VERSION 5.8 ;
BUSBITCHARS "[]" ;
DIVIDERCHAR "/" ;
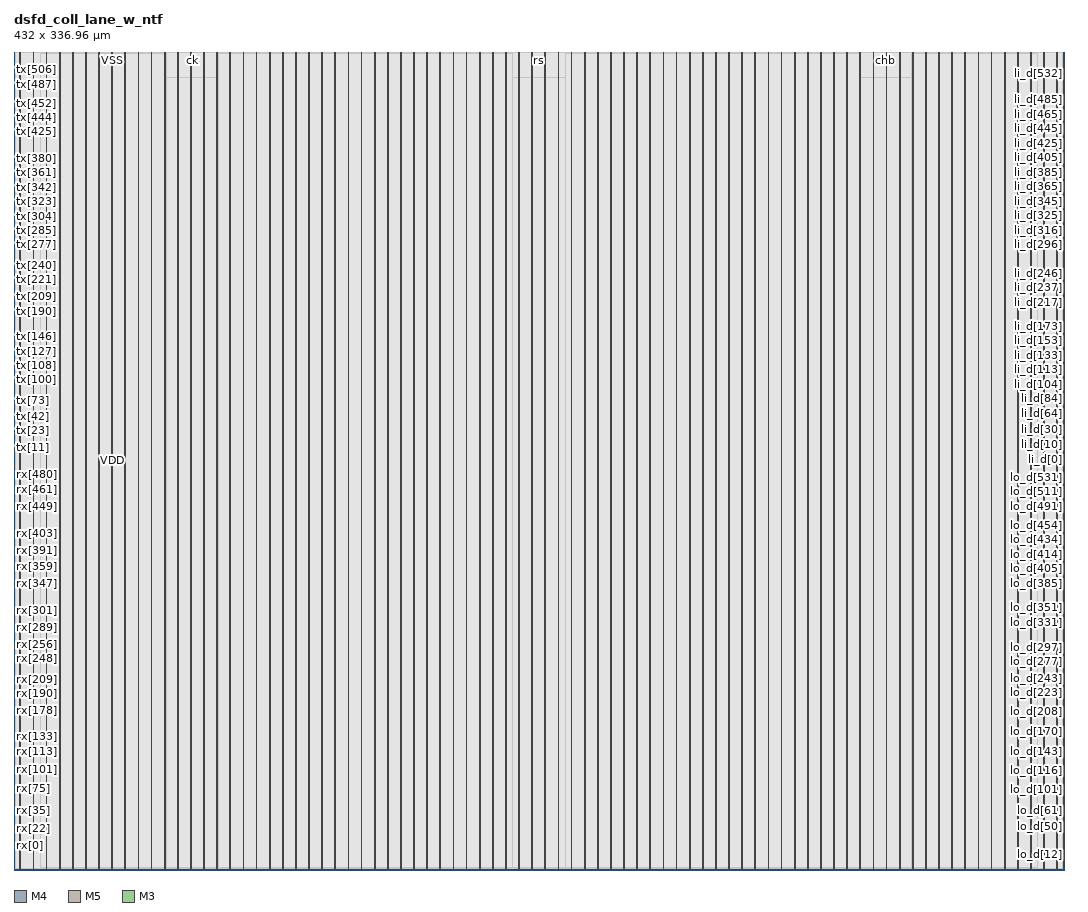
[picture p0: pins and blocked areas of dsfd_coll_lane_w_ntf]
MACRO dsfd_coll_lane_w_ntf
  CLASS BLOCK ;
  ORIGIN 0 0 ;
  FOREIGN dsfd_coll_lane_w_ntf 0 0 ;
  SIZE 432.0 BY 336.96 ;
  SYMMETRY X Y ;
  PIN rx[0]
    DIRECTION INPUT ;
    USE SIGNAL ;
    PORT
      LAYER M4 ;
        RECT 0.000 10.128 0.192 10.152 ;
    END
  END rx[0]
  PIN rx[1]
    DIRECTION INPUT ;
    USE SIGNAL ;
    PORT
      LAYER M4 ;
        RECT 0.000 10.464 0.192 10.488 ;
    END
  END rx[1]
  PIN rx[2]
    DIRECTION INPUT ;
    USE SIGNAL ;
    PORT
      LAYER M4 ;
        RECT 0.000 10.752 0.192 10.776 ;
    END
  END rx[2]
  PIN rx[3]
    DIRECTION INPUT ;
    USE SIGNAL ;
    PORT
      LAYER M4 ;
        RECT 0.000 11.088 0.192 11.112 ;
    END
  END rx[3]
  PIN rx[4]
    DIRECTION INPUT ;
    USE SIGNAL ;
    PORT
      LAYER M4 ;
        RECT 0.000 11.376 0.192 11.400 ;
    END
  END rx[4]
  PIN rx[5]
    DIRECTION INPUT ;
    USE SIGNAL ;
    PORT
      LAYER M4 ;
        RECT 0.000 11.712 0.192 11.736 ;
    END
  END rx[5]
  PIN rx[6]
    DIRECTION INPUT ;
    USE SIGNAL ;
    PORT
      LAYER M4 ;
        RECT 0.000 12.000 0.192 12.024 ;
    END
  END rx[6]
  PIN rx[7]
    DIRECTION INPUT ;
    USE SIGNAL ;
    PORT
      LAYER M4 ;
        RECT 0.000 12.336 0.192 12.360 ;
    END
  END rx[7]
  PIN rx[8]
    DIRECTION INPUT ;
    USE SIGNAL ;
    PORT
      LAYER M4 ;
        RECT 0.000 12.624 0.192 12.648 ;
    END
  END rx[8]
  PIN rx[9]
    DIRECTION INPUT ;
    USE SIGNAL ;
    PORT
      LAYER M4 ;
        RECT 0.000 12.960 0.192 12.984 ;
    END
  END rx[9]
  PIN rx[10]
    DIRECTION INPUT ;
    USE SIGNAL ;
    PORT
      LAYER M4 ;
        RECT 0.000 13.248 0.192 13.272 ;
    END
  END rx[10]
  PIN rx[11]
    DIRECTION INPUT ;
    USE SIGNAL ;
    PORT
      LAYER M4 ;
        RECT 0.000 13.584 0.192 13.608 ;
    END
  END rx[11]
  PIN rx[12]
    DIRECTION INPUT ;
    USE SIGNAL ;
    PORT
      LAYER M4 ;
        RECT 0.000 13.872 0.192 13.896 ;
    END
  END rx[12]
  PIN rx[13]
    DIRECTION INPUT ;
    USE SIGNAL ;
    PORT
      LAYER M4 ;
        RECT 0.000 14.160 0.192 14.184 ;
    END
  END rx[13]
  PIN rx[14]
    DIRECTION INPUT ;
    USE SIGNAL ;
    PORT
      LAYER M4 ;
        RECT 0.000 14.496 0.192 14.520 ;
    END
  END rx[14]
  PIN rx[15]
    DIRECTION INPUT ;
    USE SIGNAL ;
    PORT
      LAYER M4 ;
        RECT 0.000 14.784 0.192 14.808 ;
    END
  END rx[15]
  PIN rx[16]
    DIRECTION INPUT ;
    USE SIGNAL ;
    PORT
      LAYER M4 ;
        RECT 0.000 15.120 0.192 15.144 ;
    END
  END rx[16]
  PIN rx[17]
    DIRECTION INPUT ;
    USE SIGNAL ;
    PORT
      LAYER M4 ;
        RECT 0.000 15.408 0.192 15.432 ;
    END
  END rx[17]
  PIN rx[18]
    DIRECTION INPUT ;
    USE SIGNAL ;
    PORT
      LAYER M4 ;
        RECT 0.000 15.744 0.192 15.768 ;
    END
  END rx[18]
  PIN rx[19]
    DIRECTION INPUT ;
    USE SIGNAL ;
    PORT
      LAYER M4 ;
        RECT 0.000 16.032 0.192 16.056 ;
    END
  END rx[19]
  PIN rx[20]
    DIRECTION INPUT ;
    USE SIGNAL ;
    PORT
      LAYER M4 ;
        RECT 0.000 16.368 0.192 16.392 ;
    END
  END rx[20]
  PIN rx[21]
    DIRECTION INPUT ;
    USE SIGNAL ;
    PORT
      LAYER M4 ;
        RECT 0.000 16.656 0.192 16.680 ;
    END
  END rx[21]
  PIN rx[22]
    DIRECTION INPUT ;
    USE SIGNAL ;
    PORT
      LAYER M4 ;
        RECT 0.000 16.992 0.192 17.016 ;
    END
  END rx[22]
  PIN rx[23]
    DIRECTION INPUT ;
    USE SIGNAL ;
    PORT
      LAYER M4 ;
        RECT 0.000 17.280 0.192 17.304 ;
    END
  END rx[23]
  PIN rx[24]
    DIRECTION INPUT ;
    USE SIGNAL ;
    PORT
      LAYER M4 ;
        RECT 0.000 17.616 0.192 17.640 ;
    END
  END rx[24]
  PIN rx[25]
    DIRECTION INPUT ;
    USE SIGNAL ;
    PORT
      LAYER M4 ;
        RECT 0.000 17.904 0.192 17.928 ;
    END
  END rx[25]
  PIN rx[26]
    DIRECTION INPUT ;
    USE SIGNAL ;
    PORT
      LAYER M4 ;
        RECT 0.000 18.240 0.192 18.264 ;
    END
  END rx[26]
  PIN rx[27]
    DIRECTION INPUT ;
    USE SIGNAL ;
    PORT
      LAYER M4 ;
        RECT 0.000 18.528 0.192 18.552 ;
    END
  END rx[27]
  PIN rx[28]
    DIRECTION INPUT ;
    USE SIGNAL ;
    PORT
      LAYER M4 ;
        RECT 0.000 18.864 0.192 18.888 ;
    END
  END rx[28]
  PIN rx[29]
    DIRECTION INPUT ;
    USE SIGNAL ;
    PORT
      LAYER M4 ;
        RECT 0.000 19.152 0.192 19.176 ;
    END
  END rx[29]
  PIN rx[30]
    DIRECTION INPUT ;
    USE SIGNAL ;
    PORT
      LAYER M4 ;
        RECT 0.000 19.440 0.192 19.464 ;
    END
  END rx[30]
  PIN rx[31]
    DIRECTION INPUT ;
    USE SIGNAL ;
    PORT
      LAYER M4 ;
        RECT 0.000 19.776 0.192 19.800 ;
    END
  END rx[31]
  PIN rx[32]
    DIRECTION INPUT ;
    USE SIGNAL ;
    PORT
      LAYER M4 ;
        RECT 0.000 20.064 0.192 20.088 ;
    END
  END rx[32]
  PIN rx[33]
    DIRECTION INPUT ;
    USE SIGNAL ;
    PORT
      LAYER M4 ;
        RECT 0.000 20.400 0.192 20.424 ;
    END
  END rx[33]
  PIN rx[34]
    DIRECTION INPUT ;
    USE SIGNAL ;
    PORT
      LAYER M4 ;
        RECT 0.000 20.688 0.192 20.712 ;
    END
  END rx[34]
  PIN rx[35]
    DIRECTION INPUT ;
    USE SIGNAL ;
    PORT
      LAYER M4 ;
        RECT 0.000 21.024 0.192 21.048 ;
    END
  END rx[35]
  PIN rx[36]
    DIRECTION INPUT ;
    USE SIGNAL ;
    PORT
      LAYER M4 ;
        RECT 0.000 21.312 0.192 21.336 ;
    END
  END rx[36]
  PIN rx[37]
    DIRECTION INPUT ;
    USE SIGNAL ;
    PORT
      LAYER M4 ;
        RECT 0.000 21.648 0.192 21.672 ;
    END
  END rx[37]
  PIN rx[38]
    DIRECTION INPUT ;
    USE SIGNAL ;
    PORT
      LAYER M4 ;
        RECT 0.000 21.936 0.192 21.960 ;
    END
  END rx[38]
  PIN rx[39]
    DIRECTION INPUT ;
    USE SIGNAL ;
    PORT
      LAYER M4 ;
        RECT 0.000 22.272 0.192 22.296 ;
    END
  END rx[39]
  PIN rx[40]
    DIRECTION INPUT ;
    USE SIGNAL ;
    PORT
      LAYER M4 ;
        RECT 0.000 22.560 0.192 22.584 ;
    END
  END rx[40]
  PIN rx[41]
    DIRECTION INPUT ;
    USE SIGNAL ;
    PORT
      LAYER M4 ;
        RECT 0.000 22.896 0.192 22.920 ;
    END
  END rx[41]
  PIN rx[42]
    DIRECTION INPUT ;
    USE SIGNAL ;
    PORT
      LAYER M4 ;
        RECT 0.000 23.184 0.192 23.208 ;
    END
  END rx[42]
  PIN rx[43]
    DIRECTION INPUT ;
    USE SIGNAL ;
    PORT
      LAYER M4 ;
        RECT 0.000 23.520 0.192 23.544 ;
    END
  END rx[43]
  PIN rx[44]
    DIRECTION INPUT ;
    USE SIGNAL ;
    PORT
      LAYER M4 ;
        RECT 0.000 23.808 0.192 23.832 ;
    END
  END rx[44]
  PIN rx[45]
    DIRECTION INPUT ;
    USE SIGNAL ;
    PORT
      LAYER M4 ;
        RECT 0.000 24.144 0.192 24.168 ;
    END
  END rx[45]
  PIN rx[46]
    DIRECTION INPUT ;
    USE SIGNAL ;
    PORT
      LAYER M4 ;
        RECT 0.000 24.432 0.192 24.456 ;
    END
  END rx[46]
  PIN rx[47]
    DIRECTION INPUT ;
    USE SIGNAL ;
    PORT
      LAYER M4 ;
        RECT 0.000 24.768 0.192 24.792 ;
    END
  END rx[47]
  PIN rx[48]
    DIRECTION INPUT ;
    USE SIGNAL ;
    PORT
      LAYER M4 ;
        RECT 0.000 25.056 0.192 25.080 ;
    END
  END rx[48]
  PIN rx[49]
    DIRECTION INPUT ;
    USE SIGNAL ;
    PORT
      LAYER M4 ;
        RECT 0.000 25.344 0.192 25.368 ;
    END
  END rx[49]
  PIN rx[50]
    DIRECTION INPUT ;
    USE SIGNAL ;
    PORT
      LAYER M4 ;
        RECT 0.000 25.680 0.192 25.704 ;
    END
  END rx[50]
  PIN rx[51]
    DIRECTION INPUT ;
    USE SIGNAL ;
    PORT
      LAYER M4 ;
        RECT 0.000 25.968 0.192 25.992 ;
    END
  END rx[51]
  PIN rx[52]
    DIRECTION INPUT ;
    USE SIGNAL ;
    PORT
      LAYER M4 ;
        RECT 0.000 26.304 0.192 26.328 ;
    END
  END rx[52]
  PIN rx[53]
    DIRECTION INPUT ;
    USE SIGNAL ;
    PORT
      LAYER M4 ;
        RECT 0.000 26.592 0.192 26.616 ;
    END
  END rx[53]
  PIN rx[54]
    DIRECTION INPUT ;
    USE SIGNAL ;
    PORT
      LAYER M4 ;
        RECT 0.000 26.928 0.192 26.952 ;
    END
  END rx[54]
  PIN rx[55]
    DIRECTION INPUT ;
    USE SIGNAL ;
    PORT
      LAYER M4 ;
        RECT 0.000 27.216 0.192 27.240 ;
    END
  END rx[55]
  PIN rx[56]
    DIRECTION INPUT ;
    USE SIGNAL ;
    PORT
      LAYER M4 ;
        RECT 0.000 27.552 0.192 27.576 ;
    END
  END rx[56]
  PIN rx[57]
    DIRECTION INPUT ;
    USE SIGNAL ;
    PORT
      LAYER M4 ;
        RECT 0.000 27.840 0.192 27.864 ;
    END
  END rx[57]
  PIN rx[58]
    DIRECTION INPUT ;
    USE SIGNAL ;
    PORT
      LAYER M4 ;
        RECT 0.000 28.176 0.192 28.200 ;
    END
  END rx[58]
  PIN rx[59]
    DIRECTION INPUT ;
    USE SIGNAL ;
    PORT
      LAYER M4 ;
        RECT 0.000 28.464 0.192 28.488 ;
    END
  END rx[59]
  PIN rx[60]
    DIRECTION INPUT ;
    USE SIGNAL ;
    PORT
      LAYER M4 ;
        RECT 0.000 28.800 0.192 28.824 ;
    END
  END rx[60]
  PIN rx[61]
    DIRECTION INPUT ;
    USE SIGNAL ;
    PORT
      LAYER M4 ;
        RECT 0.000 29.088 0.192 29.112 ;
    END
  END rx[61]
  PIN rx[62]
    DIRECTION INPUT ;
    USE SIGNAL ;
    PORT
      LAYER M4 ;
        RECT 0.000 29.424 0.192 29.448 ;
    END
  END rx[62]
  PIN rx[63]
    DIRECTION INPUT ;
    USE SIGNAL ;
    PORT
      LAYER M4 ;
        RECT 0.000 29.712 0.192 29.736 ;
    END
  END rx[63]
  PIN rx[64]
    DIRECTION INPUT ;
    USE SIGNAL ;
    PORT
      LAYER M4 ;
        RECT 0.000 30.048 0.192 30.072 ;
    END
  END rx[64]
  PIN rx[65]
    DIRECTION INPUT ;
    USE SIGNAL ;
    PORT
      LAYER M4 ;
        RECT 0.000 30.336 0.192 30.360 ;
    END
  END rx[65]
  PIN rx[66]
    DIRECTION INPUT ;
    USE SIGNAL ;
    PORT
      LAYER M4 ;
        RECT 0.000 30.672 0.192 30.696 ;
    END
  END rx[66]
  PIN rx[67]
    DIRECTION INPUT ;
    USE SIGNAL ;
    PORT
      LAYER M4 ;
        RECT 0.000 30.960 0.192 30.984 ;
    END
  END rx[67]
  PIN rx[68]
    DIRECTION INPUT ;
    USE SIGNAL ;
    PORT
      LAYER M4 ;
        RECT 0.000 31.248 0.192 31.272 ;
    END
  END rx[68]
  PIN rx[69]
    DIRECTION INPUT ;
    USE SIGNAL ;
    PORT
      LAYER M4 ;
        RECT 0.000 31.584 0.192 31.608 ;
    END
  END rx[69]
  PIN rx[70]
    DIRECTION INPUT ;
    USE SIGNAL ;
    PORT
      LAYER M4 ;
        RECT 0.000 31.872 0.192 31.896 ;
    END
  END rx[70]
  PIN rx[71]
    DIRECTION INPUT ;
    USE SIGNAL ;
    PORT
      LAYER M4 ;
        RECT 0.000 32.208 0.192 32.232 ;
    END
  END rx[71]
  PIN rx[72]
    DIRECTION INPUT ;
    USE SIGNAL ;
    PORT
      LAYER M4 ;
        RECT 0.000 32.496 0.192 32.520 ;
    END
  END rx[72]
  PIN rx[73]
    DIRECTION INPUT ;
    USE SIGNAL ;
    PORT
      LAYER M4 ;
        RECT 0.000 32.832 0.192 32.856 ;
    END
  END rx[73]
  PIN rx[74]
    DIRECTION INPUT ;
    USE SIGNAL ;
    PORT
      LAYER M4 ;
        RECT 0.000 33.120 0.192 33.144 ;
    END
  END rx[74]
  PIN rx[75]
    DIRECTION INPUT ;
    USE SIGNAL ;
    PORT
      LAYER M4 ;
        RECT 0.000 33.456 0.192 33.480 ;
    END
  END rx[75]
  PIN rx[76]
    DIRECTION INPUT ;
    USE SIGNAL ;
    PORT
      LAYER M4 ;
        RECT 0.000 33.744 0.192 33.768 ;
    END
  END rx[76]
  PIN rx[77]
    DIRECTION INPUT ;
    USE SIGNAL ;
    PORT
      LAYER M4 ;
        RECT 0.000 34.080 0.192 34.104 ;
    END
  END rx[77]
  PIN rx[78]
    DIRECTION INPUT ;
    USE SIGNAL ;
    PORT
      LAYER M4 ;
        RECT 0.000 34.368 0.192 34.392 ;
    END
  END rx[78]
  PIN rx[79]
    DIRECTION INPUT ;
    USE SIGNAL ;
    PORT
      LAYER M4 ;
        RECT 0.000 34.704 0.192 34.728 ;
    END
  END rx[79]
  PIN rx[80]
    DIRECTION INPUT ;
    USE SIGNAL ;
    PORT
      LAYER M4 ;
        RECT 0.000 34.992 0.192 35.016 ;
    END
  END rx[80]
  PIN rx[81]
    DIRECTION INPUT ;
    USE SIGNAL ;
    PORT
      LAYER M4 ;
        RECT 0.000 35.328 0.192 35.352 ;
    END
  END rx[81]
  PIN rx[82]
    DIRECTION INPUT ;
    USE SIGNAL ;
    PORT
      LAYER M4 ;
        RECT 0.000 35.616 0.192 35.640 ;
    END
  END rx[82]
  PIN rx[83]
    DIRECTION INPUT ;
    USE SIGNAL ;
    PORT
      LAYER M4 ;
        RECT 0.000 35.952 0.192 35.976 ;
    END
  END rx[83]
  PIN rx[84]
    DIRECTION INPUT ;
    USE SIGNAL ;
    PORT
      LAYER M4 ;
        RECT 0.000 36.240 0.192 36.264 ;
    END
  END rx[84]
  PIN rx[85]
    DIRECTION INPUT ;
    USE SIGNAL ;
    PORT
      LAYER M4 ;
        RECT 0.000 36.528 0.192 36.552 ;
    END
  END rx[85]
  PIN rx[86]
    DIRECTION INPUT ;
    USE SIGNAL ;
    PORT
      LAYER M4 ;
        RECT 0.000 36.864 0.192 36.888 ;
    END
  END rx[86]
  PIN rx[87]
    DIRECTION INPUT ;
    USE SIGNAL ;
    PORT
      LAYER M4 ;
        RECT 0.000 37.152 0.192 37.176 ;
    END
  END rx[87]
  PIN rx[88]
    DIRECTION INPUT ;
    USE SIGNAL ;
    PORT
      LAYER M4 ;
        RECT 0.000 37.488 0.192 37.512 ;
    END
  END rx[88]
  PIN rx[89]
    DIRECTION INPUT ;
    USE SIGNAL ;
    PORT
      LAYER M4 ;
        RECT 0.000 37.776 0.192 37.800 ;
    END
  END rx[89]
  PIN rx[90]
    DIRECTION INPUT ;
    USE SIGNAL ;
    PORT
      LAYER M4 ;
        RECT 0.000 38.112 0.192 38.136 ;
    END
  END rx[90]
  PIN rx[91]
    DIRECTION INPUT ;
    USE SIGNAL ;
    PORT
      LAYER M4 ;
        RECT 0.000 38.400 0.192 38.424 ;
    END
  END rx[91]
  PIN rx[92]
    DIRECTION INPUT ;
    USE SIGNAL ;
    PORT
      LAYER M4 ;
        RECT 0.000 38.736 0.192 38.760 ;
    END
  END rx[92]
  PIN rx[93]
    DIRECTION INPUT ;
    USE SIGNAL ;
    PORT
      LAYER M4 ;
        RECT 0.000 39.024 0.192 39.048 ;
    END
  END rx[93]
  PIN rx[94]
    DIRECTION INPUT ;
    USE SIGNAL ;
    PORT
      LAYER M4 ;
        RECT 0.000 39.360 0.192 39.384 ;
    END
  END rx[94]
  PIN rx[95]
    DIRECTION INPUT ;
    USE SIGNAL ;
    PORT
      LAYER M4 ;
        RECT 0.000 39.648 0.192 39.672 ;
    END
  END rx[95]
  PIN rx[96]
    DIRECTION INPUT ;
    USE SIGNAL ;
    PORT
      LAYER M4 ;
        RECT 0.000 39.984 0.192 40.008 ;
    END
  END rx[96]
  PIN rx[97]
    DIRECTION INPUT ;
    USE SIGNAL ;
    PORT
      LAYER M4 ;
        RECT 0.000 40.272 0.192 40.296 ;
    END
  END rx[97]
  PIN rx[98]
    DIRECTION INPUT ;
    USE SIGNAL ;
    PORT
      LAYER M4 ;
        RECT 0.000 40.608 0.192 40.632 ;
    END
  END rx[98]
  PIN rx[99]
    DIRECTION INPUT ;
    USE SIGNAL ;
    PORT
      LAYER M4 ;
        RECT 0.000 40.896 0.192 40.920 ;
    END
  END rx[99]
  PIN rx[100]
    DIRECTION INPUT ;
    USE SIGNAL ;
    PORT
      LAYER M4 ;
        RECT 0.000 41.232 0.192 41.256 ;
    END
  END rx[100]
  PIN rx[101]
    DIRECTION INPUT ;
    USE SIGNAL ;
    PORT
      LAYER M4 ;
        RECT 0.000 41.520 0.192 41.544 ;
    END
  END rx[101]
  PIN rx[102]
    DIRECTION INPUT ;
    USE SIGNAL ;
    PORT
      LAYER M4 ;
        RECT 0.000 41.856 0.192 41.880 ;
    END
  END rx[102]
  PIN rx[103]
    DIRECTION INPUT ;
    USE SIGNAL ;
    PORT
      LAYER M4 ;
        RECT 0.000 42.144 0.192 42.168 ;
    END
  END rx[103]
  PIN rx[104]
    DIRECTION INPUT ;
    USE SIGNAL ;
    PORT
      LAYER M4 ;
        RECT 0.000 42.432 0.192 42.456 ;
    END
  END rx[104]
  PIN rx[105]
    DIRECTION INPUT ;
    USE SIGNAL ;
    PORT
      LAYER M4 ;
        RECT 0.000 42.768 0.192 42.792 ;
    END
  END rx[105]
  PIN rx[106]
    DIRECTION INPUT ;
    USE SIGNAL ;
    PORT
      LAYER M4 ;
        RECT 0.000 43.056 0.192 43.080 ;
    END
  END rx[106]
  PIN rx[107]
    DIRECTION INPUT ;
    USE SIGNAL ;
    PORT
      LAYER M4 ;
        RECT 0.000 43.392 0.192 43.416 ;
    END
  END rx[107]
  PIN rx[108]
    DIRECTION INPUT ;
    USE SIGNAL ;
    PORT
      LAYER M4 ;
        RECT 0.000 43.680 0.192 43.704 ;
    END
  END rx[108]
  PIN rx[109]
    DIRECTION INPUT ;
    USE SIGNAL ;
    PORT
      LAYER M4 ;
        RECT 0.000 44.016 0.192 44.040 ;
    END
  END rx[109]
  PIN rx[110]
    DIRECTION INPUT ;
    USE SIGNAL ;
    PORT
      LAYER M4 ;
        RECT 0.000 44.304 0.192 44.328 ;
    END
  END rx[110]
  PIN rx[111]
    DIRECTION INPUT ;
    USE SIGNAL ;
    PORT
      LAYER M4 ;
        RECT 0.000 44.640 0.192 44.664 ;
    END
  END rx[111]
  PIN rx[112]
    DIRECTION INPUT ;
    USE SIGNAL ;
    PORT
      LAYER M4 ;
        RECT 0.000 44.928 0.192 44.952 ;
    END
  END rx[112]
  PIN rx[113]
    DIRECTION INPUT ;
    USE SIGNAL ;
    PORT
      LAYER M4 ;
        RECT 0.000 45.264 0.192 45.288 ;
    END
  END rx[113]
  PIN rx[114]
    DIRECTION INPUT ;
    USE SIGNAL ;
    PORT
      LAYER M4 ;
        RECT 0.000 45.552 0.192 45.576 ;
    END
  END rx[114]
  PIN rx[115]
    DIRECTION INPUT ;
    USE SIGNAL ;
    PORT
      LAYER M4 ;
        RECT 0.000 45.888 0.192 45.912 ;
    END
  END rx[115]
  PIN rx[116]
    DIRECTION INPUT ;
    USE SIGNAL ;
    PORT
      LAYER M4 ;
        RECT 0.000 46.176 0.192 46.200 ;
    END
  END rx[116]
  PIN rx[117]
    DIRECTION INPUT ;
    USE SIGNAL ;
    PORT
      LAYER M4 ;
        RECT 0.000 46.512 0.192 46.536 ;
    END
  END rx[117]
  PIN rx[118]
    DIRECTION INPUT ;
    USE SIGNAL ;
    PORT
      LAYER M4 ;
        RECT 0.000 46.800 0.192 46.824 ;
    END
  END rx[118]
  PIN rx[119]
    DIRECTION INPUT ;
    USE SIGNAL ;
    PORT
      LAYER M4 ;
        RECT 0.000 47.136 0.192 47.160 ;
    END
  END rx[119]
  PIN rx[120]
    DIRECTION INPUT ;
    USE SIGNAL ;
    PORT
      LAYER M4 ;
        RECT 0.000 47.424 0.192 47.448 ;
    END
  END rx[120]
  PIN rx[121]
    DIRECTION INPUT ;
    USE SIGNAL ;
    PORT
      LAYER M4 ;
        RECT 0.000 47.712 0.192 47.736 ;
    END
  END rx[121]
  PIN rx[122]
    DIRECTION INPUT ;
    USE SIGNAL ;
    PORT
      LAYER M4 ;
        RECT 0.000 48.048 0.192 48.072 ;
    END
  END rx[122]
  PIN rx[123]
    DIRECTION INPUT ;
    USE SIGNAL ;
    PORT
      LAYER M4 ;
        RECT 0.000 48.336 0.192 48.360 ;
    END
  END rx[123]
  PIN rx[124]
    DIRECTION INPUT ;
    USE SIGNAL ;
    PORT
      LAYER M4 ;
        RECT 0.000 48.672 0.192 48.696 ;
    END
  END rx[124]
  PIN rx[125]
    DIRECTION INPUT ;
    USE SIGNAL ;
    PORT
      LAYER M4 ;
        RECT 0.000 48.960 0.192 48.984 ;
    END
  END rx[125]
  PIN rx[126]
    DIRECTION INPUT ;
    USE SIGNAL ;
    PORT
      LAYER M4 ;
        RECT 0.000 49.296 0.192 49.320 ;
    END
  END rx[126]
  PIN rx[127]
    DIRECTION INPUT ;
    USE SIGNAL ;
    PORT
      LAYER M4 ;
        RECT 0.000 49.584 0.192 49.608 ;
    END
  END rx[127]
  PIN rx[128]
    DIRECTION INPUT ;
    USE SIGNAL ;
    PORT
      LAYER M4 ;
        RECT 0.000 49.920 0.192 49.944 ;
    END
  END rx[128]
  PIN rx[129]
    DIRECTION INPUT ;
    USE SIGNAL ;
    PORT
      LAYER M4 ;
        RECT 0.000 50.208 0.192 50.232 ;
    END
  END rx[129]
  PIN rx[130]
    DIRECTION INPUT ;
    USE SIGNAL ;
    PORT
      LAYER M4 ;
        RECT 0.000 50.544 0.192 50.568 ;
    END
  END rx[130]
  PIN rx[131]
    DIRECTION INPUT ;
    USE SIGNAL ;
    PORT
      LAYER M4 ;
        RECT 0.000 50.832 0.192 50.856 ;
    END
  END rx[131]
  PIN rx[132]
    DIRECTION INPUT ;
    USE SIGNAL ;
    PORT
      LAYER M4 ;
        RECT 0.000 51.168 0.192 51.192 ;
    END
  END rx[132]
  PIN rx[133]
    DIRECTION INPUT ;
    USE SIGNAL ;
    PORT
      LAYER M4 ;
        RECT 0.000 51.456 0.192 51.480 ;
    END
  END rx[133]
  PIN rx[134]
    DIRECTION INPUT ;
    USE SIGNAL ;
    PORT
      LAYER M4 ;
        RECT 0.000 51.792 0.192 51.816 ;
    END
  END rx[134]
  PIN rx[135]
    DIRECTION INPUT ;
    USE SIGNAL ;
    PORT
      LAYER M4 ;
        RECT 0.000 52.080 0.192 52.104 ;
    END
  END rx[135]
  PIN rx[136]
    DIRECTION INPUT ;
    USE SIGNAL ;
    PORT
      LAYER M4 ;
        RECT 0.000 52.416 0.192 52.440 ;
    END
  END rx[136]
  PIN rx[137]
    DIRECTION INPUT ;
    USE SIGNAL ;
    PORT
      LAYER M4 ;
        RECT 0.000 52.704 0.192 52.728 ;
    END
  END rx[137]
  PIN rx[138]
    DIRECTION INPUT ;
    USE SIGNAL ;
    PORT
      LAYER M4 ;
        RECT 0.000 53.040 0.192 53.064 ;
    END
  END rx[138]
  PIN rx[139]
    DIRECTION INPUT ;
    USE SIGNAL ;
    PORT
      LAYER M4 ;
        RECT 0.000 53.328 0.192 53.352 ;
    END
  END rx[139]
  PIN rx[140]
    DIRECTION INPUT ;
    USE SIGNAL ;
    PORT
      LAYER M4 ;
        RECT 0.000 53.616 0.192 53.640 ;
    END
  END rx[140]
  PIN rx[141]
    DIRECTION INPUT ;
    USE SIGNAL ;
    PORT
      LAYER M4 ;
        RECT 0.000 53.952 0.192 53.976 ;
    END
  END rx[141]
  PIN rx[142]
    DIRECTION INPUT ;
    USE SIGNAL ;
    PORT
      LAYER M4 ;
        RECT 0.000 54.240 0.192 54.264 ;
    END
  END rx[142]
  PIN rx[143]
    DIRECTION INPUT ;
    USE SIGNAL ;
    PORT
      LAYER M4 ;
        RECT 0.000 54.576 0.192 54.600 ;
    END
  END rx[143]
  PIN rx[144]
    DIRECTION INPUT ;
    USE SIGNAL ;
    PORT
      LAYER M4 ;
        RECT 0.000 54.864 0.192 54.888 ;
    END
  END rx[144]
  PIN rx[145]
    DIRECTION INPUT ;
    USE SIGNAL ;
    PORT
      LAYER M4 ;
        RECT 0.000 55.200 0.192 55.224 ;
    END
  END rx[145]
  PIN rx[146]
    DIRECTION INPUT ;
    USE SIGNAL ;
    PORT
      LAYER M4 ;
        RECT 0.000 55.488 0.192 55.512 ;
    END
  END rx[146]
  PIN rx[147]
    DIRECTION INPUT ;
    USE SIGNAL ;
    PORT
      LAYER M4 ;
        RECT 0.000 55.824 0.192 55.848 ;
    END
  END rx[147]
  PIN rx[148]
    DIRECTION INPUT ;
    USE SIGNAL ;
    PORT
      LAYER M4 ;
        RECT 0.000 56.112 0.192 56.136 ;
    END
  END rx[148]
  PIN rx[149]
    DIRECTION INPUT ;
    USE SIGNAL ;
    PORT
      LAYER M4 ;
        RECT 0.000 56.448 0.192 56.472 ;
    END
  END rx[149]
  PIN rx[150]
    DIRECTION INPUT ;
    USE SIGNAL ;
    PORT
      LAYER M4 ;
        RECT 0.000 56.736 0.192 56.760 ;
    END
  END rx[150]
  PIN rx[151]
    DIRECTION INPUT ;
    USE SIGNAL ;
    PORT
      LAYER M4 ;
        RECT 0.000 57.072 0.192 57.096 ;
    END
  END rx[151]
  PIN rx[152]
    DIRECTION INPUT ;
    USE SIGNAL ;
    PORT
      LAYER M4 ;
        RECT 0.000 57.360 0.192 57.384 ;
    END
  END rx[152]
  PIN rx[153]
    DIRECTION INPUT ;
    USE SIGNAL ;
    PORT
      LAYER M4 ;
        RECT 0.000 57.696 0.192 57.720 ;
    END
  END rx[153]
  PIN rx[154]
    DIRECTION INPUT ;
    USE SIGNAL ;
    PORT
      LAYER M4 ;
        RECT 0.000 57.984 0.192 58.008 ;
    END
  END rx[154]
  PIN rx[155]
    DIRECTION INPUT ;
    USE SIGNAL ;
    PORT
      LAYER M4 ;
        RECT 0.000 58.320 0.192 58.344 ;
    END
  END rx[155]
  PIN rx[156]
    DIRECTION INPUT ;
    USE SIGNAL ;
    PORT
      LAYER M4 ;
        RECT 0.000 58.608 0.192 58.632 ;
    END
  END rx[156]
  PIN rx[157]
    DIRECTION INPUT ;
    USE SIGNAL ;
    PORT
      LAYER M4 ;
        RECT 0.000 58.944 0.192 58.968 ;
    END
  END rx[157]
  PIN rx[158]
    DIRECTION INPUT ;
    USE SIGNAL ;
    PORT
      LAYER M4 ;
        RECT 0.000 59.232 0.192 59.256 ;
    END
  END rx[158]
  PIN rx[159]
    DIRECTION INPUT ;
    USE SIGNAL ;
    PORT
      LAYER M4 ;
        RECT 0.000 59.520 0.192 59.544 ;
    END
  END rx[159]
  PIN rx[160]
    DIRECTION INPUT ;
    USE SIGNAL ;
    PORT
      LAYER M4 ;
        RECT 0.000 59.856 0.192 59.880 ;
    END
  END rx[160]
  PIN rx[161]
    DIRECTION INPUT ;
    USE SIGNAL ;
    PORT
      LAYER M4 ;
        RECT 0.000 60.144 0.192 60.168 ;
    END
  END rx[161]
  PIN rx[162]
    DIRECTION INPUT ;
    USE SIGNAL ;
    PORT
      LAYER M4 ;
        RECT 0.000 60.480 0.192 60.504 ;
    END
  END rx[162]
  PIN rx[163]
    DIRECTION INPUT ;
    USE SIGNAL ;
    PORT
      LAYER M4 ;
        RECT 0.000 60.768 0.192 60.792 ;
    END
  END rx[163]
  PIN rx[164]
    DIRECTION INPUT ;
    USE SIGNAL ;
    PORT
      LAYER M4 ;
        RECT 0.000 61.104 0.192 61.128 ;
    END
  END rx[164]
  PIN rx[165]
    DIRECTION INPUT ;
    USE SIGNAL ;
    PORT
      LAYER M4 ;
        RECT 0.000 61.392 0.192 61.416 ;
    END
  END rx[165]
  PIN rx[166]
    DIRECTION INPUT ;
    USE SIGNAL ;
    PORT
      LAYER M4 ;
        RECT 0.000 61.728 0.192 61.752 ;
    END
  END rx[166]
  PIN rx[167]
    DIRECTION INPUT ;
    USE SIGNAL ;
    PORT
      LAYER M4 ;
        RECT 0.000 62.016 0.192 62.040 ;
    END
  END rx[167]
  PIN rx[168]
    DIRECTION INPUT ;
    USE SIGNAL ;
    PORT
      LAYER M4 ;
        RECT 0.000 62.352 0.192 62.376 ;
    END
  END rx[168]
  PIN rx[169]
    DIRECTION INPUT ;
    USE SIGNAL ;
    PORT
      LAYER M4 ;
        RECT 0.000 62.640 0.192 62.664 ;
    END
  END rx[169]
  PIN rx[170]
    DIRECTION INPUT ;
    USE SIGNAL ;
    PORT
      LAYER M4 ;
        RECT 0.000 62.976 0.192 63.000 ;
    END
  END rx[170]
  PIN rx[171]
    DIRECTION INPUT ;
    USE SIGNAL ;
    PORT
      LAYER M4 ;
        RECT 0.000 63.264 0.192 63.288 ;
    END
  END rx[171]
  PIN rx[172]
    DIRECTION INPUT ;
    USE SIGNAL ;
    PORT
      LAYER M4 ;
        RECT 0.000 63.600 0.192 63.624 ;
    END
  END rx[172]
  PIN rx[173]
    DIRECTION INPUT ;
    USE SIGNAL ;
    PORT
      LAYER M4 ;
        RECT 0.000 63.888 0.192 63.912 ;
    END
  END rx[173]
  PIN rx[174]
    DIRECTION INPUT ;
    USE SIGNAL ;
    PORT
      LAYER M4 ;
        RECT 0.000 64.224 0.192 64.248 ;
    END
  END rx[174]
  PIN rx[175]
    DIRECTION INPUT ;
    USE SIGNAL ;
    PORT
      LAYER M4 ;
        RECT 0.000 64.512 0.192 64.536 ;
    END
  END rx[175]
  PIN rx[176]
    DIRECTION INPUT ;
    USE SIGNAL ;
    PORT
      LAYER M4 ;
        RECT 0.000 64.800 0.192 64.824 ;
    END
  END rx[176]
  PIN rx[177]
    DIRECTION INPUT ;
    USE SIGNAL ;
    PORT
      LAYER M4 ;
        RECT 0.000 65.136 0.192 65.160 ;
    END
  END rx[177]
  PIN rx[178]
    DIRECTION INPUT ;
    USE SIGNAL ;
    PORT
      LAYER M4 ;
        RECT 0.000 65.424 0.192 65.448 ;
    END
  END rx[178]
  PIN rx[179]
    DIRECTION INPUT ;
    USE SIGNAL ;
    PORT
      LAYER M4 ;
        RECT 0.000 65.760 0.192 65.784 ;
    END
  END rx[179]
  PIN rx[180]
    DIRECTION INPUT ;
    USE SIGNAL ;
    PORT
      LAYER M4 ;
        RECT 0.000 66.048 0.192 66.072 ;
    END
  END rx[180]
  PIN rx[181]
    DIRECTION INPUT ;
    USE SIGNAL ;
    PORT
      LAYER M4 ;
        RECT 0.000 66.384 0.192 66.408 ;
    END
  END rx[181]
  PIN rx[182]
    DIRECTION INPUT ;
    USE SIGNAL ;
    PORT
      LAYER M4 ;
        RECT 0.000 66.672 0.192 66.696 ;
    END
  END rx[182]
  PIN rx[183]
    DIRECTION INPUT ;
    USE SIGNAL ;
    PORT
      LAYER M4 ;
        RECT 0.000 67.008 0.192 67.032 ;
    END
  END rx[183]
  PIN rx[184]
    DIRECTION INPUT ;
    USE SIGNAL ;
    PORT
      LAYER M4 ;
        RECT 0.000 67.296 0.192 67.320 ;
    END
  END rx[184]
  PIN rx[185]
    DIRECTION INPUT ;
    USE SIGNAL ;
    PORT
      LAYER M4 ;
        RECT 0.000 67.632 0.192 67.656 ;
    END
  END rx[185]
  PIN rx[186]
    DIRECTION INPUT ;
    USE SIGNAL ;
    PORT
      LAYER M4 ;
        RECT 0.000 67.920 0.192 67.944 ;
    END
  END rx[186]
  PIN rx[187]
    DIRECTION INPUT ;
    USE SIGNAL ;
    PORT
      LAYER M4 ;
        RECT 0.000 68.256 0.192 68.280 ;
    END
  END rx[187]
  PIN rx[188]
    DIRECTION INPUT ;
    USE SIGNAL ;
    PORT
      LAYER M4 ;
        RECT 0.000 68.544 0.192 68.568 ;
    END
  END rx[188]
  PIN rx[189]
    DIRECTION INPUT ;
    USE SIGNAL ;
    PORT
      LAYER M4 ;
        RECT 0.000 68.880 0.192 68.904 ;
    END
  END rx[189]
  PIN rx[190]
    DIRECTION INPUT ;
    USE SIGNAL ;
    PORT
      LAYER M4 ;
        RECT 0.000 69.168 0.192 69.192 ;
    END
  END rx[190]
  PIN rx[191]
    DIRECTION INPUT ;
    USE SIGNAL ;
    PORT
      LAYER M4 ;
        RECT 0.000 69.504 0.192 69.528 ;
    END
  END rx[191]
  PIN rx[192]
    DIRECTION INPUT ;
    USE SIGNAL ;
    PORT
      LAYER M4 ;
        RECT 0.000 69.792 0.192 69.816 ;
    END
  END rx[192]
  PIN rx[193]
    DIRECTION INPUT ;
    USE SIGNAL ;
    PORT
      LAYER M4 ;
        RECT 0.000 70.128 0.192 70.152 ;
    END
  END rx[193]
  PIN rx[194]
    DIRECTION INPUT ;
    USE SIGNAL ;
    PORT
      LAYER M4 ;
        RECT 0.000 70.416 0.192 70.440 ;
    END
  END rx[194]
  PIN rx[195]
    DIRECTION INPUT ;
    USE SIGNAL ;
    PORT
      LAYER M4 ;
        RECT 0.000 70.704 0.192 70.728 ;
    END
  END rx[195]
  PIN rx[196]
    DIRECTION INPUT ;
    USE SIGNAL ;
    PORT
      LAYER M4 ;
        RECT 0.000 71.040 0.192 71.064 ;
    END
  END rx[196]
  PIN rx[197]
    DIRECTION INPUT ;
    USE SIGNAL ;
    PORT
      LAYER M4 ;
        RECT 0.000 71.328 0.192 71.352 ;
    END
  END rx[197]
  PIN rx[198]
    DIRECTION INPUT ;
    USE SIGNAL ;
    PORT
      LAYER M4 ;
        RECT 0.000 71.664 0.192 71.688 ;
    END
  END rx[198]
  PIN rx[199]
    DIRECTION INPUT ;
    USE SIGNAL ;
    PORT
      LAYER M4 ;
        RECT 0.000 71.952 0.192 71.976 ;
    END
  END rx[199]
  PIN rx[200]
    DIRECTION INPUT ;
    USE SIGNAL ;
    PORT
      LAYER M4 ;
        RECT 0.000 72.288 0.192 72.312 ;
    END
  END rx[200]
  PIN rx[201]
    DIRECTION INPUT ;
    USE SIGNAL ;
    PORT
      LAYER M4 ;
        RECT 0.000 72.576 0.192 72.600 ;
    END
  END rx[201]
  PIN rx[202]
    DIRECTION INPUT ;
    USE SIGNAL ;
    PORT
      LAYER M4 ;
        RECT 0.000 72.912 0.192 72.936 ;
    END
  END rx[202]
  PIN rx[203]
    DIRECTION INPUT ;
    USE SIGNAL ;
    PORT
      LAYER M4 ;
        RECT 0.000 73.200 0.192 73.224 ;
    END
  END rx[203]
  PIN rx[204]
    DIRECTION INPUT ;
    USE SIGNAL ;
    PORT
      LAYER M4 ;
        RECT 0.000 73.536 0.192 73.560 ;
    END
  END rx[204]
  PIN rx[205]
    DIRECTION INPUT ;
    USE SIGNAL ;
    PORT
      LAYER M4 ;
        RECT 0.000 73.824 0.192 73.848 ;
    END
  END rx[205]
  PIN rx[206]
    DIRECTION INPUT ;
    USE SIGNAL ;
    PORT
      LAYER M4 ;
        RECT 0.000 74.160 0.192 74.184 ;
    END
  END rx[206]
  PIN rx[207]
    DIRECTION INPUT ;
    USE SIGNAL ;
    PORT
      LAYER M4 ;
        RECT 0.000 74.448 0.192 74.472 ;
    END
  END rx[207]
  PIN rx[208]
    DIRECTION INPUT ;
    USE SIGNAL ;
    PORT
      LAYER M4 ;
        RECT 0.000 74.784 0.192 74.808 ;
    END
  END rx[208]
  PIN rx[209]
    DIRECTION INPUT ;
    USE SIGNAL ;
    PORT
      LAYER M4 ;
        RECT 0.000 75.072 0.192 75.096 ;
    END
  END rx[209]
  PIN rx[210]
    DIRECTION INPUT ;
    USE SIGNAL ;
    PORT
      LAYER M4 ;
        RECT 0.000 75.408 0.192 75.432 ;
    END
  END rx[210]
  PIN rx[211]
    DIRECTION INPUT ;
    USE SIGNAL ;
    PORT
      LAYER M4 ;
        RECT 0.000 75.696 0.192 75.720 ;
    END
  END rx[211]
  PIN rx[212]
    DIRECTION INPUT ;
    USE SIGNAL ;
    PORT
      LAYER M4 ;
        RECT 0.000 75.984 0.192 76.008 ;
    END
  END rx[212]
  PIN rx[213]
    DIRECTION INPUT ;
    USE SIGNAL ;
    PORT
      LAYER M4 ;
        RECT 0.000 76.320 0.192 76.344 ;
    END
  END rx[213]
  PIN rx[214]
    DIRECTION INPUT ;
    USE SIGNAL ;
    PORT
      LAYER M4 ;
        RECT 0.000 76.608 0.192 76.632 ;
    END
  END rx[214]
  PIN rx[215]
    DIRECTION INPUT ;
    USE SIGNAL ;
    PORT
      LAYER M4 ;
        RECT 0.000 76.944 0.192 76.968 ;
    END
  END rx[215]
  PIN rx[216]
    DIRECTION INPUT ;
    USE SIGNAL ;
    PORT
      LAYER M4 ;
        RECT 0.000 77.232 0.192 77.256 ;
    END
  END rx[216]
  PIN rx[217]
    DIRECTION INPUT ;
    USE SIGNAL ;
    PORT
      LAYER M4 ;
        RECT 0.000 77.568 0.192 77.592 ;
    END
  END rx[217]
  PIN rx[218]
    DIRECTION INPUT ;
    USE SIGNAL ;
    PORT
      LAYER M4 ;
        RECT 0.000 77.856 0.192 77.880 ;
    END
  END rx[218]
  PIN rx[219]
    DIRECTION INPUT ;
    USE SIGNAL ;
    PORT
      LAYER M4 ;
        RECT 0.000 78.192 0.192 78.216 ;
    END
  END rx[219]
  PIN rx[220]
    DIRECTION INPUT ;
    USE SIGNAL ;
    PORT
      LAYER M4 ;
        RECT 0.000 78.480 0.192 78.504 ;
    END
  END rx[220]
  PIN rx[221]
    DIRECTION INPUT ;
    USE SIGNAL ;
    PORT
      LAYER M4 ;
        RECT 0.000 78.816 0.192 78.840 ;
    END
  END rx[221]
  PIN rx[222]
    DIRECTION INPUT ;
    USE SIGNAL ;
    PORT
      LAYER M4 ;
        RECT 0.000 79.104 0.192 79.128 ;
    END
  END rx[222]
  PIN rx[223]
    DIRECTION INPUT ;
    USE SIGNAL ;
    PORT
      LAYER M4 ;
        RECT 0.000 79.440 0.192 79.464 ;
    END
  END rx[223]
  PIN rx[224]
    DIRECTION INPUT ;
    USE SIGNAL ;
    PORT
      LAYER M4 ;
        RECT 0.000 79.728 0.192 79.752 ;
    END
  END rx[224]
  PIN rx[225]
    DIRECTION INPUT ;
    USE SIGNAL ;
    PORT
      LAYER M4 ;
        RECT 0.000 80.064 0.192 80.088 ;
    END
  END rx[225]
  PIN rx[226]
    DIRECTION INPUT ;
    USE SIGNAL ;
    PORT
      LAYER M4 ;
        RECT 0.000 80.352 0.192 80.376 ;
    END
  END rx[226]
  PIN rx[227]
    DIRECTION INPUT ;
    USE SIGNAL ;
    PORT
      LAYER M4 ;
        RECT 0.000 80.688 0.192 80.712 ;
    END
  END rx[227]
  PIN rx[228]
    DIRECTION INPUT ;
    USE SIGNAL ;
    PORT
      LAYER M4 ;
        RECT 0.000 80.976 0.192 81.000 ;
    END
  END rx[228]
  PIN rx[229]
    DIRECTION INPUT ;
    USE SIGNAL ;
    PORT
      LAYER M4 ;
        RECT 0.000 81.312 0.192 81.336 ;
    END
  END rx[229]
  PIN rx[230]
    DIRECTION INPUT ;
    USE SIGNAL ;
    PORT
      LAYER M4 ;
        RECT 0.000 81.600 0.192 81.624 ;
    END
  END rx[230]
  PIN rx[231]
    DIRECTION INPUT ;
    USE SIGNAL ;
    PORT
      LAYER M4 ;
        RECT 0.000 81.888 0.192 81.912 ;
    END
  END rx[231]
  PIN rx[232]
    DIRECTION INPUT ;
    USE SIGNAL ;
    PORT
      LAYER M4 ;
        RECT 0.000 82.224 0.192 82.248 ;
    END
  END rx[232]
  PIN rx[233]
    DIRECTION INPUT ;
    USE SIGNAL ;
    PORT
      LAYER M4 ;
        RECT 0.000 82.512 0.192 82.536 ;
    END
  END rx[233]
  PIN rx[234]
    DIRECTION INPUT ;
    USE SIGNAL ;
    PORT
      LAYER M4 ;
        RECT 0.000 82.848 0.192 82.872 ;
    END
  END rx[234]
  PIN rx[235]
    DIRECTION INPUT ;
    USE SIGNAL ;
    PORT
      LAYER M4 ;
        RECT 0.000 83.136 0.192 83.160 ;
    END
  END rx[235]
  PIN rx[236]
    DIRECTION INPUT ;
    USE SIGNAL ;
    PORT
      LAYER M4 ;
        RECT 0.000 83.472 0.192 83.496 ;
    END
  END rx[236]
  PIN rx[237]
    DIRECTION INPUT ;
    USE SIGNAL ;
    PORT
      LAYER M4 ;
        RECT 0.000 83.760 0.192 83.784 ;
    END
  END rx[237]
  PIN rx[238]
    DIRECTION INPUT ;
    USE SIGNAL ;
    PORT
      LAYER M4 ;
        RECT 0.000 84.096 0.192 84.120 ;
    END
  END rx[238]
  PIN rx[239]
    DIRECTION INPUT ;
    USE SIGNAL ;
    PORT
      LAYER M4 ;
        RECT 0.000 84.384 0.192 84.408 ;
    END
  END rx[239]
  PIN rx[240]
    DIRECTION INPUT ;
    USE SIGNAL ;
    PORT
      LAYER M4 ;
        RECT 0.000 84.720 0.192 84.744 ;
    END
  END rx[240]
  PIN rx[241]
    DIRECTION INPUT ;
    USE SIGNAL ;
    PORT
      LAYER M4 ;
        RECT 0.000 85.008 0.192 85.032 ;
    END
  END rx[241]
  PIN rx[242]
    DIRECTION INPUT ;
    USE SIGNAL ;
    PORT
      LAYER M4 ;
        RECT 0.000 85.344 0.192 85.368 ;
    END
  END rx[242]
  PIN rx[243]
    DIRECTION INPUT ;
    USE SIGNAL ;
    PORT
      LAYER M4 ;
        RECT 0.000 85.632 0.192 85.656 ;
    END
  END rx[243]
  PIN rx[244]
    DIRECTION INPUT ;
    USE SIGNAL ;
    PORT
      LAYER M4 ;
        RECT 0.000 85.968 0.192 85.992 ;
    END
  END rx[244]
  PIN rx[245]
    DIRECTION INPUT ;
    USE SIGNAL ;
    PORT
      LAYER M4 ;
        RECT 0.000 86.256 0.192 86.280 ;
    END
  END rx[245]
  PIN rx[246]
    DIRECTION INPUT ;
    USE SIGNAL ;
    PORT
      LAYER M4 ;
        RECT 0.000 86.592 0.192 86.616 ;
    END
  END rx[246]
  PIN rx[247]
    DIRECTION INPUT ;
    USE SIGNAL ;
    PORT
      LAYER M4 ;
        RECT 0.000 86.880 0.192 86.904 ;
    END
  END rx[247]
  PIN rx[248]
    DIRECTION INPUT ;
    USE SIGNAL ;
    PORT
      LAYER M4 ;
        RECT 0.000 87.168 0.192 87.192 ;
    END
  END rx[248]
  PIN rx[249]
    DIRECTION INPUT ;
    USE SIGNAL ;
    PORT
      LAYER M4 ;
        RECT 0.000 87.504 0.192 87.528 ;
    END
  END rx[249]
  PIN rx[250]
    DIRECTION INPUT ;
    USE SIGNAL ;
    PORT
      LAYER M4 ;
        RECT 0.000 87.792 0.192 87.816 ;
    END
  END rx[250]
  PIN rx[251]
    DIRECTION INPUT ;
    USE SIGNAL ;
    PORT
      LAYER M4 ;
        RECT 0.000 88.128 0.192 88.152 ;
    END
  END rx[251]
  PIN rx[252]
    DIRECTION INPUT ;
    USE SIGNAL ;
    PORT
      LAYER M4 ;
        RECT 0.000 88.416 0.192 88.440 ;
    END
  END rx[252]
  PIN rx[253]
    DIRECTION INPUT ;
    USE SIGNAL ;
    PORT
      LAYER M4 ;
        RECT 0.000 88.752 0.192 88.776 ;
    END
  END rx[253]
  PIN rx[254]
    DIRECTION INPUT ;
    USE SIGNAL ;
    PORT
      LAYER M4 ;
        RECT 0.000 89.040 0.192 89.064 ;
    END
  END rx[254]
  PIN rx[255]
    DIRECTION INPUT ;
    USE SIGNAL ;
    PORT
      LAYER M4 ;
        RECT 0.000 89.376 0.192 89.400 ;
    END
  END rx[255]
  PIN rx[256]
    DIRECTION INPUT ;
    USE SIGNAL ;
    PORT
      LAYER M4 ;
        RECT 0.000 89.664 0.192 89.688 ;
    END
  END rx[256]
  PIN rx[257]
    DIRECTION INPUT ;
    USE SIGNAL ;
    PORT
      LAYER M4 ;
        RECT 0.000 90.000 0.192 90.024 ;
    END
  END rx[257]
  PIN rx[258]
    DIRECTION INPUT ;
    USE SIGNAL ;
    PORT
      LAYER M4 ;
        RECT 0.000 90.288 0.192 90.312 ;
    END
  END rx[258]
  PIN rx[259]
    DIRECTION INPUT ;
    USE SIGNAL ;
    PORT
      LAYER M4 ;
        RECT 0.000 90.624 0.192 90.648 ;
    END
  END rx[259]
  PIN rx[260]
    DIRECTION INPUT ;
    USE SIGNAL ;
    PORT
      LAYER M4 ;
        RECT 0.000 90.912 0.192 90.936 ;
    END
  END rx[260]
  PIN rx[261]
    DIRECTION INPUT ;
    USE SIGNAL ;
    PORT
      LAYER M4 ;
        RECT 0.000 91.248 0.192 91.272 ;
    END
  END rx[261]
  PIN rx[262]
    DIRECTION INPUT ;
    USE SIGNAL ;
    PORT
      LAYER M4 ;
        RECT 0.000 91.536 0.192 91.560 ;
    END
  END rx[262]
  PIN rx[263]
    DIRECTION INPUT ;
    USE SIGNAL ;
    PORT
      LAYER M4 ;
        RECT 0.000 91.872 0.192 91.896 ;
    END
  END rx[263]
  PIN rx[264]
    DIRECTION INPUT ;
    USE SIGNAL ;
    PORT
      LAYER M4 ;
        RECT 0.000 92.160 0.192 92.184 ;
    END
  END rx[264]
  PIN rx[265]
    DIRECTION INPUT ;
    USE SIGNAL ;
    PORT
      LAYER M4 ;
        RECT 0.000 92.496 0.192 92.520 ;
    END
  END rx[265]
  PIN rx[266]
    DIRECTION INPUT ;
    USE SIGNAL ;
    PORT
      LAYER M4 ;
        RECT 0.000 92.784 0.192 92.808 ;
    END
  END rx[266]
  PIN rx[267]
    DIRECTION INPUT ;
    USE SIGNAL ;
    PORT
      LAYER M4 ;
        RECT 0.000 93.072 0.192 93.096 ;
    END
  END rx[267]
  PIN rx[268]
    DIRECTION INPUT ;
    USE SIGNAL ;
    PORT
      LAYER M4 ;
        RECT 0.000 93.408 0.192 93.432 ;
    END
  END rx[268]
  PIN rx[269]
    DIRECTION INPUT ;
    USE SIGNAL ;
    PORT
      LAYER M4 ;
        RECT 0.000 93.696 0.192 93.720 ;
    END
  END rx[269]
  PIN rx[270]
    DIRECTION INPUT ;
    USE SIGNAL ;
    PORT
      LAYER M4 ;
        RECT 0.000 94.032 0.192 94.056 ;
    END
  END rx[270]
  PIN rx[271]
    DIRECTION INPUT ;
    USE SIGNAL ;
    PORT
      LAYER M4 ;
        RECT 0.000 94.320 0.192 94.344 ;
    END
  END rx[271]
  PIN rx[272]
    DIRECTION INPUT ;
    USE SIGNAL ;
    PORT
      LAYER M4 ;
        RECT 0.000 94.656 0.192 94.680 ;
    END
  END rx[272]
  PIN rx[273]
    DIRECTION INPUT ;
    USE SIGNAL ;
    PORT
      LAYER M4 ;
        RECT 0.000 94.944 0.192 94.968 ;
    END
  END rx[273]
  PIN rx[274]
    DIRECTION INPUT ;
    USE SIGNAL ;
    PORT
      LAYER M4 ;
        RECT 0.000 95.280 0.192 95.304 ;
    END
  END rx[274]
  PIN rx[275]
    DIRECTION INPUT ;
    USE SIGNAL ;
    PORT
      LAYER M4 ;
        RECT 0.000 95.568 0.192 95.592 ;
    END
  END rx[275]
  PIN rx[276]
    DIRECTION INPUT ;
    USE SIGNAL ;
    PORT
      LAYER M4 ;
        RECT 0.000 95.904 0.192 95.928 ;
    END
  END rx[276]
  PIN rx[277]
    DIRECTION INPUT ;
    USE SIGNAL ;
    PORT
      LAYER M4 ;
        RECT 0.000 96.192 0.192 96.216 ;
    END
  END rx[277]
  PIN rx[278]
    DIRECTION INPUT ;
    USE SIGNAL ;
    PORT
      LAYER M4 ;
        RECT 0.000 96.528 0.192 96.552 ;
    END
  END rx[278]
  PIN rx[279]
    DIRECTION INPUT ;
    USE SIGNAL ;
    PORT
      LAYER M4 ;
        RECT 0.000 96.816 0.192 96.840 ;
    END
  END rx[279]
  PIN rx[280]
    DIRECTION INPUT ;
    USE SIGNAL ;
    PORT
      LAYER M4 ;
        RECT 0.000 97.152 0.192 97.176 ;
    END
  END rx[280]
  PIN rx[281]
    DIRECTION INPUT ;
    USE SIGNAL ;
    PORT
      LAYER M4 ;
        RECT 0.000 97.440 0.192 97.464 ;
    END
  END rx[281]
  PIN rx[282]
    DIRECTION INPUT ;
    USE SIGNAL ;
    PORT
      LAYER M4 ;
        RECT 0.000 97.776 0.192 97.800 ;
    END
  END rx[282]
  PIN rx[283]
    DIRECTION INPUT ;
    USE SIGNAL ;
    PORT
      LAYER M4 ;
        RECT 0.000 98.064 0.192 98.088 ;
    END
  END rx[283]
  PIN rx[284]
    DIRECTION INPUT ;
    USE SIGNAL ;
    PORT
      LAYER M4 ;
        RECT 0.000 98.400 0.192 98.424 ;
    END
  END rx[284]
  PIN rx[285]
    DIRECTION INPUT ;
    USE SIGNAL ;
    PORT
      LAYER M4 ;
        RECT 0.000 98.688 0.192 98.712 ;
    END
  END rx[285]
  PIN rx[286]
    DIRECTION INPUT ;
    USE SIGNAL ;
    PORT
      LAYER M4 ;
        RECT 0.000 98.976 0.192 99.000 ;
    END
  END rx[286]
  PIN rx[287]
    DIRECTION INPUT ;
    USE SIGNAL ;
    PORT
      LAYER M4 ;
        RECT 0.000 99.312 0.192 99.336 ;
    END
  END rx[287]
  PIN rx[288]
    DIRECTION INPUT ;
    USE SIGNAL ;
    PORT
      LAYER M4 ;
        RECT 0.000 99.600 0.192 99.624 ;
    END
  END rx[288]
  PIN rx[289]
    DIRECTION INPUT ;
    USE SIGNAL ;
    PORT
      LAYER M4 ;
        RECT 0.000 99.936 0.192 99.960 ;
    END
  END rx[289]
  PIN rx[290]
    DIRECTION INPUT ;
    USE SIGNAL ;
    PORT
      LAYER M4 ;
        RECT 0.000 100.224 0.192 100.248 ;
    END
  END rx[290]
  PIN rx[291]
    DIRECTION INPUT ;
    USE SIGNAL ;
    PORT
      LAYER M4 ;
        RECT 0.000 100.560 0.192 100.584 ;
    END
  END rx[291]
  PIN rx[292]
    DIRECTION INPUT ;
    USE SIGNAL ;
    PORT
      LAYER M4 ;
        RECT 0.000 100.848 0.192 100.872 ;
    END
  END rx[292]
  PIN rx[293]
    DIRECTION INPUT ;
    USE SIGNAL ;
    PORT
      LAYER M4 ;
        RECT 0.000 101.184 0.192 101.208 ;
    END
  END rx[293]
  PIN rx[294]
    DIRECTION INPUT ;
    USE SIGNAL ;
    PORT
      LAYER M4 ;
        RECT 0.000 101.472 0.192 101.496 ;
    END
  END rx[294]
  PIN rx[295]
    DIRECTION INPUT ;
    USE SIGNAL ;
    PORT
      LAYER M4 ;
        RECT 0.000 101.808 0.192 101.832 ;
    END
  END rx[295]
  PIN rx[296]
    DIRECTION INPUT ;
    USE SIGNAL ;
    PORT
      LAYER M4 ;
        RECT 0.000 102.096 0.192 102.120 ;
    END
  END rx[296]
  PIN rx[297]
    DIRECTION INPUT ;
    USE SIGNAL ;
    PORT
      LAYER M4 ;
        RECT 0.000 102.432 0.192 102.456 ;
    END
  END rx[297]
  PIN rx[298]
    DIRECTION INPUT ;
    USE SIGNAL ;
    PORT
      LAYER M4 ;
        RECT 0.000 102.720 0.192 102.744 ;
    END
  END rx[298]
  PIN rx[299]
    DIRECTION INPUT ;
    USE SIGNAL ;
    PORT
      LAYER M4 ;
        RECT 0.000 103.056 0.192 103.080 ;
    END
  END rx[299]
  PIN rx[300]
    DIRECTION INPUT ;
    USE SIGNAL ;
    PORT
      LAYER M4 ;
        RECT 0.000 103.344 0.192 103.368 ;
    END
  END rx[300]
  PIN rx[301]
    DIRECTION INPUT ;
    USE SIGNAL ;
    PORT
      LAYER M4 ;
        RECT 0.000 103.680 0.192 103.704 ;
    END
  END rx[301]
  PIN rx[302]
    DIRECTION INPUT ;
    USE SIGNAL ;
    PORT
      LAYER M4 ;
        RECT 0.000 103.968 0.192 103.992 ;
    END
  END rx[302]
  PIN rx[303]
    DIRECTION INPUT ;
    USE SIGNAL ;
    PORT
      LAYER M4 ;
        RECT 0.000 104.256 0.192 104.280 ;
    END
  END rx[303]
  PIN rx[304]
    DIRECTION INPUT ;
    USE SIGNAL ;
    PORT
      LAYER M4 ;
        RECT 0.000 104.592 0.192 104.616 ;
    END
  END rx[304]
  PIN rx[305]
    DIRECTION INPUT ;
    USE SIGNAL ;
    PORT
      LAYER M4 ;
        RECT 0.000 104.880 0.192 104.904 ;
    END
  END rx[305]
  PIN rx[306]
    DIRECTION INPUT ;
    USE SIGNAL ;
    PORT
      LAYER M4 ;
        RECT 0.000 105.216 0.192 105.240 ;
    END
  END rx[306]
  PIN rx[307]
    DIRECTION INPUT ;
    USE SIGNAL ;
    PORT
      LAYER M4 ;
        RECT 0.000 105.504 0.192 105.528 ;
    END
  END rx[307]
  PIN rx[308]
    DIRECTION INPUT ;
    USE SIGNAL ;
    PORT
      LAYER M4 ;
        RECT 0.000 105.840 0.192 105.864 ;
    END
  END rx[308]
  PIN rx[309]
    DIRECTION INPUT ;
    USE SIGNAL ;
    PORT
      LAYER M4 ;
        RECT 0.000 106.128 0.192 106.152 ;
    END
  END rx[309]
  PIN rx[310]
    DIRECTION INPUT ;
    USE SIGNAL ;
    PORT
      LAYER M4 ;
        RECT 0.000 106.464 0.192 106.488 ;
    END
  END rx[310]
  PIN rx[311]
    DIRECTION INPUT ;
    USE SIGNAL ;
    PORT
      LAYER M4 ;
        RECT 0.000 106.752 0.192 106.776 ;
    END
  END rx[311]
  PIN rx[312]
    DIRECTION INPUT ;
    USE SIGNAL ;
    PORT
      LAYER M4 ;
        RECT 0.000 107.088 0.192 107.112 ;
    END
  END rx[312]
  PIN rx[313]
    DIRECTION INPUT ;
    USE SIGNAL ;
    PORT
      LAYER M4 ;
        RECT 0.000 107.376 0.192 107.400 ;
    END
  END rx[313]
  PIN rx[314]
    DIRECTION INPUT ;
    USE SIGNAL ;
    PORT
      LAYER M4 ;
        RECT 0.000 107.712 0.192 107.736 ;
    END
  END rx[314]
  PIN rx[315]
    DIRECTION INPUT ;
    USE SIGNAL ;
    PORT
      LAYER M4 ;
        RECT 0.000 108.000 0.192 108.024 ;
    END
  END rx[315]
  PIN rx[316]
    DIRECTION INPUT ;
    USE SIGNAL ;
    PORT
      LAYER M4 ;
        RECT 0.000 108.336 0.192 108.360 ;
    END
  END rx[316]
  PIN rx[317]
    DIRECTION INPUT ;
    USE SIGNAL ;
    PORT
      LAYER M4 ;
        RECT 0.000 108.624 0.192 108.648 ;
    END
  END rx[317]
  PIN rx[318]
    DIRECTION INPUT ;
    USE SIGNAL ;
    PORT
      LAYER M4 ;
        RECT 0.000 108.960 0.192 108.984 ;
    END
  END rx[318]
  PIN rx[319]
    DIRECTION INPUT ;
    USE SIGNAL ;
    PORT
      LAYER M4 ;
        RECT 0.000 109.248 0.192 109.272 ;
    END
  END rx[319]
  PIN rx[320]
    DIRECTION INPUT ;
    USE SIGNAL ;
    PORT
      LAYER M4 ;
        RECT 0.000 109.584 0.192 109.608 ;
    END
  END rx[320]
  PIN rx[321]
    DIRECTION INPUT ;
    USE SIGNAL ;
    PORT
      LAYER M4 ;
        RECT 0.000 109.872 0.192 109.896 ;
    END
  END rx[321]
  PIN rx[322]
    DIRECTION INPUT ;
    USE SIGNAL ;
    PORT
      LAYER M4 ;
        RECT 0.000 110.160 0.192 110.184 ;
    END
  END rx[322]
  PIN rx[323]
    DIRECTION INPUT ;
    USE SIGNAL ;
    PORT
      LAYER M4 ;
        RECT 0.000 110.496 0.192 110.520 ;
    END
  END rx[323]
  PIN rx[324]
    DIRECTION INPUT ;
    USE SIGNAL ;
    PORT
      LAYER M4 ;
        RECT 0.000 110.784 0.192 110.808 ;
    END
  END rx[324]
  PIN rx[325]
    DIRECTION INPUT ;
    USE SIGNAL ;
    PORT
      LAYER M4 ;
        RECT 0.000 111.120 0.192 111.144 ;
    END
  END rx[325]
  PIN rx[326]
    DIRECTION INPUT ;
    USE SIGNAL ;
    PORT
      LAYER M4 ;
        RECT 0.000 111.408 0.192 111.432 ;
    END
  END rx[326]
  PIN rx[327]
    DIRECTION INPUT ;
    USE SIGNAL ;
    PORT
      LAYER M4 ;
        RECT 0.000 111.744 0.192 111.768 ;
    END
  END rx[327]
  PIN rx[328]
    DIRECTION INPUT ;
    USE SIGNAL ;
    PORT
      LAYER M4 ;
        RECT 0.000 112.032 0.192 112.056 ;
    END
  END rx[328]
  PIN rx[329]
    DIRECTION INPUT ;
    USE SIGNAL ;
    PORT
      LAYER M4 ;
        RECT 0.000 112.368 0.192 112.392 ;
    END
  END rx[329]
  PIN rx[330]
    DIRECTION INPUT ;
    USE SIGNAL ;
    PORT
      LAYER M4 ;
        RECT 0.000 112.656 0.192 112.680 ;
    END
  END rx[330]
  PIN rx[331]
    DIRECTION INPUT ;
    USE SIGNAL ;
    PORT
      LAYER M4 ;
        RECT 0.000 112.992 0.192 113.016 ;
    END
  END rx[331]
  PIN rx[332]
    DIRECTION INPUT ;
    USE SIGNAL ;
    PORT
      LAYER M4 ;
        RECT 0.000 113.280 0.192 113.304 ;
    END
  END rx[332]
  PIN rx[333]
    DIRECTION INPUT ;
    USE SIGNAL ;
    PORT
      LAYER M4 ;
        RECT 0.000 113.616 0.192 113.640 ;
    END
  END rx[333]
  PIN rx[334]
    DIRECTION INPUT ;
    USE SIGNAL ;
    PORT
      LAYER M4 ;
        RECT 0.000 113.904 0.192 113.928 ;
    END
  END rx[334]
  PIN rx[335]
    DIRECTION INPUT ;
    USE SIGNAL ;
    PORT
      LAYER M4 ;
        RECT 0.000 114.240 0.192 114.264 ;
    END
  END rx[335]
  PIN rx[336]
    DIRECTION INPUT ;
    USE SIGNAL ;
    PORT
      LAYER M4 ;
        RECT 0.000 114.528 0.192 114.552 ;
    END
  END rx[336]
  PIN rx[337]
    DIRECTION INPUT ;
    USE SIGNAL ;
    PORT
      LAYER M4 ;
        RECT 0.000 114.864 0.192 114.888 ;
    END
  END rx[337]
  PIN rx[338]
    DIRECTION INPUT ;
    USE SIGNAL ;
    PORT
      LAYER M4 ;
        RECT 0.000 115.152 0.192 115.176 ;
    END
  END rx[338]
  PIN rx[339]
    DIRECTION INPUT ;
    USE SIGNAL ;
    PORT
      LAYER M4 ;
        RECT 0.000 115.440 0.192 115.464 ;
    END
  END rx[339]
  PIN rx[340]
    DIRECTION INPUT ;
    USE SIGNAL ;
    PORT
      LAYER M4 ;
        RECT 0.000 115.776 0.192 115.800 ;
    END
  END rx[340]
  PIN rx[341]
    DIRECTION INPUT ;
    USE SIGNAL ;
    PORT
      LAYER M4 ;
        RECT 0.000 116.064 0.192 116.088 ;
    END
  END rx[341]
  PIN rx[342]
    DIRECTION INPUT ;
    USE SIGNAL ;
    PORT
      LAYER M4 ;
        RECT 0.000 116.400 0.192 116.424 ;
    END
  END rx[342]
  PIN rx[343]
    DIRECTION INPUT ;
    USE SIGNAL ;
    PORT
      LAYER M4 ;
        RECT 0.000 116.688 0.192 116.712 ;
    END
  END rx[343]
  PIN rx[344]
    DIRECTION INPUT ;
    USE SIGNAL ;
    PORT
      LAYER M4 ;
        RECT 0.000 117.024 0.192 117.048 ;
    END
  END rx[344]
  PIN rx[345]
    DIRECTION INPUT ;
    USE SIGNAL ;
    PORT
      LAYER M4 ;
        RECT 0.000 117.312 0.192 117.336 ;
    END
  END rx[345]
  PIN rx[346]
    DIRECTION INPUT ;
    USE SIGNAL ;
    PORT
      LAYER M4 ;
        RECT 0.000 117.648 0.192 117.672 ;
    END
  END rx[346]
  PIN rx[347]
    DIRECTION INPUT ;
    USE SIGNAL ;
    PORT
      LAYER M4 ;
        RECT 0.000 117.936 0.192 117.960 ;
    END
  END rx[347]
  PIN rx[348]
    DIRECTION INPUT ;
    USE SIGNAL ;
    PORT
      LAYER M4 ;
        RECT 0.000 118.272 0.192 118.296 ;
    END
  END rx[348]
  PIN rx[349]
    DIRECTION INPUT ;
    USE SIGNAL ;
    PORT
      LAYER M4 ;
        RECT 0.000 118.560 0.192 118.584 ;
    END
  END rx[349]
  PIN rx[350]
    DIRECTION INPUT ;
    USE SIGNAL ;
    PORT
      LAYER M4 ;
        RECT 0.000 118.896 0.192 118.920 ;
    END
  END rx[350]
  PIN rx[351]
    DIRECTION INPUT ;
    USE SIGNAL ;
    PORT
      LAYER M4 ;
        RECT 0.000 119.184 0.192 119.208 ;
    END
  END rx[351]
  PIN rx[352]
    DIRECTION INPUT ;
    USE SIGNAL ;
    PORT
      LAYER M4 ;
        RECT 0.000 119.520 0.192 119.544 ;
    END
  END rx[352]
  PIN rx[353]
    DIRECTION INPUT ;
    USE SIGNAL ;
    PORT
      LAYER M4 ;
        RECT 0.000 119.808 0.192 119.832 ;
    END
  END rx[353]
  PIN rx[354]
    DIRECTION INPUT ;
    USE SIGNAL ;
    PORT
      LAYER M4 ;
        RECT 0.000 120.144 0.192 120.168 ;
    END
  END rx[354]
  PIN rx[355]
    DIRECTION INPUT ;
    USE SIGNAL ;
    PORT
      LAYER M4 ;
        RECT 0.000 120.432 0.192 120.456 ;
    END
  END rx[355]
  PIN rx[356]
    DIRECTION INPUT ;
    USE SIGNAL ;
    PORT
      LAYER M4 ;
        RECT 0.000 120.768 0.192 120.792 ;
    END
  END rx[356]
  PIN rx[357]
    DIRECTION INPUT ;
    USE SIGNAL ;
    PORT
      LAYER M4 ;
        RECT 0.000 121.056 0.192 121.080 ;
    END
  END rx[357]
  PIN rx[358]
    DIRECTION INPUT ;
    USE SIGNAL ;
    PORT
      LAYER M4 ;
        RECT 0.000 121.344 0.192 121.368 ;
    END
  END rx[358]
  PIN rx[359]
    DIRECTION INPUT ;
    USE SIGNAL ;
    PORT
      LAYER M4 ;
        RECT 0.000 121.680 0.192 121.704 ;
    END
  END rx[359]
  PIN rx[360]
    DIRECTION INPUT ;
    USE SIGNAL ;
    PORT
      LAYER M4 ;
        RECT 0.000 121.968 0.192 121.992 ;
    END
  END rx[360]
  PIN rx[361]
    DIRECTION INPUT ;
    USE SIGNAL ;
    PORT
      LAYER M4 ;
        RECT 0.000 122.304 0.192 122.328 ;
    END
  END rx[361]
  PIN rx[362]
    DIRECTION INPUT ;
    USE SIGNAL ;
    PORT
      LAYER M4 ;
        RECT 0.000 122.592 0.192 122.616 ;
    END
  END rx[362]
  PIN rx[363]
    DIRECTION INPUT ;
    USE SIGNAL ;
    PORT
      LAYER M4 ;
        RECT 0.000 122.928 0.192 122.952 ;
    END
  END rx[363]
  PIN rx[364]
    DIRECTION INPUT ;
    USE SIGNAL ;
    PORT
      LAYER M4 ;
        RECT 0.000 123.216 0.192 123.240 ;
    END
  END rx[364]
  PIN rx[365]
    DIRECTION INPUT ;
    USE SIGNAL ;
    PORT
      LAYER M4 ;
        RECT 0.000 123.552 0.192 123.576 ;
    END
  END rx[365]
  PIN rx[366]
    DIRECTION INPUT ;
    USE SIGNAL ;
    PORT
      LAYER M4 ;
        RECT 0.000 123.840 0.192 123.864 ;
    END
  END rx[366]
  PIN rx[367]
    DIRECTION INPUT ;
    USE SIGNAL ;
    PORT
      LAYER M4 ;
        RECT 0.000 124.176 0.192 124.200 ;
    END
  END rx[367]
  PIN rx[368]
    DIRECTION INPUT ;
    USE SIGNAL ;
    PORT
      LAYER M4 ;
        RECT 0.000 124.464 0.192 124.488 ;
    END
  END rx[368]
  PIN rx[369]
    DIRECTION INPUT ;
    USE SIGNAL ;
    PORT
      LAYER M4 ;
        RECT 0.000 124.800 0.192 124.824 ;
    END
  END rx[369]
  PIN rx[370]
    DIRECTION INPUT ;
    USE SIGNAL ;
    PORT
      LAYER M4 ;
        RECT 0.000 125.088 0.192 125.112 ;
    END
  END rx[370]
  PIN rx[371]
    DIRECTION INPUT ;
    USE SIGNAL ;
    PORT
      LAYER M4 ;
        RECT 0.000 125.424 0.192 125.448 ;
    END
  END rx[371]
  PIN rx[372]
    DIRECTION INPUT ;
    USE SIGNAL ;
    PORT
      LAYER M4 ;
        RECT 0.000 125.712 0.192 125.736 ;
    END
  END rx[372]
  PIN rx[373]
    DIRECTION INPUT ;
    USE SIGNAL ;
    PORT
      LAYER M4 ;
        RECT 0.000 126.048 0.192 126.072 ;
    END
  END rx[373]
  PIN rx[374]
    DIRECTION INPUT ;
    USE SIGNAL ;
    PORT
      LAYER M4 ;
        RECT 0.000 126.336 0.192 126.360 ;
    END
  END rx[374]
  PIN rx[375]
    DIRECTION INPUT ;
    USE SIGNAL ;
    PORT
      LAYER M4 ;
        RECT 0.000 126.672 0.192 126.696 ;
    END
  END rx[375]
  PIN rx[376]
    DIRECTION INPUT ;
    USE SIGNAL ;
    PORT
      LAYER M4 ;
        RECT 0.000 126.960 0.192 126.984 ;
    END
  END rx[376]
  PIN rx[377]
    DIRECTION INPUT ;
    USE SIGNAL ;
    PORT
      LAYER M4 ;
        RECT 0.000 127.248 0.192 127.272 ;
    END
  END rx[377]
  PIN rx[378]
    DIRECTION INPUT ;
    USE SIGNAL ;
    PORT
      LAYER M4 ;
        RECT 0.000 127.584 0.192 127.608 ;
    END
  END rx[378]
  PIN rx[379]
    DIRECTION INPUT ;
    USE SIGNAL ;
    PORT
      LAYER M4 ;
        RECT 0.000 127.872 0.192 127.896 ;
    END
  END rx[379]
  PIN rx[380]
    DIRECTION INPUT ;
    USE SIGNAL ;
    PORT
      LAYER M4 ;
        RECT 0.000 128.208 0.192 128.232 ;
    END
  END rx[380]
  PIN rx[381]
    DIRECTION INPUT ;
    USE SIGNAL ;
    PORT
      LAYER M4 ;
        RECT 0.000 128.496 0.192 128.520 ;
    END
  END rx[381]
  PIN rx[382]
    DIRECTION INPUT ;
    USE SIGNAL ;
    PORT
      LAYER M4 ;
        RECT 0.000 128.832 0.192 128.856 ;
    END
  END rx[382]
  PIN rx[383]
    DIRECTION INPUT ;
    USE SIGNAL ;
    PORT
      LAYER M4 ;
        RECT 0.000 129.120 0.192 129.144 ;
    END
  END rx[383]
  PIN rx[384]
    DIRECTION INPUT ;
    USE SIGNAL ;
    PORT
      LAYER M4 ;
        RECT 0.000 129.456 0.192 129.480 ;
    END
  END rx[384]
  PIN rx[385]
    DIRECTION INPUT ;
    USE SIGNAL ;
    PORT
      LAYER M4 ;
        RECT 0.000 129.744 0.192 129.768 ;
    END
  END rx[385]
  PIN rx[386]
    DIRECTION INPUT ;
    USE SIGNAL ;
    PORT
      LAYER M4 ;
        RECT 0.000 130.080 0.192 130.104 ;
    END
  END rx[386]
  PIN rx[387]
    DIRECTION INPUT ;
    USE SIGNAL ;
    PORT
      LAYER M4 ;
        RECT 0.000 130.368 0.192 130.392 ;
    END
  END rx[387]
  PIN rx[388]
    DIRECTION INPUT ;
    USE SIGNAL ;
    PORT
      LAYER M4 ;
        RECT 0.000 130.704 0.192 130.728 ;
    END
  END rx[388]
  PIN rx[389]
    DIRECTION INPUT ;
    USE SIGNAL ;
    PORT
      LAYER M4 ;
        RECT 0.000 130.992 0.192 131.016 ;
    END
  END rx[389]
  PIN rx[390]
    DIRECTION INPUT ;
    USE SIGNAL ;
    PORT
      LAYER M4 ;
        RECT 0.000 131.328 0.192 131.352 ;
    END
  END rx[390]
  PIN rx[391]
    DIRECTION INPUT ;
    USE SIGNAL ;
    PORT
      LAYER M4 ;
        RECT 0.000 131.616 0.192 131.640 ;
    END
  END rx[391]
  PIN rx[392]
    DIRECTION INPUT ;
    USE SIGNAL ;
    PORT
      LAYER M4 ;
        RECT 0.000 131.952 0.192 131.976 ;
    END
  END rx[392]
  PIN rx[393]
    DIRECTION INPUT ;
    USE SIGNAL ;
    PORT
      LAYER M4 ;
        RECT 0.000 132.240 0.192 132.264 ;
    END
  END rx[393]
  PIN rx[394]
    DIRECTION INPUT ;
    USE SIGNAL ;
    PORT
      LAYER M4 ;
        RECT 0.000 132.528 0.192 132.552 ;
    END
  END rx[394]
  PIN rx[395]
    DIRECTION INPUT ;
    USE SIGNAL ;
    PORT
      LAYER M4 ;
        RECT 0.000 132.864 0.192 132.888 ;
    END
  END rx[395]
  PIN rx[396]
    DIRECTION INPUT ;
    USE SIGNAL ;
    PORT
      LAYER M4 ;
        RECT 0.000 133.152 0.192 133.176 ;
    END
  END rx[396]
  PIN rx[397]
    DIRECTION INPUT ;
    USE SIGNAL ;
    PORT
      LAYER M4 ;
        RECT 0.000 133.488 0.192 133.512 ;
    END
  END rx[397]
  PIN rx[398]
    DIRECTION INPUT ;
    USE SIGNAL ;
    PORT
      LAYER M4 ;
        RECT 0.000 133.776 0.192 133.800 ;
    END
  END rx[398]
  PIN rx[399]
    DIRECTION INPUT ;
    USE SIGNAL ;
    PORT
      LAYER M4 ;
        RECT 0.000 134.112 0.192 134.136 ;
    END
  END rx[399]
  PIN rx[400]
    DIRECTION INPUT ;
    USE SIGNAL ;
    PORT
      LAYER M4 ;
        RECT 0.000 134.400 0.192 134.424 ;
    END
  END rx[400]
  PIN rx[401]
    DIRECTION INPUT ;
    USE SIGNAL ;
    PORT
      LAYER M4 ;
        RECT 0.000 134.736 0.192 134.760 ;
    END
  END rx[401]
  PIN rx[402]
    DIRECTION INPUT ;
    USE SIGNAL ;
    PORT
      LAYER M4 ;
        RECT 0.000 135.024 0.192 135.048 ;
    END
  END rx[402]
  PIN rx[403]
    DIRECTION INPUT ;
    USE SIGNAL ;
    PORT
      LAYER M4 ;
        RECT 0.000 135.360 0.192 135.384 ;
    END
  END rx[403]
  PIN rx[404]
    DIRECTION INPUT ;
    USE SIGNAL ;
    PORT
      LAYER M4 ;
        RECT 0.000 135.648 0.192 135.672 ;
    END
  END rx[404]
  PIN rx[405]
    DIRECTION INPUT ;
    USE SIGNAL ;
    PORT
      LAYER M4 ;
        RECT 0.000 135.984 0.192 136.008 ;
    END
  END rx[405]
  PIN rx[406]
    DIRECTION INPUT ;
    USE SIGNAL ;
    PORT
      LAYER M4 ;
        RECT 0.000 136.272 0.192 136.296 ;
    END
  END rx[406]
  PIN rx[407]
    DIRECTION INPUT ;
    USE SIGNAL ;
    PORT
      LAYER M4 ;
        RECT 0.000 136.608 0.192 136.632 ;
    END
  END rx[407]
  PIN rx[408]
    DIRECTION INPUT ;
    USE SIGNAL ;
    PORT
      LAYER M4 ;
        RECT 0.000 136.896 0.192 136.920 ;
    END
  END rx[408]
  PIN rx[409]
    DIRECTION INPUT ;
    USE SIGNAL ;
    PORT
      LAYER M4 ;
        RECT 0.000 137.232 0.192 137.256 ;
    END
  END rx[409]
  PIN rx[410]
    DIRECTION INPUT ;
    USE SIGNAL ;
    PORT
      LAYER M4 ;
        RECT 0.000 137.520 0.192 137.544 ;
    END
  END rx[410]
  PIN rx[411]
    DIRECTION INPUT ;
    USE SIGNAL ;
    PORT
      LAYER M4 ;
        RECT 0.000 137.856 0.192 137.880 ;
    END
  END rx[411]
  PIN rx[412]
    DIRECTION INPUT ;
    USE SIGNAL ;
    PORT
      LAYER M4 ;
        RECT 0.000 138.144 0.192 138.168 ;
    END
  END rx[412]
  PIN rx[413]
    DIRECTION INPUT ;
    USE SIGNAL ;
    PORT
      LAYER M4 ;
        RECT 0.000 138.432 0.192 138.456 ;
    END
  END rx[413]
  PIN rx[414]
    DIRECTION INPUT ;
    USE SIGNAL ;
    PORT
      LAYER M4 ;
        RECT 0.000 138.768 0.192 138.792 ;
    END
  END rx[414]
  PIN rx[415]
    DIRECTION INPUT ;
    USE SIGNAL ;
    PORT
      LAYER M4 ;
        RECT 0.000 139.056 0.192 139.080 ;
    END
  END rx[415]
  PIN rx[416]
    DIRECTION INPUT ;
    USE SIGNAL ;
    PORT
      LAYER M4 ;
        RECT 0.000 139.392 0.192 139.416 ;
    END
  END rx[416]
  PIN rx[417]
    DIRECTION INPUT ;
    USE SIGNAL ;
    PORT
      LAYER M4 ;
        RECT 0.000 139.680 0.192 139.704 ;
    END
  END rx[417]
  PIN rx[418]
    DIRECTION INPUT ;
    USE SIGNAL ;
    PORT
      LAYER M4 ;
        RECT 0.000 140.016 0.192 140.040 ;
    END
  END rx[418]
  PIN rx[419]
    DIRECTION INPUT ;
    USE SIGNAL ;
    PORT
      LAYER M4 ;
        RECT 0.000 140.304 0.192 140.328 ;
    END
  END rx[419]
  PIN rx[420]
    DIRECTION INPUT ;
    USE SIGNAL ;
    PORT
      LAYER M4 ;
        RECT 0.000 140.640 0.192 140.664 ;
    END
  END rx[420]
  PIN rx[421]
    DIRECTION INPUT ;
    USE SIGNAL ;
    PORT
      LAYER M4 ;
        RECT 0.000 140.928 0.192 140.952 ;
    END
  END rx[421]
  PIN rx[422]
    DIRECTION INPUT ;
    USE SIGNAL ;
    PORT
      LAYER M4 ;
        RECT 0.000 141.264 0.192 141.288 ;
    END
  END rx[422]
  PIN rx[423]
    DIRECTION INPUT ;
    USE SIGNAL ;
    PORT
      LAYER M4 ;
        RECT 0.000 141.552 0.192 141.576 ;
    END
  END rx[423]
  PIN rx[424]
    DIRECTION INPUT ;
    USE SIGNAL ;
    PORT
      LAYER M4 ;
        RECT 0.000 141.888 0.192 141.912 ;
    END
  END rx[424]
  PIN rx[425]
    DIRECTION INPUT ;
    USE SIGNAL ;
    PORT
      LAYER M4 ;
        RECT 0.000 142.176 0.192 142.200 ;
    END
  END rx[425]
  PIN rx[426]
    DIRECTION INPUT ;
    USE SIGNAL ;
    PORT
      LAYER M4 ;
        RECT 0.000 142.512 0.192 142.536 ;
    END
  END rx[426]
  PIN rx[427]
    DIRECTION INPUT ;
    USE SIGNAL ;
    PORT
      LAYER M4 ;
        RECT 0.000 142.800 0.192 142.824 ;
    END
  END rx[427]
  PIN rx[428]
    DIRECTION INPUT ;
    USE SIGNAL ;
    PORT
      LAYER M4 ;
        RECT 0.000 143.136 0.192 143.160 ;
    END
  END rx[428]
  PIN rx[429]
    DIRECTION INPUT ;
    USE SIGNAL ;
    PORT
      LAYER M4 ;
        RECT 0.000 143.424 0.192 143.448 ;
    END
  END rx[429]
  PIN rx[430]
    DIRECTION INPUT ;
    USE SIGNAL ;
    PORT
      LAYER M4 ;
        RECT 0.000 143.712 0.192 143.736 ;
    END
  END rx[430]
  PIN rx[431]
    DIRECTION INPUT ;
    USE SIGNAL ;
    PORT
      LAYER M4 ;
        RECT 0.000 144.048 0.192 144.072 ;
    END
  END rx[431]
  PIN rx[432]
    DIRECTION INPUT ;
    USE SIGNAL ;
    PORT
      LAYER M4 ;
        RECT 0.000 144.336 0.192 144.360 ;
    END
  END rx[432]
  PIN rx[433]
    DIRECTION INPUT ;
    USE SIGNAL ;
    PORT
      LAYER M4 ;
        RECT 0.000 144.672 0.192 144.696 ;
    END
  END rx[433]
  PIN rx[434]
    DIRECTION INPUT ;
    USE SIGNAL ;
    PORT
      LAYER M4 ;
        RECT 0.000 144.960 0.192 144.984 ;
    END
  END rx[434]
  PIN rx[435]
    DIRECTION INPUT ;
    USE SIGNAL ;
    PORT
      LAYER M4 ;
        RECT 0.000 145.296 0.192 145.320 ;
    END
  END rx[435]
  PIN rx[436]
    DIRECTION INPUT ;
    USE SIGNAL ;
    PORT
      LAYER M4 ;
        RECT 0.000 145.584 0.192 145.608 ;
    END
  END rx[436]
  PIN rx[437]
    DIRECTION INPUT ;
    USE SIGNAL ;
    PORT
      LAYER M4 ;
        RECT 0.000 145.920 0.192 145.944 ;
    END
  END rx[437]
  PIN rx[438]
    DIRECTION INPUT ;
    USE SIGNAL ;
    PORT
      LAYER M4 ;
        RECT 0.000 146.208 0.192 146.232 ;
    END
  END rx[438]
  PIN rx[439]
    DIRECTION INPUT ;
    USE SIGNAL ;
    PORT
      LAYER M4 ;
        RECT 0.000 146.544 0.192 146.568 ;
    END
  END rx[439]
  PIN rx[440]
    DIRECTION INPUT ;
    USE SIGNAL ;
    PORT
      LAYER M4 ;
        RECT 0.000 146.832 0.192 146.856 ;
    END
  END rx[440]
  PIN rx[441]
    DIRECTION INPUT ;
    USE SIGNAL ;
    PORT
      LAYER M4 ;
        RECT 0.000 147.168 0.192 147.192 ;
    END
  END rx[441]
  PIN rx[442]
    DIRECTION INPUT ;
    USE SIGNAL ;
    PORT
      LAYER M4 ;
        RECT 0.000 147.456 0.192 147.480 ;
    END
  END rx[442]
  PIN rx[443]
    DIRECTION INPUT ;
    USE SIGNAL ;
    PORT
      LAYER M4 ;
        RECT 0.000 147.792 0.192 147.816 ;
    END
  END rx[443]
  PIN rx[444]
    DIRECTION INPUT ;
    USE SIGNAL ;
    PORT
      LAYER M4 ;
        RECT 0.000 148.080 0.192 148.104 ;
    END
  END rx[444]
  PIN rx[445]
    DIRECTION INPUT ;
    USE SIGNAL ;
    PORT
      LAYER M4 ;
        RECT 0.000 148.416 0.192 148.440 ;
    END
  END rx[445]
  PIN rx[446]
    DIRECTION INPUT ;
    USE SIGNAL ;
    PORT
      LAYER M4 ;
        RECT 0.000 148.704 0.192 148.728 ;
    END
  END rx[446]
  PIN rx[447]
    DIRECTION INPUT ;
    USE SIGNAL ;
    PORT
      LAYER M4 ;
        RECT 0.000 149.040 0.192 149.064 ;
    END
  END rx[447]
  PIN rx[448]
    DIRECTION INPUT ;
    USE SIGNAL ;
    PORT
      LAYER M4 ;
        RECT 0.000 149.328 0.192 149.352 ;
    END
  END rx[448]
  PIN rx[449]
    DIRECTION INPUT ;
    USE SIGNAL ;
    PORT
      LAYER M4 ;
        RECT 0.000 149.616 0.192 149.640 ;
    END
  END rx[449]
  PIN rx[450]
    DIRECTION INPUT ;
    USE SIGNAL ;
    PORT
      LAYER M4 ;
        RECT 0.000 149.952 0.192 149.976 ;
    END
  END rx[450]
  PIN rx[451]
    DIRECTION INPUT ;
    USE SIGNAL ;
    PORT
      LAYER M4 ;
        RECT 0.000 150.240 0.192 150.264 ;
    END
  END rx[451]
  PIN rx[452]
    DIRECTION INPUT ;
    USE SIGNAL ;
    PORT
      LAYER M4 ;
        RECT 0.000 150.576 0.192 150.600 ;
    END
  END rx[452]
  PIN rx[453]
    DIRECTION INPUT ;
    USE SIGNAL ;
    PORT
      LAYER M4 ;
        RECT 0.000 150.864 0.192 150.888 ;
    END
  END rx[453]
  PIN rx[454]
    DIRECTION INPUT ;
    USE SIGNAL ;
    PORT
      LAYER M4 ;
        RECT 0.000 151.200 0.192 151.224 ;
    END
  END rx[454]
  PIN rx[455]
    DIRECTION INPUT ;
    USE SIGNAL ;
    PORT
      LAYER M4 ;
        RECT 0.000 151.488 0.192 151.512 ;
    END
  END rx[455]
  PIN rx[456]
    DIRECTION INPUT ;
    USE SIGNAL ;
    PORT
      LAYER M4 ;
        RECT 0.000 151.824 0.192 151.848 ;
    END
  END rx[456]
  PIN rx[457]
    DIRECTION INPUT ;
    USE SIGNAL ;
    PORT
      LAYER M4 ;
        RECT 0.000 152.112 0.192 152.136 ;
    END
  END rx[457]
  PIN rx[458]
    DIRECTION INPUT ;
    USE SIGNAL ;
    PORT
      LAYER M4 ;
        RECT 0.000 152.448 0.192 152.472 ;
    END
  END rx[458]
  PIN rx[459]
    DIRECTION INPUT ;
    USE SIGNAL ;
    PORT
      LAYER M4 ;
        RECT 0.000 152.736 0.192 152.760 ;
    END
  END rx[459]
  PIN rx[460]
    DIRECTION INPUT ;
    USE SIGNAL ;
    PORT
      LAYER M4 ;
        RECT 0.000 153.072 0.192 153.096 ;
    END
  END rx[460]
  PIN rx[461]
    DIRECTION INPUT ;
    USE SIGNAL ;
    PORT
      LAYER M4 ;
        RECT 0.000 153.360 0.192 153.384 ;
    END
  END rx[461]
  PIN rx[462]
    DIRECTION INPUT ;
    USE SIGNAL ;
    PORT
      LAYER M4 ;
        RECT 0.000 153.696 0.192 153.720 ;
    END
  END rx[462]
  PIN rx[463]
    DIRECTION INPUT ;
    USE SIGNAL ;
    PORT
      LAYER M4 ;
        RECT 0.000 153.984 0.192 154.008 ;
    END
  END rx[463]
  PIN rx[464]
    DIRECTION INPUT ;
    USE SIGNAL ;
    PORT
      LAYER M4 ;
        RECT 0.000 154.320 0.192 154.344 ;
    END
  END rx[464]
  PIN rx[465]
    DIRECTION INPUT ;
    USE SIGNAL ;
    PORT
      LAYER M4 ;
        RECT 0.000 154.608 0.192 154.632 ;
    END
  END rx[465]
  PIN rx[466]
    DIRECTION INPUT ;
    USE SIGNAL ;
    PORT
      LAYER M4 ;
        RECT 0.000 154.944 0.192 154.968 ;
    END
  END rx[466]
  PIN rx[467]
    DIRECTION INPUT ;
    USE SIGNAL ;
    PORT
      LAYER M4 ;
        RECT 0.000 155.232 0.192 155.256 ;
    END
  END rx[467]
  PIN rx[468]
    DIRECTION INPUT ;
    USE SIGNAL ;
    PORT
      LAYER M4 ;
        RECT 0.000 155.520 0.192 155.544 ;
    END
  END rx[468]
  PIN rx[469]
    DIRECTION INPUT ;
    USE SIGNAL ;
    PORT
      LAYER M4 ;
        RECT 0.000 155.856 0.192 155.880 ;
    END
  END rx[469]
  PIN rx[470]
    DIRECTION INPUT ;
    USE SIGNAL ;
    PORT
      LAYER M4 ;
        RECT 0.000 156.144 0.192 156.168 ;
    END
  END rx[470]
  PIN rx[471]
    DIRECTION INPUT ;
    USE SIGNAL ;
    PORT
      LAYER M4 ;
        RECT 0.000 156.480 0.192 156.504 ;
    END
  END rx[471]
  PIN rx[472]
    DIRECTION INPUT ;
    USE SIGNAL ;
    PORT
      LAYER M4 ;
        RECT 0.000 156.768 0.192 156.792 ;
    END
  END rx[472]
  PIN rx[473]
    DIRECTION INPUT ;
    USE SIGNAL ;
    PORT
      LAYER M4 ;
        RECT 0.000 157.104 0.192 157.128 ;
    END
  END rx[473]
  PIN rx[474]
    DIRECTION INPUT ;
    USE SIGNAL ;
    PORT
      LAYER M4 ;
        RECT 0.000 157.392 0.192 157.416 ;
    END
  END rx[474]
  PIN rx[475]
    DIRECTION INPUT ;
    USE SIGNAL ;
    PORT
      LAYER M4 ;
        RECT 0.000 157.728 0.192 157.752 ;
    END
  END rx[475]
  PIN rx[476]
    DIRECTION INPUT ;
    USE SIGNAL ;
    PORT
      LAYER M4 ;
        RECT 0.000 158.016 0.192 158.040 ;
    END
  END rx[476]
  PIN rx[477]
    DIRECTION INPUT ;
    USE SIGNAL ;
    PORT
      LAYER M4 ;
        RECT 0.000 158.352 0.192 158.376 ;
    END
  END rx[477]
  PIN rx[478]
    DIRECTION INPUT ;
    USE SIGNAL ;
    PORT
      LAYER M4 ;
        RECT 0.000 158.640 0.192 158.664 ;
    END
  END rx[478]
  PIN rx[479]
    DIRECTION INPUT ;
    USE SIGNAL ;
    PORT
      LAYER M4 ;
        RECT 0.000 158.976 0.192 159.000 ;
    END
  END rx[479]
  PIN rx[480]
    DIRECTION INPUT ;
    USE SIGNAL ;
    PORT
      LAYER M4 ;
        RECT 0.000 159.264 0.192 159.288 ;
    END
  END rx[480]
  PIN rx[481]
    DIRECTION INPUT ;
    USE SIGNAL ;
    PORT
      LAYER M4 ;
        RECT 0.000 159.600 0.192 159.624 ;
    END
  END rx[481]
  PIN rx[482]
    DIRECTION INPUT ;
    USE SIGNAL ;
    PORT
      LAYER M4 ;
        RECT 0.000 159.888 0.192 159.912 ;
    END
  END rx[482]
  PIN rx[483]
    DIRECTION INPUT ;
    USE SIGNAL ;
    PORT
      LAYER M4 ;
        RECT 0.000 160.224 0.192 160.248 ;
    END
  END rx[483]
  PIN rx[484]
    DIRECTION INPUT ;
    USE SIGNAL ;
    PORT
      LAYER M4 ;
        RECT 0.000 160.512 0.192 160.536 ;
    END
  END rx[484]
  PIN rx[485]
    DIRECTION INPUT ;
    USE SIGNAL ;
    PORT
      LAYER M4 ;
        RECT 0.000 160.800 0.192 160.824 ;
    END
  END rx[485]
  PIN rx[486]
    DIRECTION INPUT ;
    USE SIGNAL ;
    PORT
      LAYER M4 ;
        RECT 0.000 161.136 0.192 161.160 ;
    END
  END rx[486]
  PIN rx[487]
    DIRECTION INPUT ;
    USE SIGNAL ;
    PORT
      LAYER M4 ;
        RECT 0.000 161.424 0.192 161.448 ;
    END
  END rx[487]
  PIN rx[488]
    DIRECTION INPUT ;
    USE SIGNAL ;
    PORT
      LAYER M4 ;
        RECT 0.000 161.760 0.192 161.784 ;
    END
  END rx[488]
  PIN rx[489]
    DIRECTION INPUT ;
    USE SIGNAL ;
    PORT
      LAYER M4 ;
        RECT 0.000 162.048 0.192 162.072 ;
    END
  END rx[489]
  PIN rx[490]
    DIRECTION INPUT ;
    USE SIGNAL ;
    PORT
      LAYER M4 ;
        RECT 0.000 162.384 0.192 162.408 ;
    END
  END rx[490]
  PIN rx[491]
    DIRECTION INPUT ;
    USE SIGNAL ;
    PORT
      LAYER M4 ;
        RECT 0.000 162.672 0.192 162.696 ;
    END
  END rx[491]
  PIN rx[492]
    DIRECTION INPUT ;
    USE SIGNAL ;
    PORT
      LAYER M4 ;
        RECT 0.000 163.008 0.192 163.032 ;
    END
  END rx[492]
  PIN rx[493]
    DIRECTION INPUT ;
    USE SIGNAL ;
    PORT
      LAYER M4 ;
        RECT 0.000 163.296 0.192 163.320 ;
    END
  END rx[493]
  PIN rx[494]
    DIRECTION INPUT ;
    USE SIGNAL ;
    PORT
      LAYER M4 ;
        RECT 0.000 163.632 0.192 163.656 ;
    END
  END rx[494]
  PIN rx[495]
    DIRECTION INPUT ;
    USE SIGNAL ;
    PORT
      LAYER M4 ;
        RECT 0.000 163.920 0.192 163.944 ;
    END
  END rx[495]
  PIN rx[496]
    DIRECTION INPUT ;
    USE SIGNAL ;
    PORT
      LAYER M4 ;
        RECT 0.000 164.256 0.192 164.280 ;
    END
  END rx[496]
  PIN rx[497]
    DIRECTION INPUT ;
    USE SIGNAL ;
    PORT
      LAYER M4 ;
        RECT 0.000 164.544 0.192 164.568 ;
    END
  END rx[497]
  PIN rx[498]
    DIRECTION INPUT ;
    USE SIGNAL ;
    PORT
      LAYER M4 ;
        RECT 0.000 164.880 0.192 164.904 ;
    END
  END rx[498]
  PIN rx[499]
    DIRECTION INPUT ;
    USE SIGNAL ;
    PORT
      LAYER M4 ;
        RECT 0.000 165.168 0.192 165.192 ;
    END
  END rx[499]
  PIN rx[500]
    DIRECTION INPUT ;
    USE SIGNAL ;
    PORT
      LAYER M4 ;
        RECT 0.000 165.504 0.192 165.528 ;
    END
  END rx[500]
  PIN rx[501]
    DIRECTION INPUT ;
    USE SIGNAL ;
    PORT
      LAYER M4 ;
        RECT 0.000 165.792 0.192 165.816 ;
    END
  END rx[501]
  PIN rx[502]
    DIRECTION INPUT ;
    USE SIGNAL ;
    PORT
      LAYER M4 ;
        RECT 0.000 166.128 0.192 166.152 ;
    END
  END rx[502]
  PIN rx[503]
    DIRECTION INPUT ;
    USE SIGNAL ;
    PORT
      LAYER M4 ;
        RECT 0.000 166.416 0.192 166.440 ;
    END
  END rx[503]
  PIN rx[504]
    DIRECTION INPUT ;
    USE SIGNAL ;
    PORT
      LAYER M4 ;
        RECT 0.000 166.704 0.192 166.728 ;
    END
  END rx[504]
  PIN rx[505]
    DIRECTION INPUT ;
    USE SIGNAL ;
    PORT
      LAYER M4 ;
        RECT 0.000 167.040 0.192 167.064 ;
    END
  END rx[505]
  PIN rx[506]
    DIRECTION INPUT ;
    USE SIGNAL ;
    PORT
      LAYER M4 ;
        RECT 0.000 167.328 0.192 167.352 ;
    END
  END rx[506]
  PIN rx[507]
    DIRECTION INPUT ;
    USE SIGNAL ;
    PORT
      LAYER M4 ;
        RECT 0.000 167.664 0.192 167.688 ;
    END
  END rx[507]
  PIN rx[508]
    DIRECTION INPUT ;
    USE SIGNAL ;
    PORT
      LAYER M4 ;
        RECT 0.000 167.952 0.192 167.976 ;
    END
  END rx[508]
  PIN rx[509]
    DIRECTION INPUT ;
    USE SIGNAL ;
    PORT
      LAYER M4 ;
        RECT 0.000 168.288 0.192 168.312 ;
    END
  END rx[509]
  PIN rx[510]
    DIRECTION INPUT ;
    USE SIGNAL ;
    PORT
      LAYER M4 ;
        RECT 0.000 168.576 0.192 168.600 ;
    END
  END rx[510]
  PIN rx[511]
    DIRECTION INPUT ;
    USE SIGNAL ;
    PORT
      LAYER M4 ;
        RECT 0.000 168.912 0.192 168.936 ;
    END
  END rx[511]
  PIN rx[512]
    DIRECTION INPUT ;
    USE SIGNAL ;
    PORT
      LAYER M4 ;
        RECT 0.000 169.200 0.192 169.224 ;
    END
  END rx[512]
  PIN rx[513]
    DIRECTION INPUT ;
    USE SIGNAL ;
    PORT
      LAYER M4 ;
        RECT 0.000 169.536 0.192 169.560 ;
    END
  END rx[513]
  PIN rx[514]
    DIRECTION INPUT ;
    USE SIGNAL ;
    PORT
      LAYER M4 ;
        RECT 0.000 169.824 0.192 169.848 ;
    END
  END rx[514]
  PIN tx[0]
    DIRECTION OUTPUT ;
    USE SIGNAL ;
    PORT
      LAYER M4 ;
        RECT 0.000 170.160 0.192 170.184 ;
    END
  END tx[0]
  PIN tx[1]
    DIRECTION OUTPUT ;
    USE SIGNAL ;
    PORT
      LAYER M4 ;
        RECT 0.000 170.448 0.192 170.472 ;
    END
  END tx[1]
  PIN tx[2]
    DIRECTION OUTPUT ;
    USE SIGNAL ;
    PORT
      LAYER M4 ;
        RECT 0.000 170.784 0.192 170.808 ;
    END
  END tx[2]
  PIN tx[3]
    DIRECTION OUTPUT ;
    USE SIGNAL ;
    PORT
      LAYER M4 ;
        RECT 0.000 171.072 0.192 171.096 ;
    END
  END tx[3]
  PIN tx[4]
    DIRECTION OUTPUT ;
    USE SIGNAL ;
    PORT
      LAYER M4 ;
        RECT 0.000 171.408 0.192 171.432 ;
    END
  END tx[4]
  PIN tx[5]
    DIRECTION OUTPUT ;
    USE SIGNAL ;
    PORT
      LAYER M4 ;
        RECT 0.000 171.696 0.192 171.720 ;
    END
  END tx[5]
  PIN tx[6]
    DIRECTION OUTPUT ;
    USE SIGNAL ;
    PORT
      LAYER M4 ;
        RECT 0.000 172.032 0.192 172.056 ;
    END
  END tx[6]
  PIN tx[7]
    DIRECTION OUTPUT ;
    USE SIGNAL ;
    PORT
      LAYER M4 ;
        RECT 0.000 172.368 0.192 172.392 ;
    END
  END tx[7]
  PIN tx[8]
    DIRECTION OUTPUT ;
    USE SIGNAL ;
    PORT
      LAYER M4 ;
        RECT 0.000 172.656 0.192 172.680 ;
    END
  END tx[8]
  PIN tx[9]
    DIRECTION OUTPUT ;
    USE SIGNAL ;
    PORT
      LAYER M4 ;
        RECT 0.000 172.992 0.192 173.016 ;
    END
  END tx[9]
  PIN tx[10]
    DIRECTION OUTPUT ;
    USE SIGNAL ;
    PORT
      LAYER M4 ;
        RECT 0.000 173.280 0.192 173.304 ;
    END
  END tx[10]
  PIN tx[11]
    DIRECTION OUTPUT ;
    USE SIGNAL ;
    PORT
      LAYER M4 ;
        RECT 0.000 173.616 0.192 173.640 ;
    END
  END tx[11]
  PIN tx[12]
    DIRECTION OUTPUT ;
    USE SIGNAL ;
    PORT
      LAYER M4 ;
        RECT 0.000 173.904 0.192 173.928 ;
    END
  END tx[12]
  PIN tx[13]
    DIRECTION OUTPUT ;
    USE SIGNAL ;
    PORT
      LAYER M4 ;
        RECT 0.000 174.240 0.192 174.264 ;
    END
  END tx[13]
  PIN tx[14]
    DIRECTION OUTPUT ;
    USE SIGNAL ;
    PORT
      LAYER M4 ;
        RECT 0.000 174.528 0.192 174.552 ;
    END
  END tx[14]
  PIN tx[15]
    DIRECTION OUTPUT ;
    USE SIGNAL ;
    PORT
      LAYER M4 ;
        RECT 0.000 174.864 0.192 174.888 ;
    END
  END tx[15]
  PIN tx[16]
    DIRECTION OUTPUT ;
    USE SIGNAL ;
    PORT
      LAYER M4 ;
        RECT 0.000 175.152 0.192 175.176 ;
    END
  END tx[16]
  PIN tx[17]
    DIRECTION OUTPUT ;
    USE SIGNAL ;
    PORT
      LAYER M4 ;
        RECT 0.000 175.488 0.192 175.512 ;
    END
  END tx[17]
  PIN tx[18]
    DIRECTION OUTPUT ;
    USE SIGNAL ;
    PORT
      LAYER M4 ;
        RECT 0.000 175.824 0.192 175.848 ;
    END
  END tx[18]
  PIN tx[19]
    DIRECTION OUTPUT ;
    USE SIGNAL ;
    PORT
      LAYER M4 ;
        RECT 0.000 176.112 0.192 176.136 ;
    END
  END tx[19]
  PIN tx[20]
    DIRECTION OUTPUT ;
    USE SIGNAL ;
    PORT
      LAYER M4 ;
        RECT 0.000 176.448 0.192 176.472 ;
    END
  END tx[20]
  PIN tx[21]
    DIRECTION OUTPUT ;
    USE SIGNAL ;
    PORT
      LAYER M4 ;
        RECT 0.000 176.736 0.192 176.760 ;
    END
  END tx[21]
  PIN tx[22]
    DIRECTION OUTPUT ;
    USE SIGNAL ;
    PORT
      LAYER M4 ;
        RECT 0.000 177.072 0.192 177.096 ;
    END
  END tx[22]
  PIN tx[23]
    DIRECTION OUTPUT ;
    USE SIGNAL ;
    PORT
      LAYER M4 ;
        RECT 0.000 177.360 0.192 177.384 ;
    END
  END tx[23]
  PIN tx[24]
    DIRECTION OUTPUT ;
    USE SIGNAL ;
    PORT
      LAYER M4 ;
        RECT 0.000 177.696 0.192 177.720 ;
    END
  END tx[24]
  PIN tx[25]
    DIRECTION OUTPUT ;
    USE SIGNAL ;
    PORT
      LAYER M4 ;
        RECT 0.000 177.984 0.192 178.008 ;
    END
  END tx[25]
  PIN tx[26]
    DIRECTION OUTPUT ;
    USE SIGNAL ;
    PORT
      LAYER M4 ;
        RECT 0.000 178.320 0.192 178.344 ;
    END
  END tx[26]
  PIN tx[27]
    DIRECTION OUTPUT ;
    USE SIGNAL ;
    PORT
      LAYER M4 ;
        RECT 0.000 178.656 0.192 178.680 ;
    END
  END tx[27]
  PIN tx[28]
    DIRECTION OUTPUT ;
    USE SIGNAL ;
    PORT
      LAYER M4 ;
        RECT 0.000 178.944 0.192 178.968 ;
    END
  END tx[28]
  PIN tx[29]
    DIRECTION OUTPUT ;
    USE SIGNAL ;
    PORT
      LAYER M4 ;
        RECT 0.000 179.280 0.192 179.304 ;
    END
  END tx[29]
  PIN tx[30]
    DIRECTION OUTPUT ;
    USE SIGNAL ;
    PORT
      LAYER M4 ;
        RECT 0.000 179.568 0.192 179.592 ;
    END
  END tx[30]
  PIN tx[31]
    DIRECTION OUTPUT ;
    USE SIGNAL ;
    PORT
      LAYER M4 ;
        RECT 0.000 179.904 0.192 179.928 ;
    END
  END tx[31]
  PIN tx[32]
    DIRECTION OUTPUT ;
    USE SIGNAL ;
    PORT
      LAYER M4 ;
        RECT 0.000 180.192 0.192 180.216 ;
    END
  END tx[32]
  PIN tx[33]
    DIRECTION OUTPUT ;
    USE SIGNAL ;
    PORT
      LAYER M4 ;
        RECT 0.000 180.528 0.192 180.552 ;
    END
  END tx[33]
  PIN tx[34]
    DIRECTION OUTPUT ;
    USE SIGNAL ;
    PORT
      LAYER M4 ;
        RECT 0.000 180.816 0.192 180.840 ;
    END
  END tx[34]
  PIN tx[35]
    DIRECTION OUTPUT ;
    USE SIGNAL ;
    PORT
      LAYER M4 ;
        RECT 0.000 181.152 0.192 181.176 ;
    END
  END tx[35]
  PIN tx[36]
    DIRECTION OUTPUT ;
    USE SIGNAL ;
    PORT
      LAYER M4 ;
        RECT 0.000 181.440 0.192 181.464 ;
    END
  END tx[36]
  PIN tx[37]
    DIRECTION OUTPUT ;
    USE SIGNAL ;
    PORT
      LAYER M4 ;
        RECT 0.000 181.776 0.192 181.800 ;
    END
  END tx[37]
  PIN tx[38]
    DIRECTION OUTPUT ;
    USE SIGNAL ;
    PORT
      LAYER M4 ;
        RECT 0.000 182.112 0.192 182.136 ;
    END
  END tx[38]
  PIN tx[39]
    DIRECTION OUTPUT ;
    USE SIGNAL ;
    PORT
      LAYER M4 ;
        RECT 0.000 182.400 0.192 182.424 ;
    END
  END tx[39]
  PIN tx[40]
    DIRECTION OUTPUT ;
    USE SIGNAL ;
    PORT
      LAYER M4 ;
        RECT 0.000 182.736 0.192 182.760 ;
    END
  END tx[40]
  PIN tx[41]
    DIRECTION OUTPUT ;
    USE SIGNAL ;
    PORT
      LAYER M4 ;
        RECT 0.000 183.024 0.192 183.048 ;
    END
  END tx[41]
  PIN tx[42]
    DIRECTION OUTPUT ;
    USE SIGNAL ;
    PORT
      LAYER M4 ;
        RECT 0.000 183.360 0.192 183.384 ;
    END
  END tx[42]
  PIN tx[43]
    DIRECTION OUTPUT ;
    USE SIGNAL ;
    PORT
      LAYER M4 ;
        RECT 0.000 183.648 0.192 183.672 ;
    END
  END tx[43]
  PIN tx[44]
    DIRECTION OUTPUT ;
    USE SIGNAL ;
    PORT
      LAYER M4 ;
        RECT 0.000 183.984 0.192 184.008 ;
    END
  END tx[44]
  PIN tx[45]
    DIRECTION OUTPUT ;
    USE SIGNAL ;
    PORT
      LAYER M4 ;
        RECT 0.000 184.272 0.192 184.296 ;
    END
  END tx[45]
  PIN tx[46]
    DIRECTION OUTPUT ;
    USE SIGNAL ;
    PORT
      LAYER M4 ;
        RECT 0.000 184.608 0.192 184.632 ;
    END
  END tx[46]
  PIN tx[47]
    DIRECTION OUTPUT ;
    USE SIGNAL ;
    PORT
      LAYER M4 ;
        RECT 0.000 184.944 0.192 184.968 ;
    END
  END tx[47]
  PIN tx[48]
    DIRECTION OUTPUT ;
    USE SIGNAL ;
    PORT
      LAYER M4 ;
        RECT 0.000 185.232 0.192 185.256 ;
    END
  END tx[48]
  PIN tx[49]
    DIRECTION OUTPUT ;
    USE SIGNAL ;
    PORT
      LAYER M4 ;
        RECT 0.000 185.568 0.192 185.592 ;
    END
  END tx[49]
  PIN tx[50]
    DIRECTION OUTPUT ;
    USE SIGNAL ;
    PORT
      LAYER M4 ;
        RECT 0.000 185.856 0.192 185.880 ;
    END
  END tx[50]
  PIN tx[51]
    DIRECTION OUTPUT ;
    USE SIGNAL ;
    PORT
      LAYER M4 ;
        RECT 0.000 186.192 0.192 186.216 ;
    END
  END tx[51]
  PIN tx[52]
    DIRECTION OUTPUT ;
    USE SIGNAL ;
    PORT
      LAYER M4 ;
        RECT 0.000 186.480 0.192 186.504 ;
    END
  END tx[52]
  PIN tx[53]
    DIRECTION OUTPUT ;
    USE SIGNAL ;
    PORT
      LAYER M4 ;
        RECT 0.000 186.816 0.192 186.840 ;
    END
  END tx[53]
  PIN tx[54]
    DIRECTION OUTPUT ;
    USE SIGNAL ;
    PORT
      LAYER M4 ;
        RECT 0.000 187.104 0.192 187.128 ;
    END
  END tx[54]
  PIN tx[55]
    DIRECTION OUTPUT ;
    USE SIGNAL ;
    PORT
      LAYER M4 ;
        RECT 0.000 187.440 0.192 187.464 ;
    END
  END tx[55]
  PIN tx[56]
    DIRECTION OUTPUT ;
    USE SIGNAL ;
    PORT
      LAYER M4 ;
        RECT 0.000 187.728 0.192 187.752 ;
    END
  END tx[56]
  PIN tx[57]
    DIRECTION OUTPUT ;
    USE SIGNAL ;
    PORT
      LAYER M4 ;
        RECT 0.000 188.064 0.192 188.088 ;
    END
  END tx[57]
  PIN tx[58]
    DIRECTION OUTPUT ;
    USE SIGNAL ;
    PORT
      LAYER M4 ;
        RECT 0.000 188.400 0.192 188.424 ;
    END
  END tx[58]
  PIN tx[59]
    DIRECTION OUTPUT ;
    USE SIGNAL ;
    PORT
      LAYER M4 ;
        RECT 0.000 188.688 0.192 188.712 ;
    END
  END tx[59]
  PIN tx[60]
    DIRECTION OUTPUT ;
    USE SIGNAL ;
    PORT
      LAYER M4 ;
        RECT 0.000 189.024 0.192 189.048 ;
    END
  END tx[60]
  PIN tx[61]
    DIRECTION OUTPUT ;
    USE SIGNAL ;
    PORT
      LAYER M4 ;
        RECT 0.000 189.312 0.192 189.336 ;
    END
  END tx[61]
  PIN tx[62]
    DIRECTION OUTPUT ;
    USE SIGNAL ;
    PORT
      LAYER M4 ;
        RECT 0.000 189.648 0.192 189.672 ;
    END
  END tx[62]
  PIN tx[63]
    DIRECTION OUTPUT ;
    USE SIGNAL ;
    PORT
      LAYER M4 ;
        RECT 0.000 189.936 0.192 189.960 ;
    END
  END tx[63]
  PIN tx[64]
    DIRECTION OUTPUT ;
    USE SIGNAL ;
    PORT
      LAYER M4 ;
        RECT 0.000 190.272 0.192 190.296 ;
    END
  END tx[64]
  PIN tx[65]
    DIRECTION OUTPUT ;
    USE SIGNAL ;
    PORT
      LAYER M4 ;
        RECT 0.000 190.560 0.192 190.584 ;
    END
  END tx[65]
  PIN tx[66]
    DIRECTION OUTPUT ;
    USE SIGNAL ;
    PORT
      LAYER M4 ;
        RECT 0.000 190.896 0.192 190.920 ;
    END
  END tx[66]
  PIN tx[67]
    DIRECTION OUTPUT ;
    USE SIGNAL ;
    PORT
      LAYER M4 ;
        RECT 0.000 191.232 0.192 191.256 ;
    END
  END tx[67]
  PIN tx[68]
    DIRECTION OUTPUT ;
    USE SIGNAL ;
    PORT
      LAYER M4 ;
        RECT 0.000 191.520 0.192 191.544 ;
    END
  END tx[68]
  PIN tx[69]
    DIRECTION OUTPUT ;
    USE SIGNAL ;
    PORT
      LAYER M4 ;
        RECT 0.000 191.856 0.192 191.880 ;
    END
  END tx[69]
  PIN tx[70]
    DIRECTION OUTPUT ;
    USE SIGNAL ;
    PORT
      LAYER M4 ;
        RECT 0.000 192.144 0.192 192.168 ;
    END
  END tx[70]
  PIN tx[71]
    DIRECTION OUTPUT ;
    USE SIGNAL ;
    PORT
      LAYER M4 ;
        RECT 0.000 192.480 0.192 192.504 ;
    END
  END tx[71]
  PIN tx[72]
    DIRECTION OUTPUT ;
    USE SIGNAL ;
    PORT
      LAYER M4 ;
        RECT 0.000 192.768 0.192 192.792 ;
    END
  END tx[72]
  PIN tx[73]
    DIRECTION OUTPUT ;
    USE SIGNAL ;
    PORT
      LAYER M4 ;
        RECT 0.000 193.104 0.192 193.128 ;
    END
  END tx[73]
  PIN tx[74]
    DIRECTION OUTPUT ;
    USE SIGNAL ;
    PORT
      LAYER M4 ;
        RECT 0.000 193.392 0.192 193.416 ;
    END
  END tx[74]
  PIN tx[75]
    DIRECTION OUTPUT ;
    USE SIGNAL ;
    PORT
      LAYER M4 ;
        RECT 0.000 193.728 0.192 193.752 ;
    END
  END tx[75]
  PIN tx[76]
    DIRECTION OUTPUT ;
    USE SIGNAL ;
    PORT
      LAYER M4 ;
        RECT 0.000 194.016 0.192 194.040 ;
    END
  END tx[76]
  PIN tx[77]
    DIRECTION OUTPUT ;
    USE SIGNAL ;
    PORT
      LAYER M4 ;
        RECT 0.000 194.352 0.192 194.376 ;
    END
  END tx[77]
  PIN tx[78]
    DIRECTION OUTPUT ;
    USE SIGNAL ;
    PORT
      LAYER M4 ;
        RECT 0.000 194.688 0.192 194.712 ;
    END
  END tx[78]
  PIN tx[79]
    DIRECTION OUTPUT ;
    USE SIGNAL ;
    PORT
      LAYER M4 ;
        RECT 0.000 194.976 0.192 195.000 ;
    END
  END tx[79]
  PIN tx[80]
    DIRECTION OUTPUT ;
    USE SIGNAL ;
    PORT
      LAYER M4 ;
        RECT 0.000 195.312 0.192 195.336 ;
    END
  END tx[80]
  PIN tx[81]
    DIRECTION OUTPUT ;
    USE SIGNAL ;
    PORT
      LAYER M4 ;
        RECT 0.000 195.600 0.192 195.624 ;
    END
  END tx[81]
  PIN tx[82]
    DIRECTION OUTPUT ;
    USE SIGNAL ;
    PORT
      LAYER M4 ;
        RECT 0.000 195.936 0.192 195.960 ;
    END
  END tx[82]
  PIN tx[83]
    DIRECTION OUTPUT ;
    USE SIGNAL ;
    PORT
      LAYER M4 ;
        RECT 0.000 196.224 0.192 196.248 ;
    END
  END tx[83]
  PIN tx[84]
    DIRECTION OUTPUT ;
    USE SIGNAL ;
    PORT
      LAYER M4 ;
        RECT 0.000 196.560 0.192 196.584 ;
    END
  END tx[84]
  PIN tx[85]
    DIRECTION OUTPUT ;
    USE SIGNAL ;
    PORT
      LAYER M4 ;
        RECT 0.000 196.848 0.192 196.872 ;
    END
  END tx[85]
  PIN tx[86]
    DIRECTION OUTPUT ;
    USE SIGNAL ;
    PORT
      LAYER M4 ;
        RECT 0.000 197.184 0.192 197.208 ;
    END
  END tx[86]
  PIN tx[87]
    DIRECTION OUTPUT ;
    USE SIGNAL ;
    PORT
      LAYER M4 ;
        RECT 0.000 197.472 0.192 197.496 ;
    END
  END tx[87]
  PIN tx[88]
    DIRECTION OUTPUT ;
    USE SIGNAL ;
    PORT
      LAYER M4 ;
        RECT 0.000 197.808 0.192 197.832 ;
    END
  END tx[88]
  PIN tx[89]
    DIRECTION OUTPUT ;
    USE SIGNAL ;
    PORT
      LAYER M4 ;
        RECT 0.000 198.144 0.192 198.168 ;
    END
  END tx[89]
  PIN tx[90]
    DIRECTION OUTPUT ;
    USE SIGNAL ;
    PORT
      LAYER M4 ;
        RECT 0.000 198.432 0.192 198.456 ;
    END
  END tx[90]
  PIN tx[91]
    DIRECTION OUTPUT ;
    USE SIGNAL ;
    PORT
      LAYER M4 ;
        RECT 0.000 198.768 0.192 198.792 ;
    END
  END tx[91]
  PIN tx[92]
    DIRECTION OUTPUT ;
    USE SIGNAL ;
    PORT
      LAYER M4 ;
        RECT 0.000 199.056 0.192 199.080 ;
    END
  END tx[92]
  PIN tx[93]
    DIRECTION OUTPUT ;
    USE SIGNAL ;
    PORT
      LAYER M4 ;
        RECT 0.000 199.392 0.192 199.416 ;
    END
  END tx[93]
  PIN tx[94]
    DIRECTION OUTPUT ;
    USE SIGNAL ;
    PORT
      LAYER M4 ;
        RECT 0.000 199.680 0.192 199.704 ;
    END
  END tx[94]
  PIN tx[95]
    DIRECTION OUTPUT ;
    USE SIGNAL ;
    PORT
      LAYER M4 ;
        RECT 0.000 200.016 0.192 200.040 ;
    END
  END tx[95]
  PIN tx[96]
    DIRECTION OUTPUT ;
    USE SIGNAL ;
    PORT
      LAYER M4 ;
        RECT 0.000 200.304 0.192 200.328 ;
    END
  END tx[96]
  PIN tx[97]
    DIRECTION OUTPUT ;
    USE SIGNAL ;
    PORT
      LAYER M4 ;
        RECT 0.000 200.640 0.192 200.664 ;
    END
  END tx[97]
  PIN tx[98]
    DIRECTION OUTPUT ;
    USE SIGNAL ;
    PORT
      LAYER M4 ;
        RECT 0.000 200.976 0.192 201.000 ;
    END
  END tx[98]
  PIN tx[99]
    DIRECTION OUTPUT ;
    USE SIGNAL ;
    PORT
      LAYER M4 ;
        RECT 0.000 201.264 0.192 201.288 ;
    END
  END tx[99]
  PIN tx[100]
    DIRECTION OUTPUT ;
    USE SIGNAL ;
    PORT
      LAYER M4 ;
        RECT 0.000 201.600 0.192 201.624 ;
    END
  END tx[100]
  PIN tx[101]
    DIRECTION OUTPUT ;
    USE SIGNAL ;
    PORT
      LAYER M4 ;
        RECT 0.000 201.888 0.192 201.912 ;
    END
  END tx[101]
  PIN tx[102]
    DIRECTION OUTPUT ;
    USE SIGNAL ;
    PORT
      LAYER M4 ;
        RECT 0.000 202.224 0.192 202.248 ;
    END
  END tx[102]
  PIN tx[103]
    DIRECTION OUTPUT ;
    USE SIGNAL ;
    PORT
      LAYER M4 ;
        RECT 0.000 202.512 0.192 202.536 ;
    END
  END tx[103]
  PIN tx[104]
    DIRECTION OUTPUT ;
    USE SIGNAL ;
    PORT
      LAYER M4 ;
        RECT 0.000 202.848 0.192 202.872 ;
    END
  END tx[104]
  PIN tx[105]
    DIRECTION OUTPUT ;
    USE SIGNAL ;
    PORT
      LAYER M4 ;
        RECT 0.000 203.136 0.192 203.160 ;
    END
  END tx[105]
  PIN tx[106]
    DIRECTION OUTPUT ;
    USE SIGNAL ;
    PORT
      LAYER M4 ;
        RECT 0.000 203.472 0.192 203.496 ;
    END
  END tx[106]
  PIN tx[107]
    DIRECTION OUTPUT ;
    USE SIGNAL ;
    PORT
      LAYER M4 ;
        RECT 0.000 203.760 0.192 203.784 ;
    END
  END tx[107]
  PIN tx[108]
    DIRECTION OUTPUT ;
    USE SIGNAL ;
    PORT
      LAYER M4 ;
        RECT 0.000 204.096 0.192 204.120 ;
    END
  END tx[108]
  PIN tx[109]
    DIRECTION OUTPUT ;
    USE SIGNAL ;
    PORT
      LAYER M4 ;
        RECT 0.000 204.432 0.192 204.456 ;
    END
  END tx[109]
  PIN tx[110]
    DIRECTION OUTPUT ;
    USE SIGNAL ;
    PORT
      LAYER M4 ;
        RECT 0.000 204.720 0.192 204.744 ;
    END
  END tx[110]
  PIN tx[111]
    DIRECTION OUTPUT ;
    USE SIGNAL ;
    PORT
      LAYER M4 ;
        RECT 0.000 205.056 0.192 205.080 ;
    END
  END tx[111]
  PIN tx[112]
    DIRECTION OUTPUT ;
    USE SIGNAL ;
    PORT
      LAYER M4 ;
        RECT 0.000 205.344 0.192 205.368 ;
    END
  END tx[112]
  PIN tx[113]
    DIRECTION OUTPUT ;
    USE SIGNAL ;
    PORT
      LAYER M4 ;
        RECT 0.000 205.680 0.192 205.704 ;
    END
  END tx[113]
  PIN tx[114]
    DIRECTION OUTPUT ;
    USE SIGNAL ;
    PORT
      LAYER M4 ;
        RECT 0.000 205.968 0.192 205.992 ;
    END
  END tx[114]
  PIN tx[115]
    DIRECTION OUTPUT ;
    USE SIGNAL ;
    PORT
      LAYER M4 ;
        RECT 0.000 206.304 0.192 206.328 ;
    END
  END tx[115]
  PIN tx[116]
    DIRECTION OUTPUT ;
    USE SIGNAL ;
    PORT
      LAYER M4 ;
        RECT 0.000 206.592 0.192 206.616 ;
    END
  END tx[116]
  PIN tx[117]
    DIRECTION OUTPUT ;
    USE SIGNAL ;
    PORT
      LAYER M4 ;
        RECT 0.000 206.928 0.192 206.952 ;
    END
  END tx[117]
  PIN tx[118]
    DIRECTION OUTPUT ;
    USE SIGNAL ;
    PORT
      LAYER M4 ;
        RECT 0.000 207.264 0.192 207.288 ;
    END
  END tx[118]
  PIN tx[119]
    DIRECTION OUTPUT ;
    USE SIGNAL ;
    PORT
      LAYER M4 ;
        RECT 0.000 207.552 0.192 207.576 ;
    END
  END tx[119]
  PIN tx[120]
    DIRECTION OUTPUT ;
    USE SIGNAL ;
    PORT
      LAYER M4 ;
        RECT 0.000 207.888 0.192 207.912 ;
    END
  END tx[120]
  PIN tx[121]
    DIRECTION OUTPUT ;
    USE SIGNAL ;
    PORT
      LAYER M4 ;
        RECT 0.000 208.176 0.192 208.200 ;
    END
  END tx[121]
  PIN tx[122]
    DIRECTION OUTPUT ;
    USE SIGNAL ;
    PORT
      LAYER M4 ;
        RECT 0.000 208.512 0.192 208.536 ;
    END
  END tx[122]
  PIN tx[123]
    DIRECTION OUTPUT ;
    USE SIGNAL ;
    PORT
      LAYER M4 ;
        RECT 0.000 208.800 0.192 208.824 ;
    END
  END tx[123]
  PIN tx[124]
    DIRECTION OUTPUT ;
    USE SIGNAL ;
    PORT
      LAYER M4 ;
        RECT 0.000 209.136 0.192 209.160 ;
    END
  END tx[124]
  PIN tx[125]
    DIRECTION OUTPUT ;
    USE SIGNAL ;
    PORT
      LAYER M4 ;
        RECT 0.000 209.424 0.192 209.448 ;
    END
  END tx[125]
  PIN tx[126]
    DIRECTION OUTPUT ;
    USE SIGNAL ;
    PORT
      LAYER M4 ;
        RECT 0.000 209.760 0.192 209.784 ;
    END
  END tx[126]
  PIN tx[127]
    DIRECTION OUTPUT ;
    USE SIGNAL ;
    PORT
      LAYER M4 ;
        RECT 0.000 210.048 0.192 210.072 ;
    END
  END tx[127]
  PIN tx[128]
    DIRECTION OUTPUT ;
    USE SIGNAL ;
    PORT
      LAYER M4 ;
        RECT 0.000 210.384 0.192 210.408 ;
    END
  END tx[128]
  PIN tx[129]
    DIRECTION OUTPUT ;
    USE SIGNAL ;
    PORT
      LAYER M4 ;
        RECT 0.000 210.720 0.192 210.744 ;
    END
  END tx[129]
  PIN tx[130]
    DIRECTION OUTPUT ;
    USE SIGNAL ;
    PORT
      LAYER M4 ;
        RECT 0.000 211.008 0.192 211.032 ;
    END
  END tx[130]
  PIN tx[131]
    DIRECTION OUTPUT ;
    USE SIGNAL ;
    PORT
      LAYER M4 ;
        RECT 0.000 211.344 0.192 211.368 ;
    END
  END tx[131]
  PIN tx[132]
    DIRECTION OUTPUT ;
    USE SIGNAL ;
    PORT
      LAYER M4 ;
        RECT 0.000 211.632 0.192 211.656 ;
    END
  END tx[132]
  PIN tx[133]
    DIRECTION OUTPUT ;
    USE SIGNAL ;
    PORT
      LAYER M4 ;
        RECT 0.000 211.968 0.192 211.992 ;
    END
  END tx[133]
  PIN tx[134]
    DIRECTION OUTPUT ;
    USE SIGNAL ;
    PORT
      LAYER M4 ;
        RECT 0.000 212.256 0.192 212.280 ;
    END
  END tx[134]
  PIN tx[135]
    DIRECTION OUTPUT ;
    USE SIGNAL ;
    PORT
      LAYER M4 ;
        RECT 0.000 212.592 0.192 212.616 ;
    END
  END tx[135]
  PIN tx[136]
    DIRECTION OUTPUT ;
    USE SIGNAL ;
    PORT
      LAYER M4 ;
        RECT 0.000 212.880 0.192 212.904 ;
    END
  END tx[136]
  PIN tx[137]
    DIRECTION OUTPUT ;
    USE SIGNAL ;
    PORT
      LAYER M4 ;
        RECT 0.000 213.216 0.192 213.240 ;
    END
  END tx[137]
  PIN tx[138]
    DIRECTION OUTPUT ;
    USE SIGNAL ;
    PORT
      LAYER M4 ;
        RECT 0.000 213.552 0.192 213.576 ;
    END
  END tx[138]
  PIN tx[139]
    DIRECTION OUTPUT ;
    USE SIGNAL ;
    PORT
      LAYER M4 ;
        RECT 0.000 213.840 0.192 213.864 ;
    END
  END tx[139]
  PIN tx[140]
    DIRECTION OUTPUT ;
    USE SIGNAL ;
    PORT
      LAYER M4 ;
        RECT 0.000 214.176 0.192 214.200 ;
    END
  END tx[140]
  PIN tx[141]
    DIRECTION OUTPUT ;
    USE SIGNAL ;
    PORT
      LAYER M4 ;
        RECT 0.000 214.464 0.192 214.488 ;
    END
  END tx[141]
  PIN tx[142]
    DIRECTION OUTPUT ;
    USE SIGNAL ;
    PORT
      LAYER M4 ;
        RECT 0.000 214.800 0.192 214.824 ;
    END
  END tx[142]
  PIN tx[143]
    DIRECTION OUTPUT ;
    USE SIGNAL ;
    PORT
      LAYER M4 ;
        RECT 0.000 215.088 0.192 215.112 ;
    END
  END tx[143]
  PIN tx[144]
    DIRECTION OUTPUT ;
    USE SIGNAL ;
    PORT
      LAYER M4 ;
        RECT 0.000 215.424 0.192 215.448 ;
    END
  END tx[144]
  PIN tx[145]
    DIRECTION OUTPUT ;
    USE SIGNAL ;
    PORT
      LAYER M4 ;
        RECT 0.000 215.712 0.192 215.736 ;
    END
  END tx[145]
  PIN tx[146]
    DIRECTION OUTPUT ;
    USE SIGNAL ;
    PORT
      LAYER M4 ;
        RECT 0.000 216.048 0.192 216.072 ;
    END
  END tx[146]
  PIN tx[147]
    DIRECTION OUTPUT ;
    USE SIGNAL ;
    PORT
      LAYER M4 ;
        RECT 0.000 216.336 0.192 216.360 ;
    END
  END tx[147]
  PIN tx[148]
    DIRECTION OUTPUT ;
    USE SIGNAL ;
    PORT
      LAYER M4 ;
        RECT 0.000 216.672 0.192 216.696 ;
    END
  END tx[148]
  PIN tx[149]
    DIRECTION OUTPUT ;
    USE SIGNAL ;
    PORT
      LAYER M4 ;
        RECT 0.000 217.008 0.192 217.032 ;
    END
  END tx[149]
  PIN tx[150]
    DIRECTION OUTPUT ;
    USE SIGNAL ;
    PORT
      LAYER M4 ;
        RECT 0.000 217.296 0.192 217.320 ;
    END
  END tx[150]
  PIN tx[151]
    DIRECTION OUTPUT ;
    USE SIGNAL ;
    PORT
      LAYER M4 ;
        RECT 0.000 217.632 0.192 217.656 ;
    END
  END tx[151]
  PIN tx[152]
    DIRECTION OUTPUT ;
    USE SIGNAL ;
    PORT
      LAYER M4 ;
        RECT 0.000 217.920 0.192 217.944 ;
    END
  END tx[152]
  PIN tx[153]
    DIRECTION OUTPUT ;
    USE SIGNAL ;
    PORT
      LAYER M4 ;
        RECT 0.000 218.256 0.192 218.280 ;
    END
  END tx[153]
  PIN tx[154]
    DIRECTION OUTPUT ;
    USE SIGNAL ;
    PORT
      LAYER M4 ;
        RECT 0.000 218.544 0.192 218.568 ;
    END
  END tx[154]
  PIN tx[155]
    DIRECTION OUTPUT ;
    USE SIGNAL ;
    PORT
      LAYER M4 ;
        RECT 0.000 218.880 0.192 218.904 ;
    END
  END tx[155]
  PIN tx[156]
    DIRECTION OUTPUT ;
    USE SIGNAL ;
    PORT
      LAYER M4 ;
        RECT 0.000 219.168 0.192 219.192 ;
    END
  END tx[156]
  PIN tx[157]
    DIRECTION OUTPUT ;
    USE SIGNAL ;
    PORT
      LAYER M4 ;
        RECT 0.000 219.504 0.192 219.528 ;
    END
  END tx[157]
  PIN tx[158]
    DIRECTION OUTPUT ;
    USE SIGNAL ;
    PORT
      LAYER M4 ;
        RECT 0.000 219.840 0.192 219.864 ;
    END
  END tx[158]
  PIN tx[159]
    DIRECTION OUTPUT ;
    USE SIGNAL ;
    PORT
      LAYER M4 ;
        RECT 0.000 220.128 0.192 220.152 ;
    END
  END tx[159]
  PIN tx[160]
    DIRECTION OUTPUT ;
    USE SIGNAL ;
    PORT
      LAYER M4 ;
        RECT 0.000 220.464 0.192 220.488 ;
    END
  END tx[160]
  PIN tx[161]
    DIRECTION OUTPUT ;
    USE SIGNAL ;
    PORT
      LAYER M4 ;
        RECT 0.000 220.752 0.192 220.776 ;
    END
  END tx[161]
  PIN tx[162]
    DIRECTION OUTPUT ;
    USE SIGNAL ;
    PORT
      LAYER M4 ;
        RECT 0.000 221.088 0.192 221.112 ;
    END
  END tx[162]
  PIN tx[163]
    DIRECTION OUTPUT ;
    USE SIGNAL ;
    PORT
      LAYER M4 ;
        RECT 0.000 221.376 0.192 221.400 ;
    END
  END tx[163]
  PIN tx[164]
    DIRECTION OUTPUT ;
    USE SIGNAL ;
    PORT
      LAYER M4 ;
        RECT 0.000 221.712 0.192 221.736 ;
    END
  END tx[164]
  PIN tx[165]
    DIRECTION OUTPUT ;
    USE SIGNAL ;
    PORT
      LAYER M4 ;
        RECT 0.000 222.000 0.192 222.024 ;
    END
  END tx[165]
  PIN tx[166]
    DIRECTION OUTPUT ;
    USE SIGNAL ;
    PORT
      LAYER M4 ;
        RECT 0.000 222.336 0.192 222.360 ;
    END
  END tx[166]
  PIN tx[167]
    DIRECTION OUTPUT ;
    USE SIGNAL ;
    PORT
      LAYER M4 ;
        RECT 0.000 222.624 0.192 222.648 ;
    END
  END tx[167]
  PIN tx[168]
    DIRECTION OUTPUT ;
    USE SIGNAL ;
    PORT
      LAYER M4 ;
        RECT 0.000 222.960 0.192 222.984 ;
    END
  END tx[168]
  PIN tx[169]
    DIRECTION OUTPUT ;
    USE SIGNAL ;
    PORT
      LAYER M4 ;
        RECT 0.000 223.296 0.192 223.320 ;
    END
  END tx[169]
  PIN tx[170]
    DIRECTION OUTPUT ;
    USE SIGNAL ;
    PORT
      LAYER M4 ;
        RECT 0.000 223.584 0.192 223.608 ;
    END
  END tx[170]
  PIN tx[171]
    DIRECTION OUTPUT ;
    USE SIGNAL ;
    PORT
      LAYER M4 ;
        RECT 0.000 223.920 0.192 223.944 ;
    END
  END tx[171]
  PIN tx[172]
    DIRECTION OUTPUT ;
    USE SIGNAL ;
    PORT
      LAYER M4 ;
        RECT 0.000 224.208 0.192 224.232 ;
    END
  END tx[172]
  PIN tx[173]
    DIRECTION OUTPUT ;
    USE SIGNAL ;
    PORT
      LAYER M4 ;
        RECT 0.000 224.544 0.192 224.568 ;
    END
  END tx[173]
  PIN tx[174]
    DIRECTION OUTPUT ;
    USE SIGNAL ;
    PORT
      LAYER M4 ;
        RECT 0.000 224.832 0.192 224.856 ;
    END
  END tx[174]
  PIN tx[175]
    DIRECTION OUTPUT ;
    USE SIGNAL ;
    PORT
      LAYER M4 ;
        RECT 0.000 225.168 0.192 225.192 ;
    END
  END tx[175]
  PIN tx[176]
    DIRECTION OUTPUT ;
    USE SIGNAL ;
    PORT
      LAYER M4 ;
        RECT 0.000 225.456 0.192 225.480 ;
    END
  END tx[176]
  PIN tx[177]
    DIRECTION OUTPUT ;
    USE SIGNAL ;
    PORT
      LAYER M4 ;
        RECT 0.000 225.792 0.192 225.816 ;
    END
  END tx[177]
  PIN tx[178]
    DIRECTION OUTPUT ;
    USE SIGNAL ;
    PORT
      LAYER M4 ;
        RECT 0.000 226.080 0.192 226.104 ;
    END
  END tx[178]
  PIN tx[179]
    DIRECTION OUTPUT ;
    USE SIGNAL ;
    PORT
      LAYER M4 ;
        RECT 0.000 226.416 0.192 226.440 ;
    END
  END tx[179]
  PIN tx[180]
    DIRECTION OUTPUT ;
    USE SIGNAL ;
    PORT
      LAYER M4 ;
        RECT 0.000 226.752 0.192 226.776 ;
    END
  END tx[180]
  PIN tx[181]
    DIRECTION OUTPUT ;
    USE SIGNAL ;
    PORT
      LAYER M4 ;
        RECT 0.000 227.040 0.192 227.064 ;
    END
  END tx[181]
  PIN tx[182]
    DIRECTION OUTPUT ;
    USE SIGNAL ;
    PORT
      LAYER M4 ;
        RECT 0.000 227.376 0.192 227.400 ;
    END
  END tx[182]
  PIN tx[183]
    DIRECTION OUTPUT ;
    USE SIGNAL ;
    PORT
      LAYER M4 ;
        RECT 0.000 227.664 0.192 227.688 ;
    END
  END tx[183]
  PIN tx[184]
    DIRECTION OUTPUT ;
    USE SIGNAL ;
    PORT
      LAYER M4 ;
        RECT 0.000 228.000 0.192 228.024 ;
    END
  END tx[184]
  PIN tx[185]
    DIRECTION OUTPUT ;
    USE SIGNAL ;
    PORT
      LAYER M4 ;
        RECT 0.000 228.288 0.192 228.312 ;
    END
  END tx[185]
  PIN tx[186]
    DIRECTION OUTPUT ;
    USE SIGNAL ;
    PORT
      LAYER M4 ;
        RECT 0.000 228.624 0.192 228.648 ;
    END
  END tx[186]
  PIN tx[187]
    DIRECTION OUTPUT ;
    USE SIGNAL ;
    PORT
      LAYER M4 ;
        RECT 0.000 228.912 0.192 228.936 ;
    END
  END tx[187]
  PIN tx[188]
    DIRECTION OUTPUT ;
    USE SIGNAL ;
    PORT
      LAYER M4 ;
        RECT 0.000 229.248 0.192 229.272 ;
    END
  END tx[188]
  PIN tx[189]
    DIRECTION OUTPUT ;
    USE SIGNAL ;
    PORT
      LAYER M4 ;
        RECT 0.000 229.584 0.192 229.608 ;
    END
  END tx[189]
  PIN tx[190]
    DIRECTION OUTPUT ;
    USE SIGNAL ;
    PORT
      LAYER M4 ;
        RECT 0.000 229.872 0.192 229.896 ;
    END
  END tx[190]
  PIN tx[191]
    DIRECTION OUTPUT ;
    USE SIGNAL ;
    PORT
      LAYER M4 ;
        RECT 0.000 230.208 0.192 230.232 ;
    END
  END tx[191]
  PIN tx[192]
    DIRECTION OUTPUT ;
    USE SIGNAL ;
    PORT
      LAYER M4 ;
        RECT 0.000 230.496 0.192 230.520 ;
    END
  END tx[192]
  PIN tx[193]
    DIRECTION OUTPUT ;
    USE SIGNAL ;
    PORT
      LAYER M4 ;
        RECT 0.000 230.832 0.192 230.856 ;
    END
  END tx[193]
  PIN tx[194]
    DIRECTION OUTPUT ;
    USE SIGNAL ;
    PORT
      LAYER M4 ;
        RECT 0.000 231.120 0.192 231.144 ;
    END
  END tx[194]
  PIN tx[195]
    DIRECTION OUTPUT ;
    USE SIGNAL ;
    PORT
      LAYER M4 ;
        RECT 0.000 231.456 0.192 231.480 ;
    END
  END tx[195]
  PIN tx[196]
    DIRECTION OUTPUT ;
    USE SIGNAL ;
    PORT
      LAYER M4 ;
        RECT 0.000 231.744 0.192 231.768 ;
    END
  END tx[196]
  PIN tx[197]
    DIRECTION OUTPUT ;
    USE SIGNAL ;
    PORT
      LAYER M4 ;
        RECT 0.000 232.080 0.192 232.104 ;
    END
  END tx[197]
  PIN tx[198]
    DIRECTION OUTPUT ;
    USE SIGNAL ;
    PORT
      LAYER M4 ;
        RECT 0.000 232.368 0.192 232.392 ;
    END
  END tx[198]
  PIN tx[199]
    DIRECTION OUTPUT ;
    USE SIGNAL ;
    PORT
      LAYER M4 ;
        RECT 0.000 232.704 0.192 232.728 ;
    END
  END tx[199]
  PIN tx[200]
    DIRECTION OUTPUT ;
    USE SIGNAL ;
    PORT
      LAYER M4 ;
        RECT 0.000 233.040 0.192 233.064 ;
    END
  END tx[200]
  PIN tx[201]
    DIRECTION OUTPUT ;
    USE SIGNAL ;
    PORT
      LAYER M4 ;
        RECT 0.000 233.328 0.192 233.352 ;
    END
  END tx[201]
  PIN tx[202]
    DIRECTION OUTPUT ;
    USE SIGNAL ;
    PORT
      LAYER M4 ;
        RECT 0.000 233.664 0.192 233.688 ;
    END
  END tx[202]
  PIN tx[203]
    DIRECTION OUTPUT ;
    USE SIGNAL ;
    PORT
      LAYER M4 ;
        RECT 0.000 233.952 0.192 233.976 ;
    END
  END tx[203]
  PIN tx[204]
    DIRECTION OUTPUT ;
    USE SIGNAL ;
    PORT
      LAYER M4 ;
        RECT 0.000 234.288 0.192 234.312 ;
    END
  END tx[204]
  PIN tx[205]
    DIRECTION OUTPUT ;
    USE SIGNAL ;
    PORT
      LAYER M4 ;
        RECT 0.000 234.576 0.192 234.600 ;
    END
  END tx[205]
  PIN tx[206]
    DIRECTION OUTPUT ;
    USE SIGNAL ;
    PORT
      LAYER M4 ;
        RECT 0.000 234.912 0.192 234.936 ;
    END
  END tx[206]
  PIN tx[207]
    DIRECTION OUTPUT ;
    USE SIGNAL ;
    PORT
      LAYER M4 ;
        RECT 0.000 235.200 0.192 235.224 ;
    END
  END tx[207]
  PIN tx[208]
    DIRECTION OUTPUT ;
    USE SIGNAL ;
    PORT
      LAYER M4 ;
        RECT 0.000 235.536 0.192 235.560 ;
    END
  END tx[208]
  PIN tx[209]
    DIRECTION OUTPUT ;
    USE SIGNAL ;
    PORT
      LAYER M4 ;
        RECT 0.000 235.872 0.192 235.896 ;
    END
  END tx[209]
  PIN tx[210]
    DIRECTION OUTPUT ;
    USE SIGNAL ;
    PORT
      LAYER M4 ;
        RECT 0.000 236.160 0.192 236.184 ;
    END
  END tx[210]
  PIN tx[211]
    DIRECTION OUTPUT ;
    USE SIGNAL ;
    PORT
      LAYER M4 ;
        RECT 0.000 236.496 0.192 236.520 ;
    END
  END tx[211]
  PIN tx[212]
    DIRECTION OUTPUT ;
    USE SIGNAL ;
    PORT
      LAYER M4 ;
        RECT 0.000 236.784 0.192 236.808 ;
    END
  END tx[212]
  PIN tx[213]
    DIRECTION OUTPUT ;
    USE SIGNAL ;
    PORT
      LAYER M4 ;
        RECT 0.000 237.120 0.192 237.144 ;
    END
  END tx[213]
  PIN tx[214]
    DIRECTION OUTPUT ;
    USE SIGNAL ;
    PORT
      LAYER M4 ;
        RECT 0.000 237.408 0.192 237.432 ;
    END
  END tx[214]
  PIN tx[215]
    DIRECTION OUTPUT ;
    USE SIGNAL ;
    PORT
      LAYER M4 ;
        RECT 0.000 237.744 0.192 237.768 ;
    END
  END tx[215]
  PIN tx[216]
    DIRECTION OUTPUT ;
    USE SIGNAL ;
    PORT
      LAYER M4 ;
        RECT 0.000 238.032 0.192 238.056 ;
    END
  END tx[216]
  PIN tx[217]
    DIRECTION OUTPUT ;
    USE SIGNAL ;
    PORT
      LAYER M4 ;
        RECT 0.000 238.368 0.192 238.392 ;
    END
  END tx[217]
  PIN tx[218]
    DIRECTION OUTPUT ;
    USE SIGNAL ;
    PORT
      LAYER M4 ;
        RECT 0.000 238.656 0.192 238.680 ;
    END
  END tx[218]
  PIN tx[219]
    DIRECTION OUTPUT ;
    USE SIGNAL ;
    PORT
      LAYER M4 ;
        RECT 0.000 238.992 0.192 239.016 ;
    END
  END tx[219]
  PIN tx[220]
    DIRECTION OUTPUT ;
    USE SIGNAL ;
    PORT
      LAYER M4 ;
        RECT 0.000 239.328 0.192 239.352 ;
    END
  END tx[220]
  PIN tx[221]
    DIRECTION OUTPUT ;
    USE SIGNAL ;
    PORT
      LAYER M4 ;
        RECT 0.000 239.616 0.192 239.640 ;
    END
  END tx[221]
  PIN tx[222]
    DIRECTION OUTPUT ;
    USE SIGNAL ;
    PORT
      LAYER M4 ;
        RECT 0.000 239.952 0.192 239.976 ;
    END
  END tx[222]
  PIN tx[223]
    DIRECTION OUTPUT ;
    USE SIGNAL ;
    PORT
      LAYER M4 ;
        RECT 0.000 240.240 0.192 240.264 ;
    END
  END tx[223]
  PIN tx[224]
    DIRECTION OUTPUT ;
    USE SIGNAL ;
    PORT
      LAYER M4 ;
        RECT 0.000 240.576 0.192 240.600 ;
    END
  END tx[224]
  PIN tx[225]
    DIRECTION OUTPUT ;
    USE SIGNAL ;
    PORT
      LAYER M4 ;
        RECT 0.000 240.864 0.192 240.888 ;
    END
  END tx[225]
  PIN tx[226]
    DIRECTION OUTPUT ;
    USE SIGNAL ;
    PORT
      LAYER M4 ;
        RECT 0.000 241.200 0.192 241.224 ;
    END
  END tx[226]
  PIN tx[227]
    DIRECTION OUTPUT ;
    USE SIGNAL ;
    PORT
      LAYER M4 ;
        RECT 0.000 241.488 0.192 241.512 ;
    END
  END tx[227]
  PIN tx[228]
    DIRECTION OUTPUT ;
    USE SIGNAL ;
    PORT
      LAYER M4 ;
        RECT 0.000 241.824 0.192 241.848 ;
    END
  END tx[228]
  PIN tx[229]
    DIRECTION OUTPUT ;
    USE SIGNAL ;
    PORT
      LAYER M4 ;
        RECT 0.000 242.160 0.192 242.184 ;
    END
  END tx[229]
  PIN tx[230]
    DIRECTION OUTPUT ;
    USE SIGNAL ;
    PORT
      LAYER M4 ;
        RECT 0.000 242.448 0.192 242.472 ;
    END
  END tx[230]
  PIN tx[231]
    DIRECTION OUTPUT ;
    USE SIGNAL ;
    PORT
      LAYER M4 ;
        RECT 0.000 242.784 0.192 242.808 ;
    END
  END tx[231]
  PIN tx[232]
    DIRECTION OUTPUT ;
    USE SIGNAL ;
    PORT
      LAYER M4 ;
        RECT 0.000 243.072 0.192 243.096 ;
    END
  END tx[232]
  PIN tx[233]
    DIRECTION OUTPUT ;
    USE SIGNAL ;
    PORT
      LAYER M4 ;
        RECT 0.000 243.408 0.192 243.432 ;
    END
  END tx[233]
  PIN tx[234]
    DIRECTION OUTPUT ;
    USE SIGNAL ;
    PORT
      LAYER M4 ;
        RECT 0.000 243.696 0.192 243.720 ;
    END
  END tx[234]
  PIN tx[235]
    DIRECTION OUTPUT ;
    USE SIGNAL ;
    PORT
      LAYER M4 ;
        RECT 0.000 244.032 0.192 244.056 ;
    END
  END tx[235]
  PIN tx[236]
    DIRECTION OUTPUT ;
    USE SIGNAL ;
    PORT
      LAYER M4 ;
        RECT 0.000 244.320 0.192 244.344 ;
    END
  END tx[236]
  PIN tx[237]
    DIRECTION OUTPUT ;
    USE SIGNAL ;
    PORT
      LAYER M4 ;
        RECT 0.000 244.656 0.192 244.680 ;
    END
  END tx[237]
  PIN tx[238]
    DIRECTION OUTPUT ;
    USE SIGNAL ;
    PORT
      LAYER M4 ;
        RECT 0.000 244.944 0.192 244.968 ;
    END
  END tx[238]
  PIN tx[239]
    DIRECTION OUTPUT ;
    USE SIGNAL ;
    PORT
      LAYER M4 ;
        RECT 0.000 245.280 0.192 245.304 ;
    END
  END tx[239]
  PIN tx[240]
    DIRECTION OUTPUT ;
    USE SIGNAL ;
    PORT
      LAYER M4 ;
        RECT 0.000 245.616 0.192 245.640 ;
    END
  END tx[240]
  PIN tx[241]
    DIRECTION OUTPUT ;
    USE SIGNAL ;
    PORT
      LAYER M4 ;
        RECT 0.000 245.904 0.192 245.928 ;
    END
  END tx[241]
  PIN tx[242]
    DIRECTION OUTPUT ;
    USE SIGNAL ;
    PORT
      LAYER M4 ;
        RECT 0.000 246.240 0.192 246.264 ;
    END
  END tx[242]
  PIN tx[243]
    DIRECTION OUTPUT ;
    USE SIGNAL ;
    PORT
      LAYER M4 ;
        RECT 0.000 246.528 0.192 246.552 ;
    END
  END tx[243]
  PIN tx[244]
    DIRECTION OUTPUT ;
    USE SIGNAL ;
    PORT
      LAYER M4 ;
        RECT 0.000 246.864 0.192 246.888 ;
    END
  END tx[244]
  PIN tx[245]
    DIRECTION OUTPUT ;
    USE SIGNAL ;
    PORT
      LAYER M4 ;
        RECT 0.000 247.152 0.192 247.176 ;
    END
  END tx[245]
  PIN tx[246]
    DIRECTION OUTPUT ;
    USE SIGNAL ;
    PORT
      LAYER M4 ;
        RECT 0.000 247.488 0.192 247.512 ;
    END
  END tx[246]
  PIN tx[247]
    DIRECTION OUTPUT ;
    USE SIGNAL ;
    PORT
      LAYER M4 ;
        RECT 0.000 247.776 0.192 247.800 ;
    END
  END tx[247]
  PIN tx[248]
    DIRECTION OUTPUT ;
    USE SIGNAL ;
    PORT
      LAYER M4 ;
        RECT 0.000 248.112 0.192 248.136 ;
    END
  END tx[248]
  PIN tx[249]
    DIRECTION OUTPUT ;
    USE SIGNAL ;
    PORT
      LAYER M4 ;
        RECT 0.000 248.448 0.192 248.472 ;
    END
  END tx[249]
  PIN tx[250]
    DIRECTION OUTPUT ;
    USE SIGNAL ;
    PORT
      LAYER M4 ;
        RECT 0.000 248.736 0.192 248.760 ;
    END
  END tx[250]
  PIN tx[251]
    DIRECTION OUTPUT ;
    USE SIGNAL ;
    PORT
      LAYER M4 ;
        RECT 0.000 249.072 0.192 249.096 ;
    END
  END tx[251]
  PIN tx[252]
    DIRECTION OUTPUT ;
    USE SIGNAL ;
    PORT
      LAYER M4 ;
        RECT 0.000 249.360 0.192 249.384 ;
    END
  END tx[252]
  PIN tx[253]
    DIRECTION OUTPUT ;
    USE SIGNAL ;
    PORT
      LAYER M4 ;
        RECT 0.000 249.696 0.192 249.720 ;
    END
  END tx[253]
  PIN tx[254]
    DIRECTION OUTPUT ;
    USE SIGNAL ;
    PORT
      LAYER M4 ;
        RECT 0.000 249.984 0.192 250.008 ;
    END
  END tx[254]
  PIN tx[255]
    DIRECTION OUTPUT ;
    USE SIGNAL ;
    PORT
      LAYER M4 ;
        RECT 0.000 250.320 0.192 250.344 ;
    END
  END tx[255]
  PIN tx[256]
    DIRECTION OUTPUT ;
    USE SIGNAL ;
    PORT
      LAYER M4 ;
        RECT 0.000 250.608 0.192 250.632 ;
    END
  END tx[256]
  PIN tx[257]
    DIRECTION OUTPUT ;
    USE SIGNAL ;
    PORT
      LAYER M4 ;
        RECT 0.000 250.944 0.192 250.968 ;
    END
  END tx[257]
  PIN tx[258]
    DIRECTION OUTPUT ;
    USE SIGNAL ;
    PORT
      LAYER M4 ;
        RECT 0.000 251.232 0.192 251.256 ;
    END
  END tx[258]
  PIN tx[259]
    DIRECTION OUTPUT ;
    USE SIGNAL ;
    PORT
      LAYER M4 ;
        RECT 0.000 251.568 0.192 251.592 ;
    END
  END tx[259]
  PIN tx[260]
    DIRECTION OUTPUT ;
    USE SIGNAL ;
    PORT
      LAYER M4 ;
        RECT 0.000 251.904 0.192 251.928 ;
    END
  END tx[260]
  PIN tx[261]
    DIRECTION OUTPUT ;
    USE SIGNAL ;
    PORT
      LAYER M4 ;
        RECT 0.000 252.192 0.192 252.216 ;
    END
  END tx[261]
  PIN tx[262]
    DIRECTION OUTPUT ;
    USE SIGNAL ;
    PORT
      LAYER M4 ;
        RECT 0.000 252.528 0.192 252.552 ;
    END
  END tx[262]
  PIN tx[263]
    DIRECTION OUTPUT ;
    USE SIGNAL ;
    PORT
      LAYER M4 ;
        RECT 0.000 252.816 0.192 252.840 ;
    END
  END tx[263]
  PIN tx[264]
    DIRECTION OUTPUT ;
    USE SIGNAL ;
    PORT
      LAYER M4 ;
        RECT 0.000 253.152 0.192 253.176 ;
    END
  END tx[264]
  PIN tx[265]
    DIRECTION OUTPUT ;
    USE SIGNAL ;
    PORT
      LAYER M4 ;
        RECT 0.000 253.440 0.192 253.464 ;
    END
  END tx[265]
  PIN tx[266]
    DIRECTION OUTPUT ;
    USE SIGNAL ;
    PORT
      LAYER M4 ;
        RECT 0.000 253.776 0.192 253.800 ;
    END
  END tx[266]
  PIN tx[267]
    DIRECTION OUTPUT ;
    USE SIGNAL ;
    PORT
      LAYER M4 ;
        RECT 0.000 254.064 0.192 254.088 ;
    END
  END tx[267]
  PIN tx[268]
    DIRECTION OUTPUT ;
    USE SIGNAL ;
    PORT
      LAYER M4 ;
        RECT 0.000 254.400 0.192 254.424 ;
    END
  END tx[268]
  PIN tx[269]
    DIRECTION OUTPUT ;
    USE SIGNAL ;
    PORT
      LAYER M4 ;
        RECT 0.000 254.736 0.192 254.760 ;
    END
  END tx[269]
  PIN tx[270]
    DIRECTION OUTPUT ;
    USE SIGNAL ;
    PORT
      LAYER M4 ;
        RECT 0.000 255.024 0.192 255.048 ;
    END
  END tx[270]
  PIN tx[271]
    DIRECTION OUTPUT ;
    USE SIGNAL ;
    PORT
      LAYER M4 ;
        RECT 0.000 255.360 0.192 255.384 ;
    END
  END tx[271]
  PIN tx[272]
    DIRECTION OUTPUT ;
    USE SIGNAL ;
    PORT
      LAYER M4 ;
        RECT 0.000 255.648 0.192 255.672 ;
    END
  END tx[272]
  PIN tx[273]
    DIRECTION OUTPUT ;
    USE SIGNAL ;
    PORT
      LAYER M4 ;
        RECT 0.000 255.984 0.192 256.008 ;
    END
  END tx[273]
  PIN tx[274]
    DIRECTION OUTPUT ;
    USE SIGNAL ;
    PORT
      LAYER M4 ;
        RECT 0.000 256.272 0.192 256.296 ;
    END
  END tx[274]
  PIN tx[275]
    DIRECTION OUTPUT ;
    USE SIGNAL ;
    PORT
      LAYER M4 ;
        RECT 0.000 256.608 0.192 256.632 ;
    END
  END tx[275]
  PIN tx[276]
    DIRECTION OUTPUT ;
    USE SIGNAL ;
    PORT
      LAYER M4 ;
        RECT 0.000 256.896 0.192 256.920 ;
    END
  END tx[276]
  PIN tx[277]
    DIRECTION OUTPUT ;
    USE SIGNAL ;
    PORT
      LAYER M4 ;
        RECT 0.000 257.232 0.192 257.256 ;
    END
  END tx[277]
  PIN tx[278]
    DIRECTION OUTPUT ;
    USE SIGNAL ;
    PORT
      LAYER M4 ;
        RECT 0.000 257.520 0.192 257.544 ;
    END
  END tx[278]
  PIN tx[279]
    DIRECTION OUTPUT ;
    USE SIGNAL ;
    PORT
      LAYER M4 ;
        RECT 0.000 257.856 0.192 257.880 ;
    END
  END tx[279]
  PIN tx[280]
    DIRECTION OUTPUT ;
    USE SIGNAL ;
    PORT
      LAYER M4 ;
        RECT 0.000 258.192 0.192 258.216 ;
    END
  END tx[280]
  PIN tx[281]
    DIRECTION OUTPUT ;
    USE SIGNAL ;
    PORT
      LAYER M4 ;
        RECT 0.000 258.480 0.192 258.504 ;
    END
  END tx[281]
  PIN tx[282]
    DIRECTION OUTPUT ;
    USE SIGNAL ;
    PORT
      LAYER M4 ;
        RECT 0.000 258.816 0.192 258.840 ;
    END
  END tx[282]
  PIN tx[283]
    DIRECTION OUTPUT ;
    USE SIGNAL ;
    PORT
      LAYER M4 ;
        RECT 0.000 259.104 0.192 259.128 ;
    END
  END tx[283]
  PIN tx[284]
    DIRECTION OUTPUT ;
    USE SIGNAL ;
    PORT
      LAYER M4 ;
        RECT 0.000 259.440 0.192 259.464 ;
    END
  END tx[284]
  PIN tx[285]
    DIRECTION OUTPUT ;
    USE SIGNAL ;
    PORT
      LAYER M4 ;
        RECT 0.000 259.728 0.192 259.752 ;
    END
  END tx[285]
  PIN tx[286]
    DIRECTION OUTPUT ;
    USE SIGNAL ;
    PORT
      LAYER M4 ;
        RECT 0.000 260.064 0.192 260.088 ;
    END
  END tx[286]
  PIN tx[287]
    DIRECTION OUTPUT ;
    USE SIGNAL ;
    PORT
      LAYER M4 ;
        RECT 0.000 260.352 0.192 260.376 ;
    END
  END tx[287]
  PIN tx[288]
    DIRECTION OUTPUT ;
    USE SIGNAL ;
    PORT
      LAYER M4 ;
        RECT 0.000 260.688 0.192 260.712 ;
    END
  END tx[288]
  PIN tx[289]
    DIRECTION OUTPUT ;
    USE SIGNAL ;
    PORT
      LAYER M4 ;
        RECT 0.000 260.976 0.192 261.000 ;
    END
  END tx[289]
  PIN tx[290]
    DIRECTION OUTPUT ;
    USE SIGNAL ;
    PORT
      LAYER M4 ;
        RECT 0.000 261.312 0.192 261.336 ;
    END
  END tx[290]
  PIN tx[291]
    DIRECTION OUTPUT ;
    USE SIGNAL ;
    PORT
      LAYER M4 ;
        RECT 0.000 261.648 0.192 261.672 ;
    END
  END tx[291]
  PIN tx[292]
    DIRECTION OUTPUT ;
    USE SIGNAL ;
    PORT
      LAYER M4 ;
        RECT 0.000 261.936 0.192 261.960 ;
    END
  END tx[292]
  PIN tx[293]
    DIRECTION OUTPUT ;
    USE SIGNAL ;
    PORT
      LAYER M4 ;
        RECT 0.000 262.272 0.192 262.296 ;
    END
  END tx[293]
  PIN tx[294]
    DIRECTION OUTPUT ;
    USE SIGNAL ;
    PORT
      LAYER M4 ;
        RECT 0.000 262.560 0.192 262.584 ;
    END
  END tx[294]
  PIN tx[295]
    DIRECTION OUTPUT ;
    USE SIGNAL ;
    PORT
      LAYER M4 ;
        RECT 0.000 262.896 0.192 262.920 ;
    END
  END tx[295]
  PIN tx[296]
    DIRECTION OUTPUT ;
    USE SIGNAL ;
    PORT
      LAYER M4 ;
        RECT 0.000 263.184 0.192 263.208 ;
    END
  END tx[296]
  PIN tx[297]
    DIRECTION OUTPUT ;
    USE SIGNAL ;
    PORT
      LAYER M4 ;
        RECT 0.000 263.520 0.192 263.544 ;
    END
  END tx[297]
  PIN tx[298]
    DIRECTION OUTPUT ;
    USE SIGNAL ;
    PORT
      LAYER M4 ;
        RECT 0.000 263.808 0.192 263.832 ;
    END
  END tx[298]
  PIN tx[299]
    DIRECTION OUTPUT ;
    USE SIGNAL ;
    PORT
      LAYER M4 ;
        RECT 0.000 264.144 0.192 264.168 ;
    END
  END tx[299]
  PIN tx[300]
    DIRECTION OUTPUT ;
    USE SIGNAL ;
    PORT
      LAYER M4 ;
        RECT 0.000 264.480 0.192 264.504 ;
    END
  END tx[300]
  PIN tx[301]
    DIRECTION OUTPUT ;
    USE SIGNAL ;
    PORT
      LAYER M4 ;
        RECT 0.000 264.768 0.192 264.792 ;
    END
  END tx[301]
  PIN tx[302]
    DIRECTION OUTPUT ;
    USE SIGNAL ;
    PORT
      LAYER M4 ;
        RECT 0.000 265.104 0.192 265.128 ;
    END
  END tx[302]
  PIN tx[303]
    DIRECTION OUTPUT ;
    USE SIGNAL ;
    PORT
      LAYER M4 ;
        RECT 0.000 265.392 0.192 265.416 ;
    END
  END tx[303]
  PIN tx[304]
    DIRECTION OUTPUT ;
    USE SIGNAL ;
    PORT
      LAYER M4 ;
        RECT 0.000 265.728 0.192 265.752 ;
    END
  END tx[304]
  PIN tx[305]
    DIRECTION OUTPUT ;
    USE SIGNAL ;
    PORT
      LAYER M4 ;
        RECT 0.000 266.016 0.192 266.040 ;
    END
  END tx[305]
  PIN tx[306]
    DIRECTION OUTPUT ;
    USE SIGNAL ;
    PORT
      LAYER M4 ;
        RECT 0.000 266.352 0.192 266.376 ;
    END
  END tx[306]
  PIN tx[307]
    DIRECTION OUTPUT ;
    USE SIGNAL ;
    PORT
      LAYER M4 ;
        RECT 0.000 266.640 0.192 266.664 ;
    END
  END tx[307]
  PIN tx[308]
    DIRECTION OUTPUT ;
    USE SIGNAL ;
    PORT
      LAYER M4 ;
        RECT 0.000 266.976 0.192 267.000 ;
    END
  END tx[308]
  PIN tx[309]
    DIRECTION OUTPUT ;
    USE SIGNAL ;
    PORT
      LAYER M4 ;
        RECT 0.000 267.264 0.192 267.288 ;
    END
  END tx[309]
  PIN tx[310]
    DIRECTION OUTPUT ;
    USE SIGNAL ;
    PORT
      LAYER M4 ;
        RECT 0.000 267.600 0.192 267.624 ;
    END
  END tx[310]
  PIN tx[311]
    DIRECTION OUTPUT ;
    USE SIGNAL ;
    PORT
      LAYER M4 ;
        RECT 0.000 267.936 0.192 267.960 ;
    END
  END tx[311]
  PIN tx[312]
    DIRECTION OUTPUT ;
    USE SIGNAL ;
    PORT
      LAYER M4 ;
        RECT 0.000 268.224 0.192 268.248 ;
    END
  END tx[312]
  PIN tx[313]
    DIRECTION OUTPUT ;
    USE SIGNAL ;
    PORT
      LAYER M4 ;
        RECT 0.000 268.560 0.192 268.584 ;
    END
  END tx[313]
  PIN tx[314]
    DIRECTION OUTPUT ;
    USE SIGNAL ;
    PORT
      LAYER M4 ;
        RECT 0.000 268.848 0.192 268.872 ;
    END
  END tx[314]
  PIN tx[315]
    DIRECTION OUTPUT ;
    USE SIGNAL ;
    PORT
      LAYER M4 ;
        RECT 0.000 269.184 0.192 269.208 ;
    END
  END tx[315]
  PIN tx[316]
    DIRECTION OUTPUT ;
    USE SIGNAL ;
    PORT
      LAYER M4 ;
        RECT 0.000 269.472 0.192 269.496 ;
    END
  END tx[316]
  PIN tx[317]
    DIRECTION OUTPUT ;
    USE SIGNAL ;
    PORT
      LAYER M4 ;
        RECT 0.000 269.808 0.192 269.832 ;
    END
  END tx[317]
  PIN tx[318]
    DIRECTION OUTPUT ;
    USE SIGNAL ;
    PORT
      LAYER M4 ;
        RECT 0.000 270.096 0.192 270.120 ;
    END
  END tx[318]
  PIN tx[319]
    DIRECTION OUTPUT ;
    USE SIGNAL ;
    PORT
      LAYER M4 ;
        RECT 0.000 270.432 0.192 270.456 ;
    END
  END tx[319]
  PIN tx[320]
    DIRECTION OUTPUT ;
    USE SIGNAL ;
    PORT
      LAYER M4 ;
        RECT 0.000 270.768 0.192 270.792 ;
    END
  END tx[320]
  PIN tx[321]
    DIRECTION OUTPUT ;
    USE SIGNAL ;
    PORT
      LAYER M4 ;
        RECT 0.000 271.056 0.192 271.080 ;
    END
  END tx[321]
  PIN tx[322]
    DIRECTION OUTPUT ;
    USE SIGNAL ;
    PORT
      LAYER M4 ;
        RECT 0.000 271.392 0.192 271.416 ;
    END
  END tx[322]
  PIN tx[323]
    DIRECTION OUTPUT ;
    USE SIGNAL ;
    PORT
      LAYER M4 ;
        RECT 0.000 271.680 0.192 271.704 ;
    END
  END tx[323]
  PIN tx[324]
    DIRECTION OUTPUT ;
    USE SIGNAL ;
    PORT
      LAYER M4 ;
        RECT 0.000 272.016 0.192 272.040 ;
    END
  END tx[324]
  PIN tx[325]
    DIRECTION OUTPUT ;
    USE SIGNAL ;
    PORT
      LAYER M4 ;
        RECT 0.000 272.304 0.192 272.328 ;
    END
  END tx[325]
  PIN tx[326]
    DIRECTION OUTPUT ;
    USE SIGNAL ;
    PORT
      LAYER M4 ;
        RECT 0.000 272.640 0.192 272.664 ;
    END
  END tx[326]
  PIN tx[327]
    DIRECTION OUTPUT ;
    USE SIGNAL ;
    PORT
      LAYER M4 ;
        RECT 0.000 272.928 0.192 272.952 ;
    END
  END tx[327]
  PIN tx[328]
    DIRECTION OUTPUT ;
    USE SIGNAL ;
    PORT
      LAYER M4 ;
        RECT 0.000 273.264 0.192 273.288 ;
    END
  END tx[328]
  PIN tx[329]
    DIRECTION OUTPUT ;
    USE SIGNAL ;
    PORT
      LAYER M4 ;
        RECT 0.000 273.552 0.192 273.576 ;
    END
  END tx[329]
  PIN tx[330]
    DIRECTION OUTPUT ;
    USE SIGNAL ;
    PORT
      LAYER M4 ;
        RECT 0.000 273.888 0.192 273.912 ;
    END
  END tx[330]
  PIN tx[331]
    DIRECTION OUTPUT ;
    USE SIGNAL ;
    PORT
      LAYER M4 ;
        RECT 0.000 274.224 0.192 274.248 ;
    END
  END tx[331]
  PIN tx[332]
    DIRECTION OUTPUT ;
    USE SIGNAL ;
    PORT
      LAYER M4 ;
        RECT 0.000 274.512 0.192 274.536 ;
    END
  END tx[332]
  PIN tx[333]
    DIRECTION OUTPUT ;
    USE SIGNAL ;
    PORT
      LAYER M4 ;
        RECT 0.000 274.848 0.192 274.872 ;
    END
  END tx[333]
  PIN tx[334]
    DIRECTION OUTPUT ;
    USE SIGNAL ;
    PORT
      LAYER M4 ;
        RECT 0.000 275.136 0.192 275.160 ;
    END
  END tx[334]
  PIN tx[335]
    DIRECTION OUTPUT ;
    USE SIGNAL ;
    PORT
      LAYER M4 ;
        RECT 0.000 275.472 0.192 275.496 ;
    END
  END tx[335]
  PIN tx[336]
    DIRECTION OUTPUT ;
    USE SIGNAL ;
    PORT
      LAYER M4 ;
        RECT 0.000 275.760 0.192 275.784 ;
    END
  END tx[336]
  PIN tx[337]
    DIRECTION OUTPUT ;
    USE SIGNAL ;
    PORT
      LAYER M4 ;
        RECT 0.000 276.096 0.192 276.120 ;
    END
  END tx[337]
  PIN tx[338]
    DIRECTION OUTPUT ;
    USE SIGNAL ;
    PORT
      LAYER M4 ;
        RECT 0.000 276.384 0.192 276.408 ;
    END
  END tx[338]
  PIN tx[339]
    DIRECTION OUTPUT ;
    USE SIGNAL ;
    PORT
      LAYER M4 ;
        RECT 0.000 276.720 0.192 276.744 ;
    END
  END tx[339]
  PIN tx[340]
    DIRECTION OUTPUT ;
    USE SIGNAL ;
    PORT
      LAYER M4 ;
        RECT 0.000 277.056 0.192 277.080 ;
    END
  END tx[340]
  PIN tx[341]
    DIRECTION OUTPUT ;
    USE SIGNAL ;
    PORT
      LAYER M4 ;
        RECT 0.000 277.344 0.192 277.368 ;
    END
  END tx[341]
  PIN tx[342]
    DIRECTION OUTPUT ;
    USE SIGNAL ;
    PORT
      LAYER M4 ;
        RECT 0.000 277.680 0.192 277.704 ;
    END
  END tx[342]
  PIN tx[343]
    DIRECTION OUTPUT ;
    USE SIGNAL ;
    PORT
      LAYER M4 ;
        RECT 0.000 277.968 0.192 277.992 ;
    END
  END tx[343]
  PIN tx[344]
    DIRECTION OUTPUT ;
    USE SIGNAL ;
    PORT
      LAYER M4 ;
        RECT 0.000 278.304 0.192 278.328 ;
    END
  END tx[344]
  PIN tx[345]
    DIRECTION OUTPUT ;
    USE SIGNAL ;
    PORT
      LAYER M4 ;
        RECT 0.000 278.592 0.192 278.616 ;
    END
  END tx[345]
  PIN tx[346]
    DIRECTION OUTPUT ;
    USE SIGNAL ;
    PORT
      LAYER M4 ;
        RECT 0.000 278.928 0.192 278.952 ;
    END
  END tx[346]
  PIN tx[347]
    DIRECTION OUTPUT ;
    USE SIGNAL ;
    PORT
      LAYER M4 ;
        RECT 0.000 279.216 0.192 279.240 ;
    END
  END tx[347]
  PIN tx[348]
    DIRECTION OUTPUT ;
    USE SIGNAL ;
    PORT
      LAYER M4 ;
        RECT 0.000 279.552 0.192 279.576 ;
    END
  END tx[348]
  PIN tx[349]
    DIRECTION OUTPUT ;
    USE SIGNAL ;
    PORT
      LAYER M4 ;
        RECT 0.000 279.840 0.192 279.864 ;
    END
  END tx[349]
  PIN tx[350]
    DIRECTION OUTPUT ;
    USE SIGNAL ;
    PORT
      LAYER M4 ;
        RECT 0.000 280.176 0.192 280.200 ;
    END
  END tx[350]
  PIN tx[351]
    DIRECTION OUTPUT ;
    USE SIGNAL ;
    PORT
      LAYER M4 ;
        RECT 0.000 280.512 0.192 280.536 ;
    END
  END tx[351]
  PIN tx[352]
    DIRECTION OUTPUT ;
    USE SIGNAL ;
    PORT
      LAYER M4 ;
        RECT 0.000 280.800 0.192 280.824 ;
    END
  END tx[352]
  PIN tx[353]
    DIRECTION OUTPUT ;
    USE SIGNAL ;
    PORT
      LAYER M4 ;
        RECT 0.000 281.136 0.192 281.160 ;
    END
  END tx[353]
  PIN tx[354]
    DIRECTION OUTPUT ;
    USE SIGNAL ;
    PORT
      LAYER M4 ;
        RECT 0.000 281.424 0.192 281.448 ;
    END
  END tx[354]
  PIN tx[355]
    DIRECTION OUTPUT ;
    USE SIGNAL ;
    PORT
      LAYER M4 ;
        RECT 0.000 281.760 0.192 281.784 ;
    END
  END tx[355]
  PIN tx[356]
    DIRECTION OUTPUT ;
    USE SIGNAL ;
    PORT
      LAYER M4 ;
        RECT 0.000 282.048 0.192 282.072 ;
    END
  END tx[356]
  PIN tx[357]
    DIRECTION OUTPUT ;
    USE SIGNAL ;
    PORT
      LAYER M4 ;
        RECT 0.000 282.384 0.192 282.408 ;
    END
  END tx[357]
  PIN tx[358]
    DIRECTION OUTPUT ;
    USE SIGNAL ;
    PORT
      LAYER M4 ;
        RECT 0.000 282.672 0.192 282.696 ;
    END
  END tx[358]
  PIN tx[359]
    DIRECTION OUTPUT ;
    USE SIGNAL ;
    PORT
      LAYER M4 ;
        RECT 0.000 283.008 0.192 283.032 ;
    END
  END tx[359]
  PIN tx[360]
    DIRECTION OUTPUT ;
    USE SIGNAL ;
    PORT
      LAYER M4 ;
        RECT 0.000 283.344 0.192 283.368 ;
    END
  END tx[360]
  PIN tx[361]
    DIRECTION OUTPUT ;
    USE SIGNAL ;
    PORT
      LAYER M4 ;
        RECT 0.000 283.632 0.192 283.656 ;
    END
  END tx[361]
  PIN tx[362]
    DIRECTION OUTPUT ;
    USE SIGNAL ;
    PORT
      LAYER M4 ;
        RECT 0.000 283.968 0.192 283.992 ;
    END
  END tx[362]
  PIN tx[363]
    DIRECTION OUTPUT ;
    USE SIGNAL ;
    PORT
      LAYER M4 ;
        RECT 0.000 284.256 0.192 284.280 ;
    END
  END tx[363]
  PIN tx[364]
    DIRECTION OUTPUT ;
    USE SIGNAL ;
    PORT
      LAYER M4 ;
        RECT 0.000 284.592 0.192 284.616 ;
    END
  END tx[364]
  PIN tx[365]
    DIRECTION OUTPUT ;
    USE SIGNAL ;
    PORT
      LAYER M4 ;
        RECT 0.000 284.880 0.192 284.904 ;
    END
  END tx[365]
  PIN tx[366]
    DIRECTION OUTPUT ;
    USE SIGNAL ;
    PORT
      LAYER M4 ;
        RECT 0.000 285.216 0.192 285.240 ;
    END
  END tx[366]
  PIN tx[367]
    DIRECTION OUTPUT ;
    USE SIGNAL ;
    PORT
      LAYER M4 ;
        RECT 0.000 285.504 0.192 285.528 ;
    END
  END tx[367]
  PIN tx[368]
    DIRECTION OUTPUT ;
    USE SIGNAL ;
    PORT
      LAYER M4 ;
        RECT 0.000 285.840 0.192 285.864 ;
    END
  END tx[368]
  PIN tx[369]
    DIRECTION OUTPUT ;
    USE SIGNAL ;
    PORT
      LAYER M4 ;
        RECT 0.000 286.128 0.192 286.152 ;
    END
  END tx[369]
  PIN tx[370]
    DIRECTION OUTPUT ;
    USE SIGNAL ;
    PORT
      LAYER M4 ;
        RECT 0.000 286.464 0.192 286.488 ;
    END
  END tx[370]
  PIN tx[371]
    DIRECTION OUTPUT ;
    USE SIGNAL ;
    PORT
      LAYER M4 ;
        RECT 0.000 286.800 0.192 286.824 ;
    END
  END tx[371]
  PIN tx[372]
    DIRECTION OUTPUT ;
    USE SIGNAL ;
    PORT
      LAYER M4 ;
        RECT 0.000 287.088 0.192 287.112 ;
    END
  END tx[372]
  PIN tx[373]
    DIRECTION OUTPUT ;
    USE SIGNAL ;
    PORT
      LAYER M4 ;
        RECT 0.000 287.424 0.192 287.448 ;
    END
  END tx[373]
  PIN tx[374]
    DIRECTION OUTPUT ;
    USE SIGNAL ;
    PORT
      LAYER M4 ;
        RECT 0.000 287.712 0.192 287.736 ;
    END
  END tx[374]
  PIN tx[375]
    DIRECTION OUTPUT ;
    USE SIGNAL ;
    PORT
      LAYER M4 ;
        RECT 0.000 288.048 0.192 288.072 ;
    END
  END tx[375]
  PIN tx[376]
    DIRECTION OUTPUT ;
    USE SIGNAL ;
    PORT
      LAYER M4 ;
        RECT 0.000 288.336 0.192 288.360 ;
    END
  END tx[376]
  PIN tx[377]
    DIRECTION OUTPUT ;
    USE SIGNAL ;
    PORT
      LAYER M4 ;
        RECT 0.000 288.672 0.192 288.696 ;
    END
  END tx[377]
  PIN tx[378]
    DIRECTION OUTPUT ;
    USE SIGNAL ;
    PORT
      LAYER M4 ;
        RECT 0.000 288.960 0.192 288.984 ;
    END
  END tx[378]
  PIN tx[379]
    DIRECTION OUTPUT ;
    USE SIGNAL ;
    PORT
      LAYER M4 ;
        RECT 0.000 289.296 0.192 289.320 ;
    END
  END tx[379]
  PIN tx[380]
    DIRECTION OUTPUT ;
    USE SIGNAL ;
    PORT
      LAYER M4 ;
        RECT 0.000 289.584 0.192 289.608 ;
    END
  END tx[380]
  PIN tx[381]
    DIRECTION OUTPUT ;
    USE SIGNAL ;
    PORT
      LAYER M4 ;
        RECT 0.000 289.920 0.192 289.944 ;
    END
  END tx[381]
  PIN tx[382]
    DIRECTION OUTPUT ;
    USE SIGNAL ;
    PORT
      LAYER M4 ;
        RECT 0.000 290.256 0.192 290.280 ;
    END
  END tx[382]
  PIN tx[383]
    DIRECTION OUTPUT ;
    USE SIGNAL ;
    PORT
      LAYER M4 ;
        RECT 0.000 290.544 0.192 290.568 ;
    END
  END tx[383]
  PIN tx[384]
    DIRECTION OUTPUT ;
    USE SIGNAL ;
    PORT
      LAYER M4 ;
        RECT 0.000 290.880 0.192 290.904 ;
    END
  END tx[384]
  PIN tx[385]
    DIRECTION OUTPUT ;
    USE SIGNAL ;
    PORT
      LAYER M4 ;
        RECT 0.000 291.168 0.192 291.192 ;
    END
  END tx[385]
  PIN tx[386]
    DIRECTION OUTPUT ;
    USE SIGNAL ;
    PORT
      LAYER M4 ;
        RECT 0.000 291.504 0.192 291.528 ;
    END
  END tx[386]
  PIN tx[387]
    DIRECTION OUTPUT ;
    USE SIGNAL ;
    PORT
      LAYER M4 ;
        RECT 0.000 291.792 0.192 291.816 ;
    END
  END tx[387]
  PIN tx[388]
    DIRECTION OUTPUT ;
    USE SIGNAL ;
    PORT
      LAYER M4 ;
        RECT 0.000 292.128 0.192 292.152 ;
    END
  END tx[388]
  PIN tx[389]
    DIRECTION OUTPUT ;
    USE SIGNAL ;
    PORT
      LAYER M4 ;
        RECT 0.000 292.416 0.192 292.440 ;
    END
  END tx[389]
  PIN tx[390]
    DIRECTION OUTPUT ;
    USE SIGNAL ;
    PORT
      LAYER M4 ;
        RECT 0.000 292.752 0.192 292.776 ;
    END
  END tx[390]
  PIN tx[391]
    DIRECTION OUTPUT ;
    USE SIGNAL ;
    PORT
      LAYER M4 ;
        RECT 0.000 293.088 0.192 293.112 ;
    END
  END tx[391]
  PIN tx[392]
    DIRECTION OUTPUT ;
    USE SIGNAL ;
    PORT
      LAYER M4 ;
        RECT 0.000 293.376 0.192 293.400 ;
    END
  END tx[392]
  PIN tx[393]
    DIRECTION OUTPUT ;
    USE SIGNAL ;
    PORT
      LAYER M4 ;
        RECT 0.000 293.712 0.192 293.736 ;
    END
  END tx[393]
  PIN tx[394]
    DIRECTION OUTPUT ;
    USE SIGNAL ;
    PORT
      LAYER M4 ;
        RECT 0.000 294.000 0.192 294.024 ;
    END
  END tx[394]
  PIN tx[395]
    DIRECTION OUTPUT ;
    USE SIGNAL ;
    PORT
      LAYER M4 ;
        RECT 0.000 294.336 0.192 294.360 ;
    END
  END tx[395]
  PIN tx[396]
    DIRECTION OUTPUT ;
    USE SIGNAL ;
    PORT
      LAYER M4 ;
        RECT 0.000 294.624 0.192 294.648 ;
    END
  END tx[396]
  PIN tx[397]
    DIRECTION OUTPUT ;
    USE SIGNAL ;
    PORT
      LAYER M4 ;
        RECT 0.000 294.960 0.192 294.984 ;
    END
  END tx[397]
  PIN tx[398]
    DIRECTION OUTPUT ;
    USE SIGNAL ;
    PORT
      LAYER M4 ;
        RECT 0.000 295.248 0.192 295.272 ;
    END
  END tx[398]
  PIN tx[399]
    DIRECTION OUTPUT ;
    USE SIGNAL ;
    PORT
      LAYER M4 ;
        RECT 0.000 295.584 0.192 295.608 ;
    END
  END tx[399]
  PIN tx[400]
    DIRECTION OUTPUT ;
    USE SIGNAL ;
    PORT
      LAYER M4 ;
        RECT 0.000 295.872 0.192 295.896 ;
    END
  END tx[400]
  PIN tx[401]
    DIRECTION OUTPUT ;
    USE SIGNAL ;
    PORT
      LAYER M4 ;
        RECT 0.000 296.208 0.192 296.232 ;
    END
  END tx[401]
  PIN tx[402]
    DIRECTION OUTPUT ;
    USE SIGNAL ;
    PORT
      LAYER M4 ;
        RECT 0.000 296.544 0.192 296.568 ;
    END
  END tx[402]
  PIN tx[403]
    DIRECTION OUTPUT ;
    USE SIGNAL ;
    PORT
      LAYER M4 ;
        RECT 0.000 296.832 0.192 296.856 ;
    END
  END tx[403]
  PIN tx[404]
    DIRECTION OUTPUT ;
    USE SIGNAL ;
    PORT
      LAYER M4 ;
        RECT 0.000 297.168 0.192 297.192 ;
    END
  END tx[404]
  PIN tx[405]
    DIRECTION OUTPUT ;
    USE SIGNAL ;
    PORT
      LAYER M4 ;
        RECT 0.000 297.456 0.192 297.480 ;
    END
  END tx[405]
  PIN tx[406]
    DIRECTION OUTPUT ;
    USE SIGNAL ;
    PORT
      LAYER M4 ;
        RECT 0.000 297.792 0.192 297.816 ;
    END
  END tx[406]
  PIN tx[407]
    DIRECTION OUTPUT ;
    USE SIGNAL ;
    PORT
      LAYER M4 ;
        RECT 0.000 298.080 0.192 298.104 ;
    END
  END tx[407]
  PIN tx[408]
    DIRECTION OUTPUT ;
    USE SIGNAL ;
    PORT
      LAYER M4 ;
        RECT 0.000 298.416 0.192 298.440 ;
    END
  END tx[408]
  PIN tx[409]
    DIRECTION OUTPUT ;
    USE SIGNAL ;
    PORT
      LAYER M4 ;
        RECT 0.000 298.704 0.192 298.728 ;
    END
  END tx[409]
  PIN tx[410]
    DIRECTION OUTPUT ;
    USE SIGNAL ;
    PORT
      LAYER M4 ;
        RECT 0.000 299.040 0.192 299.064 ;
    END
  END tx[410]
  PIN tx[411]
    DIRECTION OUTPUT ;
    USE SIGNAL ;
    PORT
      LAYER M4 ;
        RECT 0.000 299.376 0.192 299.400 ;
    END
  END tx[411]
  PIN tx[412]
    DIRECTION OUTPUT ;
    USE SIGNAL ;
    PORT
      LAYER M4 ;
        RECT 0.000 299.664 0.192 299.688 ;
    END
  END tx[412]
  PIN tx[413]
    DIRECTION OUTPUT ;
    USE SIGNAL ;
    PORT
      LAYER M4 ;
        RECT 0.000 300.000 0.192 300.024 ;
    END
  END tx[413]
  PIN tx[414]
    DIRECTION OUTPUT ;
    USE SIGNAL ;
    PORT
      LAYER M4 ;
        RECT 0.000 300.288 0.192 300.312 ;
    END
  END tx[414]
  PIN tx[415]
    DIRECTION OUTPUT ;
    USE SIGNAL ;
    PORT
      LAYER M4 ;
        RECT 0.000 300.624 0.192 300.648 ;
    END
  END tx[415]
  PIN tx[416]
    DIRECTION OUTPUT ;
    USE SIGNAL ;
    PORT
      LAYER M4 ;
        RECT 0.000 300.912 0.192 300.936 ;
    END
  END tx[416]
  PIN tx[417]
    DIRECTION OUTPUT ;
    USE SIGNAL ;
    PORT
      LAYER M4 ;
        RECT 0.000 301.248 0.192 301.272 ;
    END
  END tx[417]
  PIN tx[418]
    DIRECTION OUTPUT ;
    USE SIGNAL ;
    PORT
      LAYER M4 ;
        RECT 0.000 301.536 0.192 301.560 ;
    END
  END tx[418]
  PIN tx[419]
    DIRECTION OUTPUT ;
    USE SIGNAL ;
    PORT
      LAYER M4 ;
        RECT 0.000 301.872 0.192 301.896 ;
    END
  END tx[419]
  PIN tx[420]
    DIRECTION OUTPUT ;
    USE SIGNAL ;
    PORT
      LAYER M4 ;
        RECT 0.000 302.160 0.192 302.184 ;
    END
  END tx[420]
  PIN tx[421]
    DIRECTION OUTPUT ;
    USE SIGNAL ;
    PORT
      LAYER M4 ;
        RECT 0.000 302.496 0.192 302.520 ;
    END
  END tx[421]
  PIN tx[422]
    DIRECTION OUTPUT ;
    USE SIGNAL ;
    PORT
      LAYER M4 ;
        RECT 0.000 302.832 0.192 302.856 ;
    END
  END tx[422]
  PIN tx[423]
    DIRECTION OUTPUT ;
    USE SIGNAL ;
    PORT
      LAYER M4 ;
        RECT 0.000 303.120 0.192 303.144 ;
    END
  END tx[423]
  PIN tx[424]
    DIRECTION OUTPUT ;
    USE SIGNAL ;
    PORT
      LAYER M4 ;
        RECT 0.000 303.456 0.192 303.480 ;
    END
  END tx[424]
  PIN tx[425]
    DIRECTION OUTPUT ;
    USE SIGNAL ;
    PORT
      LAYER M4 ;
        RECT 0.000 303.744 0.192 303.768 ;
    END
  END tx[425]
  PIN tx[426]
    DIRECTION OUTPUT ;
    USE SIGNAL ;
    PORT
      LAYER M4 ;
        RECT 0.000 304.080 0.192 304.104 ;
    END
  END tx[426]
  PIN tx[427]
    DIRECTION OUTPUT ;
    USE SIGNAL ;
    PORT
      LAYER M4 ;
        RECT 0.000 304.368 0.192 304.392 ;
    END
  END tx[427]
  PIN tx[428]
    DIRECTION OUTPUT ;
    USE SIGNAL ;
    PORT
      LAYER M4 ;
        RECT 0.000 304.704 0.192 304.728 ;
    END
  END tx[428]
  PIN tx[429]
    DIRECTION OUTPUT ;
    USE SIGNAL ;
    PORT
      LAYER M4 ;
        RECT 0.000 304.992 0.192 305.016 ;
    END
  END tx[429]
  PIN tx[430]
    DIRECTION OUTPUT ;
    USE SIGNAL ;
    PORT
      LAYER M4 ;
        RECT 0.000 305.328 0.192 305.352 ;
    END
  END tx[430]
  PIN tx[431]
    DIRECTION OUTPUT ;
    USE SIGNAL ;
    PORT
      LAYER M4 ;
        RECT 0.000 305.664 0.192 305.688 ;
    END
  END tx[431]
  PIN tx[432]
    DIRECTION OUTPUT ;
    USE SIGNAL ;
    PORT
      LAYER M4 ;
        RECT 0.000 305.952 0.192 305.976 ;
    END
  END tx[432]
  PIN tx[433]
    DIRECTION OUTPUT ;
    USE SIGNAL ;
    PORT
      LAYER M4 ;
        RECT 0.000 306.288 0.192 306.312 ;
    END
  END tx[433]
  PIN tx[434]
    DIRECTION OUTPUT ;
    USE SIGNAL ;
    PORT
      LAYER M4 ;
        RECT 0.000 306.576 0.192 306.600 ;
    END
  END tx[434]
  PIN tx[435]
    DIRECTION OUTPUT ;
    USE SIGNAL ;
    PORT
      LAYER M4 ;
        RECT 0.000 306.912 0.192 306.936 ;
    END
  END tx[435]
  PIN tx[436]
    DIRECTION OUTPUT ;
    USE SIGNAL ;
    PORT
      LAYER M4 ;
        RECT 0.000 307.200 0.192 307.224 ;
    END
  END tx[436]
  PIN tx[437]
    DIRECTION OUTPUT ;
    USE SIGNAL ;
    PORT
      LAYER M4 ;
        RECT 0.000 307.536 0.192 307.560 ;
    END
  END tx[437]
  PIN tx[438]
    DIRECTION OUTPUT ;
    USE SIGNAL ;
    PORT
      LAYER M4 ;
        RECT 0.000 307.824 0.192 307.848 ;
    END
  END tx[438]
  PIN tx[439]
    DIRECTION OUTPUT ;
    USE SIGNAL ;
    PORT
      LAYER M4 ;
        RECT 0.000 308.160 0.192 308.184 ;
    END
  END tx[439]
  PIN tx[440]
    DIRECTION OUTPUT ;
    USE SIGNAL ;
    PORT
      LAYER M4 ;
        RECT 0.000 308.448 0.192 308.472 ;
    END
  END tx[440]
  PIN tx[441]
    DIRECTION OUTPUT ;
    USE SIGNAL ;
    PORT
      LAYER M4 ;
        RECT 0.000 308.784 0.192 308.808 ;
    END
  END tx[441]
  PIN tx[442]
    DIRECTION OUTPUT ;
    USE SIGNAL ;
    PORT
      LAYER M4 ;
        RECT 0.000 309.120 0.192 309.144 ;
    END
  END tx[442]
  PIN tx[443]
    DIRECTION OUTPUT ;
    USE SIGNAL ;
    PORT
      LAYER M4 ;
        RECT 0.000 309.408 0.192 309.432 ;
    END
  END tx[443]
  PIN tx[444]
    DIRECTION OUTPUT ;
    USE SIGNAL ;
    PORT
      LAYER M4 ;
        RECT 0.000 309.744 0.192 309.768 ;
    END
  END tx[444]
  PIN tx[445]
    DIRECTION OUTPUT ;
    USE SIGNAL ;
    PORT
      LAYER M4 ;
        RECT 0.000 310.032 0.192 310.056 ;
    END
  END tx[445]
  PIN tx[446]
    DIRECTION OUTPUT ;
    USE SIGNAL ;
    PORT
      LAYER M4 ;
        RECT 0.000 310.368 0.192 310.392 ;
    END
  END tx[446]
  PIN tx[447]
    DIRECTION OUTPUT ;
    USE SIGNAL ;
    PORT
      LAYER M4 ;
        RECT 0.000 310.656 0.192 310.680 ;
    END
  END tx[447]
  PIN tx[448]
    DIRECTION OUTPUT ;
    USE SIGNAL ;
    PORT
      LAYER M4 ;
        RECT 0.000 310.992 0.192 311.016 ;
    END
  END tx[448]
  PIN tx[449]
    DIRECTION OUTPUT ;
    USE SIGNAL ;
    PORT
      LAYER M4 ;
        RECT 0.000 311.280 0.192 311.304 ;
    END
  END tx[449]
  PIN tx[450]
    DIRECTION OUTPUT ;
    USE SIGNAL ;
    PORT
      LAYER M4 ;
        RECT 0.000 311.616 0.192 311.640 ;
    END
  END tx[450]
  PIN tx[451]
    DIRECTION OUTPUT ;
    USE SIGNAL ;
    PORT
      LAYER M4 ;
        RECT 0.000 311.952 0.192 311.976 ;
    END
  END tx[451]
  PIN tx[452]
    DIRECTION OUTPUT ;
    USE SIGNAL ;
    PORT
      LAYER M4 ;
        RECT 0.000 312.240 0.192 312.264 ;
    END
  END tx[452]
  PIN tx[453]
    DIRECTION OUTPUT ;
    USE SIGNAL ;
    PORT
      LAYER M4 ;
        RECT 0.000 312.576 0.192 312.600 ;
    END
  END tx[453]
  PIN tx[454]
    DIRECTION OUTPUT ;
    USE SIGNAL ;
    PORT
      LAYER M4 ;
        RECT 0.000 312.864 0.192 312.888 ;
    END
  END tx[454]
  PIN tx[455]
    DIRECTION OUTPUT ;
    USE SIGNAL ;
    PORT
      LAYER M4 ;
        RECT 0.000 313.200 0.192 313.224 ;
    END
  END tx[455]
  PIN tx[456]
    DIRECTION OUTPUT ;
    USE SIGNAL ;
    PORT
      LAYER M4 ;
        RECT 0.000 313.488 0.192 313.512 ;
    END
  END tx[456]
  PIN tx[457]
    DIRECTION OUTPUT ;
    USE SIGNAL ;
    PORT
      LAYER M4 ;
        RECT 0.000 313.824 0.192 313.848 ;
    END
  END tx[457]
  PIN tx[458]
    DIRECTION OUTPUT ;
    USE SIGNAL ;
    PORT
      LAYER M4 ;
        RECT 0.000 314.112 0.192 314.136 ;
    END
  END tx[458]
  PIN tx[459]
    DIRECTION OUTPUT ;
    USE SIGNAL ;
    PORT
      LAYER M4 ;
        RECT 0.000 314.448 0.192 314.472 ;
    END
  END tx[459]
  PIN tx[460]
    DIRECTION OUTPUT ;
    USE SIGNAL ;
    PORT
      LAYER M4 ;
        RECT 0.000 314.736 0.192 314.760 ;
    END
  END tx[460]
  PIN tx[461]
    DIRECTION OUTPUT ;
    USE SIGNAL ;
    PORT
      LAYER M4 ;
        RECT 0.000 315.072 0.192 315.096 ;
    END
  END tx[461]
  PIN tx[462]
    DIRECTION OUTPUT ;
    USE SIGNAL ;
    PORT
      LAYER M4 ;
        RECT 0.000 315.408 0.192 315.432 ;
    END
  END tx[462]
  PIN tx[463]
    DIRECTION OUTPUT ;
    USE SIGNAL ;
    PORT
      LAYER M4 ;
        RECT 0.000 315.696 0.192 315.720 ;
    END
  END tx[463]
  PIN tx[464]
    DIRECTION OUTPUT ;
    USE SIGNAL ;
    PORT
      LAYER M4 ;
        RECT 0.000 316.032 0.192 316.056 ;
    END
  END tx[464]
  PIN tx[465]
    DIRECTION OUTPUT ;
    USE SIGNAL ;
    PORT
      LAYER M4 ;
        RECT 0.000 316.320 0.192 316.344 ;
    END
  END tx[465]
  PIN tx[466]
    DIRECTION OUTPUT ;
    USE SIGNAL ;
    PORT
      LAYER M4 ;
        RECT 0.000 316.656 0.192 316.680 ;
    END
  END tx[466]
  PIN tx[467]
    DIRECTION OUTPUT ;
    USE SIGNAL ;
    PORT
      LAYER M4 ;
        RECT 0.000 316.944 0.192 316.968 ;
    END
  END tx[467]
  PIN tx[468]
    DIRECTION OUTPUT ;
    USE SIGNAL ;
    PORT
      LAYER M4 ;
        RECT 0.000 317.280 0.192 317.304 ;
    END
  END tx[468]
  PIN tx[469]
    DIRECTION OUTPUT ;
    USE SIGNAL ;
    PORT
      LAYER M4 ;
        RECT 0.000 317.568 0.192 317.592 ;
    END
  END tx[469]
  PIN tx[470]
    DIRECTION OUTPUT ;
    USE SIGNAL ;
    PORT
      LAYER M4 ;
        RECT 0.000 317.904 0.192 317.928 ;
    END
  END tx[470]
  PIN tx[471]
    DIRECTION OUTPUT ;
    USE SIGNAL ;
    PORT
      LAYER M4 ;
        RECT 0.000 318.192 0.192 318.216 ;
    END
  END tx[471]
  PIN tx[472]
    DIRECTION OUTPUT ;
    USE SIGNAL ;
    PORT
      LAYER M4 ;
        RECT 0.000 318.528 0.192 318.552 ;
    END
  END tx[472]
  PIN tx[473]
    DIRECTION OUTPUT ;
    USE SIGNAL ;
    PORT
      LAYER M4 ;
        RECT 0.000 318.864 0.192 318.888 ;
    END
  END tx[473]
  PIN tx[474]
    DIRECTION OUTPUT ;
    USE SIGNAL ;
    PORT
      LAYER M4 ;
        RECT 0.000 319.152 0.192 319.176 ;
    END
  END tx[474]
  PIN tx[475]
    DIRECTION OUTPUT ;
    USE SIGNAL ;
    PORT
      LAYER M4 ;
        RECT 0.000 319.488 0.192 319.512 ;
    END
  END tx[475]
  PIN tx[476]
    DIRECTION OUTPUT ;
    USE SIGNAL ;
    PORT
      LAYER M4 ;
        RECT 0.000 319.776 0.192 319.800 ;
    END
  END tx[476]
  PIN tx[477]
    DIRECTION OUTPUT ;
    USE SIGNAL ;
    PORT
      LAYER M4 ;
        RECT 0.000 320.112 0.192 320.136 ;
    END
  END tx[477]
  PIN tx[478]
    DIRECTION OUTPUT ;
    USE SIGNAL ;
    PORT
      LAYER M4 ;
        RECT 0.000 320.400 0.192 320.424 ;
    END
  END tx[478]
  PIN tx[479]
    DIRECTION OUTPUT ;
    USE SIGNAL ;
    PORT
      LAYER M4 ;
        RECT 0.000 320.736 0.192 320.760 ;
    END
  END tx[479]
  PIN tx[480]
    DIRECTION OUTPUT ;
    USE SIGNAL ;
    PORT
      LAYER M4 ;
        RECT 0.000 321.024 0.192 321.048 ;
    END
  END tx[480]
  PIN tx[481]
    DIRECTION OUTPUT ;
    USE SIGNAL ;
    PORT
      LAYER M4 ;
        RECT 0.000 321.360 0.192 321.384 ;
    END
  END tx[481]
  PIN tx[482]
    DIRECTION OUTPUT ;
    USE SIGNAL ;
    PORT
      LAYER M4 ;
        RECT 0.000 321.696 0.192 321.720 ;
    END
  END tx[482]
  PIN tx[483]
    DIRECTION OUTPUT ;
    USE SIGNAL ;
    PORT
      LAYER M4 ;
        RECT 0.000 321.984 0.192 322.008 ;
    END
  END tx[483]
  PIN tx[484]
    DIRECTION OUTPUT ;
    USE SIGNAL ;
    PORT
      LAYER M4 ;
        RECT 0.000 322.320 0.192 322.344 ;
    END
  END tx[484]
  PIN tx[485]
    DIRECTION OUTPUT ;
    USE SIGNAL ;
    PORT
      LAYER M4 ;
        RECT 0.000 322.608 0.192 322.632 ;
    END
  END tx[485]
  PIN tx[486]
    DIRECTION OUTPUT ;
    USE SIGNAL ;
    PORT
      LAYER M4 ;
        RECT 0.000 322.944 0.192 322.968 ;
    END
  END tx[486]
  PIN tx[487]
    DIRECTION OUTPUT ;
    USE SIGNAL ;
    PORT
      LAYER M4 ;
        RECT 0.000 323.232 0.192 323.256 ;
    END
  END tx[487]
  PIN tx[488]
    DIRECTION OUTPUT ;
    USE SIGNAL ;
    PORT
      LAYER M4 ;
        RECT 0.000 323.568 0.192 323.592 ;
    END
  END tx[488]
  PIN tx[489]
    DIRECTION OUTPUT ;
    USE SIGNAL ;
    PORT
      LAYER M4 ;
        RECT 0.000 323.856 0.192 323.880 ;
    END
  END tx[489]
  PIN tx[490]
    DIRECTION OUTPUT ;
    USE SIGNAL ;
    PORT
      LAYER M4 ;
        RECT 0.000 324.192 0.192 324.216 ;
    END
  END tx[490]
  PIN tx[491]
    DIRECTION OUTPUT ;
    USE SIGNAL ;
    PORT
      LAYER M4 ;
        RECT 0.000 324.480 0.192 324.504 ;
    END
  END tx[491]
  PIN tx[492]
    DIRECTION OUTPUT ;
    USE SIGNAL ;
    PORT
      LAYER M4 ;
        RECT 0.000 324.816 0.192 324.840 ;
    END
  END tx[492]
  PIN tx[493]
    DIRECTION OUTPUT ;
    USE SIGNAL ;
    PORT
      LAYER M4 ;
        RECT 0.000 325.152 0.192 325.176 ;
    END
  END tx[493]
  PIN tx[494]
    DIRECTION OUTPUT ;
    USE SIGNAL ;
    PORT
      LAYER M4 ;
        RECT 0.000 325.440 0.192 325.464 ;
    END
  END tx[494]
  PIN tx[495]
    DIRECTION OUTPUT ;
    USE SIGNAL ;
    PORT
      LAYER M4 ;
        RECT 0.000 325.776 0.192 325.800 ;
    END
  END tx[495]
  PIN tx[496]
    DIRECTION OUTPUT ;
    USE SIGNAL ;
    PORT
      LAYER M4 ;
        RECT 0.000 326.064 0.192 326.088 ;
    END
  END tx[496]
  PIN tx[497]
    DIRECTION OUTPUT ;
    USE SIGNAL ;
    PORT
      LAYER M4 ;
        RECT 0.000 326.400 0.192 326.424 ;
    END
  END tx[497]
  PIN tx[498]
    DIRECTION OUTPUT ;
    USE SIGNAL ;
    PORT
      LAYER M4 ;
        RECT 0.000 326.688 0.192 326.712 ;
    END
  END tx[498]
  PIN tx[499]
    DIRECTION OUTPUT ;
    USE SIGNAL ;
    PORT
      LAYER M4 ;
        RECT 0.000 327.024 0.192 327.048 ;
    END
  END tx[499]
  PIN tx[500]
    DIRECTION OUTPUT ;
    USE SIGNAL ;
    PORT
      LAYER M4 ;
        RECT 0.000 327.312 0.192 327.336 ;
    END
  END tx[500]
  PIN tx[501]
    DIRECTION OUTPUT ;
    USE SIGNAL ;
    PORT
      LAYER M4 ;
        RECT 0.000 327.648 0.192 327.672 ;
    END
  END tx[501]
  PIN tx[502]
    DIRECTION OUTPUT ;
    USE SIGNAL ;
    PORT
      LAYER M4 ;
        RECT 0.000 327.984 0.192 328.008 ;
    END
  END tx[502]
  PIN tx[503]
    DIRECTION OUTPUT ;
    USE SIGNAL ;
    PORT
      LAYER M4 ;
        RECT 0.000 328.272 0.192 328.296 ;
    END
  END tx[503]
  PIN tx[504]
    DIRECTION OUTPUT ;
    USE SIGNAL ;
    PORT
      LAYER M4 ;
        RECT 0.000 328.608 0.192 328.632 ;
    END
  END tx[504]
  PIN tx[505]
    DIRECTION OUTPUT ;
    USE SIGNAL ;
    PORT
      LAYER M4 ;
        RECT 0.000 328.896 0.192 328.920 ;
    END
  END tx[505]
  PIN tx[506]
    DIRECTION OUTPUT ;
    USE SIGNAL ;
    PORT
      LAYER M4 ;
        RECT 0.000 329.232 0.192 329.256 ;
    END
  END tx[506]
  PIN tx[507]
    DIRECTION OUTPUT ;
    USE SIGNAL ;
    PORT
      LAYER M4 ;
        RECT 0.000 329.520 0.192 329.544 ;
    END
  END tx[507]
  PIN tx[508]
    DIRECTION OUTPUT ;
    USE SIGNAL ;
    PORT
      LAYER M4 ;
        RECT 0.000 329.856 0.192 329.880 ;
    END
  END tx[508]
  PIN tx[509]
    DIRECTION OUTPUT ;
    USE SIGNAL ;
    PORT
      LAYER M4 ;
        RECT 0.000 330.144 0.192 330.168 ;
    END
  END tx[509]
  PIN tx[510]
    DIRECTION OUTPUT ;
    USE SIGNAL ;
    PORT
      LAYER M4 ;
        RECT 0.000 330.480 0.192 330.504 ;
    END
  END tx[510]
  PIN tx[511]
    DIRECTION OUTPUT ;
    USE SIGNAL ;
    PORT
      LAYER M4 ;
        RECT 0.000 330.768 0.192 330.792 ;
    END
  END tx[511]
  PIN lo_v
    DIRECTION INPUT ;
    USE SIGNAL ;
    PORT
      LAYER M4 ;
        RECT 431.808 2.304 432.000 2.328 ;
    END
  END lo_v
  PIN lo_r
    DIRECTION OUTPUT ;
    USE SIGNAL ;
    PORT
      LAYER M4 ;
        RECT 431.808 2.592 432.000 2.616 ;
    END
  END lo_r
  PIN lo_d[0]
    DIRECTION INPUT ;
    USE SIGNAL ;
    PORT
      LAYER M4 ;
        RECT 431.808 2.880 432.000 2.904 ;
    END
  END lo_d[0]
  PIN lo_d[1]
    DIRECTION INPUT ;
    USE SIGNAL ;
    PORT
      LAYER M4 ;
        RECT 431.808 3.216 432.000 3.240 ;
    END
  END lo_d[1]
  PIN lo_d[2]
    DIRECTION INPUT ;
    USE SIGNAL ;
    PORT
      LAYER M4 ;
        RECT 431.808 3.504 432.000 3.528 ;
    END
  END lo_d[2]
  PIN lo_d[3]
    DIRECTION INPUT ;
    USE SIGNAL ;
    PORT
      LAYER M4 ;
        RECT 431.808 3.792 432.000 3.816 ;
    END
  END lo_d[3]
  PIN lo_d[4]
    DIRECTION INPUT ;
    USE SIGNAL ;
    PORT
      LAYER M4 ;
        RECT 431.808 4.080 432.000 4.104 ;
    END
  END lo_d[4]
  PIN lo_d[5]
    DIRECTION INPUT ;
    USE SIGNAL ;
    PORT
      LAYER M4 ;
        RECT 431.808 4.368 432.000 4.392 ;
    END
  END lo_d[5]
  PIN lo_d[6]
    DIRECTION INPUT ;
    USE SIGNAL ;
    PORT
      LAYER M4 ;
        RECT 431.808 4.704 432.000 4.728 ;
    END
  END lo_d[6]
  PIN lo_d[7]
    DIRECTION INPUT ;
    USE SIGNAL ;
    PORT
      LAYER M4 ;
        RECT 431.808 4.992 432.000 5.016 ;
    END
  END lo_d[7]
  PIN lo_d[8]
    DIRECTION INPUT ;
    USE SIGNAL ;
    PORT
      LAYER M4 ;
        RECT 431.808 5.280 432.000 5.304 ;
    END
  END lo_d[8]
  PIN lo_d[9]
    DIRECTION INPUT ;
    USE SIGNAL ;
    PORT
      LAYER M4 ;
        RECT 431.808 5.568 432.000 5.592 ;
    END
  END lo_d[9]
  PIN lo_d[10]
    DIRECTION INPUT ;
    USE SIGNAL ;
    PORT
      LAYER M4 ;
        RECT 431.808 5.904 432.000 5.928 ;
    END
  END lo_d[10]
  PIN lo_d[11]
    DIRECTION INPUT ;
    USE SIGNAL ;
    PORT
      LAYER M4 ;
        RECT 431.808 6.192 432.000 6.216 ;
    END
  END lo_d[11]
  PIN lo_d[12]
    DIRECTION INPUT ;
    USE SIGNAL ;
    PORT
      LAYER M4 ;
        RECT 431.808 6.480 432.000 6.504 ;
    END
  END lo_d[12]
  PIN lo_d[13]
    DIRECTION INPUT ;
    USE SIGNAL ;
    PORT
      LAYER M4 ;
        RECT 431.808 6.768 432.000 6.792 ;
    END
  END lo_d[13]
  PIN lo_d[14]
    DIRECTION INPUT ;
    USE SIGNAL ;
    PORT
      LAYER M4 ;
        RECT 431.808 7.056 432.000 7.080 ;
    END
  END lo_d[14]
  PIN lo_d[15]
    DIRECTION INPUT ;
    USE SIGNAL ;
    PORT
      LAYER M4 ;
        RECT 431.808 7.392 432.000 7.416 ;
    END
  END lo_d[15]
  PIN lo_d[16]
    DIRECTION INPUT ;
    USE SIGNAL ;
    PORT
      LAYER M4 ;
        RECT 431.808 7.680 432.000 7.704 ;
    END
  END lo_d[16]
  PIN lo_d[17]
    DIRECTION INPUT ;
    USE SIGNAL ;
    PORT
      LAYER M4 ;
        RECT 431.808 7.968 432.000 7.992 ;
    END
  END lo_d[17]
  PIN lo_d[18]
    DIRECTION INPUT ;
    USE SIGNAL ;
    PORT
      LAYER M4 ;
        RECT 431.808 8.256 432.000 8.280 ;
    END
  END lo_d[18]
  PIN lo_d[19]
    DIRECTION INPUT ;
    USE SIGNAL ;
    PORT
      LAYER M4 ;
        RECT 431.808 8.592 432.000 8.616 ;
    END
  END lo_d[19]
  PIN lo_d[20]
    DIRECTION INPUT ;
    USE SIGNAL ;
    PORT
      LAYER M4 ;
        RECT 431.808 8.880 432.000 8.904 ;
    END
  END lo_d[20]
  PIN lo_d[21]
    DIRECTION INPUT ;
    USE SIGNAL ;
    PORT
      LAYER M4 ;
        RECT 431.808 9.168 432.000 9.192 ;
    END
  END lo_d[21]
  PIN lo_d[22]
    DIRECTION INPUT ;
    USE SIGNAL ;
    PORT
      LAYER M4 ;
        RECT 431.808 9.456 432.000 9.480 ;
    END
  END lo_d[22]
  PIN lo_d[23]
    DIRECTION INPUT ;
    USE SIGNAL ;
    PORT
      LAYER M4 ;
        RECT 431.808 9.792 432.000 9.816 ;
    END
  END lo_d[23]
  PIN lo_d[24]
    DIRECTION INPUT ;
    USE SIGNAL ;
    PORT
      LAYER M4 ;
        RECT 431.808 10.080 432.000 10.104 ;
    END
  END lo_d[24]
  PIN lo_d[25]
    DIRECTION INPUT ;
    USE SIGNAL ;
    PORT
      LAYER M4 ;
        RECT 431.808 10.368 432.000 10.392 ;
    END
  END lo_d[25]
  PIN lo_d[26]
    DIRECTION INPUT ;
    USE SIGNAL ;
    PORT
      LAYER M4 ;
        RECT 431.808 10.656 432.000 10.680 ;
    END
  END lo_d[26]
  PIN lo_d[27]
    DIRECTION INPUT ;
    USE SIGNAL ;
    PORT
      LAYER M4 ;
        RECT 431.808 10.944 432.000 10.968 ;
    END
  END lo_d[27]
  PIN lo_d[28]
    DIRECTION INPUT ;
    USE SIGNAL ;
    PORT
      LAYER M4 ;
        RECT 431.808 11.280 432.000 11.304 ;
    END
  END lo_d[28]
  PIN lo_d[29]
    DIRECTION INPUT ;
    USE SIGNAL ;
    PORT
      LAYER M4 ;
        RECT 431.808 11.568 432.000 11.592 ;
    END
  END lo_d[29]
  PIN lo_d[30]
    DIRECTION INPUT ;
    USE SIGNAL ;
    PORT
      LAYER M4 ;
        RECT 431.808 11.856 432.000 11.880 ;
    END
  END lo_d[30]
  PIN lo_d[31]
    DIRECTION INPUT ;
    USE SIGNAL ;
    PORT
      LAYER M4 ;
        RECT 431.808 12.144 432.000 12.168 ;
    END
  END lo_d[31]
  PIN lo_d[32]
    DIRECTION INPUT ;
    USE SIGNAL ;
    PORT
      LAYER M4 ;
        RECT 431.808 12.480 432.000 12.504 ;
    END
  END lo_d[32]
  PIN lo_d[33]
    DIRECTION INPUT ;
    USE SIGNAL ;
    PORT
      LAYER M4 ;
        RECT 431.808 12.768 432.000 12.792 ;
    END
  END lo_d[33]
  PIN lo_d[34]
    DIRECTION INPUT ;
    USE SIGNAL ;
    PORT
      LAYER M4 ;
        RECT 431.808 13.056 432.000 13.080 ;
    END
  END lo_d[34]
  PIN lo_d[35]
    DIRECTION INPUT ;
    USE SIGNAL ;
    PORT
      LAYER M4 ;
        RECT 431.808 13.344 432.000 13.368 ;
    END
  END lo_d[35]
  PIN lo_d[36]
    DIRECTION INPUT ;
    USE SIGNAL ;
    PORT
      LAYER M4 ;
        RECT 431.808 13.632 432.000 13.656 ;
    END
  END lo_d[36]
  PIN lo_d[37]
    DIRECTION INPUT ;
    USE SIGNAL ;
    PORT
      LAYER M4 ;
        RECT 431.808 13.968 432.000 13.992 ;
    END
  END lo_d[37]
  PIN lo_d[38]
    DIRECTION INPUT ;
    USE SIGNAL ;
    PORT
      LAYER M4 ;
        RECT 431.808 14.256 432.000 14.280 ;
    END
  END lo_d[38]
  PIN lo_d[39]
    DIRECTION INPUT ;
    USE SIGNAL ;
    PORT
      LAYER M4 ;
        RECT 431.808 14.544 432.000 14.568 ;
    END
  END lo_d[39]
  PIN lo_d[40]
    DIRECTION INPUT ;
    USE SIGNAL ;
    PORT
      LAYER M4 ;
        RECT 431.808 14.832 432.000 14.856 ;
    END
  END lo_d[40]
  PIN lo_d[41]
    DIRECTION INPUT ;
    USE SIGNAL ;
    PORT
      LAYER M4 ;
        RECT 431.808 15.168 432.000 15.192 ;
    END
  END lo_d[41]
  PIN lo_d[42]
    DIRECTION INPUT ;
    USE SIGNAL ;
    PORT
      LAYER M4 ;
        RECT 431.808 15.456 432.000 15.480 ;
    END
  END lo_d[42]
  PIN lo_d[43]
    DIRECTION INPUT ;
    USE SIGNAL ;
    PORT
      LAYER M4 ;
        RECT 431.808 15.744 432.000 15.768 ;
    END
  END lo_d[43]
  PIN lo_d[44]
    DIRECTION INPUT ;
    USE SIGNAL ;
    PORT
      LAYER M4 ;
        RECT 431.808 16.032 432.000 16.056 ;
    END
  END lo_d[44]
  PIN lo_d[45]
    DIRECTION INPUT ;
    USE SIGNAL ;
    PORT
      LAYER M4 ;
        RECT 431.808 16.368 432.000 16.392 ;
    END
  END lo_d[45]
  PIN lo_d[46]
    DIRECTION INPUT ;
    USE SIGNAL ;
    PORT
      LAYER M4 ;
        RECT 431.808 16.656 432.000 16.680 ;
    END
  END lo_d[46]
  PIN lo_d[47]
    DIRECTION INPUT ;
    USE SIGNAL ;
    PORT
      LAYER M4 ;
        RECT 431.808 16.944 432.000 16.968 ;
    END
  END lo_d[47]
  PIN lo_d[48]
    DIRECTION INPUT ;
    USE SIGNAL ;
    PORT
      LAYER M4 ;
        RECT 431.808 17.232 432.000 17.256 ;
    END
  END lo_d[48]
  PIN lo_d[49]
    DIRECTION INPUT ;
    USE SIGNAL ;
    PORT
      LAYER M4 ;
        RECT 431.808 17.520 432.000 17.544 ;
    END
  END lo_d[49]
  PIN lo_d[50]
    DIRECTION INPUT ;
    USE SIGNAL ;
    PORT
      LAYER M4 ;
        RECT 431.808 17.856 432.000 17.880 ;
    END
  END lo_d[50]
  PIN lo_d[51]
    DIRECTION INPUT ;
    USE SIGNAL ;
    PORT
      LAYER M4 ;
        RECT 431.808 18.144 432.000 18.168 ;
    END
  END lo_d[51]
  PIN lo_d[52]
    DIRECTION INPUT ;
    USE SIGNAL ;
    PORT
      LAYER M4 ;
        RECT 431.808 18.432 432.000 18.456 ;
    END
  END lo_d[52]
  PIN lo_d[53]
    DIRECTION INPUT ;
    USE SIGNAL ;
    PORT
      LAYER M4 ;
        RECT 431.808 18.720 432.000 18.744 ;
    END
  END lo_d[53]
  PIN lo_d[54]
    DIRECTION INPUT ;
    USE SIGNAL ;
    PORT
      LAYER M4 ;
        RECT 431.808 19.056 432.000 19.080 ;
    END
  END lo_d[54]
  PIN lo_d[55]
    DIRECTION INPUT ;
    USE SIGNAL ;
    PORT
      LAYER M4 ;
        RECT 431.808 19.344 432.000 19.368 ;
    END
  END lo_d[55]
  PIN lo_d[56]
    DIRECTION INPUT ;
    USE SIGNAL ;
    PORT
      LAYER M4 ;
        RECT 431.808 19.632 432.000 19.656 ;
    END
  END lo_d[56]
  PIN lo_d[57]
    DIRECTION INPUT ;
    USE SIGNAL ;
    PORT
      LAYER M4 ;
        RECT 431.808 19.920 432.000 19.944 ;
    END
  END lo_d[57]
  PIN lo_d[58]
    DIRECTION INPUT ;
    USE SIGNAL ;
    PORT
      LAYER M4 ;
        RECT 431.808 20.208 432.000 20.232 ;
    END
  END lo_d[58]
  PIN lo_d[59]
    DIRECTION INPUT ;
    USE SIGNAL ;
    PORT
      LAYER M4 ;
        RECT 431.808 20.544 432.000 20.568 ;
    END
  END lo_d[59]
  PIN lo_d[60]
    DIRECTION INPUT ;
    USE SIGNAL ;
    PORT
      LAYER M4 ;
        RECT 431.808 20.832 432.000 20.856 ;
    END
  END lo_d[60]
  PIN lo_d[61]
    DIRECTION INPUT ;
    USE SIGNAL ;
    PORT
      LAYER M4 ;
        RECT 431.808 21.120 432.000 21.144 ;
    END
  END lo_d[61]
  PIN lo_d[62]
    DIRECTION INPUT ;
    USE SIGNAL ;
    PORT
      LAYER M4 ;
        RECT 431.808 21.408 432.000 21.432 ;
    END
  END lo_d[62]
  PIN lo_d[63]
    DIRECTION INPUT ;
    USE SIGNAL ;
    PORT
      LAYER M4 ;
        RECT 431.808 21.744 432.000 21.768 ;
    END
  END lo_d[63]
  PIN lo_d[64]
    DIRECTION INPUT ;
    USE SIGNAL ;
    PORT
      LAYER M4 ;
        RECT 431.808 22.032 432.000 22.056 ;
    END
  END lo_d[64]
  PIN lo_d[65]
    DIRECTION INPUT ;
    USE SIGNAL ;
    PORT
      LAYER M4 ;
        RECT 431.808 22.320 432.000 22.344 ;
    END
  END lo_d[65]
  PIN lo_d[66]
    DIRECTION INPUT ;
    USE SIGNAL ;
    PORT
      LAYER M4 ;
        RECT 431.808 22.608 432.000 22.632 ;
    END
  END lo_d[66]
  PIN lo_d[67]
    DIRECTION INPUT ;
    USE SIGNAL ;
    PORT
      LAYER M4 ;
        RECT 431.808 22.896 432.000 22.920 ;
    END
  END lo_d[67]
  PIN lo_d[68]
    DIRECTION INPUT ;
    USE SIGNAL ;
    PORT
      LAYER M4 ;
        RECT 431.808 23.232 432.000 23.256 ;
    END
  END lo_d[68]
  PIN lo_d[69]
    DIRECTION INPUT ;
    USE SIGNAL ;
    PORT
      LAYER M4 ;
        RECT 431.808 23.520 432.000 23.544 ;
    END
  END lo_d[69]
  PIN lo_d[70]
    DIRECTION INPUT ;
    USE SIGNAL ;
    PORT
      LAYER M4 ;
        RECT 431.808 23.808 432.000 23.832 ;
    END
  END lo_d[70]
  PIN lo_d[71]
    DIRECTION INPUT ;
    USE SIGNAL ;
    PORT
      LAYER M4 ;
        RECT 431.808 24.096 432.000 24.120 ;
    END
  END lo_d[71]
  PIN lo_d[72]
    DIRECTION INPUT ;
    USE SIGNAL ;
    PORT
      LAYER M4 ;
        RECT 431.808 24.432 432.000 24.456 ;
    END
  END lo_d[72]
  PIN lo_d[73]
    DIRECTION INPUT ;
    USE SIGNAL ;
    PORT
      LAYER M4 ;
        RECT 431.808 24.720 432.000 24.744 ;
    END
  END lo_d[73]
  PIN lo_d[74]
    DIRECTION INPUT ;
    USE SIGNAL ;
    PORT
      LAYER M4 ;
        RECT 431.808 25.008 432.000 25.032 ;
    END
  END lo_d[74]
  PIN lo_d[75]
    DIRECTION INPUT ;
    USE SIGNAL ;
    PORT
      LAYER M4 ;
        RECT 431.808 25.296 432.000 25.320 ;
    END
  END lo_d[75]
  PIN lo_d[76]
    DIRECTION INPUT ;
    USE SIGNAL ;
    PORT
      LAYER M4 ;
        RECT 431.808 25.632 432.000 25.656 ;
    END
  END lo_d[76]
  PIN lo_d[77]
    DIRECTION INPUT ;
    USE SIGNAL ;
    PORT
      LAYER M4 ;
        RECT 431.808 25.920 432.000 25.944 ;
    END
  END lo_d[77]
  PIN lo_d[78]
    DIRECTION INPUT ;
    USE SIGNAL ;
    PORT
      LAYER M4 ;
        RECT 431.808 26.208 432.000 26.232 ;
    END
  END lo_d[78]
  PIN lo_d[79]
    DIRECTION INPUT ;
    USE SIGNAL ;
    PORT
      LAYER M4 ;
        RECT 431.808 26.496 432.000 26.520 ;
    END
  END lo_d[79]
  PIN lo_d[80]
    DIRECTION INPUT ;
    USE SIGNAL ;
    PORT
      LAYER M4 ;
        RECT 431.808 26.784 432.000 26.808 ;
    END
  END lo_d[80]
  PIN lo_d[81]
    DIRECTION INPUT ;
    USE SIGNAL ;
    PORT
      LAYER M4 ;
        RECT 431.808 27.120 432.000 27.144 ;
    END
  END lo_d[81]
  PIN lo_d[82]
    DIRECTION INPUT ;
    USE SIGNAL ;
    PORT
      LAYER M4 ;
        RECT 431.808 27.408 432.000 27.432 ;
    END
  END lo_d[82]
  PIN lo_d[83]
    DIRECTION INPUT ;
    USE SIGNAL ;
    PORT
      LAYER M4 ;
        RECT 431.808 27.696 432.000 27.720 ;
    END
  END lo_d[83]
  PIN lo_d[84]
    DIRECTION INPUT ;
    USE SIGNAL ;
    PORT
      LAYER M4 ;
        RECT 431.808 27.984 432.000 28.008 ;
    END
  END lo_d[84]
  PIN lo_d[85]
    DIRECTION INPUT ;
    USE SIGNAL ;
    PORT
      LAYER M4 ;
        RECT 431.808 28.320 432.000 28.344 ;
    END
  END lo_d[85]
  PIN lo_d[86]
    DIRECTION INPUT ;
    USE SIGNAL ;
    PORT
      LAYER M4 ;
        RECT 431.808 28.608 432.000 28.632 ;
    END
  END lo_d[86]
  PIN lo_d[87]
    DIRECTION INPUT ;
    USE SIGNAL ;
    PORT
      LAYER M4 ;
        RECT 431.808 28.896 432.000 28.920 ;
    END
  END lo_d[87]
  PIN lo_d[88]
    DIRECTION INPUT ;
    USE SIGNAL ;
    PORT
      LAYER M4 ;
        RECT 431.808 29.184 432.000 29.208 ;
    END
  END lo_d[88]
  PIN lo_d[89]
    DIRECTION INPUT ;
    USE SIGNAL ;
    PORT
      LAYER M4 ;
        RECT 431.808 29.472 432.000 29.496 ;
    END
  END lo_d[89]
  PIN lo_d[90]
    DIRECTION INPUT ;
    USE SIGNAL ;
    PORT
      LAYER M4 ;
        RECT 431.808 29.808 432.000 29.832 ;
    END
  END lo_d[90]
  PIN lo_d[91]
    DIRECTION INPUT ;
    USE SIGNAL ;
    PORT
      LAYER M4 ;
        RECT 431.808 30.096 432.000 30.120 ;
    END
  END lo_d[91]
  PIN lo_d[92]
    DIRECTION INPUT ;
    USE SIGNAL ;
    PORT
      LAYER M4 ;
        RECT 431.808 30.384 432.000 30.408 ;
    END
  END lo_d[92]
  PIN lo_d[93]
    DIRECTION INPUT ;
    USE SIGNAL ;
    PORT
      LAYER M4 ;
        RECT 431.808 30.672 432.000 30.696 ;
    END
  END lo_d[93]
  PIN lo_d[94]
    DIRECTION INPUT ;
    USE SIGNAL ;
    PORT
      LAYER M4 ;
        RECT 431.808 31.008 432.000 31.032 ;
    END
  END lo_d[94]
  PIN lo_d[95]
    DIRECTION INPUT ;
    USE SIGNAL ;
    PORT
      LAYER M4 ;
        RECT 431.808 31.296 432.000 31.320 ;
    END
  END lo_d[95]
  PIN lo_d[96]
    DIRECTION INPUT ;
    USE SIGNAL ;
    PORT
      LAYER M4 ;
        RECT 431.808 31.584 432.000 31.608 ;
    END
  END lo_d[96]
  PIN lo_d[97]
    DIRECTION INPUT ;
    USE SIGNAL ;
    PORT
      LAYER M4 ;
        RECT 431.808 31.872 432.000 31.896 ;
    END
  END lo_d[97]
  PIN lo_d[98]
    DIRECTION INPUT ;
    USE SIGNAL ;
    PORT
      LAYER M4 ;
        RECT 431.808 32.208 432.000 32.232 ;
    END
  END lo_d[98]
  PIN lo_d[99]
    DIRECTION INPUT ;
    USE SIGNAL ;
    PORT
      LAYER M4 ;
        RECT 431.808 32.496 432.000 32.520 ;
    END
  END lo_d[99]
  PIN lo_d[100]
    DIRECTION INPUT ;
    USE SIGNAL ;
    PORT
      LAYER M4 ;
        RECT 431.808 32.784 432.000 32.808 ;
    END
  END lo_d[100]
  PIN lo_d[101]
    DIRECTION INPUT ;
    USE SIGNAL ;
    PORT
      LAYER M4 ;
        RECT 431.808 33.072 432.000 33.096 ;
    END
  END lo_d[101]
  PIN lo_d[102]
    DIRECTION INPUT ;
    USE SIGNAL ;
    PORT
      LAYER M4 ;
        RECT 431.808 33.360 432.000 33.384 ;
    END
  END lo_d[102]
  PIN lo_d[103]
    DIRECTION INPUT ;
    USE SIGNAL ;
    PORT
      LAYER M4 ;
        RECT 431.808 33.696 432.000 33.720 ;
    END
  END lo_d[103]
  PIN lo_d[104]
    DIRECTION INPUT ;
    USE SIGNAL ;
    PORT
      LAYER M4 ;
        RECT 431.808 33.984 432.000 34.008 ;
    END
  END lo_d[104]
  PIN lo_d[105]
    DIRECTION INPUT ;
    USE SIGNAL ;
    PORT
      LAYER M4 ;
        RECT 431.808 34.272 432.000 34.296 ;
    END
  END lo_d[105]
  PIN lo_d[106]
    DIRECTION INPUT ;
    USE SIGNAL ;
    PORT
      LAYER M4 ;
        RECT 431.808 34.560 432.000 34.584 ;
    END
  END lo_d[106]
  PIN lo_d[107]
    DIRECTION INPUT ;
    USE SIGNAL ;
    PORT
      LAYER M4 ;
        RECT 431.808 34.896 432.000 34.920 ;
    END
  END lo_d[107]
  PIN lo_d[108]
    DIRECTION INPUT ;
    USE SIGNAL ;
    PORT
      LAYER M4 ;
        RECT 431.808 35.184 432.000 35.208 ;
    END
  END lo_d[108]
  PIN lo_d[109]
    DIRECTION INPUT ;
    USE SIGNAL ;
    PORT
      LAYER M4 ;
        RECT 431.808 35.472 432.000 35.496 ;
    END
  END lo_d[109]
  PIN lo_d[110]
    DIRECTION INPUT ;
    USE SIGNAL ;
    PORT
      LAYER M4 ;
        RECT 431.808 35.760 432.000 35.784 ;
    END
  END lo_d[110]
  PIN lo_d[111]
    DIRECTION INPUT ;
    USE SIGNAL ;
    PORT
      LAYER M4 ;
        RECT 431.808 36.048 432.000 36.072 ;
    END
  END lo_d[111]
  PIN lo_d[112]
    DIRECTION INPUT ;
    USE SIGNAL ;
    PORT
      LAYER M4 ;
        RECT 431.808 36.384 432.000 36.408 ;
    END
  END lo_d[112]
  PIN lo_d[113]
    DIRECTION INPUT ;
    USE SIGNAL ;
    PORT
      LAYER M4 ;
        RECT 431.808 36.672 432.000 36.696 ;
    END
  END lo_d[113]
  PIN lo_d[114]
    DIRECTION INPUT ;
    USE SIGNAL ;
    PORT
      LAYER M4 ;
        RECT 431.808 36.960 432.000 36.984 ;
    END
  END lo_d[114]
  PIN lo_d[115]
    DIRECTION INPUT ;
    USE SIGNAL ;
    PORT
      LAYER M4 ;
        RECT 431.808 37.248 432.000 37.272 ;
    END
  END lo_d[115]
  PIN lo_d[116]
    DIRECTION INPUT ;
    USE SIGNAL ;
    PORT
      LAYER M4 ;
        RECT 431.808 37.584 432.000 37.608 ;
    END
  END lo_d[116]
  PIN lo_d[117]
    DIRECTION INPUT ;
    USE SIGNAL ;
    PORT
      LAYER M4 ;
        RECT 431.808 37.872 432.000 37.896 ;
    END
  END lo_d[117]
  PIN lo_d[118]
    DIRECTION INPUT ;
    USE SIGNAL ;
    PORT
      LAYER M4 ;
        RECT 431.808 38.160 432.000 38.184 ;
    END
  END lo_d[118]
  PIN lo_d[119]
    DIRECTION INPUT ;
    USE SIGNAL ;
    PORT
      LAYER M4 ;
        RECT 431.808 38.448 432.000 38.472 ;
    END
  END lo_d[119]
  PIN lo_d[120]
    DIRECTION INPUT ;
    USE SIGNAL ;
    PORT
      LAYER M4 ;
        RECT 431.808 38.736 432.000 38.760 ;
    END
  END lo_d[120]
  PIN lo_d[121]
    DIRECTION INPUT ;
    USE SIGNAL ;
    PORT
      LAYER M4 ;
        RECT 431.808 39.072 432.000 39.096 ;
    END
  END lo_d[121]
  PIN lo_d[122]
    DIRECTION INPUT ;
    USE SIGNAL ;
    PORT
      LAYER M4 ;
        RECT 431.808 39.360 432.000 39.384 ;
    END
  END lo_d[122]
  PIN lo_d[123]
    DIRECTION INPUT ;
    USE SIGNAL ;
    PORT
      LAYER M4 ;
        RECT 431.808 39.648 432.000 39.672 ;
    END
  END lo_d[123]
  PIN lo_d[124]
    DIRECTION INPUT ;
    USE SIGNAL ;
    PORT
      LAYER M4 ;
        RECT 431.808 39.936 432.000 39.960 ;
    END
  END lo_d[124]
  PIN lo_d[125]
    DIRECTION INPUT ;
    USE SIGNAL ;
    PORT
      LAYER M4 ;
        RECT 431.808 40.272 432.000 40.296 ;
    END
  END lo_d[125]
  PIN lo_d[126]
    DIRECTION INPUT ;
    USE SIGNAL ;
    PORT
      LAYER M4 ;
        RECT 431.808 40.560 432.000 40.584 ;
    END
  END lo_d[126]
  PIN lo_d[127]
    DIRECTION INPUT ;
    USE SIGNAL ;
    PORT
      LAYER M4 ;
        RECT 431.808 40.848 432.000 40.872 ;
    END
  END lo_d[127]
  PIN lo_d[128]
    DIRECTION INPUT ;
    USE SIGNAL ;
    PORT
      LAYER M4 ;
        RECT 431.808 41.136 432.000 41.160 ;
    END
  END lo_d[128]
  PIN lo_d[129]
    DIRECTION INPUT ;
    USE SIGNAL ;
    PORT
      LAYER M4 ;
        RECT 431.808 41.472 432.000 41.496 ;
    END
  END lo_d[129]
  PIN lo_d[130]
    DIRECTION INPUT ;
    USE SIGNAL ;
    PORT
      LAYER M4 ;
        RECT 431.808 41.760 432.000 41.784 ;
    END
  END lo_d[130]
  PIN lo_d[131]
    DIRECTION INPUT ;
    USE SIGNAL ;
    PORT
      LAYER M4 ;
        RECT 431.808 42.048 432.000 42.072 ;
    END
  END lo_d[131]
  PIN lo_d[132]
    DIRECTION INPUT ;
    USE SIGNAL ;
    PORT
      LAYER M4 ;
        RECT 431.808 42.336 432.000 42.360 ;
    END
  END lo_d[132]
  PIN lo_d[133]
    DIRECTION INPUT ;
    USE SIGNAL ;
    PORT
      LAYER M4 ;
        RECT 431.808 42.624 432.000 42.648 ;
    END
  END lo_d[133]
  PIN lo_d[134]
    DIRECTION INPUT ;
    USE SIGNAL ;
    PORT
      LAYER M4 ;
        RECT 431.808 42.960 432.000 42.984 ;
    END
  END lo_d[134]
  PIN lo_d[135]
    DIRECTION INPUT ;
    USE SIGNAL ;
    PORT
      LAYER M4 ;
        RECT 431.808 43.248 432.000 43.272 ;
    END
  END lo_d[135]
  PIN lo_d[136]
    DIRECTION INPUT ;
    USE SIGNAL ;
    PORT
      LAYER M4 ;
        RECT 431.808 43.536 432.000 43.560 ;
    END
  END lo_d[136]
  PIN lo_d[137]
    DIRECTION INPUT ;
    USE SIGNAL ;
    PORT
      LAYER M4 ;
        RECT 431.808 43.824 432.000 43.848 ;
    END
  END lo_d[137]
  PIN lo_d[138]
    DIRECTION INPUT ;
    USE SIGNAL ;
    PORT
      LAYER M4 ;
        RECT 431.808 44.160 432.000 44.184 ;
    END
  END lo_d[138]
  PIN lo_d[139]
    DIRECTION INPUT ;
    USE SIGNAL ;
    PORT
      LAYER M4 ;
        RECT 431.808 44.448 432.000 44.472 ;
    END
  END lo_d[139]
  PIN lo_d[140]
    DIRECTION INPUT ;
    USE SIGNAL ;
    PORT
      LAYER M4 ;
        RECT 431.808 44.736 432.000 44.760 ;
    END
  END lo_d[140]
  PIN lo_d[141]
    DIRECTION INPUT ;
    USE SIGNAL ;
    PORT
      LAYER M4 ;
        RECT 431.808 45.024 432.000 45.048 ;
    END
  END lo_d[141]
  PIN lo_d[142]
    DIRECTION INPUT ;
    USE SIGNAL ;
    PORT
      LAYER M4 ;
        RECT 431.808 45.312 432.000 45.336 ;
    END
  END lo_d[142]
  PIN lo_d[143]
    DIRECTION INPUT ;
    USE SIGNAL ;
    PORT
      LAYER M4 ;
        RECT 431.808 45.648 432.000 45.672 ;
    END
  END lo_d[143]
  PIN lo_d[144]
    DIRECTION INPUT ;
    USE SIGNAL ;
    PORT
      LAYER M4 ;
        RECT 431.808 45.936 432.000 45.960 ;
    END
  END lo_d[144]
  PIN lo_d[145]
    DIRECTION INPUT ;
    USE SIGNAL ;
    PORT
      LAYER M4 ;
        RECT 431.808 46.224 432.000 46.248 ;
    END
  END lo_d[145]
  PIN lo_d[146]
    DIRECTION INPUT ;
    USE SIGNAL ;
    PORT
      LAYER M4 ;
        RECT 431.808 46.512 432.000 46.536 ;
    END
  END lo_d[146]
  PIN lo_d[147]
    DIRECTION INPUT ;
    USE SIGNAL ;
    PORT
      LAYER M4 ;
        RECT 431.808 46.848 432.000 46.872 ;
    END
  END lo_d[147]
  PIN lo_d[148]
    DIRECTION INPUT ;
    USE SIGNAL ;
    PORT
      LAYER M4 ;
        RECT 431.808 47.136 432.000 47.160 ;
    END
  END lo_d[148]
  PIN lo_d[149]
    DIRECTION INPUT ;
    USE SIGNAL ;
    PORT
      LAYER M4 ;
        RECT 431.808 47.424 432.000 47.448 ;
    END
  END lo_d[149]
  PIN lo_d[150]
    DIRECTION INPUT ;
    USE SIGNAL ;
    PORT
      LAYER M4 ;
        RECT 431.808 47.712 432.000 47.736 ;
    END
  END lo_d[150]
  PIN lo_d[151]
    DIRECTION INPUT ;
    USE SIGNAL ;
    PORT
      LAYER M4 ;
        RECT 431.808 48.048 432.000 48.072 ;
    END
  END lo_d[151]
  PIN lo_d[152]
    DIRECTION INPUT ;
    USE SIGNAL ;
    PORT
      LAYER M4 ;
        RECT 431.808 48.336 432.000 48.360 ;
    END
  END lo_d[152]
  PIN lo_d[153]
    DIRECTION INPUT ;
    USE SIGNAL ;
    PORT
      LAYER M4 ;
        RECT 431.808 48.624 432.000 48.648 ;
    END
  END lo_d[153]
  PIN lo_d[154]
    DIRECTION INPUT ;
    USE SIGNAL ;
    PORT
      LAYER M4 ;
        RECT 431.808 48.912 432.000 48.936 ;
    END
  END lo_d[154]
  PIN lo_d[155]
    DIRECTION INPUT ;
    USE SIGNAL ;
    PORT
      LAYER M4 ;
        RECT 431.808 49.200 432.000 49.224 ;
    END
  END lo_d[155]
  PIN lo_d[156]
    DIRECTION INPUT ;
    USE SIGNAL ;
    PORT
      LAYER M4 ;
        RECT 431.808 49.536 432.000 49.560 ;
    END
  END lo_d[156]
  PIN lo_d[157]
    DIRECTION INPUT ;
    USE SIGNAL ;
    PORT
      LAYER M4 ;
        RECT 431.808 49.824 432.000 49.848 ;
    END
  END lo_d[157]
  PIN lo_d[158]
    DIRECTION INPUT ;
    USE SIGNAL ;
    PORT
      LAYER M4 ;
        RECT 431.808 50.112 432.000 50.136 ;
    END
  END lo_d[158]
  PIN lo_d[159]
    DIRECTION INPUT ;
    USE SIGNAL ;
    PORT
      LAYER M4 ;
        RECT 431.808 50.400 432.000 50.424 ;
    END
  END lo_d[159]
  PIN lo_d[160]
    DIRECTION INPUT ;
    USE SIGNAL ;
    PORT
      LAYER M4 ;
        RECT 431.808 50.736 432.000 50.760 ;
    END
  END lo_d[160]
  PIN lo_d[161]
    DIRECTION INPUT ;
    USE SIGNAL ;
    PORT
      LAYER M4 ;
        RECT 431.808 51.024 432.000 51.048 ;
    END
  END lo_d[161]
  PIN lo_d[162]
    DIRECTION INPUT ;
    USE SIGNAL ;
    PORT
      LAYER M4 ;
        RECT 431.808 51.312 432.000 51.336 ;
    END
  END lo_d[162]
  PIN lo_d[163]
    DIRECTION INPUT ;
    USE SIGNAL ;
    PORT
      LAYER M4 ;
        RECT 431.808 51.600 432.000 51.624 ;
    END
  END lo_d[163]
  PIN lo_d[164]
    DIRECTION INPUT ;
    USE SIGNAL ;
    PORT
      LAYER M4 ;
        RECT 431.808 51.888 432.000 51.912 ;
    END
  END lo_d[164]
  PIN lo_d[165]
    DIRECTION INPUT ;
    USE SIGNAL ;
    PORT
      LAYER M4 ;
        RECT 431.808 52.224 432.000 52.248 ;
    END
  END lo_d[165]
  PIN lo_d[166]
    DIRECTION INPUT ;
    USE SIGNAL ;
    PORT
      LAYER M4 ;
        RECT 431.808 52.512 432.000 52.536 ;
    END
  END lo_d[166]
  PIN lo_d[167]
    DIRECTION INPUT ;
    USE SIGNAL ;
    PORT
      LAYER M4 ;
        RECT 431.808 52.800 432.000 52.824 ;
    END
  END lo_d[167]
  PIN lo_d[168]
    DIRECTION INPUT ;
    USE SIGNAL ;
    PORT
      LAYER M4 ;
        RECT 431.808 53.088 432.000 53.112 ;
    END
  END lo_d[168]
  PIN lo_d[169]
    DIRECTION INPUT ;
    USE SIGNAL ;
    PORT
      LAYER M4 ;
        RECT 431.808 53.424 432.000 53.448 ;
    END
  END lo_d[169]
  PIN lo_d[170]
    DIRECTION INPUT ;
    USE SIGNAL ;
    PORT
      LAYER M4 ;
        RECT 431.808 53.712 432.000 53.736 ;
    END
  END lo_d[170]
  PIN lo_d[171]
    DIRECTION INPUT ;
    USE SIGNAL ;
    PORT
      LAYER M4 ;
        RECT 431.808 54.000 432.000 54.024 ;
    END
  END lo_d[171]
  PIN lo_d[172]
    DIRECTION INPUT ;
    USE SIGNAL ;
    PORT
      LAYER M4 ;
        RECT 431.808 54.288 432.000 54.312 ;
    END
  END lo_d[172]
  PIN lo_d[173]
    DIRECTION INPUT ;
    USE SIGNAL ;
    PORT
      LAYER M4 ;
        RECT 431.808 54.576 432.000 54.600 ;
    END
  END lo_d[173]
  PIN lo_d[174]
    DIRECTION INPUT ;
    USE SIGNAL ;
    PORT
      LAYER M4 ;
        RECT 431.808 54.912 432.000 54.936 ;
    END
  END lo_d[174]
  PIN lo_d[175]
    DIRECTION INPUT ;
    USE SIGNAL ;
    PORT
      LAYER M4 ;
        RECT 431.808 55.200 432.000 55.224 ;
    END
  END lo_d[175]
  PIN lo_d[176]
    DIRECTION INPUT ;
    USE SIGNAL ;
    PORT
      LAYER M4 ;
        RECT 431.808 55.488 432.000 55.512 ;
    END
  END lo_d[176]
  PIN lo_d[177]
    DIRECTION INPUT ;
    USE SIGNAL ;
    PORT
      LAYER M4 ;
        RECT 431.808 55.776 432.000 55.800 ;
    END
  END lo_d[177]
  PIN lo_d[178]
    DIRECTION INPUT ;
    USE SIGNAL ;
    PORT
      LAYER M4 ;
        RECT 431.808 56.112 432.000 56.136 ;
    END
  END lo_d[178]
  PIN lo_d[179]
    DIRECTION INPUT ;
    USE SIGNAL ;
    PORT
      LAYER M4 ;
        RECT 431.808 56.400 432.000 56.424 ;
    END
  END lo_d[179]
  PIN lo_d[180]
    DIRECTION INPUT ;
    USE SIGNAL ;
    PORT
      LAYER M4 ;
        RECT 431.808 56.688 432.000 56.712 ;
    END
  END lo_d[180]
  PIN lo_d[181]
    DIRECTION INPUT ;
    USE SIGNAL ;
    PORT
      LAYER M4 ;
        RECT 431.808 56.976 432.000 57.000 ;
    END
  END lo_d[181]
  PIN lo_d[182]
    DIRECTION INPUT ;
    USE SIGNAL ;
    PORT
      LAYER M4 ;
        RECT 431.808 57.312 432.000 57.336 ;
    END
  END lo_d[182]
  PIN lo_d[183]
    DIRECTION INPUT ;
    USE SIGNAL ;
    PORT
      LAYER M4 ;
        RECT 431.808 57.600 432.000 57.624 ;
    END
  END lo_d[183]
  PIN lo_d[184]
    DIRECTION INPUT ;
    USE SIGNAL ;
    PORT
      LAYER M4 ;
        RECT 431.808 57.888 432.000 57.912 ;
    END
  END lo_d[184]
  PIN lo_d[185]
    DIRECTION INPUT ;
    USE SIGNAL ;
    PORT
      LAYER M4 ;
        RECT 431.808 58.176 432.000 58.200 ;
    END
  END lo_d[185]
  PIN lo_d[186]
    DIRECTION INPUT ;
    USE SIGNAL ;
    PORT
      LAYER M4 ;
        RECT 431.808 58.464 432.000 58.488 ;
    END
  END lo_d[186]
  PIN lo_d[187]
    DIRECTION INPUT ;
    USE SIGNAL ;
    PORT
      LAYER M4 ;
        RECT 431.808 58.800 432.000 58.824 ;
    END
  END lo_d[187]
  PIN lo_d[188]
    DIRECTION INPUT ;
    USE SIGNAL ;
    PORT
      LAYER M4 ;
        RECT 431.808 59.088 432.000 59.112 ;
    END
  END lo_d[188]
  PIN lo_d[189]
    DIRECTION INPUT ;
    USE SIGNAL ;
    PORT
      LAYER M4 ;
        RECT 431.808 59.376 432.000 59.400 ;
    END
  END lo_d[189]
  PIN lo_d[190]
    DIRECTION INPUT ;
    USE SIGNAL ;
    PORT
      LAYER M4 ;
        RECT 431.808 59.664 432.000 59.688 ;
    END
  END lo_d[190]
  PIN lo_d[191]
    DIRECTION INPUT ;
    USE SIGNAL ;
    PORT
      LAYER M4 ;
        RECT 431.808 60.000 432.000 60.024 ;
    END
  END lo_d[191]
  PIN lo_d[192]
    DIRECTION INPUT ;
    USE SIGNAL ;
    PORT
      LAYER M4 ;
        RECT 431.808 60.288 432.000 60.312 ;
    END
  END lo_d[192]
  PIN lo_d[193]
    DIRECTION INPUT ;
    USE SIGNAL ;
    PORT
      LAYER M4 ;
        RECT 431.808 60.576 432.000 60.600 ;
    END
  END lo_d[193]
  PIN lo_d[194]
    DIRECTION INPUT ;
    USE SIGNAL ;
    PORT
      LAYER M4 ;
        RECT 431.808 60.864 432.000 60.888 ;
    END
  END lo_d[194]
  PIN lo_d[195]
    DIRECTION INPUT ;
    USE SIGNAL ;
    PORT
      LAYER M4 ;
        RECT 431.808 61.152 432.000 61.176 ;
    END
  END lo_d[195]
  PIN lo_d[196]
    DIRECTION INPUT ;
    USE SIGNAL ;
    PORT
      LAYER M4 ;
        RECT 431.808 61.488 432.000 61.512 ;
    END
  END lo_d[196]
  PIN lo_d[197]
    DIRECTION INPUT ;
    USE SIGNAL ;
    PORT
      LAYER M4 ;
        RECT 431.808 61.776 432.000 61.800 ;
    END
  END lo_d[197]
  PIN lo_d[198]
    DIRECTION INPUT ;
    USE SIGNAL ;
    PORT
      LAYER M4 ;
        RECT 431.808 62.064 432.000 62.088 ;
    END
  END lo_d[198]
  PIN lo_d[199]
    DIRECTION INPUT ;
    USE SIGNAL ;
    PORT
      LAYER M4 ;
        RECT 431.808 62.352 432.000 62.376 ;
    END
  END lo_d[199]
  PIN lo_d[200]
    DIRECTION INPUT ;
    USE SIGNAL ;
    PORT
      LAYER M4 ;
        RECT 431.808 62.688 432.000 62.712 ;
    END
  END lo_d[200]
  PIN lo_d[201]
    DIRECTION INPUT ;
    USE SIGNAL ;
    PORT
      LAYER M4 ;
        RECT 431.808 62.976 432.000 63.000 ;
    END
  END lo_d[201]
  PIN lo_d[202]
    DIRECTION INPUT ;
    USE SIGNAL ;
    PORT
      LAYER M4 ;
        RECT 431.808 63.264 432.000 63.288 ;
    END
  END lo_d[202]
  PIN lo_d[203]
    DIRECTION INPUT ;
    USE SIGNAL ;
    PORT
      LAYER M4 ;
        RECT 431.808 63.552 432.000 63.576 ;
    END
  END lo_d[203]
  PIN lo_d[204]
    DIRECTION INPUT ;
    USE SIGNAL ;
    PORT
      LAYER M4 ;
        RECT 431.808 63.888 432.000 63.912 ;
    END
  END lo_d[204]
  PIN lo_d[205]
    DIRECTION INPUT ;
    USE SIGNAL ;
    PORT
      LAYER M4 ;
        RECT 431.808 64.176 432.000 64.200 ;
    END
  END lo_d[205]
  PIN lo_d[206]
    DIRECTION INPUT ;
    USE SIGNAL ;
    PORT
      LAYER M4 ;
        RECT 431.808 64.464 432.000 64.488 ;
    END
  END lo_d[206]
  PIN lo_d[207]
    DIRECTION INPUT ;
    USE SIGNAL ;
    PORT
      LAYER M4 ;
        RECT 431.808 64.752 432.000 64.776 ;
    END
  END lo_d[207]
  PIN lo_d[208]
    DIRECTION INPUT ;
    USE SIGNAL ;
    PORT
      LAYER M4 ;
        RECT 431.808 65.040 432.000 65.064 ;
    END
  END lo_d[208]
  PIN lo_d[209]
    DIRECTION INPUT ;
    USE SIGNAL ;
    PORT
      LAYER M4 ;
        RECT 431.808 65.376 432.000 65.400 ;
    END
  END lo_d[209]
  PIN lo_d[210]
    DIRECTION INPUT ;
    USE SIGNAL ;
    PORT
      LAYER M4 ;
        RECT 431.808 65.664 432.000 65.688 ;
    END
  END lo_d[210]
  PIN lo_d[211]
    DIRECTION INPUT ;
    USE SIGNAL ;
    PORT
      LAYER M4 ;
        RECT 431.808 65.952 432.000 65.976 ;
    END
  END lo_d[211]
  PIN lo_d[212]
    DIRECTION INPUT ;
    USE SIGNAL ;
    PORT
      LAYER M4 ;
        RECT 431.808 66.240 432.000 66.264 ;
    END
  END lo_d[212]
  PIN lo_d[213]
    DIRECTION INPUT ;
    USE SIGNAL ;
    PORT
      LAYER M4 ;
        RECT 431.808 66.576 432.000 66.600 ;
    END
  END lo_d[213]
  PIN lo_d[214]
    DIRECTION INPUT ;
    USE SIGNAL ;
    PORT
      LAYER M4 ;
        RECT 431.808 66.864 432.000 66.888 ;
    END
  END lo_d[214]
  PIN lo_d[215]
    DIRECTION INPUT ;
    USE SIGNAL ;
    PORT
      LAYER M4 ;
        RECT 431.808 67.152 432.000 67.176 ;
    END
  END lo_d[215]
  PIN lo_d[216]
    DIRECTION INPUT ;
    USE SIGNAL ;
    PORT
      LAYER M4 ;
        RECT 431.808 67.440 432.000 67.464 ;
    END
  END lo_d[216]
  PIN lo_d[217]
    DIRECTION INPUT ;
    USE SIGNAL ;
    PORT
      LAYER M4 ;
        RECT 431.808 67.728 432.000 67.752 ;
    END
  END lo_d[217]
  PIN lo_d[218]
    DIRECTION INPUT ;
    USE SIGNAL ;
    PORT
      LAYER M4 ;
        RECT 431.808 68.064 432.000 68.088 ;
    END
  END lo_d[218]
  PIN lo_d[219]
    DIRECTION INPUT ;
    USE SIGNAL ;
    PORT
      LAYER M4 ;
        RECT 431.808 68.352 432.000 68.376 ;
    END
  END lo_d[219]
  PIN lo_d[220]
    DIRECTION INPUT ;
    USE SIGNAL ;
    PORT
      LAYER M4 ;
        RECT 431.808 68.640 432.000 68.664 ;
    END
  END lo_d[220]
  PIN lo_d[221]
    DIRECTION INPUT ;
    USE SIGNAL ;
    PORT
      LAYER M4 ;
        RECT 431.808 68.928 432.000 68.952 ;
    END
  END lo_d[221]
  PIN lo_d[222]
    DIRECTION INPUT ;
    USE SIGNAL ;
    PORT
      LAYER M4 ;
        RECT 431.808 69.264 432.000 69.288 ;
    END
  END lo_d[222]
  PIN lo_d[223]
    DIRECTION INPUT ;
    USE SIGNAL ;
    PORT
      LAYER M4 ;
        RECT 431.808 69.552 432.000 69.576 ;
    END
  END lo_d[223]
  PIN lo_d[224]
    DIRECTION INPUT ;
    USE SIGNAL ;
    PORT
      LAYER M4 ;
        RECT 431.808 69.840 432.000 69.864 ;
    END
  END lo_d[224]
  PIN lo_d[225]
    DIRECTION INPUT ;
    USE SIGNAL ;
    PORT
      LAYER M4 ;
        RECT 431.808 70.128 432.000 70.152 ;
    END
  END lo_d[225]
  PIN lo_d[226]
    DIRECTION INPUT ;
    USE SIGNAL ;
    PORT
      LAYER M4 ;
        RECT 431.808 70.416 432.000 70.440 ;
    END
  END lo_d[226]
  PIN lo_d[227]
    DIRECTION INPUT ;
    USE SIGNAL ;
    PORT
      LAYER M4 ;
        RECT 431.808 70.752 432.000 70.776 ;
    END
  END lo_d[227]
  PIN lo_d[228]
    DIRECTION INPUT ;
    USE SIGNAL ;
    PORT
      LAYER M4 ;
        RECT 431.808 71.040 432.000 71.064 ;
    END
  END lo_d[228]
  PIN lo_d[229]
    DIRECTION INPUT ;
    USE SIGNAL ;
    PORT
      LAYER M4 ;
        RECT 431.808 71.328 432.000 71.352 ;
    END
  END lo_d[229]
  PIN lo_d[230]
    DIRECTION INPUT ;
    USE SIGNAL ;
    PORT
      LAYER M4 ;
        RECT 431.808 71.616 432.000 71.640 ;
    END
  END lo_d[230]
  PIN lo_d[231]
    DIRECTION INPUT ;
    USE SIGNAL ;
    PORT
      LAYER M4 ;
        RECT 431.808 71.952 432.000 71.976 ;
    END
  END lo_d[231]
  PIN lo_d[232]
    DIRECTION INPUT ;
    USE SIGNAL ;
    PORT
      LAYER M4 ;
        RECT 431.808 72.240 432.000 72.264 ;
    END
  END lo_d[232]
  PIN lo_d[233]
    DIRECTION INPUT ;
    USE SIGNAL ;
    PORT
      LAYER M4 ;
        RECT 431.808 72.528 432.000 72.552 ;
    END
  END lo_d[233]
  PIN lo_d[234]
    DIRECTION INPUT ;
    USE SIGNAL ;
    PORT
      LAYER M4 ;
        RECT 431.808 72.816 432.000 72.840 ;
    END
  END lo_d[234]
  PIN lo_d[235]
    DIRECTION INPUT ;
    USE SIGNAL ;
    PORT
      LAYER M4 ;
        RECT 431.808 73.152 432.000 73.176 ;
    END
  END lo_d[235]
  PIN lo_d[236]
    DIRECTION INPUT ;
    USE SIGNAL ;
    PORT
      LAYER M4 ;
        RECT 431.808 73.440 432.000 73.464 ;
    END
  END lo_d[236]
  PIN lo_d[237]
    DIRECTION INPUT ;
    USE SIGNAL ;
    PORT
      LAYER M4 ;
        RECT 431.808 73.728 432.000 73.752 ;
    END
  END lo_d[237]
  PIN lo_d[238]
    DIRECTION INPUT ;
    USE SIGNAL ;
    PORT
      LAYER M4 ;
        RECT 431.808 74.016 432.000 74.040 ;
    END
  END lo_d[238]
  PIN lo_d[239]
    DIRECTION INPUT ;
    USE SIGNAL ;
    PORT
      LAYER M4 ;
        RECT 431.808 74.304 432.000 74.328 ;
    END
  END lo_d[239]
  PIN lo_d[240]
    DIRECTION INPUT ;
    USE SIGNAL ;
    PORT
      LAYER M4 ;
        RECT 431.808 74.640 432.000 74.664 ;
    END
  END lo_d[240]
  PIN lo_d[241]
    DIRECTION INPUT ;
    USE SIGNAL ;
    PORT
      LAYER M4 ;
        RECT 431.808 74.928 432.000 74.952 ;
    END
  END lo_d[241]
  PIN lo_d[242]
    DIRECTION INPUT ;
    USE SIGNAL ;
    PORT
      LAYER M4 ;
        RECT 431.808 75.216 432.000 75.240 ;
    END
  END lo_d[242]
  PIN lo_d[243]
    DIRECTION INPUT ;
    USE SIGNAL ;
    PORT
      LAYER M4 ;
        RECT 431.808 75.504 432.000 75.528 ;
    END
  END lo_d[243]
  PIN lo_d[244]
    DIRECTION INPUT ;
    USE SIGNAL ;
    PORT
      LAYER M4 ;
        RECT 431.808 75.840 432.000 75.864 ;
    END
  END lo_d[244]
  PIN lo_d[245]
    DIRECTION INPUT ;
    USE SIGNAL ;
    PORT
      LAYER M4 ;
        RECT 431.808 76.128 432.000 76.152 ;
    END
  END lo_d[245]
  PIN lo_d[246]
    DIRECTION INPUT ;
    USE SIGNAL ;
    PORT
      LAYER M4 ;
        RECT 431.808 76.416 432.000 76.440 ;
    END
  END lo_d[246]
  PIN lo_d[247]
    DIRECTION INPUT ;
    USE SIGNAL ;
    PORT
      LAYER M4 ;
        RECT 431.808 76.704 432.000 76.728 ;
    END
  END lo_d[247]
  PIN lo_d[248]
    DIRECTION INPUT ;
    USE SIGNAL ;
    PORT
      LAYER M4 ;
        RECT 431.808 76.992 432.000 77.016 ;
    END
  END lo_d[248]
  PIN lo_d[249]
    DIRECTION INPUT ;
    USE SIGNAL ;
    PORT
      LAYER M4 ;
        RECT 431.808 77.328 432.000 77.352 ;
    END
  END lo_d[249]
  PIN lo_d[250]
    DIRECTION INPUT ;
    USE SIGNAL ;
    PORT
      LAYER M4 ;
        RECT 431.808 77.616 432.000 77.640 ;
    END
  END lo_d[250]
  PIN lo_d[251]
    DIRECTION INPUT ;
    USE SIGNAL ;
    PORT
      LAYER M4 ;
        RECT 431.808 77.904 432.000 77.928 ;
    END
  END lo_d[251]
  PIN lo_d[252]
    DIRECTION INPUT ;
    USE SIGNAL ;
    PORT
      LAYER M4 ;
        RECT 431.808 78.192 432.000 78.216 ;
    END
  END lo_d[252]
  PIN lo_d[253]
    DIRECTION INPUT ;
    USE SIGNAL ;
    PORT
      LAYER M4 ;
        RECT 431.808 78.528 432.000 78.552 ;
    END
  END lo_d[253]
  PIN lo_d[254]
    DIRECTION INPUT ;
    USE SIGNAL ;
    PORT
      LAYER M4 ;
        RECT 431.808 78.816 432.000 78.840 ;
    END
  END lo_d[254]
  PIN lo_d[255]
    DIRECTION INPUT ;
    USE SIGNAL ;
    PORT
      LAYER M4 ;
        RECT 431.808 79.104 432.000 79.128 ;
    END
  END lo_d[255]
  PIN lo_d[256]
    DIRECTION INPUT ;
    USE SIGNAL ;
    PORT
      LAYER M4 ;
        RECT 431.808 79.392 432.000 79.416 ;
    END
  END lo_d[256]
  PIN lo_d[257]
    DIRECTION INPUT ;
    USE SIGNAL ;
    PORT
      LAYER M4 ;
        RECT 431.808 79.728 432.000 79.752 ;
    END
  END lo_d[257]
  PIN lo_d[258]
    DIRECTION INPUT ;
    USE SIGNAL ;
    PORT
      LAYER M4 ;
        RECT 431.808 80.016 432.000 80.040 ;
    END
  END lo_d[258]
  PIN lo_d[259]
    DIRECTION INPUT ;
    USE SIGNAL ;
    PORT
      LAYER M4 ;
        RECT 431.808 80.304 432.000 80.328 ;
    END
  END lo_d[259]
  PIN lo_d[260]
    DIRECTION INPUT ;
    USE SIGNAL ;
    PORT
      LAYER M4 ;
        RECT 431.808 80.592 432.000 80.616 ;
    END
  END lo_d[260]
  PIN lo_d[261]
    DIRECTION INPUT ;
    USE SIGNAL ;
    PORT
      LAYER M4 ;
        RECT 431.808 80.880 432.000 80.904 ;
    END
  END lo_d[261]
  PIN lo_d[262]
    DIRECTION INPUT ;
    USE SIGNAL ;
    PORT
      LAYER M4 ;
        RECT 431.808 81.216 432.000 81.240 ;
    END
  END lo_d[262]
  PIN lo_d[263]
    DIRECTION INPUT ;
    USE SIGNAL ;
    PORT
      LAYER M4 ;
        RECT 431.808 81.504 432.000 81.528 ;
    END
  END lo_d[263]
  PIN lo_d[264]
    DIRECTION INPUT ;
    USE SIGNAL ;
    PORT
      LAYER M4 ;
        RECT 431.808 81.792 432.000 81.816 ;
    END
  END lo_d[264]
  PIN lo_d[265]
    DIRECTION INPUT ;
    USE SIGNAL ;
    PORT
      LAYER M4 ;
        RECT 431.808 82.080 432.000 82.104 ;
    END
  END lo_d[265]
  PIN lo_d[266]
    DIRECTION INPUT ;
    USE SIGNAL ;
    PORT
      LAYER M4 ;
        RECT 431.808 82.416 432.000 82.440 ;
    END
  END lo_d[266]
  PIN lo_d[267]
    DIRECTION INPUT ;
    USE SIGNAL ;
    PORT
      LAYER M4 ;
        RECT 431.808 82.704 432.000 82.728 ;
    END
  END lo_d[267]
  PIN lo_d[268]
    DIRECTION INPUT ;
    USE SIGNAL ;
    PORT
      LAYER M4 ;
        RECT 431.808 82.992 432.000 83.016 ;
    END
  END lo_d[268]
  PIN lo_d[269]
    DIRECTION INPUT ;
    USE SIGNAL ;
    PORT
      LAYER M4 ;
        RECT 431.808 83.280 432.000 83.304 ;
    END
  END lo_d[269]
  PIN lo_d[270]
    DIRECTION INPUT ;
    USE SIGNAL ;
    PORT
      LAYER M4 ;
        RECT 431.808 83.568 432.000 83.592 ;
    END
  END lo_d[270]
  PIN lo_d[271]
    DIRECTION INPUT ;
    USE SIGNAL ;
    PORT
      LAYER M4 ;
        RECT 431.808 83.904 432.000 83.928 ;
    END
  END lo_d[271]
  PIN lo_d[272]
    DIRECTION INPUT ;
    USE SIGNAL ;
    PORT
      LAYER M4 ;
        RECT 431.808 84.192 432.000 84.216 ;
    END
  END lo_d[272]
  PIN lo_d[273]
    DIRECTION INPUT ;
    USE SIGNAL ;
    PORT
      LAYER M4 ;
        RECT 431.808 84.480 432.000 84.504 ;
    END
  END lo_d[273]
  PIN lo_d[274]
    DIRECTION INPUT ;
    USE SIGNAL ;
    PORT
      LAYER M4 ;
        RECT 431.808 84.768 432.000 84.792 ;
    END
  END lo_d[274]
  PIN lo_d[275]
    DIRECTION INPUT ;
    USE SIGNAL ;
    PORT
      LAYER M4 ;
        RECT 431.808 85.104 432.000 85.128 ;
    END
  END lo_d[275]
  PIN lo_d[276]
    DIRECTION INPUT ;
    USE SIGNAL ;
    PORT
      LAYER M4 ;
        RECT 431.808 85.392 432.000 85.416 ;
    END
  END lo_d[276]
  PIN lo_d[277]
    DIRECTION INPUT ;
    USE SIGNAL ;
    PORT
      LAYER M4 ;
        RECT 431.808 85.680 432.000 85.704 ;
    END
  END lo_d[277]
  PIN lo_d[278]
    DIRECTION INPUT ;
    USE SIGNAL ;
    PORT
      LAYER M4 ;
        RECT 431.808 85.968 432.000 85.992 ;
    END
  END lo_d[278]
  PIN lo_d[279]
    DIRECTION INPUT ;
    USE SIGNAL ;
    PORT
      LAYER M4 ;
        RECT 431.808 86.256 432.000 86.280 ;
    END
  END lo_d[279]
  PIN lo_d[280]
    DIRECTION INPUT ;
    USE SIGNAL ;
    PORT
      LAYER M4 ;
        RECT 431.808 86.592 432.000 86.616 ;
    END
  END lo_d[280]
  PIN lo_d[281]
    DIRECTION INPUT ;
    USE SIGNAL ;
    PORT
      LAYER M4 ;
        RECT 431.808 86.880 432.000 86.904 ;
    END
  END lo_d[281]
  PIN lo_d[282]
    DIRECTION INPUT ;
    USE SIGNAL ;
    PORT
      LAYER M4 ;
        RECT 431.808 87.168 432.000 87.192 ;
    END
  END lo_d[282]
  PIN lo_d[283]
    DIRECTION INPUT ;
    USE SIGNAL ;
    PORT
      LAYER M4 ;
        RECT 431.808 87.456 432.000 87.480 ;
    END
  END lo_d[283]
  PIN lo_d[284]
    DIRECTION INPUT ;
    USE SIGNAL ;
    PORT
      LAYER M4 ;
        RECT 431.808 87.792 432.000 87.816 ;
    END
  END lo_d[284]
  PIN lo_d[285]
    DIRECTION INPUT ;
    USE SIGNAL ;
    PORT
      LAYER M4 ;
        RECT 431.808 88.080 432.000 88.104 ;
    END
  END lo_d[285]
  PIN lo_d[286]
    DIRECTION INPUT ;
    USE SIGNAL ;
    PORT
      LAYER M4 ;
        RECT 431.808 88.368 432.000 88.392 ;
    END
  END lo_d[286]
  PIN lo_d[287]
    DIRECTION INPUT ;
    USE SIGNAL ;
    PORT
      LAYER M4 ;
        RECT 431.808 88.656 432.000 88.680 ;
    END
  END lo_d[287]
  PIN lo_d[288]
    DIRECTION INPUT ;
    USE SIGNAL ;
    PORT
      LAYER M4 ;
        RECT 431.808 88.992 432.000 89.016 ;
    END
  END lo_d[288]
  PIN lo_d[289]
    DIRECTION INPUT ;
    USE SIGNAL ;
    PORT
      LAYER M4 ;
        RECT 431.808 89.280 432.000 89.304 ;
    END
  END lo_d[289]
  PIN lo_d[290]
    DIRECTION INPUT ;
    USE SIGNAL ;
    PORT
      LAYER M4 ;
        RECT 431.808 89.568 432.000 89.592 ;
    END
  END lo_d[290]
  PIN lo_d[291]
    DIRECTION INPUT ;
    USE SIGNAL ;
    PORT
      LAYER M4 ;
        RECT 431.808 89.856 432.000 89.880 ;
    END
  END lo_d[291]
  PIN lo_d[292]
    DIRECTION INPUT ;
    USE SIGNAL ;
    PORT
      LAYER M4 ;
        RECT 431.808 90.144 432.000 90.168 ;
    END
  END lo_d[292]
  PIN lo_d[293]
    DIRECTION INPUT ;
    USE SIGNAL ;
    PORT
      LAYER M4 ;
        RECT 431.808 90.480 432.000 90.504 ;
    END
  END lo_d[293]
  PIN lo_d[294]
    DIRECTION INPUT ;
    USE SIGNAL ;
    PORT
      LAYER M4 ;
        RECT 431.808 90.768 432.000 90.792 ;
    END
  END lo_d[294]
  PIN lo_d[295]
    DIRECTION INPUT ;
    USE SIGNAL ;
    PORT
      LAYER M4 ;
        RECT 431.808 91.056 432.000 91.080 ;
    END
  END lo_d[295]
  PIN lo_d[296]
    DIRECTION INPUT ;
    USE SIGNAL ;
    PORT
      LAYER M4 ;
        RECT 431.808 91.344 432.000 91.368 ;
    END
  END lo_d[296]
  PIN lo_d[297]
    DIRECTION INPUT ;
    USE SIGNAL ;
    PORT
      LAYER M4 ;
        RECT 431.808 91.680 432.000 91.704 ;
    END
  END lo_d[297]
  PIN lo_d[298]
    DIRECTION INPUT ;
    USE SIGNAL ;
    PORT
      LAYER M4 ;
        RECT 431.808 91.968 432.000 91.992 ;
    END
  END lo_d[298]
  PIN lo_d[299]
    DIRECTION INPUT ;
    USE SIGNAL ;
    PORT
      LAYER M4 ;
        RECT 431.808 92.256 432.000 92.280 ;
    END
  END lo_d[299]
  PIN lo_d[300]
    DIRECTION INPUT ;
    USE SIGNAL ;
    PORT
      LAYER M4 ;
        RECT 431.808 92.544 432.000 92.568 ;
    END
  END lo_d[300]
  PIN lo_d[301]
    DIRECTION INPUT ;
    USE SIGNAL ;
    PORT
      LAYER M4 ;
        RECT 431.808 92.832 432.000 92.856 ;
    END
  END lo_d[301]
  PIN lo_d[302]
    DIRECTION INPUT ;
    USE SIGNAL ;
    PORT
      LAYER M4 ;
        RECT 431.808 93.168 432.000 93.192 ;
    END
  END lo_d[302]
  PIN lo_d[303]
    DIRECTION INPUT ;
    USE SIGNAL ;
    PORT
      LAYER M4 ;
        RECT 431.808 93.456 432.000 93.480 ;
    END
  END lo_d[303]
  PIN lo_d[304]
    DIRECTION INPUT ;
    USE SIGNAL ;
    PORT
      LAYER M4 ;
        RECT 431.808 93.744 432.000 93.768 ;
    END
  END lo_d[304]
  PIN lo_d[305]
    DIRECTION INPUT ;
    USE SIGNAL ;
    PORT
      LAYER M4 ;
        RECT 431.808 94.032 432.000 94.056 ;
    END
  END lo_d[305]
  PIN lo_d[306]
    DIRECTION INPUT ;
    USE SIGNAL ;
    PORT
      LAYER M4 ;
        RECT 431.808 94.368 432.000 94.392 ;
    END
  END lo_d[306]
  PIN lo_d[307]
    DIRECTION INPUT ;
    USE SIGNAL ;
    PORT
      LAYER M4 ;
        RECT 431.808 94.656 432.000 94.680 ;
    END
  END lo_d[307]
  PIN lo_d[308]
    DIRECTION INPUT ;
    USE SIGNAL ;
    PORT
      LAYER M4 ;
        RECT 431.808 94.944 432.000 94.968 ;
    END
  END lo_d[308]
  PIN lo_d[309]
    DIRECTION INPUT ;
    USE SIGNAL ;
    PORT
      LAYER M4 ;
        RECT 431.808 95.232 432.000 95.256 ;
    END
  END lo_d[309]
  PIN lo_d[310]
    DIRECTION INPUT ;
    USE SIGNAL ;
    PORT
      LAYER M4 ;
        RECT 431.808 95.568 432.000 95.592 ;
    END
  END lo_d[310]
  PIN lo_d[311]
    DIRECTION INPUT ;
    USE SIGNAL ;
    PORT
      LAYER M4 ;
        RECT 431.808 95.856 432.000 95.880 ;
    END
  END lo_d[311]
  PIN lo_d[312]
    DIRECTION INPUT ;
    USE SIGNAL ;
    PORT
      LAYER M4 ;
        RECT 431.808 96.144 432.000 96.168 ;
    END
  END lo_d[312]
  PIN lo_d[313]
    DIRECTION INPUT ;
    USE SIGNAL ;
    PORT
      LAYER M4 ;
        RECT 431.808 96.432 432.000 96.456 ;
    END
  END lo_d[313]
  PIN lo_d[314]
    DIRECTION INPUT ;
    USE SIGNAL ;
    PORT
      LAYER M4 ;
        RECT 431.808 96.720 432.000 96.744 ;
    END
  END lo_d[314]
  PIN lo_d[315]
    DIRECTION INPUT ;
    USE SIGNAL ;
    PORT
      LAYER M4 ;
        RECT 431.808 97.056 432.000 97.080 ;
    END
  END lo_d[315]
  PIN lo_d[316]
    DIRECTION INPUT ;
    USE SIGNAL ;
    PORT
      LAYER M4 ;
        RECT 431.808 97.344 432.000 97.368 ;
    END
  END lo_d[316]
  PIN lo_d[317]
    DIRECTION INPUT ;
    USE SIGNAL ;
    PORT
      LAYER M4 ;
        RECT 431.808 97.632 432.000 97.656 ;
    END
  END lo_d[317]
  PIN lo_d[318]
    DIRECTION INPUT ;
    USE SIGNAL ;
    PORT
      LAYER M4 ;
        RECT 431.808 97.920 432.000 97.944 ;
    END
  END lo_d[318]
  PIN lo_d[319]
    DIRECTION INPUT ;
    USE SIGNAL ;
    PORT
      LAYER M4 ;
        RECT 431.808 98.256 432.000 98.280 ;
    END
  END lo_d[319]
  PIN lo_d[320]
    DIRECTION INPUT ;
    USE SIGNAL ;
    PORT
      LAYER M4 ;
        RECT 431.808 98.544 432.000 98.568 ;
    END
  END lo_d[320]
  PIN lo_d[321]
    DIRECTION INPUT ;
    USE SIGNAL ;
    PORT
      LAYER M4 ;
        RECT 431.808 98.832 432.000 98.856 ;
    END
  END lo_d[321]
  PIN lo_d[322]
    DIRECTION INPUT ;
    USE SIGNAL ;
    PORT
      LAYER M4 ;
        RECT 431.808 99.120 432.000 99.144 ;
    END
  END lo_d[322]
  PIN lo_d[323]
    DIRECTION INPUT ;
    USE SIGNAL ;
    PORT
      LAYER M4 ;
        RECT 431.808 99.408 432.000 99.432 ;
    END
  END lo_d[323]
  PIN lo_d[324]
    DIRECTION INPUT ;
    USE SIGNAL ;
    PORT
      LAYER M4 ;
        RECT 431.808 99.744 432.000 99.768 ;
    END
  END lo_d[324]
  PIN lo_d[325]
    DIRECTION INPUT ;
    USE SIGNAL ;
    PORT
      LAYER M4 ;
        RECT 431.808 100.032 432.000 100.056 ;
    END
  END lo_d[325]
  PIN lo_d[326]
    DIRECTION INPUT ;
    USE SIGNAL ;
    PORT
      LAYER M4 ;
        RECT 431.808 100.320 432.000 100.344 ;
    END
  END lo_d[326]
  PIN lo_d[327]
    DIRECTION INPUT ;
    USE SIGNAL ;
    PORT
      LAYER M4 ;
        RECT 431.808 100.608 432.000 100.632 ;
    END
  END lo_d[327]
  PIN lo_d[328]
    DIRECTION INPUT ;
    USE SIGNAL ;
    PORT
      LAYER M4 ;
        RECT 431.808 100.944 432.000 100.968 ;
    END
  END lo_d[328]
  PIN lo_d[329]
    DIRECTION INPUT ;
    USE SIGNAL ;
    PORT
      LAYER M4 ;
        RECT 431.808 101.232 432.000 101.256 ;
    END
  END lo_d[329]
  PIN lo_d[330]
    DIRECTION INPUT ;
    USE SIGNAL ;
    PORT
      LAYER M4 ;
        RECT 431.808 101.520 432.000 101.544 ;
    END
  END lo_d[330]
  PIN lo_d[331]
    DIRECTION INPUT ;
    USE SIGNAL ;
    PORT
      LAYER M4 ;
        RECT 431.808 101.808 432.000 101.832 ;
    END
  END lo_d[331]
  PIN lo_d[332]
    DIRECTION INPUT ;
    USE SIGNAL ;
    PORT
      LAYER M4 ;
        RECT 431.808 102.096 432.000 102.120 ;
    END
  END lo_d[332]
  PIN lo_d[333]
    DIRECTION INPUT ;
    USE SIGNAL ;
    PORT
      LAYER M4 ;
        RECT 431.808 102.432 432.000 102.456 ;
    END
  END lo_d[333]
  PIN lo_d[334]
    DIRECTION INPUT ;
    USE SIGNAL ;
    PORT
      LAYER M4 ;
        RECT 431.808 102.720 432.000 102.744 ;
    END
  END lo_d[334]
  PIN lo_d[335]
    DIRECTION INPUT ;
    USE SIGNAL ;
    PORT
      LAYER M4 ;
        RECT 431.808 103.008 432.000 103.032 ;
    END
  END lo_d[335]
  PIN lo_d[336]
    DIRECTION INPUT ;
    USE SIGNAL ;
    PORT
      LAYER M4 ;
        RECT 431.808 103.296 432.000 103.320 ;
    END
  END lo_d[336]
  PIN lo_d[337]
    DIRECTION INPUT ;
    USE SIGNAL ;
    PORT
      LAYER M4 ;
        RECT 431.808 103.632 432.000 103.656 ;
    END
  END lo_d[337]
  PIN lo_d[338]
    DIRECTION INPUT ;
    USE SIGNAL ;
    PORT
      LAYER M4 ;
        RECT 431.808 103.920 432.000 103.944 ;
    END
  END lo_d[338]
  PIN lo_d[339]
    DIRECTION INPUT ;
    USE SIGNAL ;
    PORT
      LAYER M4 ;
        RECT 431.808 104.208 432.000 104.232 ;
    END
  END lo_d[339]
  PIN lo_d[340]
    DIRECTION INPUT ;
    USE SIGNAL ;
    PORT
      LAYER M4 ;
        RECT 431.808 104.496 432.000 104.520 ;
    END
  END lo_d[340]
  PIN lo_d[341]
    DIRECTION INPUT ;
    USE SIGNAL ;
    PORT
      LAYER M4 ;
        RECT 431.808 104.832 432.000 104.856 ;
    END
  END lo_d[341]
  PIN lo_d[342]
    DIRECTION INPUT ;
    USE SIGNAL ;
    PORT
      LAYER M4 ;
        RECT 431.808 105.120 432.000 105.144 ;
    END
  END lo_d[342]
  PIN lo_d[343]
    DIRECTION INPUT ;
    USE SIGNAL ;
    PORT
      LAYER M4 ;
        RECT 431.808 105.408 432.000 105.432 ;
    END
  END lo_d[343]
  PIN lo_d[344]
    DIRECTION INPUT ;
    USE SIGNAL ;
    PORT
      LAYER M4 ;
        RECT 431.808 105.696 432.000 105.720 ;
    END
  END lo_d[344]
  PIN lo_d[345]
    DIRECTION INPUT ;
    USE SIGNAL ;
    PORT
      LAYER M4 ;
        RECT 431.808 105.984 432.000 106.008 ;
    END
  END lo_d[345]
  PIN lo_d[346]
    DIRECTION INPUT ;
    USE SIGNAL ;
    PORT
      LAYER M4 ;
        RECT 431.808 106.320 432.000 106.344 ;
    END
  END lo_d[346]
  PIN lo_d[347]
    DIRECTION INPUT ;
    USE SIGNAL ;
    PORT
      LAYER M4 ;
        RECT 431.808 106.608 432.000 106.632 ;
    END
  END lo_d[347]
  PIN lo_d[348]
    DIRECTION INPUT ;
    USE SIGNAL ;
    PORT
      LAYER M4 ;
        RECT 431.808 106.896 432.000 106.920 ;
    END
  END lo_d[348]
  PIN lo_d[349]
    DIRECTION INPUT ;
    USE SIGNAL ;
    PORT
      LAYER M4 ;
        RECT 431.808 107.184 432.000 107.208 ;
    END
  END lo_d[349]
  PIN lo_d[350]
    DIRECTION INPUT ;
    USE SIGNAL ;
    PORT
      LAYER M4 ;
        RECT 431.808 107.520 432.000 107.544 ;
    END
  END lo_d[350]
  PIN lo_d[351]
    DIRECTION INPUT ;
    USE SIGNAL ;
    PORT
      LAYER M4 ;
        RECT 431.808 107.808 432.000 107.832 ;
    END
  END lo_d[351]
  PIN lo_d[352]
    DIRECTION INPUT ;
    USE SIGNAL ;
    PORT
      LAYER M4 ;
        RECT 431.808 108.096 432.000 108.120 ;
    END
  END lo_d[352]
  PIN lo_d[353]
    DIRECTION INPUT ;
    USE SIGNAL ;
    PORT
      LAYER M4 ;
        RECT 431.808 108.384 432.000 108.408 ;
    END
  END lo_d[353]
  PIN lo_d[354]
    DIRECTION INPUT ;
    USE SIGNAL ;
    PORT
      LAYER M4 ;
        RECT 431.808 108.672 432.000 108.696 ;
    END
  END lo_d[354]
  PIN lo_d[355]
    DIRECTION INPUT ;
    USE SIGNAL ;
    PORT
      LAYER M4 ;
        RECT 431.808 109.008 432.000 109.032 ;
    END
  END lo_d[355]
  PIN lo_d[356]
    DIRECTION INPUT ;
    USE SIGNAL ;
    PORT
      LAYER M4 ;
        RECT 431.808 109.296 432.000 109.320 ;
    END
  END lo_d[356]
  PIN lo_d[357]
    DIRECTION INPUT ;
    USE SIGNAL ;
    PORT
      LAYER M4 ;
        RECT 431.808 109.584 432.000 109.608 ;
    END
  END lo_d[357]
  PIN lo_d[358]
    DIRECTION INPUT ;
    USE SIGNAL ;
    PORT
      LAYER M4 ;
        RECT 431.808 109.872 432.000 109.896 ;
    END
  END lo_d[358]
  PIN lo_d[359]
    DIRECTION INPUT ;
    USE SIGNAL ;
    PORT
      LAYER M4 ;
        RECT 431.808 110.208 432.000 110.232 ;
    END
  END lo_d[359]
  PIN lo_d[360]
    DIRECTION INPUT ;
    USE SIGNAL ;
    PORT
      LAYER M4 ;
        RECT 431.808 110.496 432.000 110.520 ;
    END
  END lo_d[360]
  PIN lo_d[361]
    DIRECTION INPUT ;
    USE SIGNAL ;
    PORT
      LAYER M4 ;
        RECT 431.808 110.784 432.000 110.808 ;
    END
  END lo_d[361]
  PIN lo_d[362]
    DIRECTION INPUT ;
    USE SIGNAL ;
    PORT
      LAYER M4 ;
        RECT 431.808 111.072 432.000 111.096 ;
    END
  END lo_d[362]
  PIN lo_d[363]
    DIRECTION INPUT ;
    USE SIGNAL ;
    PORT
      LAYER M4 ;
        RECT 431.808 111.408 432.000 111.432 ;
    END
  END lo_d[363]
  PIN lo_d[364]
    DIRECTION INPUT ;
    USE SIGNAL ;
    PORT
      LAYER M4 ;
        RECT 431.808 111.696 432.000 111.720 ;
    END
  END lo_d[364]
  PIN lo_d[365]
    DIRECTION INPUT ;
    USE SIGNAL ;
    PORT
      LAYER M4 ;
        RECT 431.808 111.984 432.000 112.008 ;
    END
  END lo_d[365]
  PIN lo_d[366]
    DIRECTION INPUT ;
    USE SIGNAL ;
    PORT
      LAYER M4 ;
        RECT 431.808 112.272 432.000 112.296 ;
    END
  END lo_d[366]
  PIN lo_d[367]
    DIRECTION INPUT ;
    USE SIGNAL ;
    PORT
      LAYER M4 ;
        RECT 431.808 112.560 432.000 112.584 ;
    END
  END lo_d[367]
  PIN lo_d[368]
    DIRECTION INPUT ;
    USE SIGNAL ;
    PORT
      LAYER M4 ;
        RECT 431.808 112.896 432.000 112.920 ;
    END
  END lo_d[368]
  PIN lo_d[369]
    DIRECTION INPUT ;
    USE SIGNAL ;
    PORT
      LAYER M4 ;
        RECT 431.808 113.184 432.000 113.208 ;
    END
  END lo_d[369]
  PIN lo_d[370]
    DIRECTION INPUT ;
    USE SIGNAL ;
    PORT
      LAYER M4 ;
        RECT 431.808 113.472 432.000 113.496 ;
    END
  END lo_d[370]
  PIN lo_d[371]
    DIRECTION INPUT ;
    USE SIGNAL ;
    PORT
      LAYER M4 ;
        RECT 431.808 113.760 432.000 113.784 ;
    END
  END lo_d[371]
  PIN lo_d[372]
    DIRECTION INPUT ;
    USE SIGNAL ;
    PORT
      LAYER M4 ;
        RECT 431.808 114.096 432.000 114.120 ;
    END
  END lo_d[372]
  PIN lo_d[373]
    DIRECTION INPUT ;
    USE SIGNAL ;
    PORT
      LAYER M4 ;
        RECT 431.808 114.384 432.000 114.408 ;
    END
  END lo_d[373]
  PIN lo_d[374]
    DIRECTION INPUT ;
    USE SIGNAL ;
    PORT
      LAYER M4 ;
        RECT 431.808 114.672 432.000 114.696 ;
    END
  END lo_d[374]
  PIN lo_d[375]
    DIRECTION INPUT ;
    USE SIGNAL ;
    PORT
      LAYER M4 ;
        RECT 431.808 114.960 432.000 114.984 ;
    END
  END lo_d[375]
  PIN lo_d[376]
    DIRECTION INPUT ;
    USE SIGNAL ;
    PORT
      LAYER M4 ;
        RECT 431.808 115.248 432.000 115.272 ;
    END
  END lo_d[376]
  PIN lo_d[377]
    DIRECTION INPUT ;
    USE SIGNAL ;
    PORT
      LAYER M4 ;
        RECT 431.808 115.584 432.000 115.608 ;
    END
  END lo_d[377]
  PIN lo_d[378]
    DIRECTION INPUT ;
    USE SIGNAL ;
    PORT
      LAYER M4 ;
        RECT 431.808 115.872 432.000 115.896 ;
    END
  END lo_d[378]
  PIN lo_d[379]
    DIRECTION INPUT ;
    USE SIGNAL ;
    PORT
      LAYER M4 ;
        RECT 431.808 116.160 432.000 116.184 ;
    END
  END lo_d[379]
  PIN lo_d[380]
    DIRECTION INPUT ;
    USE SIGNAL ;
    PORT
      LAYER M4 ;
        RECT 431.808 116.448 432.000 116.472 ;
    END
  END lo_d[380]
  PIN lo_d[381]
    DIRECTION INPUT ;
    USE SIGNAL ;
    PORT
      LAYER M4 ;
        RECT 431.808 116.784 432.000 116.808 ;
    END
  END lo_d[381]
  PIN lo_d[382]
    DIRECTION INPUT ;
    USE SIGNAL ;
    PORT
      LAYER M4 ;
        RECT 431.808 117.072 432.000 117.096 ;
    END
  END lo_d[382]
  PIN lo_d[383]
    DIRECTION INPUT ;
    USE SIGNAL ;
    PORT
      LAYER M4 ;
        RECT 431.808 117.360 432.000 117.384 ;
    END
  END lo_d[383]
  PIN lo_d[384]
    DIRECTION INPUT ;
    USE SIGNAL ;
    PORT
      LAYER M4 ;
        RECT 431.808 117.648 432.000 117.672 ;
    END
  END lo_d[384]
  PIN lo_d[385]
    DIRECTION INPUT ;
    USE SIGNAL ;
    PORT
      LAYER M4 ;
        RECT 431.808 117.936 432.000 117.960 ;
    END
  END lo_d[385]
  PIN lo_d[386]
    DIRECTION INPUT ;
    USE SIGNAL ;
    PORT
      LAYER M4 ;
        RECT 431.808 118.272 432.000 118.296 ;
    END
  END lo_d[386]
  PIN lo_d[387]
    DIRECTION INPUT ;
    USE SIGNAL ;
    PORT
      LAYER M4 ;
        RECT 431.808 118.560 432.000 118.584 ;
    END
  END lo_d[387]
  PIN lo_d[388]
    DIRECTION INPUT ;
    USE SIGNAL ;
    PORT
      LAYER M4 ;
        RECT 431.808 118.848 432.000 118.872 ;
    END
  END lo_d[388]
  PIN lo_d[389]
    DIRECTION INPUT ;
    USE SIGNAL ;
    PORT
      LAYER M4 ;
        RECT 431.808 119.136 432.000 119.160 ;
    END
  END lo_d[389]
  PIN lo_d[390]
    DIRECTION INPUT ;
    USE SIGNAL ;
    PORT
      LAYER M4 ;
        RECT 431.808 119.472 432.000 119.496 ;
    END
  END lo_d[390]
  PIN lo_d[391]
    DIRECTION INPUT ;
    USE SIGNAL ;
    PORT
      LAYER M4 ;
        RECT 431.808 119.760 432.000 119.784 ;
    END
  END lo_d[391]
  PIN lo_d[392]
    DIRECTION INPUT ;
    USE SIGNAL ;
    PORT
      LAYER M4 ;
        RECT 431.808 120.048 432.000 120.072 ;
    END
  END lo_d[392]
  PIN lo_d[393]
    DIRECTION INPUT ;
    USE SIGNAL ;
    PORT
      LAYER M4 ;
        RECT 431.808 120.336 432.000 120.360 ;
    END
  END lo_d[393]
  PIN lo_d[394]
    DIRECTION INPUT ;
    USE SIGNAL ;
    PORT
      LAYER M4 ;
        RECT 431.808 120.672 432.000 120.696 ;
    END
  END lo_d[394]
  PIN lo_d[395]
    DIRECTION INPUT ;
    USE SIGNAL ;
    PORT
      LAYER M4 ;
        RECT 431.808 120.960 432.000 120.984 ;
    END
  END lo_d[395]
  PIN lo_d[396]
    DIRECTION INPUT ;
    USE SIGNAL ;
    PORT
      LAYER M4 ;
        RECT 431.808 121.248 432.000 121.272 ;
    END
  END lo_d[396]
  PIN lo_d[397]
    DIRECTION INPUT ;
    USE SIGNAL ;
    PORT
      LAYER M4 ;
        RECT 431.808 121.536 432.000 121.560 ;
    END
  END lo_d[397]
  PIN lo_d[398]
    DIRECTION INPUT ;
    USE SIGNAL ;
    PORT
      LAYER M4 ;
        RECT 431.808 121.824 432.000 121.848 ;
    END
  END lo_d[398]
  PIN lo_d[399]
    DIRECTION INPUT ;
    USE SIGNAL ;
    PORT
      LAYER M4 ;
        RECT 431.808 122.160 432.000 122.184 ;
    END
  END lo_d[399]
  PIN lo_d[400]
    DIRECTION INPUT ;
    USE SIGNAL ;
    PORT
      LAYER M4 ;
        RECT 431.808 122.448 432.000 122.472 ;
    END
  END lo_d[400]
  PIN lo_d[401]
    DIRECTION INPUT ;
    USE SIGNAL ;
    PORT
      LAYER M4 ;
        RECT 431.808 122.736 432.000 122.760 ;
    END
  END lo_d[401]
  PIN lo_d[402]
    DIRECTION INPUT ;
    USE SIGNAL ;
    PORT
      LAYER M4 ;
        RECT 431.808 123.024 432.000 123.048 ;
    END
  END lo_d[402]
  PIN lo_d[403]
    DIRECTION INPUT ;
    USE SIGNAL ;
    PORT
      LAYER M4 ;
        RECT 431.808 123.360 432.000 123.384 ;
    END
  END lo_d[403]
  PIN lo_d[404]
    DIRECTION INPUT ;
    USE SIGNAL ;
    PORT
      LAYER M4 ;
        RECT 431.808 123.648 432.000 123.672 ;
    END
  END lo_d[404]
  PIN lo_d[405]
    DIRECTION INPUT ;
    USE SIGNAL ;
    PORT
      LAYER M4 ;
        RECT 431.808 123.936 432.000 123.960 ;
    END
  END lo_d[405]
  PIN lo_d[406]
    DIRECTION INPUT ;
    USE SIGNAL ;
    PORT
      LAYER M4 ;
        RECT 431.808 124.224 432.000 124.248 ;
    END
  END lo_d[406]
  PIN lo_d[407]
    DIRECTION INPUT ;
    USE SIGNAL ;
    PORT
      LAYER M4 ;
        RECT 431.808 124.512 432.000 124.536 ;
    END
  END lo_d[407]
  PIN lo_d[408]
    DIRECTION INPUT ;
    USE SIGNAL ;
    PORT
      LAYER M4 ;
        RECT 431.808 124.848 432.000 124.872 ;
    END
  END lo_d[408]
  PIN lo_d[409]
    DIRECTION INPUT ;
    USE SIGNAL ;
    PORT
      LAYER M4 ;
        RECT 431.808 125.136 432.000 125.160 ;
    END
  END lo_d[409]
  PIN lo_d[410]
    DIRECTION INPUT ;
    USE SIGNAL ;
    PORT
      LAYER M4 ;
        RECT 431.808 125.424 432.000 125.448 ;
    END
  END lo_d[410]
  PIN lo_d[411]
    DIRECTION INPUT ;
    USE SIGNAL ;
    PORT
      LAYER M4 ;
        RECT 431.808 125.712 432.000 125.736 ;
    END
  END lo_d[411]
  PIN lo_d[412]
    DIRECTION INPUT ;
    USE SIGNAL ;
    PORT
      LAYER M4 ;
        RECT 431.808 126.048 432.000 126.072 ;
    END
  END lo_d[412]
  PIN lo_d[413]
    DIRECTION INPUT ;
    USE SIGNAL ;
    PORT
      LAYER M4 ;
        RECT 431.808 126.336 432.000 126.360 ;
    END
  END lo_d[413]
  PIN lo_d[414]
    DIRECTION INPUT ;
    USE SIGNAL ;
    PORT
      LAYER M4 ;
        RECT 431.808 126.624 432.000 126.648 ;
    END
  END lo_d[414]
  PIN lo_d[415]
    DIRECTION INPUT ;
    USE SIGNAL ;
    PORT
      LAYER M4 ;
        RECT 431.808 126.912 432.000 126.936 ;
    END
  END lo_d[415]
  PIN lo_d[416]
    DIRECTION INPUT ;
    USE SIGNAL ;
    PORT
      LAYER M4 ;
        RECT 431.808 127.248 432.000 127.272 ;
    END
  END lo_d[416]
  PIN lo_d[417]
    DIRECTION INPUT ;
    USE SIGNAL ;
    PORT
      LAYER M4 ;
        RECT 431.808 127.536 432.000 127.560 ;
    END
  END lo_d[417]
  PIN lo_d[418]
    DIRECTION INPUT ;
    USE SIGNAL ;
    PORT
      LAYER M4 ;
        RECT 431.808 127.824 432.000 127.848 ;
    END
  END lo_d[418]
  PIN lo_d[419]
    DIRECTION INPUT ;
    USE SIGNAL ;
    PORT
      LAYER M4 ;
        RECT 431.808 128.112 432.000 128.136 ;
    END
  END lo_d[419]
  PIN lo_d[420]
    DIRECTION INPUT ;
    USE SIGNAL ;
    PORT
      LAYER M4 ;
        RECT 431.808 128.400 432.000 128.424 ;
    END
  END lo_d[420]
  PIN lo_d[421]
    DIRECTION INPUT ;
    USE SIGNAL ;
    PORT
      LAYER M4 ;
        RECT 431.808 128.736 432.000 128.760 ;
    END
  END lo_d[421]
  PIN lo_d[422]
    DIRECTION INPUT ;
    USE SIGNAL ;
    PORT
      LAYER M4 ;
        RECT 431.808 129.024 432.000 129.048 ;
    END
  END lo_d[422]
  PIN lo_d[423]
    DIRECTION INPUT ;
    USE SIGNAL ;
    PORT
      LAYER M4 ;
        RECT 431.808 129.312 432.000 129.336 ;
    END
  END lo_d[423]
  PIN lo_d[424]
    DIRECTION INPUT ;
    USE SIGNAL ;
    PORT
      LAYER M4 ;
        RECT 431.808 129.600 432.000 129.624 ;
    END
  END lo_d[424]
  PIN lo_d[425]
    DIRECTION INPUT ;
    USE SIGNAL ;
    PORT
      LAYER M4 ;
        RECT 431.808 129.936 432.000 129.960 ;
    END
  END lo_d[425]
  PIN lo_d[426]
    DIRECTION INPUT ;
    USE SIGNAL ;
    PORT
      LAYER M4 ;
        RECT 431.808 130.224 432.000 130.248 ;
    END
  END lo_d[426]
  PIN lo_d[427]
    DIRECTION INPUT ;
    USE SIGNAL ;
    PORT
      LAYER M4 ;
        RECT 431.808 130.512 432.000 130.536 ;
    END
  END lo_d[427]
  PIN lo_d[428]
    DIRECTION INPUT ;
    USE SIGNAL ;
    PORT
      LAYER M4 ;
        RECT 431.808 130.800 432.000 130.824 ;
    END
  END lo_d[428]
  PIN lo_d[429]
    DIRECTION INPUT ;
    USE SIGNAL ;
    PORT
      LAYER M4 ;
        RECT 431.808 131.088 432.000 131.112 ;
    END
  END lo_d[429]
  PIN lo_d[430]
    DIRECTION INPUT ;
    USE SIGNAL ;
    PORT
      LAYER M4 ;
        RECT 431.808 131.424 432.000 131.448 ;
    END
  END lo_d[430]
  PIN lo_d[431]
    DIRECTION INPUT ;
    USE SIGNAL ;
    PORT
      LAYER M4 ;
        RECT 431.808 131.712 432.000 131.736 ;
    END
  END lo_d[431]
  PIN lo_d[432]
    DIRECTION INPUT ;
    USE SIGNAL ;
    PORT
      LAYER M4 ;
        RECT 431.808 132.000 432.000 132.024 ;
    END
  END lo_d[432]
  PIN lo_d[433]
    DIRECTION INPUT ;
    USE SIGNAL ;
    PORT
      LAYER M4 ;
        RECT 431.808 132.288 432.000 132.312 ;
    END
  END lo_d[433]
  PIN lo_d[434]
    DIRECTION INPUT ;
    USE SIGNAL ;
    PORT
      LAYER M4 ;
        RECT 431.808 132.624 432.000 132.648 ;
    END
  END lo_d[434]
  PIN lo_d[435]
    DIRECTION INPUT ;
    USE SIGNAL ;
    PORT
      LAYER M4 ;
        RECT 431.808 132.912 432.000 132.936 ;
    END
  END lo_d[435]
  PIN lo_d[436]
    DIRECTION INPUT ;
    USE SIGNAL ;
    PORT
      LAYER M4 ;
        RECT 431.808 133.200 432.000 133.224 ;
    END
  END lo_d[436]
  PIN lo_d[437]
    DIRECTION INPUT ;
    USE SIGNAL ;
    PORT
      LAYER M4 ;
        RECT 431.808 133.488 432.000 133.512 ;
    END
  END lo_d[437]
  PIN lo_d[438]
    DIRECTION INPUT ;
    USE SIGNAL ;
    PORT
      LAYER M4 ;
        RECT 431.808 133.776 432.000 133.800 ;
    END
  END lo_d[438]
  PIN lo_d[439]
    DIRECTION INPUT ;
    USE SIGNAL ;
    PORT
      LAYER M4 ;
        RECT 431.808 134.112 432.000 134.136 ;
    END
  END lo_d[439]
  PIN lo_d[440]
    DIRECTION INPUT ;
    USE SIGNAL ;
    PORT
      LAYER M4 ;
        RECT 431.808 134.400 432.000 134.424 ;
    END
  END lo_d[440]
  PIN lo_d[441]
    DIRECTION INPUT ;
    USE SIGNAL ;
    PORT
      LAYER M4 ;
        RECT 431.808 134.688 432.000 134.712 ;
    END
  END lo_d[441]
  PIN lo_d[442]
    DIRECTION INPUT ;
    USE SIGNAL ;
    PORT
      LAYER M4 ;
        RECT 431.808 134.976 432.000 135.000 ;
    END
  END lo_d[442]
  PIN lo_d[443]
    DIRECTION INPUT ;
    USE SIGNAL ;
    PORT
      LAYER M4 ;
        RECT 431.808 135.312 432.000 135.336 ;
    END
  END lo_d[443]
  PIN lo_d[444]
    DIRECTION INPUT ;
    USE SIGNAL ;
    PORT
      LAYER M4 ;
        RECT 431.808 135.600 432.000 135.624 ;
    END
  END lo_d[444]
  PIN lo_d[445]
    DIRECTION INPUT ;
    USE SIGNAL ;
    PORT
      LAYER M4 ;
        RECT 431.808 135.888 432.000 135.912 ;
    END
  END lo_d[445]
  PIN lo_d[446]
    DIRECTION INPUT ;
    USE SIGNAL ;
    PORT
      LAYER M4 ;
        RECT 431.808 136.176 432.000 136.200 ;
    END
  END lo_d[446]
  PIN lo_d[447]
    DIRECTION INPUT ;
    USE SIGNAL ;
    PORT
      LAYER M4 ;
        RECT 431.808 136.512 432.000 136.536 ;
    END
  END lo_d[447]
  PIN lo_d[448]
    DIRECTION INPUT ;
    USE SIGNAL ;
    PORT
      LAYER M4 ;
        RECT 431.808 136.800 432.000 136.824 ;
    END
  END lo_d[448]
  PIN lo_d[449]
    DIRECTION INPUT ;
    USE SIGNAL ;
    PORT
      LAYER M4 ;
        RECT 431.808 137.088 432.000 137.112 ;
    END
  END lo_d[449]
  PIN lo_d[450]
    DIRECTION INPUT ;
    USE SIGNAL ;
    PORT
      LAYER M4 ;
        RECT 431.808 137.376 432.000 137.400 ;
    END
  END lo_d[450]
  PIN lo_d[451]
    DIRECTION INPUT ;
    USE SIGNAL ;
    PORT
      LAYER M4 ;
        RECT 431.808 137.664 432.000 137.688 ;
    END
  END lo_d[451]
  PIN lo_d[452]
    DIRECTION INPUT ;
    USE SIGNAL ;
    PORT
      LAYER M4 ;
        RECT 431.808 138.000 432.000 138.024 ;
    END
  END lo_d[452]
  PIN lo_d[453]
    DIRECTION INPUT ;
    USE SIGNAL ;
    PORT
      LAYER M4 ;
        RECT 431.808 138.288 432.000 138.312 ;
    END
  END lo_d[453]
  PIN lo_d[454]
    DIRECTION INPUT ;
    USE SIGNAL ;
    PORT
      LAYER M4 ;
        RECT 431.808 138.576 432.000 138.600 ;
    END
  END lo_d[454]
  PIN lo_d[455]
    DIRECTION INPUT ;
    USE SIGNAL ;
    PORT
      LAYER M4 ;
        RECT 431.808 138.864 432.000 138.888 ;
    END
  END lo_d[455]
  PIN lo_d[456]
    DIRECTION INPUT ;
    USE SIGNAL ;
    PORT
      LAYER M4 ;
        RECT 431.808 139.200 432.000 139.224 ;
    END
  END lo_d[456]
  PIN lo_d[457]
    DIRECTION INPUT ;
    USE SIGNAL ;
    PORT
      LAYER M4 ;
        RECT 431.808 139.488 432.000 139.512 ;
    END
  END lo_d[457]
  PIN lo_d[458]
    DIRECTION INPUT ;
    USE SIGNAL ;
    PORT
      LAYER M4 ;
        RECT 431.808 139.776 432.000 139.800 ;
    END
  END lo_d[458]
  PIN lo_d[459]
    DIRECTION INPUT ;
    USE SIGNAL ;
    PORT
      LAYER M4 ;
        RECT 431.808 140.064 432.000 140.088 ;
    END
  END lo_d[459]
  PIN lo_d[460]
    DIRECTION INPUT ;
    USE SIGNAL ;
    PORT
      LAYER M4 ;
        RECT 431.808 140.352 432.000 140.376 ;
    END
  END lo_d[460]
  PIN lo_d[461]
    DIRECTION INPUT ;
    USE SIGNAL ;
    PORT
      LAYER M4 ;
        RECT 431.808 140.688 432.000 140.712 ;
    END
  END lo_d[461]
  PIN lo_d[462]
    DIRECTION INPUT ;
    USE SIGNAL ;
    PORT
      LAYER M4 ;
        RECT 431.808 140.976 432.000 141.000 ;
    END
  END lo_d[462]
  PIN lo_d[463]
    DIRECTION INPUT ;
    USE SIGNAL ;
    PORT
      LAYER M4 ;
        RECT 431.808 141.264 432.000 141.288 ;
    END
  END lo_d[463]
  PIN lo_d[464]
    DIRECTION INPUT ;
    USE SIGNAL ;
    PORT
      LAYER M4 ;
        RECT 431.808 141.552 432.000 141.576 ;
    END
  END lo_d[464]
  PIN lo_d[465]
    DIRECTION INPUT ;
    USE SIGNAL ;
    PORT
      LAYER M4 ;
        RECT 431.808 141.888 432.000 141.912 ;
    END
  END lo_d[465]
  PIN lo_d[466]
    DIRECTION INPUT ;
    USE SIGNAL ;
    PORT
      LAYER M4 ;
        RECT 431.808 142.176 432.000 142.200 ;
    END
  END lo_d[466]
  PIN lo_d[467]
    DIRECTION INPUT ;
    USE SIGNAL ;
    PORT
      LAYER M4 ;
        RECT 431.808 142.464 432.000 142.488 ;
    END
  END lo_d[467]
  PIN lo_d[468]
    DIRECTION INPUT ;
    USE SIGNAL ;
    PORT
      LAYER M4 ;
        RECT 431.808 142.752 432.000 142.776 ;
    END
  END lo_d[468]
  PIN lo_d[469]
    DIRECTION INPUT ;
    USE SIGNAL ;
    PORT
      LAYER M4 ;
        RECT 431.808 143.088 432.000 143.112 ;
    END
  END lo_d[469]
  PIN lo_d[470]
    DIRECTION INPUT ;
    USE SIGNAL ;
    PORT
      LAYER M4 ;
        RECT 431.808 143.376 432.000 143.400 ;
    END
  END lo_d[470]
  PIN lo_d[471]
    DIRECTION INPUT ;
    USE SIGNAL ;
    PORT
      LAYER M4 ;
        RECT 431.808 143.664 432.000 143.688 ;
    END
  END lo_d[471]
  PIN lo_d[472]
    DIRECTION INPUT ;
    USE SIGNAL ;
    PORT
      LAYER M4 ;
        RECT 431.808 143.952 432.000 143.976 ;
    END
  END lo_d[472]
  PIN lo_d[473]
    DIRECTION INPUT ;
    USE SIGNAL ;
    PORT
      LAYER M4 ;
        RECT 431.808 144.240 432.000 144.264 ;
    END
  END lo_d[473]
  PIN lo_d[474]
    DIRECTION INPUT ;
    USE SIGNAL ;
    PORT
      LAYER M4 ;
        RECT 431.808 144.576 432.000 144.600 ;
    END
  END lo_d[474]
  PIN lo_d[475]
    DIRECTION INPUT ;
    USE SIGNAL ;
    PORT
      LAYER M4 ;
        RECT 431.808 144.864 432.000 144.888 ;
    END
  END lo_d[475]
  PIN lo_d[476]
    DIRECTION INPUT ;
    USE SIGNAL ;
    PORT
      LAYER M4 ;
        RECT 431.808 145.152 432.000 145.176 ;
    END
  END lo_d[476]
  PIN lo_d[477]
    DIRECTION INPUT ;
    USE SIGNAL ;
    PORT
      LAYER M4 ;
        RECT 431.808 145.440 432.000 145.464 ;
    END
  END lo_d[477]
  PIN lo_d[478]
    DIRECTION INPUT ;
    USE SIGNAL ;
    PORT
      LAYER M4 ;
        RECT 431.808 145.776 432.000 145.800 ;
    END
  END lo_d[478]
  PIN lo_d[479]
    DIRECTION INPUT ;
    USE SIGNAL ;
    PORT
      LAYER M4 ;
        RECT 431.808 146.064 432.000 146.088 ;
    END
  END lo_d[479]
  PIN lo_d[480]
    DIRECTION INPUT ;
    USE SIGNAL ;
    PORT
      LAYER M4 ;
        RECT 431.808 146.352 432.000 146.376 ;
    END
  END lo_d[480]
  PIN lo_d[481]
    DIRECTION INPUT ;
    USE SIGNAL ;
    PORT
      LAYER M4 ;
        RECT 431.808 146.640 432.000 146.664 ;
    END
  END lo_d[481]
  PIN lo_d[482]
    DIRECTION INPUT ;
    USE SIGNAL ;
    PORT
      LAYER M4 ;
        RECT 431.808 146.928 432.000 146.952 ;
    END
  END lo_d[482]
  PIN lo_d[483]
    DIRECTION INPUT ;
    USE SIGNAL ;
    PORT
      LAYER M4 ;
        RECT 431.808 147.264 432.000 147.288 ;
    END
  END lo_d[483]
  PIN lo_d[484]
    DIRECTION INPUT ;
    USE SIGNAL ;
    PORT
      LAYER M4 ;
        RECT 431.808 147.552 432.000 147.576 ;
    END
  END lo_d[484]
  PIN lo_d[485]
    DIRECTION INPUT ;
    USE SIGNAL ;
    PORT
      LAYER M4 ;
        RECT 431.808 147.840 432.000 147.864 ;
    END
  END lo_d[485]
  PIN lo_d[486]
    DIRECTION INPUT ;
    USE SIGNAL ;
    PORT
      LAYER M4 ;
        RECT 431.808 148.128 432.000 148.152 ;
    END
  END lo_d[486]
  PIN lo_d[487]
    DIRECTION INPUT ;
    USE SIGNAL ;
    PORT
      LAYER M4 ;
        RECT 431.808 148.464 432.000 148.488 ;
    END
  END lo_d[487]
  PIN lo_d[488]
    DIRECTION INPUT ;
    USE SIGNAL ;
    PORT
      LAYER M4 ;
        RECT 431.808 148.752 432.000 148.776 ;
    END
  END lo_d[488]
  PIN lo_d[489]
    DIRECTION INPUT ;
    USE SIGNAL ;
    PORT
      LAYER M4 ;
        RECT 431.808 149.040 432.000 149.064 ;
    END
  END lo_d[489]
  PIN lo_d[490]
    DIRECTION INPUT ;
    USE SIGNAL ;
    PORT
      LAYER M4 ;
        RECT 431.808 149.328 432.000 149.352 ;
    END
  END lo_d[490]
  PIN lo_d[491]
    DIRECTION INPUT ;
    USE SIGNAL ;
    PORT
      LAYER M4 ;
        RECT 431.808 149.616 432.000 149.640 ;
    END
  END lo_d[491]
  PIN lo_d[492]
    DIRECTION INPUT ;
    USE SIGNAL ;
    PORT
      LAYER M4 ;
        RECT 431.808 149.952 432.000 149.976 ;
    END
  END lo_d[492]
  PIN lo_d[493]
    DIRECTION INPUT ;
    USE SIGNAL ;
    PORT
      LAYER M4 ;
        RECT 431.808 150.240 432.000 150.264 ;
    END
  END lo_d[493]
  PIN lo_d[494]
    DIRECTION INPUT ;
    USE SIGNAL ;
    PORT
      LAYER M4 ;
        RECT 431.808 150.528 432.000 150.552 ;
    END
  END lo_d[494]
  PIN lo_d[495]
    DIRECTION INPUT ;
    USE SIGNAL ;
    PORT
      LAYER M4 ;
        RECT 431.808 150.816 432.000 150.840 ;
    END
  END lo_d[495]
  PIN lo_d[496]
    DIRECTION INPUT ;
    USE SIGNAL ;
    PORT
      LAYER M4 ;
        RECT 431.808 151.152 432.000 151.176 ;
    END
  END lo_d[496]
  PIN lo_d[497]
    DIRECTION INPUT ;
    USE SIGNAL ;
    PORT
      LAYER M4 ;
        RECT 431.808 151.440 432.000 151.464 ;
    END
  END lo_d[497]
  PIN lo_d[498]
    DIRECTION INPUT ;
    USE SIGNAL ;
    PORT
      LAYER M4 ;
        RECT 431.808 151.728 432.000 151.752 ;
    END
  END lo_d[498]
  PIN lo_d[499]
    DIRECTION INPUT ;
    USE SIGNAL ;
    PORT
      LAYER M4 ;
        RECT 431.808 152.016 432.000 152.040 ;
    END
  END lo_d[499]
  PIN lo_d[500]
    DIRECTION INPUT ;
    USE SIGNAL ;
    PORT
      LAYER M4 ;
        RECT 431.808 152.352 432.000 152.376 ;
    END
  END lo_d[500]
  PIN lo_d[501]
    DIRECTION INPUT ;
    USE SIGNAL ;
    PORT
      LAYER M4 ;
        RECT 431.808 152.640 432.000 152.664 ;
    END
  END lo_d[501]
  PIN lo_d[502]
    DIRECTION INPUT ;
    USE SIGNAL ;
    PORT
      LAYER M4 ;
        RECT 431.808 152.928 432.000 152.952 ;
    END
  END lo_d[502]
  PIN lo_d[503]
    DIRECTION INPUT ;
    USE SIGNAL ;
    PORT
      LAYER M4 ;
        RECT 431.808 153.216 432.000 153.240 ;
    END
  END lo_d[503]
  PIN lo_d[504]
    DIRECTION INPUT ;
    USE SIGNAL ;
    PORT
      LAYER M4 ;
        RECT 431.808 153.504 432.000 153.528 ;
    END
  END lo_d[504]
  PIN lo_d[505]
    DIRECTION INPUT ;
    USE SIGNAL ;
    PORT
      LAYER M4 ;
        RECT 431.808 153.840 432.000 153.864 ;
    END
  END lo_d[505]
  PIN lo_d[506]
    DIRECTION INPUT ;
    USE SIGNAL ;
    PORT
      LAYER M4 ;
        RECT 431.808 154.128 432.000 154.152 ;
    END
  END lo_d[506]
  PIN lo_d[507]
    DIRECTION INPUT ;
    USE SIGNAL ;
    PORT
      LAYER M4 ;
        RECT 431.808 154.416 432.000 154.440 ;
    END
  END lo_d[507]
  PIN lo_d[508]
    DIRECTION INPUT ;
    USE SIGNAL ;
    PORT
      LAYER M4 ;
        RECT 431.808 154.704 432.000 154.728 ;
    END
  END lo_d[508]
  PIN lo_d[509]
    DIRECTION INPUT ;
    USE SIGNAL ;
    PORT
      LAYER M4 ;
        RECT 431.808 155.040 432.000 155.064 ;
    END
  END lo_d[509]
  PIN lo_d[510]
    DIRECTION INPUT ;
    USE SIGNAL ;
    PORT
      LAYER M4 ;
        RECT 431.808 155.328 432.000 155.352 ;
    END
  END lo_d[510]
  PIN lo_d[511]
    DIRECTION INPUT ;
    USE SIGNAL ;
    PORT
      LAYER M4 ;
        RECT 431.808 155.616 432.000 155.640 ;
    END
  END lo_d[511]
  PIN lo_d[512]
    DIRECTION INPUT ;
    USE SIGNAL ;
    PORT
      LAYER M4 ;
        RECT 431.808 155.904 432.000 155.928 ;
    END
  END lo_d[512]
  PIN lo_d[513]
    DIRECTION INPUT ;
    USE SIGNAL ;
    PORT
      LAYER M4 ;
        RECT 431.808 156.192 432.000 156.216 ;
    END
  END lo_d[513]
  PIN lo_d[514]
    DIRECTION INPUT ;
    USE SIGNAL ;
    PORT
      LAYER M4 ;
        RECT 431.808 156.528 432.000 156.552 ;
    END
  END lo_d[514]
  PIN lo_d[515]
    DIRECTION INPUT ;
    USE SIGNAL ;
    PORT
      LAYER M4 ;
        RECT 431.808 156.816 432.000 156.840 ;
    END
  END lo_d[515]
  PIN lo_d[516]
    DIRECTION INPUT ;
    USE SIGNAL ;
    PORT
      LAYER M4 ;
        RECT 431.808 157.104 432.000 157.128 ;
    END
  END lo_d[516]
  PIN lo_d[517]
    DIRECTION INPUT ;
    USE SIGNAL ;
    PORT
      LAYER M4 ;
        RECT 431.808 157.392 432.000 157.416 ;
    END
  END lo_d[517]
  PIN lo_d[518]
    DIRECTION INPUT ;
    USE SIGNAL ;
    PORT
      LAYER M4 ;
        RECT 431.808 157.728 432.000 157.752 ;
    END
  END lo_d[518]
  PIN lo_d[519]
    DIRECTION INPUT ;
    USE SIGNAL ;
    PORT
      LAYER M4 ;
        RECT 431.808 158.016 432.000 158.040 ;
    END
  END lo_d[519]
  PIN lo_d[520]
    DIRECTION INPUT ;
    USE SIGNAL ;
    PORT
      LAYER M4 ;
        RECT 431.808 158.304 432.000 158.328 ;
    END
  END lo_d[520]
  PIN lo_d[521]
    DIRECTION INPUT ;
    USE SIGNAL ;
    PORT
      LAYER M4 ;
        RECT 431.808 158.592 432.000 158.616 ;
    END
  END lo_d[521]
  PIN lo_d[522]
    DIRECTION INPUT ;
    USE SIGNAL ;
    PORT
      LAYER M4 ;
        RECT 431.808 158.928 432.000 158.952 ;
    END
  END lo_d[522]
  PIN lo_d[523]
    DIRECTION INPUT ;
    USE SIGNAL ;
    PORT
      LAYER M4 ;
        RECT 431.808 159.216 432.000 159.240 ;
    END
  END lo_d[523]
  PIN lo_d[524]
    DIRECTION INPUT ;
    USE SIGNAL ;
    PORT
      LAYER M4 ;
        RECT 431.808 159.504 432.000 159.528 ;
    END
  END lo_d[524]
  PIN lo_d[525]
    DIRECTION INPUT ;
    USE SIGNAL ;
    PORT
      LAYER M4 ;
        RECT 431.808 159.792 432.000 159.816 ;
    END
  END lo_d[525]
  PIN lo_d[526]
    DIRECTION INPUT ;
    USE SIGNAL ;
    PORT
      LAYER M4 ;
        RECT 431.808 160.080 432.000 160.104 ;
    END
  END lo_d[526]
  PIN lo_d[527]
    DIRECTION INPUT ;
    USE SIGNAL ;
    PORT
      LAYER M4 ;
        RECT 431.808 160.416 432.000 160.440 ;
    END
  END lo_d[527]
  PIN lo_d[528]
    DIRECTION INPUT ;
    USE SIGNAL ;
    PORT
      LAYER M4 ;
        RECT 431.808 160.704 432.000 160.728 ;
    END
  END lo_d[528]
  PIN lo_d[529]
    DIRECTION INPUT ;
    USE SIGNAL ;
    PORT
      LAYER M4 ;
        RECT 431.808 160.992 432.000 161.016 ;
    END
  END lo_d[529]
  PIN lo_d[530]
    DIRECTION INPUT ;
    USE SIGNAL ;
    PORT
      LAYER M4 ;
        RECT 431.808 161.280 432.000 161.304 ;
    END
  END lo_d[530]
  PIN lo_d[531]
    DIRECTION INPUT ;
    USE SIGNAL ;
    PORT
      LAYER M4 ;
        RECT 431.808 161.616 432.000 161.640 ;
    END
  END lo_d[531]
  PIN lo_d[532]
    DIRECTION INPUT ;
    USE SIGNAL ;
    PORT
      LAYER M4 ;
        RECT 431.808 161.904 432.000 161.928 ;
    END
  END lo_d[532]
  PIN lo_d[533]
    DIRECTION INPUT ;
    USE SIGNAL ;
    PORT
      LAYER M4 ;
        RECT 431.808 162.192 432.000 162.216 ;
    END
  END lo_d[533]
  PIN lo_d[534]
    DIRECTION INPUT ;
    USE SIGNAL ;
    PORT
      LAYER M4 ;
        RECT 431.808 162.480 432.000 162.504 ;
    END
  END lo_d[534]
  PIN lo_d[535]
    DIRECTION INPUT ;
    USE SIGNAL ;
    PORT
      LAYER M4 ;
        RECT 431.808 162.768 432.000 162.792 ;
    END
  END lo_d[535]
  PIN lo_d[536]
    DIRECTION INPUT ;
    USE SIGNAL ;
    PORT
      LAYER M4 ;
        RECT 431.808 163.104 432.000 163.128 ;
    END
  END lo_d[536]
  PIN lo_d[537]
    DIRECTION INPUT ;
    USE SIGNAL ;
    PORT
      LAYER M4 ;
        RECT 431.808 163.392 432.000 163.416 ;
    END
  END lo_d[537]
  PIN lo_d[538]
    DIRECTION INPUT ;
    USE SIGNAL ;
    PORT
      LAYER M4 ;
        RECT 431.808 163.680 432.000 163.704 ;
    END
  END lo_d[538]
  PIN lo_d[539]
    DIRECTION INPUT ;
    USE SIGNAL ;
    PORT
      LAYER M4 ;
        RECT 431.808 163.968 432.000 163.992 ;
    END
  END lo_d[539]
  PIN lo_d[540]
    DIRECTION INPUT ;
    USE SIGNAL ;
    PORT
      LAYER M4 ;
        RECT 431.808 164.304 432.000 164.328 ;
    END
  END lo_d[540]
  PIN lo_d[541]
    DIRECTION INPUT ;
    USE SIGNAL ;
    PORT
      LAYER M4 ;
        RECT 431.808 164.592 432.000 164.616 ;
    END
  END lo_d[541]
  PIN lo_d[542]
    DIRECTION INPUT ;
    USE SIGNAL ;
    PORT
      LAYER M4 ;
        RECT 431.808 164.880 432.000 164.904 ;
    END
  END lo_d[542]
  PIN lo_d[543]
    DIRECTION INPUT ;
    USE SIGNAL ;
    PORT
      LAYER M4 ;
        RECT 431.808 165.168 432.000 165.192 ;
    END
  END lo_d[543]
  PIN lo_d[544]
    DIRECTION INPUT ;
    USE SIGNAL ;
    PORT
      LAYER M4 ;
        RECT 431.808 165.456 432.000 165.480 ;
    END
  END lo_d[544]
  PIN lo_d[545]
    DIRECTION INPUT ;
    USE SIGNAL ;
    PORT
      LAYER M4 ;
        RECT 431.808 165.792 432.000 165.816 ;
    END
  END lo_d[545]
  PIN lo_d[546]
    DIRECTION INPUT ;
    USE SIGNAL ;
    PORT
      LAYER M4 ;
        RECT 431.808 166.080 432.000 166.104 ;
    END
  END lo_d[546]
  PIN lo_d[547]
    DIRECTION INPUT ;
    USE SIGNAL ;
    PORT
      LAYER M4 ;
        RECT 431.808 166.368 432.000 166.392 ;
    END
  END lo_d[547]
  PIN lo_d[548]
    DIRECTION INPUT ;
    USE SIGNAL ;
    PORT
      LAYER M4 ;
        RECT 431.808 166.656 432.000 166.680 ;
    END
  END lo_d[548]
  PIN lo_d[549]
    DIRECTION INPUT ;
    USE SIGNAL ;
    PORT
      LAYER M4 ;
        RECT 431.808 166.992 432.000 167.016 ;
    END
  END lo_d[549]
  PIN lo_d[550]
    DIRECTION INPUT ;
    USE SIGNAL ;
    PORT
      LAYER M4 ;
        RECT 431.808 167.280 432.000 167.304 ;
    END
  END lo_d[550]
  PIN lo_d[551]
    DIRECTION INPUT ;
    USE SIGNAL ;
    PORT
      LAYER M4 ;
        RECT 431.808 167.568 432.000 167.592 ;
    END
  END lo_d[551]
  PIN lo_d[552]
    DIRECTION INPUT ;
    USE SIGNAL ;
    PORT
      LAYER M4 ;
        RECT 431.808 167.856 432.000 167.880 ;
    END
  END lo_d[552]
  PIN li_v
    DIRECTION OUTPUT ;
    USE SIGNAL ;
    PORT
      LAYER M4 ;
        RECT 431.808 168.192 432.000 168.216 ;
    END
  END li_v
  PIN li_r
    DIRECTION INPUT ;
    USE SIGNAL ;
    PORT
      LAYER M4 ;
        RECT 431.808 168.480 432.000 168.504 ;
    END
  END li_r
  PIN li_d[0]
    DIRECTION OUTPUT ;
    USE SIGNAL ;
    PORT
      LAYER M4 ;
        RECT 431.808 168.768 432.000 168.792 ;
    END
  END li_d[0]
  PIN li_d[1]
    DIRECTION OUTPUT ;
    USE SIGNAL ;
    PORT
      LAYER M4 ;
        RECT 431.808 169.056 432.000 169.080 ;
    END
  END li_d[1]
  PIN li_d[2]
    DIRECTION OUTPUT ;
    USE SIGNAL ;
    PORT
      LAYER M4 ;
        RECT 431.808 169.344 432.000 169.368 ;
    END
  END li_d[2]
  PIN li_d[3]
    DIRECTION OUTPUT ;
    USE SIGNAL ;
    PORT
      LAYER M4 ;
        RECT 431.808 169.680 432.000 169.704 ;
    END
  END li_d[3]
  PIN li_d[4]
    DIRECTION OUTPUT ;
    USE SIGNAL ;
    PORT
      LAYER M4 ;
        RECT 431.808 169.968 432.000 169.992 ;
    END
  END li_d[4]
  PIN li_d[5]
    DIRECTION OUTPUT ;
    USE SIGNAL ;
    PORT
      LAYER M4 ;
        RECT 431.808 170.256 432.000 170.280 ;
    END
  END li_d[5]
  PIN li_d[6]
    DIRECTION OUTPUT ;
    USE SIGNAL ;
    PORT
      LAYER M4 ;
        RECT 431.808 170.544 432.000 170.568 ;
    END
  END li_d[6]
  PIN li_d[7]
    DIRECTION OUTPUT ;
    USE SIGNAL ;
    PORT
      LAYER M4 ;
        RECT 431.808 170.880 432.000 170.904 ;
    END
  END li_d[7]
  PIN li_d[8]
    DIRECTION OUTPUT ;
    USE SIGNAL ;
    PORT
      LAYER M4 ;
        RECT 431.808 171.168 432.000 171.192 ;
    END
  END li_d[8]
  PIN li_d[9]
    DIRECTION OUTPUT ;
    USE SIGNAL ;
    PORT
      LAYER M4 ;
        RECT 431.808 171.456 432.000 171.480 ;
    END
  END li_d[9]
  PIN li_d[10]
    DIRECTION OUTPUT ;
    USE SIGNAL ;
    PORT
      LAYER M4 ;
        RECT 431.808 171.744 432.000 171.768 ;
    END
  END li_d[10]
  PIN li_d[11]
    DIRECTION OUTPUT ;
    USE SIGNAL ;
    PORT
      LAYER M4 ;
        RECT 431.808 172.032 432.000 172.056 ;
    END
  END li_d[11]
  PIN li_d[12]
    DIRECTION OUTPUT ;
    USE SIGNAL ;
    PORT
      LAYER M4 ;
        RECT 431.808 172.368 432.000 172.392 ;
    END
  END li_d[12]
  PIN li_d[13]
    DIRECTION OUTPUT ;
    USE SIGNAL ;
    PORT
      LAYER M4 ;
        RECT 431.808 172.656 432.000 172.680 ;
    END
  END li_d[13]
  PIN li_d[14]
    DIRECTION OUTPUT ;
    USE SIGNAL ;
    PORT
      LAYER M4 ;
        RECT 431.808 172.944 432.000 172.968 ;
    END
  END li_d[14]
  PIN li_d[15]
    DIRECTION OUTPUT ;
    USE SIGNAL ;
    PORT
      LAYER M4 ;
        RECT 431.808 173.232 432.000 173.256 ;
    END
  END li_d[15]
  PIN li_d[16]
    DIRECTION OUTPUT ;
    USE SIGNAL ;
    PORT
      LAYER M4 ;
        RECT 431.808 173.568 432.000 173.592 ;
    END
  END li_d[16]
  PIN li_d[17]
    DIRECTION OUTPUT ;
    USE SIGNAL ;
    PORT
      LAYER M4 ;
        RECT 431.808 173.856 432.000 173.880 ;
    END
  END li_d[17]
  PIN li_d[18]
    DIRECTION OUTPUT ;
    USE SIGNAL ;
    PORT
      LAYER M4 ;
        RECT 431.808 174.144 432.000 174.168 ;
    END
  END li_d[18]
  PIN li_d[19]
    DIRECTION OUTPUT ;
    USE SIGNAL ;
    PORT
      LAYER M4 ;
        RECT 431.808 174.432 432.000 174.456 ;
    END
  END li_d[19]
  PIN li_d[20]
    DIRECTION OUTPUT ;
    USE SIGNAL ;
    PORT
      LAYER M4 ;
        RECT 431.808 174.768 432.000 174.792 ;
    END
  END li_d[20]
  PIN li_d[21]
    DIRECTION OUTPUT ;
    USE SIGNAL ;
    PORT
      LAYER M4 ;
        RECT 431.808 175.056 432.000 175.080 ;
    END
  END li_d[21]
  PIN li_d[22]
    DIRECTION OUTPUT ;
    USE SIGNAL ;
    PORT
      LAYER M4 ;
        RECT 431.808 175.344 432.000 175.368 ;
    END
  END li_d[22]
  PIN li_d[23]
    DIRECTION OUTPUT ;
    USE SIGNAL ;
    PORT
      LAYER M4 ;
        RECT 431.808 175.632 432.000 175.656 ;
    END
  END li_d[23]
  PIN li_d[24]
    DIRECTION OUTPUT ;
    USE SIGNAL ;
    PORT
      LAYER M4 ;
        RECT 431.808 175.920 432.000 175.944 ;
    END
  END li_d[24]
  PIN li_d[25]
    DIRECTION OUTPUT ;
    USE SIGNAL ;
    PORT
      LAYER M4 ;
        RECT 431.808 176.256 432.000 176.280 ;
    END
  END li_d[25]
  PIN li_d[26]
    DIRECTION OUTPUT ;
    USE SIGNAL ;
    PORT
      LAYER M4 ;
        RECT 431.808 176.544 432.000 176.568 ;
    END
  END li_d[26]
  PIN li_d[27]
    DIRECTION OUTPUT ;
    USE SIGNAL ;
    PORT
      LAYER M4 ;
        RECT 431.808 176.832 432.000 176.856 ;
    END
  END li_d[27]
  PIN li_d[28]
    DIRECTION OUTPUT ;
    USE SIGNAL ;
    PORT
      LAYER M4 ;
        RECT 431.808 177.120 432.000 177.144 ;
    END
  END li_d[28]
  PIN li_d[29]
    DIRECTION OUTPUT ;
    USE SIGNAL ;
    PORT
      LAYER M4 ;
        RECT 431.808 177.456 432.000 177.480 ;
    END
  END li_d[29]
  PIN li_d[30]
    DIRECTION OUTPUT ;
    USE SIGNAL ;
    PORT
      LAYER M4 ;
        RECT 431.808 177.744 432.000 177.768 ;
    END
  END li_d[30]
  PIN li_d[31]
    DIRECTION OUTPUT ;
    USE SIGNAL ;
    PORT
      LAYER M4 ;
        RECT 431.808 178.032 432.000 178.056 ;
    END
  END li_d[31]
  PIN li_d[32]
    DIRECTION OUTPUT ;
    USE SIGNAL ;
    PORT
      LAYER M4 ;
        RECT 431.808 178.320 432.000 178.344 ;
    END
  END li_d[32]
  PIN li_d[33]
    DIRECTION OUTPUT ;
    USE SIGNAL ;
    PORT
      LAYER M4 ;
        RECT 431.808 178.608 432.000 178.632 ;
    END
  END li_d[33]
  PIN li_d[34]
    DIRECTION OUTPUT ;
    USE SIGNAL ;
    PORT
      LAYER M4 ;
        RECT 431.808 178.944 432.000 178.968 ;
    END
  END li_d[34]
  PIN li_d[35]
    DIRECTION OUTPUT ;
    USE SIGNAL ;
    PORT
      LAYER M4 ;
        RECT 431.808 179.232 432.000 179.256 ;
    END
  END li_d[35]
  PIN li_d[36]
    DIRECTION OUTPUT ;
    USE SIGNAL ;
    PORT
      LAYER M4 ;
        RECT 431.808 179.520 432.000 179.544 ;
    END
  END li_d[36]
  PIN li_d[37]
    DIRECTION OUTPUT ;
    USE SIGNAL ;
    PORT
      LAYER M4 ;
        RECT 431.808 179.808 432.000 179.832 ;
    END
  END li_d[37]
  PIN li_d[38]
    DIRECTION OUTPUT ;
    USE SIGNAL ;
    PORT
      LAYER M4 ;
        RECT 431.808 180.144 432.000 180.168 ;
    END
  END li_d[38]
  PIN li_d[39]
    DIRECTION OUTPUT ;
    USE SIGNAL ;
    PORT
      LAYER M4 ;
        RECT 431.808 180.432 432.000 180.456 ;
    END
  END li_d[39]
  PIN li_d[40]
    DIRECTION OUTPUT ;
    USE SIGNAL ;
    PORT
      LAYER M4 ;
        RECT 431.808 180.720 432.000 180.744 ;
    END
  END li_d[40]
  PIN li_d[41]
    DIRECTION OUTPUT ;
    USE SIGNAL ;
    PORT
      LAYER M4 ;
        RECT 431.808 181.008 432.000 181.032 ;
    END
  END li_d[41]
  PIN li_d[42]
    DIRECTION OUTPUT ;
    USE SIGNAL ;
    PORT
      LAYER M4 ;
        RECT 431.808 181.296 432.000 181.320 ;
    END
  END li_d[42]
  PIN li_d[43]
    DIRECTION OUTPUT ;
    USE SIGNAL ;
    PORT
      LAYER M4 ;
        RECT 431.808 181.632 432.000 181.656 ;
    END
  END li_d[43]
  PIN li_d[44]
    DIRECTION OUTPUT ;
    USE SIGNAL ;
    PORT
      LAYER M4 ;
        RECT 431.808 181.920 432.000 181.944 ;
    END
  END li_d[44]
  PIN li_d[45]
    DIRECTION OUTPUT ;
    USE SIGNAL ;
    PORT
      LAYER M4 ;
        RECT 431.808 182.208 432.000 182.232 ;
    END
  END li_d[45]
  PIN li_d[46]
    DIRECTION OUTPUT ;
    USE SIGNAL ;
    PORT
      LAYER M4 ;
        RECT 431.808 182.496 432.000 182.520 ;
    END
  END li_d[46]
  PIN li_d[47]
    DIRECTION OUTPUT ;
    USE SIGNAL ;
    PORT
      LAYER M4 ;
        RECT 431.808 182.832 432.000 182.856 ;
    END
  END li_d[47]
  PIN li_d[48]
    DIRECTION OUTPUT ;
    USE SIGNAL ;
    PORT
      LAYER M4 ;
        RECT 431.808 183.120 432.000 183.144 ;
    END
  END li_d[48]
  PIN li_d[49]
    DIRECTION OUTPUT ;
    USE SIGNAL ;
    PORT
      LAYER M4 ;
        RECT 431.808 183.408 432.000 183.432 ;
    END
  END li_d[49]
  PIN li_d[50]
    DIRECTION OUTPUT ;
    USE SIGNAL ;
    PORT
      LAYER M4 ;
        RECT 431.808 183.696 432.000 183.720 ;
    END
  END li_d[50]
  PIN li_d[51]
    DIRECTION OUTPUT ;
    USE SIGNAL ;
    PORT
      LAYER M4 ;
        RECT 431.808 184.032 432.000 184.056 ;
    END
  END li_d[51]
  PIN li_d[52]
    DIRECTION OUTPUT ;
    USE SIGNAL ;
    PORT
      LAYER M4 ;
        RECT 431.808 184.320 432.000 184.344 ;
    END
  END li_d[52]
  PIN li_d[53]
    DIRECTION OUTPUT ;
    USE SIGNAL ;
    PORT
      LAYER M4 ;
        RECT 431.808 184.608 432.000 184.632 ;
    END
  END li_d[53]
  PIN li_d[54]
    DIRECTION OUTPUT ;
    USE SIGNAL ;
    PORT
      LAYER M4 ;
        RECT 431.808 184.896 432.000 184.920 ;
    END
  END li_d[54]
  PIN li_d[55]
    DIRECTION OUTPUT ;
    USE SIGNAL ;
    PORT
      LAYER M4 ;
        RECT 431.808 185.184 432.000 185.208 ;
    END
  END li_d[55]
  PIN li_d[56]
    DIRECTION OUTPUT ;
    USE SIGNAL ;
    PORT
      LAYER M4 ;
        RECT 431.808 185.520 432.000 185.544 ;
    END
  END li_d[56]
  PIN li_d[57]
    DIRECTION OUTPUT ;
    USE SIGNAL ;
    PORT
      LAYER M4 ;
        RECT 431.808 185.808 432.000 185.832 ;
    END
  END li_d[57]
  PIN li_d[58]
    DIRECTION OUTPUT ;
    USE SIGNAL ;
    PORT
      LAYER M4 ;
        RECT 431.808 186.096 432.000 186.120 ;
    END
  END li_d[58]
  PIN li_d[59]
    DIRECTION OUTPUT ;
    USE SIGNAL ;
    PORT
      LAYER M4 ;
        RECT 431.808 186.384 432.000 186.408 ;
    END
  END li_d[59]
  PIN li_d[60]
    DIRECTION OUTPUT ;
    USE SIGNAL ;
    PORT
      LAYER M4 ;
        RECT 431.808 186.720 432.000 186.744 ;
    END
  END li_d[60]
  PIN li_d[61]
    DIRECTION OUTPUT ;
    USE SIGNAL ;
    PORT
      LAYER M4 ;
        RECT 431.808 187.008 432.000 187.032 ;
    END
  END li_d[61]
  PIN li_d[62]
    DIRECTION OUTPUT ;
    USE SIGNAL ;
    PORT
      LAYER M4 ;
        RECT 431.808 187.296 432.000 187.320 ;
    END
  END li_d[62]
  PIN li_d[63]
    DIRECTION OUTPUT ;
    USE SIGNAL ;
    PORT
      LAYER M4 ;
        RECT 431.808 187.584 432.000 187.608 ;
    END
  END li_d[63]
  PIN li_d[64]
    DIRECTION OUTPUT ;
    USE SIGNAL ;
    PORT
      LAYER M4 ;
        RECT 431.808 187.872 432.000 187.896 ;
    END
  END li_d[64]
  PIN li_d[65]
    DIRECTION OUTPUT ;
    USE SIGNAL ;
    PORT
      LAYER M4 ;
        RECT 431.808 188.208 432.000 188.232 ;
    END
  END li_d[65]
  PIN li_d[66]
    DIRECTION OUTPUT ;
    USE SIGNAL ;
    PORT
      LAYER M4 ;
        RECT 431.808 188.496 432.000 188.520 ;
    END
  END li_d[66]
  PIN li_d[67]
    DIRECTION OUTPUT ;
    USE SIGNAL ;
    PORT
      LAYER M4 ;
        RECT 431.808 188.784 432.000 188.808 ;
    END
  END li_d[67]
  PIN li_d[68]
    DIRECTION OUTPUT ;
    USE SIGNAL ;
    PORT
      LAYER M4 ;
        RECT 431.808 189.072 432.000 189.096 ;
    END
  END li_d[68]
  PIN li_d[69]
    DIRECTION OUTPUT ;
    USE SIGNAL ;
    PORT
      LAYER M4 ;
        RECT 431.808 189.408 432.000 189.432 ;
    END
  END li_d[69]
  PIN li_d[70]
    DIRECTION OUTPUT ;
    USE SIGNAL ;
    PORT
      LAYER M4 ;
        RECT 431.808 189.696 432.000 189.720 ;
    END
  END li_d[70]
  PIN li_d[71]
    DIRECTION OUTPUT ;
    USE SIGNAL ;
    PORT
      LAYER M4 ;
        RECT 431.808 189.984 432.000 190.008 ;
    END
  END li_d[71]
  PIN li_d[72]
    DIRECTION OUTPUT ;
    USE SIGNAL ;
    PORT
      LAYER M4 ;
        RECT 431.808 190.272 432.000 190.296 ;
    END
  END li_d[72]
  PIN li_d[73]
    DIRECTION OUTPUT ;
    USE SIGNAL ;
    PORT
      LAYER M4 ;
        RECT 431.808 190.608 432.000 190.632 ;
    END
  END li_d[73]
  PIN li_d[74]
    DIRECTION OUTPUT ;
    USE SIGNAL ;
    PORT
      LAYER M4 ;
        RECT 431.808 190.896 432.000 190.920 ;
    END
  END li_d[74]
  PIN li_d[75]
    DIRECTION OUTPUT ;
    USE SIGNAL ;
    PORT
      LAYER M4 ;
        RECT 431.808 191.184 432.000 191.208 ;
    END
  END li_d[75]
  PIN li_d[76]
    DIRECTION OUTPUT ;
    USE SIGNAL ;
    PORT
      LAYER M4 ;
        RECT 431.808 191.472 432.000 191.496 ;
    END
  END li_d[76]
  PIN li_d[77]
    DIRECTION OUTPUT ;
    USE SIGNAL ;
    PORT
      LAYER M4 ;
        RECT 431.808 191.760 432.000 191.784 ;
    END
  END li_d[77]
  PIN li_d[78]
    DIRECTION OUTPUT ;
    USE SIGNAL ;
    PORT
      LAYER M4 ;
        RECT 431.808 192.096 432.000 192.120 ;
    END
  END li_d[78]
  PIN li_d[79]
    DIRECTION OUTPUT ;
    USE SIGNAL ;
    PORT
      LAYER M4 ;
        RECT 431.808 192.384 432.000 192.408 ;
    END
  END li_d[79]
  PIN li_d[80]
    DIRECTION OUTPUT ;
    USE SIGNAL ;
    PORT
      LAYER M4 ;
        RECT 431.808 192.672 432.000 192.696 ;
    END
  END li_d[80]
  PIN li_d[81]
    DIRECTION OUTPUT ;
    USE SIGNAL ;
    PORT
      LAYER M4 ;
        RECT 431.808 192.960 432.000 192.984 ;
    END
  END li_d[81]
  PIN li_d[82]
    DIRECTION OUTPUT ;
    USE SIGNAL ;
    PORT
      LAYER M4 ;
        RECT 431.808 193.296 432.000 193.320 ;
    END
  END li_d[82]
  PIN li_d[83]
    DIRECTION OUTPUT ;
    USE SIGNAL ;
    PORT
      LAYER M4 ;
        RECT 431.808 193.584 432.000 193.608 ;
    END
  END li_d[83]
  PIN li_d[84]
    DIRECTION OUTPUT ;
    USE SIGNAL ;
    PORT
      LAYER M4 ;
        RECT 431.808 193.872 432.000 193.896 ;
    END
  END li_d[84]
  PIN li_d[85]
    DIRECTION OUTPUT ;
    USE SIGNAL ;
    PORT
      LAYER M4 ;
        RECT 431.808 194.160 432.000 194.184 ;
    END
  END li_d[85]
  PIN li_d[86]
    DIRECTION OUTPUT ;
    USE SIGNAL ;
    PORT
      LAYER M4 ;
        RECT 431.808 194.448 432.000 194.472 ;
    END
  END li_d[86]
  PIN li_d[87]
    DIRECTION OUTPUT ;
    USE SIGNAL ;
    PORT
      LAYER M4 ;
        RECT 431.808 194.784 432.000 194.808 ;
    END
  END li_d[87]
  PIN li_d[88]
    DIRECTION OUTPUT ;
    USE SIGNAL ;
    PORT
      LAYER M4 ;
        RECT 431.808 195.072 432.000 195.096 ;
    END
  END li_d[88]
  PIN li_d[89]
    DIRECTION OUTPUT ;
    USE SIGNAL ;
    PORT
      LAYER M4 ;
        RECT 431.808 195.360 432.000 195.384 ;
    END
  END li_d[89]
  PIN li_d[90]
    DIRECTION OUTPUT ;
    USE SIGNAL ;
    PORT
      LAYER M4 ;
        RECT 431.808 195.648 432.000 195.672 ;
    END
  END li_d[90]
  PIN li_d[91]
    DIRECTION OUTPUT ;
    USE SIGNAL ;
    PORT
      LAYER M4 ;
        RECT 431.808 195.984 432.000 196.008 ;
    END
  END li_d[91]
  PIN li_d[92]
    DIRECTION OUTPUT ;
    USE SIGNAL ;
    PORT
      LAYER M4 ;
        RECT 431.808 196.272 432.000 196.296 ;
    END
  END li_d[92]
  PIN li_d[93]
    DIRECTION OUTPUT ;
    USE SIGNAL ;
    PORT
      LAYER M4 ;
        RECT 431.808 196.560 432.000 196.584 ;
    END
  END li_d[93]
  PIN li_d[94]
    DIRECTION OUTPUT ;
    USE SIGNAL ;
    PORT
      LAYER M4 ;
        RECT 431.808 196.848 432.000 196.872 ;
    END
  END li_d[94]
  PIN li_d[95]
    DIRECTION OUTPUT ;
    USE SIGNAL ;
    PORT
      LAYER M4 ;
        RECT 431.808 197.136 432.000 197.160 ;
    END
  END li_d[95]
  PIN li_d[96]
    DIRECTION OUTPUT ;
    USE SIGNAL ;
    PORT
      LAYER M4 ;
        RECT 431.808 197.472 432.000 197.496 ;
    END
  END li_d[96]
  PIN li_d[97]
    DIRECTION OUTPUT ;
    USE SIGNAL ;
    PORT
      LAYER M4 ;
        RECT 431.808 197.760 432.000 197.784 ;
    END
  END li_d[97]
  PIN li_d[98]
    DIRECTION OUTPUT ;
    USE SIGNAL ;
    PORT
      LAYER M4 ;
        RECT 431.808 198.048 432.000 198.072 ;
    END
  END li_d[98]
  PIN li_d[99]
    DIRECTION OUTPUT ;
    USE SIGNAL ;
    PORT
      LAYER M4 ;
        RECT 431.808 198.336 432.000 198.360 ;
    END
  END li_d[99]
  PIN li_d[100]
    DIRECTION OUTPUT ;
    USE SIGNAL ;
    PORT
      LAYER M4 ;
        RECT 431.808 198.672 432.000 198.696 ;
    END
  END li_d[100]
  PIN li_d[101]
    DIRECTION OUTPUT ;
    USE SIGNAL ;
    PORT
      LAYER M4 ;
        RECT 431.808 198.960 432.000 198.984 ;
    END
  END li_d[101]
  PIN li_d[102]
    DIRECTION OUTPUT ;
    USE SIGNAL ;
    PORT
      LAYER M4 ;
        RECT 431.808 199.248 432.000 199.272 ;
    END
  END li_d[102]
  PIN li_d[103]
    DIRECTION OUTPUT ;
    USE SIGNAL ;
    PORT
      LAYER M4 ;
        RECT 431.808 199.536 432.000 199.560 ;
    END
  END li_d[103]
  PIN li_d[104]
    DIRECTION OUTPUT ;
    USE SIGNAL ;
    PORT
      LAYER M4 ;
        RECT 431.808 199.872 432.000 199.896 ;
    END
  END li_d[104]
  PIN li_d[105]
    DIRECTION OUTPUT ;
    USE SIGNAL ;
    PORT
      LAYER M4 ;
        RECT 431.808 200.160 432.000 200.184 ;
    END
  END li_d[105]
  PIN li_d[106]
    DIRECTION OUTPUT ;
    USE SIGNAL ;
    PORT
      LAYER M4 ;
        RECT 431.808 200.448 432.000 200.472 ;
    END
  END li_d[106]
  PIN li_d[107]
    DIRECTION OUTPUT ;
    USE SIGNAL ;
    PORT
      LAYER M4 ;
        RECT 431.808 200.736 432.000 200.760 ;
    END
  END li_d[107]
  PIN li_d[108]
    DIRECTION OUTPUT ;
    USE SIGNAL ;
    PORT
      LAYER M4 ;
        RECT 431.808 201.024 432.000 201.048 ;
    END
  END li_d[108]
  PIN li_d[109]
    DIRECTION OUTPUT ;
    USE SIGNAL ;
    PORT
      LAYER M4 ;
        RECT 431.808 201.360 432.000 201.384 ;
    END
  END li_d[109]
  PIN li_d[110]
    DIRECTION OUTPUT ;
    USE SIGNAL ;
    PORT
      LAYER M4 ;
        RECT 431.808 201.648 432.000 201.672 ;
    END
  END li_d[110]
  PIN li_d[111]
    DIRECTION OUTPUT ;
    USE SIGNAL ;
    PORT
      LAYER M4 ;
        RECT 431.808 201.936 432.000 201.960 ;
    END
  END li_d[111]
  PIN li_d[112]
    DIRECTION OUTPUT ;
    USE SIGNAL ;
    PORT
      LAYER M4 ;
        RECT 431.808 202.224 432.000 202.248 ;
    END
  END li_d[112]
  PIN li_d[113]
    DIRECTION OUTPUT ;
    USE SIGNAL ;
    PORT
      LAYER M4 ;
        RECT 431.808 202.560 432.000 202.584 ;
    END
  END li_d[113]
  PIN li_d[114]
    DIRECTION OUTPUT ;
    USE SIGNAL ;
    PORT
      LAYER M4 ;
        RECT 431.808 202.848 432.000 202.872 ;
    END
  END li_d[114]
  PIN li_d[115]
    DIRECTION OUTPUT ;
    USE SIGNAL ;
    PORT
      LAYER M4 ;
        RECT 431.808 203.136 432.000 203.160 ;
    END
  END li_d[115]
  PIN li_d[116]
    DIRECTION OUTPUT ;
    USE SIGNAL ;
    PORT
      LAYER M4 ;
        RECT 431.808 203.424 432.000 203.448 ;
    END
  END li_d[116]
  PIN li_d[117]
    DIRECTION OUTPUT ;
    USE SIGNAL ;
    PORT
      LAYER M4 ;
        RECT 431.808 203.712 432.000 203.736 ;
    END
  END li_d[117]
  PIN li_d[118]
    DIRECTION OUTPUT ;
    USE SIGNAL ;
    PORT
      LAYER M4 ;
        RECT 431.808 204.048 432.000 204.072 ;
    END
  END li_d[118]
  PIN li_d[119]
    DIRECTION OUTPUT ;
    USE SIGNAL ;
    PORT
      LAYER M4 ;
        RECT 431.808 204.336 432.000 204.360 ;
    END
  END li_d[119]
  PIN li_d[120]
    DIRECTION OUTPUT ;
    USE SIGNAL ;
    PORT
      LAYER M4 ;
        RECT 431.808 204.624 432.000 204.648 ;
    END
  END li_d[120]
  PIN li_d[121]
    DIRECTION OUTPUT ;
    USE SIGNAL ;
    PORT
      LAYER M4 ;
        RECT 431.808 204.912 432.000 204.936 ;
    END
  END li_d[121]
  PIN li_d[122]
    DIRECTION OUTPUT ;
    USE SIGNAL ;
    PORT
      LAYER M4 ;
        RECT 431.808 205.248 432.000 205.272 ;
    END
  END li_d[122]
  PIN li_d[123]
    DIRECTION OUTPUT ;
    USE SIGNAL ;
    PORT
      LAYER M4 ;
        RECT 431.808 205.536 432.000 205.560 ;
    END
  END li_d[123]
  PIN li_d[124]
    DIRECTION OUTPUT ;
    USE SIGNAL ;
    PORT
      LAYER M4 ;
        RECT 431.808 205.824 432.000 205.848 ;
    END
  END li_d[124]
  PIN li_d[125]
    DIRECTION OUTPUT ;
    USE SIGNAL ;
    PORT
      LAYER M4 ;
        RECT 431.808 206.112 432.000 206.136 ;
    END
  END li_d[125]
  PIN li_d[126]
    DIRECTION OUTPUT ;
    USE SIGNAL ;
    PORT
      LAYER M4 ;
        RECT 431.808 206.448 432.000 206.472 ;
    END
  END li_d[126]
  PIN li_d[127]
    DIRECTION OUTPUT ;
    USE SIGNAL ;
    PORT
      LAYER M4 ;
        RECT 431.808 206.736 432.000 206.760 ;
    END
  END li_d[127]
  PIN li_d[128]
    DIRECTION OUTPUT ;
    USE SIGNAL ;
    PORT
      LAYER M4 ;
        RECT 431.808 207.024 432.000 207.048 ;
    END
  END li_d[128]
  PIN li_d[129]
    DIRECTION OUTPUT ;
    USE SIGNAL ;
    PORT
      LAYER M4 ;
        RECT 431.808 207.312 432.000 207.336 ;
    END
  END li_d[129]
  PIN li_d[130]
    DIRECTION OUTPUT ;
    USE SIGNAL ;
    PORT
      LAYER M4 ;
        RECT 431.808 207.600 432.000 207.624 ;
    END
  END li_d[130]
  PIN li_d[131]
    DIRECTION OUTPUT ;
    USE SIGNAL ;
    PORT
      LAYER M4 ;
        RECT 431.808 207.936 432.000 207.960 ;
    END
  END li_d[131]
  PIN li_d[132]
    DIRECTION OUTPUT ;
    USE SIGNAL ;
    PORT
      LAYER M4 ;
        RECT 431.808 208.224 432.000 208.248 ;
    END
  END li_d[132]
  PIN li_d[133]
    DIRECTION OUTPUT ;
    USE SIGNAL ;
    PORT
      LAYER M4 ;
        RECT 431.808 208.512 432.000 208.536 ;
    END
  END li_d[133]
  PIN li_d[134]
    DIRECTION OUTPUT ;
    USE SIGNAL ;
    PORT
      LAYER M4 ;
        RECT 431.808 208.800 432.000 208.824 ;
    END
  END li_d[134]
  PIN li_d[135]
    DIRECTION OUTPUT ;
    USE SIGNAL ;
    PORT
      LAYER M4 ;
        RECT 431.808 209.136 432.000 209.160 ;
    END
  END li_d[135]
  PIN li_d[136]
    DIRECTION OUTPUT ;
    USE SIGNAL ;
    PORT
      LAYER M4 ;
        RECT 431.808 209.424 432.000 209.448 ;
    END
  END li_d[136]
  PIN li_d[137]
    DIRECTION OUTPUT ;
    USE SIGNAL ;
    PORT
      LAYER M4 ;
        RECT 431.808 209.712 432.000 209.736 ;
    END
  END li_d[137]
  PIN li_d[138]
    DIRECTION OUTPUT ;
    USE SIGNAL ;
    PORT
      LAYER M4 ;
        RECT 431.808 210.000 432.000 210.024 ;
    END
  END li_d[138]
  PIN li_d[139]
    DIRECTION OUTPUT ;
    USE SIGNAL ;
    PORT
      LAYER M4 ;
        RECT 431.808 210.288 432.000 210.312 ;
    END
  END li_d[139]
  PIN li_d[140]
    DIRECTION OUTPUT ;
    USE SIGNAL ;
    PORT
      LAYER M4 ;
        RECT 431.808 210.624 432.000 210.648 ;
    END
  END li_d[140]
  PIN li_d[141]
    DIRECTION OUTPUT ;
    USE SIGNAL ;
    PORT
      LAYER M4 ;
        RECT 431.808 210.912 432.000 210.936 ;
    END
  END li_d[141]
  PIN li_d[142]
    DIRECTION OUTPUT ;
    USE SIGNAL ;
    PORT
      LAYER M4 ;
        RECT 431.808 211.200 432.000 211.224 ;
    END
  END li_d[142]
  PIN li_d[143]
    DIRECTION OUTPUT ;
    USE SIGNAL ;
    PORT
      LAYER M4 ;
        RECT 431.808 211.488 432.000 211.512 ;
    END
  END li_d[143]
  PIN li_d[144]
    DIRECTION OUTPUT ;
    USE SIGNAL ;
    PORT
      LAYER M4 ;
        RECT 431.808 211.824 432.000 211.848 ;
    END
  END li_d[144]
  PIN li_d[145]
    DIRECTION OUTPUT ;
    USE SIGNAL ;
    PORT
      LAYER M4 ;
        RECT 431.808 212.112 432.000 212.136 ;
    END
  END li_d[145]
  PIN li_d[146]
    DIRECTION OUTPUT ;
    USE SIGNAL ;
    PORT
      LAYER M4 ;
        RECT 431.808 212.400 432.000 212.424 ;
    END
  END li_d[146]
  PIN li_d[147]
    DIRECTION OUTPUT ;
    USE SIGNAL ;
    PORT
      LAYER M4 ;
        RECT 431.808 212.688 432.000 212.712 ;
    END
  END li_d[147]
  PIN li_d[148]
    DIRECTION OUTPUT ;
    USE SIGNAL ;
    PORT
      LAYER M4 ;
        RECT 431.808 212.976 432.000 213.000 ;
    END
  END li_d[148]
  PIN li_d[149]
    DIRECTION OUTPUT ;
    USE SIGNAL ;
    PORT
      LAYER M4 ;
        RECT 431.808 213.312 432.000 213.336 ;
    END
  END li_d[149]
  PIN li_d[150]
    DIRECTION OUTPUT ;
    USE SIGNAL ;
    PORT
      LAYER M4 ;
        RECT 431.808 213.600 432.000 213.624 ;
    END
  END li_d[150]
  PIN li_d[151]
    DIRECTION OUTPUT ;
    USE SIGNAL ;
    PORT
      LAYER M4 ;
        RECT 431.808 213.888 432.000 213.912 ;
    END
  END li_d[151]
  PIN li_d[152]
    DIRECTION OUTPUT ;
    USE SIGNAL ;
    PORT
      LAYER M4 ;
        RECT 431.808 214.176 432.000 214.200 ;
    END
  END li_d[152]
  PIN li_d[153]
    DIRECTION OUTPUT ;
    USE SIGNAL ;
    PORT
      LAYER M4 ;
        RECT 431.808 214.512 432.000 214.536 ;
    END
  END li_d[153]
  PIN li_d[154]
    DIRECTION OUTPUT ;
    USE SIGNAL ;
    PORT
      LAYER M4 ;
        RECT 431.808 214.800 432.000 214.824 ;
    END
  END li_d[154]
  PIN li_d[155]
    DIRECTION OUTPUT ;
    USE SIGNAL ;
    PORT
      LAYER M4 ;
        RECT 431.808 215.088 432.000 215.112 ;
    END
  END li_d[155]
  PIN li_d[156]
    DIRECTION OUTPUT ;
    USE SIGNAL ;
    PORT
      LAYER M4 ;
        RECT 431.808 215.376 432.000 215.400 ;
    END
  END li_d[156]
  PIN li_d[157]
    DIRECTION OUTPUT ;
    USE SIGNAL ;
    PORT
      LAYER M4 ;
        RECT 431.808 215.712 432.000 215.736 ;
    END
  END li_d[157]
  PIN li_d[158]
    DIRECTION OUTPUT ;
    USE SIGNAL ;
    PORT
      LAYER M4 ;
        RECT 431.808 216.000 432.000 216.024 ;
    END
  END li_d[158]
  PIN li_d[159]
    DIRECTION OUTPUT ;
    USE SIGNAL ;
    PORT
      LAYER M4 ;
        RECT 431.808 216.288 432.000 216.312 ;
    END
  END li_d[159]
  PIN li_d[160]
    DIRECTION OUTPUT ;
    USE SIGNAL ;
    PORT
      LAYER M4 ;
        RECT 431.808 216.576 432.000 216.600 ;
    END
  END li_d[160]
  PIN li_d[161]
    DIRECTION OUTPUT ;
    USE SIGNAL ;
    PORT
      LAYER M4 ;
        RECT 431.808 216.864 432.000 216.888 ;
    END
  END li_d[161]
  PIN li_d[162]
    DIRECTION OUTPUT ;
    USE SIGNAL ;
    PORT
      LAYER M4 ;
        RECT 431.808 217.200 432.000 217.224 ;
    END
  END li_d[162]
  PIN li_d[163]
    DIRECTION OUTPUT ;
    USE SIGNAL ;
    PORT
      LAYER M4 ;
        RECT 431.808 217.488 432.000 217.512 ;
    END
  END li_d[163]
  PIN li_d[164]
    DIRECTION OUTPUT ;
    USE SIGNAL ;
    PORT
      LAYER M4 ;
        RECT 431.808 217.776 432.000 217.800 ;
    END
  END li_d[164]
  PIN li_d[165]
    DIRECTION OUTPUT ;
    USE SIGNAL ;
    PORT
      LAYER M4 ;
        RECT 431.808 218.064 432.000 218.088 ;
    END
  END li_d[165]
  PIN li_d[166]
    DIRECTION OUTPUT ;
    USE SIGNAL ;
    PORT
      LAYER M4 ;
        RECT 431.808 218.400 432.000 218.424 ;
    END
  END li_d[166]
  PIN li_d[167]
    DIRECTION OUTPUT ;
    USE SIGNAL ;
    PORT
      LAYER M4 ;
        RECT 431.808 218.688 432.000 218.712 ;
    END
  END li_d[167]
  PIN li_d[168]
    DIRECTION OUTPUT ;
    USE SIGNAL ;
    PORT
      LAYER M4 ;
        RECT 431.808 218.976 432.000 219.000 ;
    END
  END li_d[168]
  PIN li_d[169]
    DIRECTION OUTPUT ;
    USE SIGNAL ;
    PORT
      LAYER M4 ;
        RECT 431.808 219.264 432.000 219.288 ;
    END
  END li_d[169]
  PIN li_d[170]
    DIRECTION OUTPUT ;
    USE SIGNAL ;
    PORT
      LAYER M4 ;
        RECT 431.808 219.552 432.000 219.576 ;
    END
  END li_d[170]
  PIN li_d[171]
    DIRECTION OUTPUT ;
    USE SIGNAL ;
    PORT
      LAYER M4 ;
        RECT 431.808 219.888 432.000 219.912 ;
    END
  END li_d[171]
  PIN li_d[172]
    DIRECTION OUTPUT ;
    USE SIGNAL ;
    PORT
      LAYER M4 ;
        RECT 431.808 220.176 432.000 220.200 ;
    END
  END li_d[172]
  PIN li_d[173]
    DIRECTION OUTPUT ;
    USE SIGNAL ;
    PORT
      LAYER M4 ;
        RECT 431.808 220.464 432.000 220.488 ;
    END
  END li_d[173]
  PIN li_d[174]
    DIRECTION OUTPUT ;
    USE SIGNAL ;
    PORT
      LAYER M4 ;
        RECT 431.808 220.752 432.000 220.776 ;
    END
  END li_d[174]
  PIN li_d[175]
    DIRECTION OUTPUT ;
    USE SIGNAL ;
    PORT
      LAYER M4 ;
        RECT 431.808 221.088 432.000 221.112 ;
    END
  END li_d[175]
  PIN li_d[176]
    DIRECTION OUTPUT ;
    USE SIGNAL ;
    PORT
      LAYER M4 ;
        RECT 431.808 221.376 432.000 221.400 ;
    END
  END li_d[176]
  PIN li_d[177]
    DIRECTION OUTPUT ;
    USE SIGNAL ;
    PORT
      LAYER M4 ;
        RECT 431.808 221.664 432.000 221.688 ;
    END
  END li_d[177]
  PIN li_d[178]
    DIRECTION OUTPUT ;
    USE SIGNAL ;
    PORT
      LAYER M4 ;
        RECT 431.808 221.952 432.000 221.976 ;
    END
  END li_d[178]
  PIN li_d[179]
    DIRECTION OUTPUT ;
    USE SIGNAL ;
    PORT
      LAYER M4 ;
        RECT 431.808 222.288 432.000 222.312 ;
    END
  END li_d[179]
  PIN li_d[180]
    DIRECTION OUTPUT ;
    USE SIGNAL ;
    PORT
      LAYER M4 ;
        RECT 431.808 222.576 432.000 222.600 ;
    END
  END li_d[180]
  PIN li_d[181]
    DIRECTION OUTPUT ;
    USE SIGNAL ;
    PORT
      LAYER M4 ;
        RECT 431.808 222.864 432.000 222.888 ;
    END
  END li_d[181]
  PIN li_d[182]
    DIRECTION OUTPUT ;
    USE SIGNAL ;
    PORT
      LAYER M4 ;
        RECT 431.808 223.152 432.000 223.176 ;
    END
  END li_d[182]
  PIN li_d[183]
    DIRECTION OUTPUT ;
    USE SIGNAL ;
    PORT
      LAYER M4 ;
        RECT 431.808 223.440 432.000 223.464 ;
    END
  END li_d[183]
  PIN li_d[184]
    DIRECTION OUTPUT ;
    USE SIGNAL ;
    PORT
      LAYER M4 ;
        RECT 431.808 223.776 432.000 223.800 ;
    END
  END li_d[184]
  PIN li_d[185]
    DIRECTION OUTPUT ;
    USE SIGNAL ;
    PORT
      LAYER M4 ;
        RECT 431.808 224.064 432.000 224.088 ;
    END
  END li_d[185]
  PIN li_d[186]
    DIRECTION OUTPUT ;
    USE SIGNAL ;
    PORT
      LAYER M4 ;
        RECT 431.808 224.352 432.000 224.376 ;
    END
  END li_d[186]
  PIN li_d[187]
    DIRECTION OUTPUT ;
    USE SIGNAL ;
    PORT
      LAYER M4 ;
        RECT 431.808 224.640 432.000 224.664 ;
    END
  END li_d[187]
  PIN li_d[188]
    DIRECTION OUTPUT ;
    USE SIGNAL ;
    PORT
      LAYER M4 ;
        RECT 431.808 224.976 432.000 225.000 ;
    END
  END li_d[188]
  PIN li_d[189]
    DIRECTION OUTPUT ;
    USE SIGNAL ;
    PORT
      LAYER M4 ;
        RECT 431.808 225.264 432.000 225.288 ;
    END
  END li_d[189]
  PIN li_d[190]
    DIRECTION OUTPUT ;
    USE SIGNAL ;
    PORT
      LAYER M4 ;
        RECT 431.808 225.552 432.000 225.576 ;
    END
  END li_d[190]
  PIN li_d[191]
    DIRECTION OUTPUT ;
    USE SIGNAL ;
    PORT
      LAYER M4 ;
        RECT 431.808 225.840 432.000 225.864 ;
    END
  END li_d[191]
  PIN li_d[192]
    DIRECTION OUTPUT ;
    USE SIGNAL ;
    PORT
      LAYER M4 ;
        RECT 431.808 226.128 432.000 226.152 ;
    END
  END li_d[192]
  PIN li_d[193]
    DIRECTION OUTPUT ;
    USE SIGNAL ;
    PORT
      LAYER M4 ;
        RECT 431.808 226.464 432.000 226.488 ;
    END
  END li_d[193]
  PIN li_d[194]
    DIRECTION OUTPUT ;
    USE SIGNAL ;
    PORT
      LAYER M4 ;
        RECT 431.808 226.752 432.000 226.776 ;
    END
  END li_d[194]
  PIN li_d[195]
    DIRECTION OUTPUT ;
    USE SIGNAL ;
    PORT
      LAYER M4 ;
        RECT 431.808 227.040 432.000 227.064 ;
    END
  END li_d[195]
  PIN li_d[196]
    DIRECTION OUTPUT ;
    USE SIGNAL ;
    PORT
      LAYER M4 ;
        RECT 431.808 227.328 432.000 227.352 ;
    END
  END li_d[196]
  PIN li_d[197]
    DIRECTION OUTPUT ;
    USE SIGNAL ;
    PORT
      LAYER M4 ;
        RECT 431.808 227.664 432.000 227.688 ;
    END
  END li_d[197]
  PIN li_d[198]
    DIRECTION OUTPUT ;
    USE SIGNAL ;
    PORT
      LAYER M4 ;
        RECT 431.808 227.952 432.000 227.976 ;
    END
  END li_d[198]
  PIN li_d[199]
    DIRECTION OUTPUT ;
    USE SIGNAL ;
    PORT
      LAYER M4 ;
        RECT 431.808 228.240 432.000 228.264 ;
    END
  END li_d[199]
  PIN li_d[200]
    DIRECTION OUTPUT ;
    USE SIGNAL ;
    PORT
      LAYER M4 ;
        RECT 431.808 228.528 432.000 228.552 ;
    END
  END li_d[200]
  PIN li_d[201]
    DIRECTION OUTPUT ;
    USE SIGNAL ;
    PORT
      LAYER M4 ;
        RECT 431.808 228.816 432.000 228.840 ;
    END
  END li_d[201]
  PIN li_d[202]
    DIRECTION OUTPUT ;
    USE SIGNAL ;
    PORT
      LAYER M4 ;
        RECT 431.808 229.152 432.000 229.176 ;
    END
  END li_d[202]
  PIN li_d[203]
    DIRECTION OUTPUT ;
    USE SIGNAL ;
    PORT
      LAYER M4 ;
        RECT 431.808 229.440 432.000 229.464 ;
    END
  END li_d[203]
  PIN li_d[204]
    DIRECTION OUTPUT ;
    USE SIGNAL ;
    PORT
      LAYER M4 ;
        RECT 431.808 229.728 432.000 229.752 ;
    END
  END li_d[204]
  PIN li_d[205]
    DIRECTION OUTPUT ;
    USE SIGNAL ;
    PORT
      LAYER M4 ;
        RECT 431.808 230.016 432.000 230.040 ;
    END
  END li_d[205]
  PIN li_d[206]
    DIRECTION OUTPUT ;
    USE SIGNAL ;
    PORT
      LAYER M4 ;
        RECT 431.808 230.352 432.000 230.376 ;
    END
  END li_d[206]
  PIN li_d[207]
    DIRECTION OUTPUT ;
    USE SIGNAL ;
    PORT
      LAYER M4 ;
        RECT 431.808 230.640 432.000 230.664 ;
    END
  END li_d[207]
  PIN li_d[208]
    DIRECTION OUTPUT ;
    USE SIGNAL ;
    PORT
      LAYER M4 ;
        RECT 431.808 230.928 432.000 230.952 ;
    END
  END li_d[208]
  PIN li_d[209]
    DIRECTION OUTPUT ;
    USE SIGNAL ;
    PORT
      LAYER M4 ;
        RECT 431.808 231.216 432.000 231.240 ;
    END
  END li_d[209]
  PIN li_d[210]
    DIRECTION OUTPUT ;
    USE SIGNAL ;
    PORT
      LAYER M4 ;
        RECT 431.808 231.552 432.000 231.576 ;
    END
  END li_d[210]
  PIN li_d[211]
    DIRECTION OUTPUT ;
    USE SIGNAL ;
    PORT
      LAYER M4 ;
        RECT 431.808 231.840 432.000 231.864 ;
    END
  END li_d[211]
  PIN li_d[212]
    DIRECTION OUTPUT ;
    USE SIGNAL ;
    PORT
      LAYER M4 ;
        RECT 431.808 232.128 432.000 232.152 ;
    END
  END li_d[212]
  PIN li_d[213]
    DIRECTION OUTPUT ;
    USE SIGNAL ;
    PORT
      LAYER M4 ;
        RECT 431.808 232.416 432.000 232.440 ;
    END
  END li_d[213]
  PIN li_d[214]
    DIRECTION OUTPUT ;
    USE SIGNAL ;
    PORT
      LAYER M4 ;
        RECT 431.808 232.704 432.000 232.728 ;
    END
  END li_d[214]
  PIN li_d[215]
    DIRECTION OUTPUT ;
    USE SIGNAL ;
    PORT
      LAYER M4 ;
        RECT 431.808 233.040 432.000 233.064 ;
    END
  END li_d[215]
  PIN li_d[216]
    DIRECTION OUTPUT ;
    USE SIGNAL ;
    PORT
      LAYER M4 ;
        RECT 431.808 233.328 432.000 233.352 ;
    END
  END li_d[216]
  PIN li_d[217]
    DIRECTION OUTPUT ;
    USE SIGNAL ;
    PORT
      LAYER M4 ;
        RECT 431.808 233.616 432.000 233.640 ;
    END
  END li_d[217]
  PIN li_d[218]
    DIRECTION OUTPUT ;
    USE SIGNAL ;
    PORT
      LAYER M4 ;
        RECT 431.808 233.904 432.000 233.928 ;
    END
  END li_d[218]
  PIN li_d[219]
    DIRECTION OUTPUT ;
    USE SIGNAL ;
    PORT
      LAYER M4 ;
        RECT 431.808 234.240 432.000 234.264 ;
    END
  END li_d[219]
  PIN li_d[220]
    DIRECTION OUTPUT ;
    USE SIGNAL ;
    PORT
      LAYER M4 ;
        RECT 431.808 234.528 432.000 234.552 ;
    END
  END li_d[220]
  PIN li_d[221]
    DIRECTION OUTPUT ;
    USE SIGNAL ;
    PORT
      LAYER M4 ;
        RECT 431.808 234.816 432.000 234.840 ;
    END
  END li_d[221]
  PIN li_d[222]
    DIRECTION OUTPUT ;
    USE SIGNAL ;
    PORT
      LAYER M4 ;
        RECT 431.808 235.104 432.000 235.128 ;
    END
  END li_d[222]
  PIN li_d[223]
    DIRECTION OUTPUT ;
    USE SIGNAL ;
    PORT
      LAYER M4 ;
        RECT 431.808 235.392 432.000 235.416 ;
    END
  END li_d[223]
  PIN li_d[224]
    DIRECTION OUTPUT ;
    USE SIGNAL ;
    PORT
      LAYER M4 ;
        RECT 431.808 235.728 432.000 235.752 ;
    END
  END li_d[224]
  PIN li_d[225]
    DIRECTION OUTPUT ;
    USE SIGNAL ;
    PORT
      LAYER M4 ;
        RECT 431.808 236.016 432.000 236.040 ;
    END
  END li_d[225]
  PIN li_d[226]
    DIRECTION OUTPUT ;
    USE SIGNAL ;
    PORT
      LAYER M4 ;
        RECT 431.808 236.304 432.000 236.328 ;
    END
  END li_d[226]
  PIN li_d[227]
    DIRECTION OUTPUT ;
    USE SIGNAL ;
    PORT
      LAYER M4 ;
        RECT 431.808 236.592 432.000 236.616 ;
    END
  END li_d[227]
  PIN li_d[228]
    DIRECTION OUTPUT ;
    USE SIGNAL ;
    PORT
      LAYER M4 ;
        RECT 431.808 236.928 432.000 236.952 ;
    END
  END li_d[228]
  PIN li_d[229]
    DIRECTION OUTPUT ;
    USE SIGNAL ;
    PORT
      LAYER M4 ;
        RECT 431.808 237.216 432.000 237.240 ;
    END
  END li_d[229]
  PIN li_d[230]
    DIRECTION OUTPUT ;
    USE SIGNAL ;
    PORT
      LAYER M4 ;
        RECT 431.808 237.504 432.000 237.528 ;
    END
  END li_d[230]
  PIN li_d[231]
    DIRECTION OUTPUT ;
    USE SIGNAL ;
    PORT
      LAYER M4 ;
        RECT 431.808 237.792 432.000 237.816 ;
    END
  END li_d[231]
  PIN li_d[232]
    DIRECTION OUTPUT ;
    USE SIGNAL ;
    PORT
      LAYER M4 ;
        RECT 431.808 238.128 432.000 238.152 ;
    END
  END li_d[232]
  PIN li_d[233]
    DIRECTION OUTPUT ;
    USE SIGNAL ;
    PORT
      LAYER M4 ;
        RECT 431.808 238.416 432.000 238.440 ;
    END
  END li_d[233]
  PIN li_d[234]
    DIRECTION OUTPUT ;
    USE SIGNAL ;
    PORT
      LAYER M4 ;
        RECT 431.808 238.704 432.000 238.728 ;
    END
  END li_d[234]
  PIN li_d[235]
    DIRECTION OUTPUT ;
    USE SIGNAL ;
    PORT
      LAYER M4 ;
        RECT 431.808 238.992 432.000 239.016 ;
    END
  END li_d[235]
  PIN li_d[236]
    DIRECTION OUTPUT ;
    USE SIGNAL ;
    PORT
      LAYER M4 ;
        RECT 431.808 239.280 432.000 239.304 ;
    END
  END li_d[236]
  PIN li_d[237]
    DIRECTION OUTPUT ;
    USE SIGNAL ;
    PORT
      LAYER M4 ;
        RECT 431.808 239.616 432.000 239.640 ;
    END
  END li_d[237]
  PIN li_d[238]
    DIRECTION OUTPUT ;
    USE SIGNAL ;
    PORT
      LAYER M4 ;
        RECT 431.808 239.904 432.000 239.928 ;
    END
  END li_d[238]
  PIN li_d[239]
    DIRECTION OUTPUT ;
    USE SIGNAL ;
    PORT
      LAYER M4 ;
        RECT 431.808 240.192 432.000 240.216 ;
    END
  END li_d[239]
  PIN li_d[240]
    DIRECTION OUTPUT ;
    USE SIGNAL ;
    PORT
      LAYER M4 ;
        RECT 431.808 240.480 432.000 240.504 ;
    END
  END li_d[240]
  PIN li_d[241]
    DIRECTION OUTPUT ;
    USE SIGNAL ;
    PORT
      LAYER M4 ;
        RECT 431.808 240.816 432.000 240.840 ;
    END
  END li_d[241]
  PIN li_d[242]
    DIRECTION OUTPUT ;
    USE SIGNAL ;
    PORT
      LAYER M4 ;
        RECT 431.808 241.104 432.000 241.128 ;
    END
  END li_d[242]
  PIN li_d[243]
    DIRECTION OUTPUT ;
    USE SIGNAL ;
    PORT
      LAYER M4 ;
        RECT 431.808 241.392 432.000 241.416 ;
    END
  END li_d[243]
  PIN li_d[244]
    DIRECTION OUTPUT ;
    USE SIGNAL ;
    PORT
      LAYER M4 ;
        RECT 431.808 241.680 432.000 241.704 ;
    END
  END li_d[244]
  PIN li_d[245]
    DIRECTION OUTPUT ;
    USE SIGNAL ;
    PORT
      LAYER M4 ;
        RECT 431.808 241.968 432.000 241.992 ;
    END
  END li_d[245]
  PIN li_d[246]
    DIRECTION OUTPUT ;
    USE SIGNAL ;
    PORT
      LAYER M4 ;
        RECT 431.808 242.304 432.000 242.328 ;
    END
  END li_d[246]
  PIN li_d[247]
    DIRECTION OUTPUT ;
    USE SIGNAL ;
    PORT
      LAYER M4 ;
        RECT 431.808 242.592 432.000 242.616 ;
    END
  END li_d[247]
  PIN li_d[248]
    DIRECTION OUTPUT ;
    USE SIGNAL ;
    PORT
      LAYER M4 ;
        RECT 431.808 242.880 432.000 242.904 ;
    END
  END li_d[248]
  PIN li_d[249]
    DIRECTION OUTPUT ;
    USE SIGNAL ;
    PORT
      LAYER M4 ;
        RECT 431.808 243.168 432.000 243.192 ;
    END
  END li_d[249]
  PIN li_d[250]
    DIRECTION OUTPUT ;
    USE SIGNAL ;
    PORT
      LAYER M4 ;
        RECT 431.808 243.504 432.000 243.528 ;
    END
  END li_d[250]
  PIN li_d[251]
    DIRECTION OUTPUT ;
    USE SIGNAL ;
    PORT
      LAYER M4 ;
        RECT 431.808 243.792 432.000 243.816 ;
    END
  END li_d[251]
  PIN li_d[252]
    DIRECTION OUTPUT ;
    USE SIGNAL ;
    PORT
      LAYER M4 ;
        RECT 431.808 244.080 432.000 244.104 ;
    END
  END li_d[252]
  PIN li_d[253]
    DIRECTION OUTPUT ;
    USE SIGNAL ;
    PORT
      LAYER M4 ;
        RECT 431.808 244.368 432.000 244.392 ;
    END
  END li_d[253]
  PIN li_d[254]
    DIRECTION OUTPUT ;
    USE SIGNAL ;
    PORT
      LAYER M4 ;
        RECT 431.808 244.656 432.000 244.680 ;
    END
  END li_d[254]
  PIN li_d[255]
    DIRECTION OUTPUT ;
    USE SIGNAL ;
    PORT
      LAYER M4 ;
        RECT 431.808 244.992 432.000 245.016 ;
    END
  END li_d[255]
  PIN li_d[256]
    DIRECTION OUTPUT ;
    USE SIGNAL ;
    PORT
      LAYER M4 ;
        RECT 431.808 245.280 432.000 245.304 ;
    END
  END li_d[256]
  PIN li_d[257]
    DIRECTION OUTPUT ;
    USE SIGNAL ;
    PORT
      LAYER M4 ;
        RECT 431.808 245.568 432.000 245.592 ;
    END
  END li_d[257]
  PIN li_d[258]
    DIRECTION OUTPUT ;
    USE SIGNAL ;
    PORT
      LAYER M4 ;
        RECT 431.808 245.856 432.000 245.880 ;
    END
  END li_d[258]
  PIN li_d[259]
    DIRECTION OUTPUT ;
    USE SIGNAL ;
    PORT
      LAYER M4 ;
        RECT 431.808 246.192 432.000 246.216 ;
    END
  END li_d[259]
  PIN li_d[260]
    DIRECTION OUTPUT ;
    USE SIGNAL ;
    PORT
      LAYER M4 ;
        RECT 431.808 246.480 432.000 246.504 ;
    END
  END li_d[260]
  PIN li_d[261]
    DIRECTION OUTPUT ;
    USE SIGNAL ;
    PORT
      LAYER M4 ;
        RECT 431.808 246.768 432.000 246.792 ;
    END
  END li_d[261]
  PIN li_d[262]
    DIRECTION OUTPUT ;
    USE SIGNAL ;
    PORT
      LAYER M4 ;
        RECT 431.808 247.056 432.000 247.080 ;
    END
  END li_d[262]
  PIN li_d[263]
    DIRECTION OUTPUT ;
    USE SIGNAL ;
    PORT
      LAYER M4 ;
        RECT 431.808 247.392 432.000 247.416 ;
    END
  END li_d[263]
  PIN li_d[264]
    DIRECTION OUTPUT ;
    USE SIGNAL ;
    PORT
      LAYER M4 ;
        RECT 431.808 247.680 432.000 247.704 ;
    END
  END li_d[264]
  PIN li_d[265]
    DIRECTION OUTPUT ;
    USE SIGNAL ;
    PORT
      LAYER M4 ;
        RECT 431.808 247.968 432.000 247.992 ;
    END
  END li_d[265]
  PIN li_d[266]
    DIRECTION OUTPUT ;
    USE SIGNAL ;
    PORT
      LAYER M4 ;
        RECT 431.808 248.256 432.000 248.280 ;
    END
  END li_d[266]
  PIN li_d[267]
    DIRECTION OUTPUT ;
    USE SIGNAL ;
    PORT
      LAYER M4 ;
        RECT 431.808 248.544 432.000 248.568 ;
    END
  END li_d[267]
  PIN li_d[268]
    DIRECTION OUTPUT ;
    USE SIGNAL ;
    PORT
      LAYER M4 ;
        RECT 431.808 248.880 432.000 248.904 ;
    END
  END li_d[268]
  PIN li_d[269]
    DIRECTION OUTPUT ;
    USE SIGNAL ;
    PORT
      LAYER M4 ;
        RECT 431.808 249.168 432.000 249.192 ;
    END
  END li_d[269]
  PIN li_d[270]
    DIRECTION OUTPUT ;
    USE SIGNAL ;
    PORT
      LAYER M4 ;
        RECT 431.808 249.456 432.000 249.480 ;
    END
  END li_d[270]
  PIN li_d[271]
    DIRECTION OUTPUT ;
    USE SIGNAL ;
    PORT
      LAYER M4 ;
        RECT 431.808 249.744 432.000 249.768 ;
    END
  END li_d[271]
  PIN li_d[272]
    DIRECTION OUTPUT ;
    USE SIGNAL ;
    PORT
      LAYER M4 ;
        RECT 431.808 250.080 432.000 250.104 ;
    END
  END li_d[272]
  PIN li_d[273]
    DIRECTION OUTPUT ;
    USE SIGNAL ;
    PORT
      LAYER M4 ;
        RECT 431.808 250.368 432.000 250.392 ;
    END
  END li_d[273]
  PIN li_d[274]
    DIRECTION OUTPUT ;
    USE SIGNAL ;
    PORT
      LAYER M4 ;
        RECT 431.808 250.656 432.000 250.680 ;
    END
  END li_d[274]
  PIN li_d[275]
    DIRECTION OUTPUT ;
    USE SIGNAL ;
    PORT
      LAYER M4 ;
        RECT 431.808 250.944 432.000 250.968 ;
    END
  END li_d[275]
  PIN li_d[276]
    DIRECTION OUTPUT ;
    USE SIGNAL ;
    PORT
      LAYER M4 ;
        RECT 431.808 251.232 432.000 251.256 ;
    END
  END li_d[276]
  PIN li_d[277]
    DIRECTION OUTPUT ;
    USE SIGNAL ;
    PORT
      LAYER M4 ;
        RECT 431.808 251.568 432.000 251.592 ;
    END
  END li_d[277]
  PIN li_d[278]
    DIRECTION OUTPUT ;
    USE SIGNAL ;
    PORT
      LAYER M4 ;
        RECT 431.808 251.856 432.000 251.880 ;
    END
  END li_d[278]
  PIN li_d[279]
    DIRECTION OUTPUT ;
    USE SIGNAL ;
    PORT
      LAYER M4 ;
        RECT 431.808 252.144 432.000 252.168 ;
    END
  END li_d[279]
  PIN li_d[280]
    DIRECTION OUTPUT ;
    USE SIGNAL ;
    PORT
      LAYER M4 ;
        RECT 431.808 252.432 432.000 252.456 ;
    END
  END li_d[280]
  PIN li_d[281]
    DIRECTION OUTPUT ;
    USE SIGNAL ;
    PORT
      LAYER M4 ;
        RECT 431.808 252.768 432.000 252.792 ;
    END
  END li_d[281]
  PIN li_d[282]
    DIRECTION OUTPUT ;
    USE SIGNAL ;
    PORT
      LAYER M4 ;
        RECT 431.808 253.056 432.000 253.080 ;
    END
  END li_d[282]
  PIN li_d[283]
    DIRECTION OUTPUT ;
    USE SIGNAL ;
    PORT
      LAYER M4 ;
        RECT 431.808 253.344 432.000 253.368 ;
    END
  END li_d[283]
  PIN li_d[284]
    DIRECTION OUTPUT ;
    USE SIGNAL ;
    PORT
      LAYER M4 ;
        RECT 431.808 253.632 432.000 253.656 ;
    END
  END li_d[284]
  PIN li_d[285]
    DIRECTION OUTPUT ;
    USE SIGNAL ;
    PORT
      LAYER M4 ;
        RECT 431.808 253.968 432.000 253.992 ;
    END
  END li_d[285]
  PIN li_d[286]
    DIRECTION OUTPUT ;
    USE SIGNAL ;
    PORT
      LAYER M4 ;
        RECT 431.808 254.256 432.000 254.280 ;
    END
  END li_d[286]
  PIN li_d[287]
    DIRECTION OUTPUT ;
    USE SIGNAL ;
    PORT
      LAYER M4 ;
        RECT 431.808 254.544 432.000 254.568 ;
    END
  END li_d[287]
  PIN li_d[288]
    DIRECTION OUTPUT ;
    USE SIGNAL ;
    PORT
      LAYER M4 ;
        RECT 431.808 254.832 432.000 254.856 ;
    END
  END li_d[288]
  PIN li_d[289]
    DIRECTION OUTPUT ;
    USE SIGNAL ;
    PORT
      LAYER M4 ;
        RECT 431.808 255.120 432.000 255.144 ;
    END
  END li_d[289]
  PIN li_d[290]
    DIRECTION OUTPUT ;
    USE SIGNAL ;
    PORT
      LAYER M4 ;
        RECT 431.808 255.456 432.000 255.480 ;
    END
  END li_d[290]
  PIN li_d[291]
    DIRECTION OUTPUT ;
    USE SIGNAL ;
    PORT
      LAYER M4 ;
        RECT 431.808 255.744 432.000 255.768 ;
    END
  END li_d[291]
  PIN li_d[292]
    DIRECTION OUTPUT ;
    USE SIGNAL ;
    PORT
      LAYER M4 ;
        RECT 431.808 256.032 432.000 256.056 ;
    END
  END li_d[292]
  PIN li_d[293]
    DIRECTION OUTPUT ;
    USE SIGNAL ;
    PORT
      LAYER M4 ;
        RECT 431.808 256.320 432.000 256.344 ;
    END
  END li_d[293]
  PIN li_d[294]
    DIRECTION OUTPUT ;
    USE SIGNAL ;
    PORT
      LAYER M4 ;
        RECT 431.808 256.656 432.000 256.680 ;
    END
  END li_d[294]
  PIN li_d[295]
    DIRECTION OUTPUT ;
    USE SIGNAL ;
    PORT
      LAYER M4 ;
        RECT 431.808 256.944 432.000 256.968 ;
    END
  END li_d[295]
  PIN li_d[296]
    DIRECTION OUTPUT ;
    USE SIGNAL ;
    PORT
      LAYER M4 ;
        RECT 431.808 257.232 432.000 257.256 ;
    END
  END li_d[296]
  PIN li_d[297]
    DIRECTION OUTPUT ;
    USE SIGNAL ;
    PORT
      LAYER M4 ;
        RECT 431.808 257.520 432.000 257.544 ;
    END
  END li_d[297]
  PIN li_d[298]
    DIRECTION OUTPUT ;
    USE SIGNAL ;
    PORT
      LAYER M4 ;
        RECT 431.808 257.808 432.000 257.832 ;
    END
  END li_d[298]
  PIN li_d[299]
    DIRECTION OUTPUT ;
    USE SIGNAL ;
    PORT
      LAYER M4 ;
        RECT 431.808 258.144 432.000 258.168 ;
    END
  END li_d[299]
  PIN li_d[300]
    DIRECTION OUTPUT ;
    USE SIGNAL ;
    PORT
      LAYER M4 ;
        RECT 431.808 258.432 432.000 258.456 ;
    END
  END li_d[300]
  PIN li_d[301]
    DIRECTION OUTPUT ;
    USE SIGNAL ;
    PORT
      LAYER M4 ;
        RECT 431.808 258.720 432.000 258.744 ;
    END
  END li_d[301]
  PIN li_d[302]
    DIRECTION OUTPUT ;
    USE SIGNAL ;
    PORT
      LAYER M4 ;
        RECT 431.808 259.008 432.000 259.032 ;
    END
  END li_d[302]
  PIN li_d[303]
    DIRECTION OUTPUT ;
    USE SIGNAL ;
    PORT
      LAYER M4 ;
        RECT 431.808 259.344 432.000 259.368 ;
    END
  END li_d[303]
  PIN li_d[304]
    DIRECTION OUTPUT ;
    USE SIGNAL ;
    PORT
      LAYER M4 ;
        RECT 431.808 259.632 432.000 259.656 ;
    END
  END li_d[304]
  PIN li_d[305]
    DIRECTION OUTPUT ;
    USE SIGNAL ;
    PORT
      LAYER M4 ;
        RECT 431.808 259.920 432.000 259.944 ;
    END
  END li_d[305]
  PIN li_d[306]
    DIRECTION OUTPUT ;
    USE SIGNAL ;
    PORT
      LAYER M4 ;
        RECT 431.808 260.208 432.000 260.232 ;
    END
  END li_d[306]
  PIN li_d[307]
    DIRECTION OUTPUT ;
    USE SIGNAL ;
    PORT
      LAYER M4 ;
        RECT 431.808 260.496 432.000 260.520 ;
    END
  END li_d[307]
  PIN li_d[308]
    DIRECTION OUTPUT ;
    USE SIGNAL ;
    PORT
      LAYER M4 ;
        RECT 431.808 260.832 432.000 260.856 ;
    END
  END li_d[308]
  PIN li_d[309]
    DIRECTION OUTPUT ;
    USE SIGNAL ;
    PORT
      LAYER M4 ;
        RECT 431.808 261.120 432.000 261.144 ;
    END
  END li_d[309]
  PIN li_d[310]
    DIRECTION OUTPUT ;
    USE SIGNAL ;
    PORT
      LAYER M4 ;
        RECT 431.808 261.408 432.000 261.432 ;
    END
  END li_d[310]
  PIN li_d[311]
    DIRECTION OUTPUT ;
    USE SIGNAL ;
    PORT
      LAYER M4 ;
        RECT 431.808 261.696 432.000 261.720 ;
    END
  END li_d[311]
  PIN li_d[312]
    DIRECTION OUTPUT ;
    USE SIGNAL ;
    PORT
      LAYER M4 ;
        RECT 431.808 262.032 432.000 262.056 ;
    END
  END li_d[312]
  PIN li_d[313]
    DIRECTION OUTPUT ;
    USE SIGNAL ;
    PORT
      LAYER M4 ;
        RECT 431.808 262.320 432.000 262.344 ;
    END
  END li_d[313]
  PIN li_d[314]
    DIRECTION OUTPUT ;
    USE SIGNAL ;
    PORT
      LAYER M4 ;
        RECT 431.808 262.608 432.000 262.632 ;
    END
  END li_d[314]
  PIN li_d[315]
    DIRECTION OUTPUT ;
    USE SIGNAL ;
    PORT
      LAYER M4 ;
        RECT 431.808 262.896 432.000 262.920 ;
    END
  END li_d[315]
  PIN li_d[316]
    DIRECTION OUTPUT ;
    USE SIGNAL ;
    PORT
      LAYER M4 ;
        RECT 431.808 263.232 432.000 263.256 ;
    END
  END li_d[316]
  PIN li_d[317]
    DIRECTION OUTPUT ;
    USE SIGNAL ;
    PORT
      LAYER M4 ;
        RECT 431.808 263.520 432.000 263.544 ;
    END
  END li_d[317]
  PIN li_d[318]
    DIRECTION OUTPUT ;
    USE SIGNAL ;
    PORT
      LAYER M4 ;
        RECT 431.808 263.808 432.000 263.832 ;
    END
  END li_d[318]
  PIN li_d[319]
    DIRECTION OUTPUT ;
    USE SIGNAL ;
    PORT
      LAYER M4 ;
        RECT 431.808 264.096 432.000 264.120 ;
    END
  END li_d[319]
  PIN li_d[320]
    DIRECTION OUTPUT ;
    USE SIGNAL ;
    PORT
      LAYER M4 ;
        RECT 431.808 264.384 432.000 264.408 ;
    END
  END li_d[320]
  PIN li_d[321]
    DIRECTION OUTPUT ;
    USE SIGNAL ;
    PORT
      LAYER M4 ;
        RECT 431.808 264.720 432.000 264.744 ;
    END
  END li_d[321]
  PIN li_d[322]
    DIRECTION OUTPUT ;
    USE SIGNAL ;
    PORT
      LAYER M4 ;
        RECT 431.808 265.008 432.000 265.032 ;
    END
  END li_d[322]
  PIN li_d[323]
    DIRECTION OUTPUT ;
    USE SIGNAL ;
    PORT
      LAYER M4 ;
        RECT 431.808 265.296 432.000 265.320 ;
    END
  END li_d[323]
  PIN li_d[324]
    DIRECTION OUTPUT ;
    USE SIGNAL ;
    PORT
      LAYER M4 ;
        RECT 431.808 265.584 432.000 265.608 ;
    END
  END li_d[324]
  PIN li_d[325]
    DIRECTION OUTPUT ;
    USE SIGNAL ;
    PORT
      LAYER M4 ;
        RECT 431.808 265.920 432.000 265.944 ;
    END
  END li_d[325]
  PIN li_d[326]
    DIRECTION OUTPUT ;
    USE SIGNAL ;
    PORT
      LAYER M4 ;
        RECT 431.808 266.208 432.000 266.232 ;
    END
  END li_d[326]
  PIN li_d[327]
    DIRECTION OUTPUT ;
    USE SIGNAL ;
    PORT
      LAYER M4 ;
        RECT 431.808 266.496 432.000 266.520 ;
    END
  END li_d[327]
  PIN li_d[328]
    DIRECTION OUTPUT ;
    USE SIGNAL ;
    PORT
      LAYER M4 ;
        RECT 431.808 266.784 432.000 266.808 ;
    END
  END li_d[328]
  PIN li_d[329]
    DIRECTION OUTPUT ;
    USE SIGNAL ;
    PORT
      LAYER M4 ;
        RECT 431.808 267.072 432.000 267.096 ;
    END
  END li_d[329]
  PIN li_d[330]
    DIRECTION OUTPUT ;
    USE SIGNAL ;
    PORT
      LAYER M4 ;
        RECT 431.808 267.408 432.000 267.432 ;
    END
  END li_d[330]
  PIN li_d[331]
    DIRECTION OUTPUT ;
    USE SIGNAL ;
    PORT
      LAYER M4 ;
        RECT 431.808 267.696 432.000 267.720 ;
    END
  END li_d[331]
  PIN li_d[332]
    DIRECTION OUTPUT ;
    USE SIGNAL ;
    PORT
      LAYER M4 ;
        RECT 431.808 267.984 432.000 268.008 ;
    END
  END li_d[332]
  PIN li_d[333]
    DIRECTION OUTPUT ;
    USE SIGNAL ;
    PORT
      LAYER M4 ;
        RECT 431.808 268.272 432.000 268.296 ;
    END
  END li_d[333]
  PIN li_d[334]
    DIRECTION OUTPUT ;
    USE SIGNAL ;
    PORT
      LAYER M4 ;
        RECT 431.808 268.608 432.000 268.632 ;
    END
  END li_d[334]
  PIN li_d[335]
    DIRECTION OUTPUT ;
    USE SIGNAL ;
    PORT
      LAYER M4 ;
        RECT 431.808 268.896 432.000 268.920 ;
    END
  END li_d[335]
  PIN li_d[336]
    DIRECTION OUTPUT ;
    USE SIGNAL ;
    PORT
      LAYER M4 ;
        RECT 431.808 269.184 432.000 269.208 ;
    END
  END li_d[336]
  PIN li_d[337]
    DIRECTION OUTPUT ;
    USE SIGNAL ;
    PORT
      LAYER M4 ;
        RECT 431.808 269.472 432.000 269.496 ;
    END
  END li_d[337]
  PIN li_d[338]
    DIRECTION OUTPUT ;
    USE SIGNAL ;
    PORT
      LAYER M4 ;
        RECT 431.808 269.808 432.000 269.832 ;
    END
  END li_d[338]
  PIN li_d[339]
    DIRECTION OUTPUT ;
    USE SIGNAL ;
    PORT
      LAYER M4 ;
        RECT 431.808 270.096 432.000 270.120 ;
    END
  END li_d[339]
  PIN li_d[340]
    DIRECTION OUTPUT ;
    USE SIGNAL ;
    PORT
      LAYER M4 ;
        RECT 431.808 270.384 432.000 270.408 ;
    END
  END li_d[340]
  PIN li_d[341]
    DIRECTION OUTPUT ;
    USE SIGNAL ;
    PORT
      LAYER M4 ;
        RECT 431.808 270.672 432.000 270.696 ;
    END
  END li_d[341]
  PIN li_d[342]
    DIRECTION OUTPUT ;
    USE SIGNAL ;
    PORT
      LAYER M4 ;
        RECT 431.808 270.960 432.000 270.984 ;
    END
  END li_d[342]
  PIN li_d[343]
    DIRECTION OUTPUT ;
    USE SIGNAL ;
    PORT
      LAYER M4 ;
        RECT 431.808 271.296 432.000 271.320 ;
    END
  END li_d[343]
  PIN li_d[344]
    DIRECTION OUTPUT ;
    USE SIGNAL ;
    PORT
      LAYER M4 ;
        RECT 431.808 271.584 432.000 271.608 ;
    END
  END li_d[344]
  PIN li_d[345]
    DIRECTION OUTPUT ;
    USE SIGNAL ;
    PORT
      LAYER M4 ;
        RECT 431.808 271.872 432.000 271.896 ;
    END
  END li_d[345]
  PIN li_d[346]
    DIRECTION OUTPUT ;
    USE SIGNAL ;
    PORT
      LAYER M4 ;
        RECT 431.808 272.160 432.000 272.184 ;
    END
  END li_d[346]
  PIN li_d[347]
    DIRECTION OUTPUT ;
    USE SIGNAL ;
    PORT
      LAYER M4 ;
        RECT 431.808 272.496 432.000 272.520 ;
    END
  END li_d[347]
  PIN li_d[348]
    DIRECTION OUTPUT ;
    USE SIGNAL ;
    PORT
      LAYER M4 ;
        RECT 431.808 272.784 432.000 272.808 ;
    END
  END li_d[348]
  PIN li_d[349]
    DIRECTION OUTPUT ;
    USE SIGNAL ;
    PORT
      LAYER M4 ;
        RECT 431.808 273.072 432.000 273.096 ;
    END
  END li_d[349]
  PIN li_d[350]
    DIRECTION OUTPUT ;
    USE SIGNAL ;
    PORT
      LAYER M4 ;
        RECT 431.808 273.360 432.000 273.384 ;
    END
  END li_d[350]
  PIN li_d[351]
    DIRECTION OUTPUT ;
    USE SIGNAL ;
    PORT
      LAYER M4 ;
        RECT 431.808 273.648 432.000 273.672 ;
    END
  END li_d[351]
  PIN li_d[352]
    DIRECTION OUTPUT ;
    USE SIGNAL ;
    PORT
      LAYER M4 ;
        RECT 431.808 273.984 432.000 274.008 ;
    END
  END li_d[352]
  PIN li_d[353]
    DIRECTION OUTPUT ;
    USE SIGNAL ;
    PORT
      LAYER M4 ;
        RECT 431.808 274.272 432.000 274.296 ;
    END
  END li_d[353]
  PIN li_d[354]
    DIRECTION OUTPUT ;
    USE SIGNAL ;
    PORT
      LAYER M4 ;
        RECT 431.808 274.560 432.000 274.584 ;
    END
  END li_d[354]
  PIN li_d[355]
    DIRECTION OUTPUT ;
    USE SIGNAL ;
    PORT
      LAYER M4 ;
        RECT 431.808 274.848 432.000 274.872 ;
    END
  END li_d[355]
  PIN li_d[356]
    DIRECTION OUTPUT ;
    USE SIGNAL ;
    PORT
      LAYER M4 ;
        RECT 431.808 275.184 432.000 275.208 ;
    END
  END li_d[356]
  PIN li_d[357]
    DIRECTION OUTPUT ;
    USE SIGNAL ;
    PORT
      LAYER M4 ;
        RECT 431.808 275.472 432.000 275.496 ;
    END
  END li_d[357]
  PIN li_d[358]
    DIRECTION OUTPUT ;
    USE SIGNAL ;
    PORT
      LAYER M4 ;
        RECT 431.808 275.760 432.000 275.784 ;
    END
  END li_d[358]
  PIN li_d[359]
    DIRECTION OUTPUT ;
    USE SIGNAL ;
    PORT
      LAYER M4 ;
        RECT 431.808 276.048 432.000 276.072 ;
    END
  END li_d[359]
  PIN li_d[360]
    DIRECTION OUTPUT ;
    USE SIGNAL ;
    PORT
      LAYER M4 ;
        RECT 431.808 276.336 432.000 276.360 ;
    END
  END li_d[360]
  PIN li_d[361]
    DIRECTION OUTPUT ;
    USE SIGNAL ;
    PORT
      LAYER M4 ;
        RECT 431.808 276.672 432.000 276.696 ;
    END
  END li_d[361]
  PIN li_d[362]
    DIRECTION OUTPUT ;
    USE SIGNAL ;
    PORT
      LAYER M4 ;
        RECT 431.808 276.960 432.000 276.984 ;
    END
  END li_d[362]
  PIN li_d[363]
    DIRECTION OUTPUT ;
    USE SIGNAL ;
    PORT
      LAYER M4 ;
        RECT 431.808 277.248 432.000 277.272 ;
    END
  END li_d[363]
  PIN li_d[364]
    DIRECTION OUTPUT ;
    USE SIGNAL ;
    PORT
      LAYER M4 ;
        RECT 431.808 277.536 432.000 277.560 ;
    END
  END li_d[364]
  PIN li_d[365]
    DIRECTION OUTPUT ;
    USE SIGNAL ;
    PORT
      LAYER M4 ;
        RECT 431.808 277.872 432.000 277.896 ;
    END
  END li_d[365]
  PIN li_d[366]
    DIRECTION OUTPUT ;
    USE SIGNAL ;
    PORT
      LAYER M4 ;
        RECT 431.808 278.160 432.000 278.184 ;
    END
  END li_d[366]
  PIN li_d[367]
    DIRECTION OUTPUT ;
    USE SIGNAL ;
    PORT
      LAYER M4 ;
        RECT 431.808 278.448 432.000 278.472 ;
    END
  END li_d[367]
  PIN li_d[368]
    DIRECTION OUTPUT ;
    USE SIGNAL ;
    PORT
      LAYER M4 ;
        RECT 431.808 278.736 432.000 278.760 ;
    END
  END li_d[368]
  PIN li_d[369]
    DIRECTION OUTPUT ;
    USE SIGNAL ;
    PORT
      LAYER M4 ;
        RECT 431.808 279.072 432.000 279.096 ;
    END
  END li_d[369]
  PIN li_d[370]
    DIRECTION OUTPUT ;
    USE SIGNAL ;
    PORT
      LAYER M4 ;
        RECT 431.808 279.360 432.000 279.384 ;
    END
  END li_d[370]
  PIN li_d[371]
    DIRECTION OUTPUT ;
    USE SIGNAL ;
    PORT
      LAYER M4 ;
        RECT 431.808 279.648 432.000 279.672 ;
    END
  END li_d[371]
  PIN li_d[372]
    DIRECTION OUTPUT ;
    USE SIGNAL ;
    PORT
      LAYER M4 ;
        RECT 431.808 279.936 432.000 279.960 ;
    END
  END li_d[372]
  PIN li_d[373]
    DIRECTION OUTPUT ;
    USE SIGNAL ;
    PORT
      LAYER M4 ;
        RECT 431.808 280.224 432.000 280.248 ;
    END
  END li_d[373]
  PIN li_d[374]
    DIRECTION OUTPUT ;
    USE SIGNAL ;
    PORT
      LAYER M4 ;
        RECT 431.808 280.560 432.000 280.584 ;
    END
  END li_d[374]
  PIN li_d[375]
    DIRECTION OUTPUT ;
    USE SIGNAL ;
    PORT
      LAYER M4 ;
        RECT 431.808 280.848 432.000 280.872 ;
    END
  END li_d[375]
  PIN li_d[376]
    DIRECTION OUTPUT ;
    USE SIGNAL ;
    PORT
      LAYER M4 ;
        RECT 431.808 281.136 432.000 281.160 ;
    END
  END li_d[376]
  PIN li_d[377]
    DIRECTION OUTPUT ;
    USE SIGNAL ;
    PORT
      LAYER M4 ;
        RECT 431.808 281.424 432.000 281.448 ;
    END
  END li_d[377]
  PIN li_d[378]
    DIRECTION OUTPUT ;
    USE SIGNAL ;
    PORT
      LAYER M4 ;
        RECT 431.808 281.760 432.000 281.784 ;
    END
  END li_d[378]
  PIN li_d[379]
    DIRECTION OUTPUT ;
    USE SIGNAL ;
    PORT
      LAYER M4 ;
        RECT 431.808 282.048 432.000 282.072 ;
    END
  END li_d[379]
  PIN li_d[380]
    DIRECTION OUTPUT ;
    USE SIGNAL ;
    PORT
      LAYER M4 ;
        RECT 431.808 282.336 432.000 282.360 ;
    END
  END li_d[380]
  PIN li_d[381]
    DIRECTION OUTPUT ;
    USE SIGNAL ;
    PORT
      LAYER M4 ;
        RECT 431.808 282.624 432.000 282.648 ;
    END
  END li_d[381]
  PIN li_d[382]
    DIRECTION OUTPUT ;
    USE SIGNAL ;
    PORT
      LAYER M4 ;
        RECT 431.808 282.912 432.000 282.936 ;
    END
  END li_d[382]
  PIN li_d[383]
    DIRECTION OUTPUT ;
    USE SIGNAL ;
    PORT
      LAYER M4 ;
        RECT 431.808 283.248 432.000 283.272 ;
    END
  END li_d[383]
  PIN li_d[384]
    DIRECTION OUTPUT ;
    USE SIGNAL ;
    PORT
      LAYER M4 ;
        RECT 431.808 283.536 432.000 283.560 ;
    END
  END li_d[384]
  PIN li_d[385]
    DIRECTION OUTPUT ;
    USE SIGNAL ;
    PORT
      LAYER M4 ;
        RECT 431.808 283.824 432.000 283.848 ;
    END
  END li_d[385]
  PIN li_d[386]
    DIRECTION OUTPUT ;
    USE SIGNAL ;
    PORT
      LAYER M4 ;
        RECT 431.808 284.112 432.000 284.136 ;
    END
  END li_d[386]
  PIN li_d[387]
    DIRECTION OUTPUT ;
    USE SIGNAL ;
    PORT
      LAYER M4 ;
        RECT 431.808 284.448 432.000 284.472 ;
    END
  END li_d[387]
  PIN li_d[388]
    DIRECTION OUTPUT ;
    USE SIGNAL ;
    PORT
      LAYER M4 ;
        RECT 431.808 284.736 432.000 284.760 ;
    END
  END li_d[388]
  PIN li_d[389]
    DIRECTION OUTPUT ;
    USE SIGNAL ;
    PORT
      LAYER M4 ;
        RECT 431.808 285.024 432.000 285.048 ;
    END
  END li_d[389]
  PIN li_d[390]
    DIRECTION OUTPUT ;
    USE SIGNAL ;
    PORT
      LAYER M4 ;
        RECT 431.808 285.312 432.000 285.336 ;
    END
  END li_d[390]
  PIN li_d[391]
    DIRECTION OUTPUT ;
    USE SIGNAL ;
    PORT
      LAYER M4 ;
        RECT 431.808 285.648 432.000 285.672 ;
    END
  END li_d[391]
  PIN li_d[392]
    DIRECTION OUTPUT ;
    USE SIGNAL ;
    PORT
      LAYER M4 ;
        RECT 431.808 285.936 432.000 285.960 ;
    END
  END li_d[392]
  PIN li_d[393]
    DIRECTION OUTPUT ;
    USE SIGNAL ;
    PORT
      LAYER M4 ;
        RECT 431.808 286.224 432.000 286.248 ;
    END
  END li_d[393]
  PIN li_d[394]
    DIRECTION OUTPUT ;
    USE SIGNAL ;
    PORT
      LAYER M4 ;
        RECT 431.808 286.512 432.000 286.536 ;
    END
  END li_d[394]
  PIN li_d[395]
    DIRECTION OUTPUT ;
    USE SIGNAL ;
    PORT
      LAYER M4 ;
        RECT 431.808 286.800 432.000 286.824 ;
    END
  END li_d[395]
  PIN li_d[396]
    DIRECTION OUTPUT ;
    USE SIGNAL ;
    PORT
      LAYER M4 ;
        RECT 431.808 287.136 432.000 287.160 ;
    END
  END li_d[396]
  PIN li_d[397]
    DIRECTION OUTPUT ;
    USE SIGNAL ;
    PORT
      LAYER M4 ;
        RECT 431.808 287.424 432.000 287.448 ;
    END
  END li_d[397]
  PIN li_d[398]
    DIRECTION OUTPUT ;
    USE SIGNAL ;
    PORT
      LAYER M4 ;
        RECT 431.808 287.712 432.000 287.736 ;
    END
  END li_d[398]
  PIN li_d[399]
    DIRECTION OUTPUT ;
    USE SIGNAL ;
    PORT
      LAYER M4 ;
        RECT 431.808 288.000 432.000 288.024 ;
    END
  END li_d[399]
  PIN li_d[400]
    DIRECTION OUTPUT ;
    USE SIGNAL ;
    PORT
      LAYER M4 ;
        RECT 431.808 288.336 432.000 288.360 ;
    END
  END li_d[400]
  PIN li_d[401]
    DIRECTION OUTPUT ;
    USE SIGNAL ;
    PORT
      LAYER M4 ;
        RECT 431.808 288.624 432.000 288.648 ;
    END
  END li_d[401]
  PIN li_d[402]
    DIRECTION OUTPUT ;
    USE SIGNAL ;
    PORT
      LAYER M4 ;
        RECT 431.808 288.912 432.000 288.936 ;
    END
  END li_d[402]
  PIN li_d[403]
    DIRECTION OUTPUT ;
    USE SIGNAL ;
    PORT
      LAYER M4 ;
        RECT 431.808 289.200 432.000 289.224 ;
    END
  END li_d[403]
  PIN li_d[404]
    DIRECTION OUTPUT ;
    USE SIGNAL ;
    PORT
      LAYER M4 ;
        RECT 431.808 289.488 432.000 289.512 ;
    END
  END li_d[404]
  PIN li_d[405]
    DIRECTION OUTPUT ;
    USE SIGNAL ;
    PORT
      LAYER M4 ;
        RECT 431.808 289.824 432.000 289.848 ;
    END
  END li_d[405]
  PIN li_d[406]
    DIRECTION OUTPUT ;
    USE SIGNAL ;
    PORT
      LAYER M4 ;
        RECT 431.808 290.112 432.000 290.136 ;
    END
  END li_d[406]
  PIN li_d[407]
    DIRECTION OUTPUT ;
    USE SIGNAL ;
    PORT
      LAYER M4 ;
        RECT 431.808 290.400 432.000 290.424 ;
    END
  END li_d[407]
  PIN li_d[408]
    DIRECTION OUTPUT ;
    USE SIGNAL ;
    PORT
      LAYER M4 ;
        RECT 431.808 290.688 432.000 290.712 ;
    END
  END li_d[408]
  PIN li_d[409]
    DIRECTION OUTPUT ;
    USE SIGNAL ;
    PORT
      LAYER M4 ;
        RECT 431.808 291.024 432.000 291.048 ;
    END
  END li_d[409]
  PIN li_d[410]
    DIRECTION OUTPUT ;
    USE SIGNAL ;
    PORT
      LAYER M4 ;
        RECT 431.808 291.312 432.000 291.336 ;
    END
  END li_d[410]
  PIN li_d[411]
    DIRECTION OUTPUT ;
    USE SIGNAL ;
    PORT
      LAYER M4 ;
        RECT 431.808 291.600 432.000 291.624 ;
    END
  END li_d[411]
  PIN li_d[412]
    DIRECTION OUTPUT ;
    USE SIGNAL ;
    PORT
      LAYER M4 ;
        RECT 431.808 291.888 432.000 291.912 ;
    END
  END li_d[412]
  PIN li_d[413]
    DIRECTION OUTPUT ;
    USE SIGNAL ;
    PORT
      LAYER M4 ;
        RECT 431.808 292.176 432.000 292.200 ;
    END
  END li_d[413]
  PIN li_d[414]
    DIRECTION OUTPUT ;
    USE SIGNAL ;
    PORT
      LAYER M4 ;
        RECT 431.808 292.512 432.000 292.536 ;
    END
  END li_d[414]
  PIN li_d[415]
    DIRECTION OUTPUT ;
    USE SIGNAL ;
    PORT
      LAYER M4 ;
        RECT 431.808 292.800 432.000 292.824 ;
    END
  END li_d[415]
  PIN li_d[416]
    DIRECTION OUTPUT ;
    USE SIGNAL ;
    PORT
      LAYER M4 ;
        RECT 431.808 293.088 432.000 293.112 ;
    END
  END li_d[416]
  PIN li_d[417]
    DIRECTION OUTPUT ;
    USE SIGNAL ;
    PORT
      LAYER M4 ;
        RECT 431.808 293.376 432.000 293.400 ;
    END
  END li_d[417]
  PIN li_d[418]
    DIRECTION OUTPUT ;
    USE SIGNAL ;
    PORT
      LAYER M4 ;
        RECT 431.808 293.712 432.000 293.736 ;
    END
  END li_d[418]
  PIN li_d[419]
    DIRECTION OUTPUT ;
    USE SIGNAL ;
    PORT
      LAYER M4 ;
        RECT 431.808 294.000 432.000 294.024 ;
    END
  END li_d[419]
  PIN li_d[420]
    DIRECTION OUTPUT ;
    USE SIGNAL ;
    PORT
      LAYER M4 ;
        RECT 431.808 294.288 432.000 294.312 ;
    END
  END li_d[420]
  PIN li_d[421]
    DIRECTION OUTPUT ;
    USE SIGNAL ;
    PORT
      LAYER M4 ;
        RECT 431.808 294.576 432.000 294.600 ;
    END
  END li_d[421]
  PIN li_d[422]
    DIRECTION OUTPUT ;
    USE SIGNAL ;
    PORT
      LAYER M4 ;
        RECT 431.808 294.912 432.000 294.936 ;
    END
  END li_d[422]
  PIN li_d[423]
    DIRECTION OUTPUT ;
    USE SIGNAL ;
    PORT
      LAYER M4 ;
        RECT 431.808 295.200 432.000 295.224 ;
    END
  END li_d[423]
  PIN li_d[424]
    DIRECTION OUTPUT ;
    USE SIGNAL ;
    PORT
      LAYER M4 ;
        RECT 431.808 295.488 432.000 295.512 ;
    END
  END li_d[424]
  PIN li_d[425]
    DIRECTION OUTPUT ;
    USE SIGNAL ;
    PORT
      LAYER M4 ;
        RECT 431.808 295.776 432.000 295.800 ;
    END
  END li_d[425]
  PIN li_d[426]
    DIRECTION OUTPUT ;
    USE SIGNAL ;
    PORT
      LAYER M4 ;
        RECT 431.808 296.064 432.000 296.088 ;
    END
  END li_d[426]
  PIN li_d[427]
    DIRECTION OUTPUT ;
    USE SIGNAL ;
    PORT
      LAYER M4 ;
        RECT 431.808 296.400 432.000 296.424 ;
    END
  END li_d[427]
  PIN li_d[428]
    DIRECTION OUTPUT ;
    USE SIGNAL ;
    PORT
      LAYER M4 ;
        RECT 431.808 296.688 432.000 296.712 ;
    END
  END li_d[428]
  PIN li_d[429]
    DIRECTION OUTPUT ;
    USE SIGNAL ;
    PORT
      LAYER M4 ;
        RECT 431.808 296.976 432.000 297.000 ;
    END
  END li_d[429]
  PIN li_d[430]
    DIRECTION OUTPUT ;
    USE SIGNAL ;
    PORT
      LAYER M4 ;
        RECT 431.808 297.264 432.000 297.288 ;
    END
  END li_d[430]
  PIN li_d[431]
    DIRECTION OUTPUT ;
    USE SIGNAL ;
    PORT
      LAYER M4 ;
        RECT 431.808 297.600 432.000 297.624 ;
    END
  END li_d[431]
  PIN li_d[432]
    DIRECTION OUTPUT ;
    USE SIGNAL ;
    PORT
      LAYER M4 ;
        RECT 431.808 297.888 432.000 297.912 ;
    END
  END li_d[432]
  PIN li_d[433]
    DIRECTION OUTPUT ;
    USE SIGNAL ;
    PORT
      LAYER M4 ;
        RECT 431.808 298.176 432.000 298.200 ;
    END
  END li_d[433]
  PIN li_d[434]
    DIRECTION OUTPUT ;
    USE SIGNAL ;
    PORT
      LAYER M4 ;
        RECT 431.808 298.464 432.000 298.488 ;
    END
  END li_d[434]
  PIN li_d[435]
    DIRECTION OUTPUT ;
    USE SIGNAL ;
    PORT
      LAYER M4 ;
        RECT 431.808 298.752 432.000 298.776 ;
    END
  END li_d[435]
  PIN li_d[436]
    DIRECTION OUTPUT ;
    USE SIGNAL ;
    PORT
      LAYER M4 ;
        RECT 431.808 299.088 432.000 299.112 ;
    END
  END li_d[436]
  PIN li_d[437]
    DIRECTION OUTPUT ;
    USE SIGNAL ;
    PORT
      LAYER M4 ;
        RECT 431.808 299.376 432.000 299.400 ;
    END
  END li_d[437]
  PIN li_d[438]
    DIRECTION OUTPUT ;
    USE SIGNAL ;
    PORT
      LAYER M4 ;
        RECT 431.808 299.664 432.000 299.688 ;
    END
  END li_d[438]
  PIN li_d[439]
    DIRECTION OUTPUT ;
    USE SIGNAL ;
    PORT
      LAYER M4 ;
        RECT 431.808 299.952 432.000 299.976 ;
    END
  END li_d[439]
  PIN li_d[440]
    DIRECTION OUTPUT ;
    USE SIGNAL ;
    PORT
      LAYER M4 ;
        RECT 431.808 300.288 432.000 300.312 ;
    END
  END li_d[440]
  PIN li_d[441]
    DIRECTION OUTPUT ;
    USE SIGNAL ;
    PORT
      LAYER M4 ;
        RECT 431.808 300.576 432.000 300.600 ;
    END
  END li_d[441]
  PIN li_d[442]
    DIRECTION OUTPUT ;
    USE SIGNAL ;
    PORT
      LAYER M4 ;
        RECT 431.808 300.864 432.000 300.888 ;
    END
  END li_d[442]
  PIN li_d[443]
    DIRECTION OUTPUT ;
    USE SIGNAL ;
    PORT
      LAYER M4 ;
        RECT 431.808 301.152 432.000 301.176 ;
    END
  END li_d[443]
  PIN li_d[444]
    DIRECTION OUTPUT ;
    USE SIGNAL ;
    PORT
      LAYER M4 ;
        RECT 431.808 301.488 432.000 301.512 ;
    END
  END li_d[444]
  PIN li_d[445]
    DIRECTION OUTPUT ;
    USE SIGNAL ;
    PORT
      LAYER M4 ;
        RECT 431.808 301.776 432.000 301.800 ;
    END
  END li_d[445]
  PIN li_d[446]
    DIRECTION OUTPUT ;
    USE SIGNAL ;
    PORT
      LAYER M4 ;
        RECT 431.808 302.064 432.000 302.088 ;
    END
  END li_d[446]
  PIN li_d[447]
    DIRECTION OUTPUT ;
    USE SIGNAL ;
    PORT
      LAYER M4 ;
        RECT 431.808 302.352 432.000 302.376 ;
    END
  END li_d[447]
  PIN li_d[448]
    DIRECTION OUTPUT ;
    USE SIGNAL ;
    PORT
      LAYER M4 ;
        RECT 431.808 302.640 432.000 302.664 ;
    END
  END li_d[448]
  PIN li_d[449]
    DIRECTION OUTPUT ;
    USE SIGNAL ;
    PORT
      LAYER M4 ;
        RECT 431.808 302.976 432.000 303.000 ;
    END
  END li_d[449]
  PIN li_d[450]
    DIRECTION OUTPUT ;
    USE SIGNAL ;
    PORT
      LAYER M4 ;
        RECT 431.808 303.264 432.000 303.288 ;
    END
  END li_d[450]
  PIN li_d[451]
    DIRECTION OUTPUT ;
    USE SIGNAL ;
    PORT
      LAYER M4 ;
        RECT 431.808 303.552 432.000 303.576 ;
    END
  END li_d[451]
  PIN li_d[452]
    DIRECTION OUTPUT ;
    USE SIGNAL ;
    PORT
      LAYER M4 ;
        RECT 431.808 303.840 432.000 303.864 ;
    END
  END li_d[452]
  PIN li_d[453]
    DIRECTION OUTPUT ;
    USE SIGNAL ;
    PORT
      LAYER M4 ;
        RECT 431.808 304.176 432.000 304.200 ;
    END
  END li_d[453]
  PIN li_d[454]
    DIRECTION OUTPUT ;
    USE SIGNAL ;
    PORT
      LAYER M4 ;
        RECT 431.808 304.464 432.000 304.488 ;
    END
  END li_d[454]
  PIN li_d[455]
    DIRECTION OUTPUT ;
    USE SIGNAL ;
    PORT
      LAYER M4 ;
        RECT 431.808 304.752 432.000 304.776 ;
    END
  END li_d[455]
  PIN li_d[456]
    DIRECTION OUTPUT ;
    USE SIGNAL ;
    PORT
      LAYER M4 ;
        RECT 431.808 305.040 432.000 305.064 ;
    END
  END li_d[456]
  PIN li_d[457]
    DIRECTION OUTPUT ;
    USE SIGNAL ;
    PORT
      LAYER M4 ;
        RECT 431.808 305.328 432.000 305.352 ;
    END
  END li_d[457]
  PIN li_d[458]
    DIRECTION OUTPUT ;
    USE SIGNAL ;
    PORT
      LAYER M4 ;
        RECT 431.808 305.664 432.000 305.688 ;
    END
  END li_d[458]
  PIN li_d[459]
    DIRECTION OUTPUT ;
    USE SIGNAL ;
    PORT
      LAYER M4 ;
        RECT 431.808 305.952 432.000 305.976 ;
    END
  END li_d[459]
  PIN li_d[460]
    DIRECTION OUTPUT ;
    USE SIGNAL ;
    PORT
      LAYER M4 ;
        RECT 431.808 306.240 432.000 306.264 ;
    END
  END li_d[460]
  PIN li_d[461]
    DIRECTION OUTPUT ;
    USE SIGNAL ;
    PORT
      LAYER M4 ;
        RECT 431.808 306.528 432.000 306.552 ;
    END
  END li_d[461]
  PIN li_d[462]
    DIRECTION OUTPUT ;
    USE SIGNAL ;
    PORT
      LAYER M4 ;
        RECT 431.808 306.864 432.000 306.888 ;
    END
  END li_d[462]
  PIN li_d[463]
    DIRECTION OUTPUT ;
    USE SIGNAL ;
    PORT
      LAYER M4 ;
        RECT 431.808 307.152 432.000 307.176 ;
    END
  END li_d[463]
  PIN li_d[464]
    DIRECTION OUTPUT ;
    USE SIGNAL ;
    PORT
      LAYER M4 ;
        RECT 431.808 307.440 432.000 307.464 ;
    END
  END li_d[464]
  PIN li_d[465]
    DIRECTION OUTPUT ;
    USE SIGNAL ;
    PORT
      LAYER M4 ;
        RECT 431.808 307.728 432.000 307.752 ;
    END
  END li_d[465]
  PIN li_d[466]
    DIRECTION OUTPUT ;
    USE SIGNAL ;
    PORT
      LAYER M4 ;
        RECT 431.808 308.016 432.000 308.040 ;
    END
  END li_d[466]
  PIN li_d[467]
    DIRECTION OUTPUT ;
    USE SIGNAL ;
    PORT
      LAYER M4 ;
        RECT 431.808 308.352 432.000 308.376 ;
    END
  END li_d[467]
  PIN li_d[468]
    DIRECTION OUTPUT ;
    USE SIGNAL ;
    PORT
      LAYER M4 ;
        RECT 431.808 308.640 432.000 308.664 ;
    END
  END li_d[468]
  PIN li_d[469]
    DIRECTION OUTPUT ;
    USE SIGNAL ;
    PORT
      LAYER M4 ;
        RECT 431.808 308.928 432.000 308.952 ;
    END
  END li_d[469]
  PIN li_d[470]
    DIRECTION OUTPUT ;
    USE SIGNAL ;
    PORT
      LAYER M4 ;
        RECT 431.808 309.216 432.000 309.240 ;
    END
  END li_d[470]
  PIN li_d[471]
    DIRECTION OUTPUT ;
    USE SIGNAL ;
    PORT
      LAYER M4 ;
        RECT 431.808 309.552 432.000 309.576 ;
    END
  END li_d[471]
  PIN li_d[472]
    DIRECTION OUTPUT ;
    USE SIGNAL ;
    PORT
      LAYER M4 ;
        RECT 431.808 309.840 432.000 309.864 ;
    END
  END li_d[472]
  PIN li_d[473]
    DIRECTION OUTPUT ;
    USE SIGNAL ;
    PORT
      LAYER M4 ;
        RECT 431.808 310.128 432.000 310.152 ;
    END
  END li_d[473]
  PIN li_d[474]
    DIRECTION OUTPUT ;
    USE SIGNAL ;
    PORT
      LAYER M4 ;
        RECT 431.808 310.416 432.000 310.440 ;
    END
  END li_d[474]
  PIN li_d[475]
    DIRECTION OUTPUT ;
    USE SIGNAL ;
    PORT
      LAYER M4 ;
        RECT 431.808 310.752 432.000 310.776 ;
    END
  END li_d[475]
  PIN li_d[476]
    DIRECTION OUTPUT ;
    USE SIGNAL ;
    PORT
      LAYER M4 ;
        RECT 431.808 311.040 432.000 311.064 ;
    END
  END li_d[476]
  PIN li_d[477]
    DIRECTION OUTPUT ;
    USE SIGNAL ;
    PORT
      LAYER M4 ;
        RECT 431.808 311.328 432.000 311.352 ;
    END
  END li_d[477]
  PIN li_d[478]
    DIRECTION OUTPUT ;
    USE SIGNAL ;
    PORT
      LAYER M4 ;
        RECT 431.808 311.616 432.000 311.640 ;
    END
  END li_d[478]
  PIN li_d[479]
    DIRECTION OUTPUT ;
    USE SIGNAL ;
    PORT
      LAYER M4 ;
        RECT 431.808 311.904 432.000 311.928 ;
    END
  END li_d[479]
  PIN li_d[480]
    DIRECTION OUTPUT ;
    USE SIGNAL ;
    PORT
      LAYER M4 ;
        RECT 431.808 312.240 432.000 312.264 ;
    END
  END li_d[480]
  PIN li_d[481]
    DIRECTION OUTPUT ;
    USE SIGNAL ;
    PORT
      LAYER M4 ;
        RECT 431.808 312.528 432.000 312.552 ;
    END
  END li_d[481]
  PIN li_d[482]
    DIRECTION OUTPUT ;
    USE SIGNAL ;
    PORT
      LAYER M4 ;
        RECT 431.808 312.816 432.000 312.840 ;
    END
  END li_d[482]
  PIN li_d[483]
    DIRECTION OUTPUT ;
    USE SIGNAL ;
    PORT
      LAYER M4 ;
        RECT 431.808 313.104 432.000 313.128 ;
    END
  END li_d[483]
  PIN li_d[484]
    DIRECTION OUTPUT ;
    USE SIGNAL ;
    PORT
      LAYER M4 ;
        RECT 431.808 313.440 432.000 313.464 ;
    END
  END li_d[484]
  PIN li_d[485]
    DIRECTION OUTPUT ;
    USE SIGNAL ;
    PORT
      LAYER M4 ;
        RECT 431.808 313.728 432.000 313.752 ;
    END
  END li_d[485]
  PIN li_d[486]
    DIRECTION OUTPUT ;
    USE SIGNAL ;
    PORT
      LAYER M4 ;
        RECT 431.808 314.016 432.000 314.040 ;
    END
  END li_d[486]
  PIN li_d[487]
    DIRECTION OUTPUT ;
    USE SIGNAL ;
    PORT
      LAYER M4 ;
        RECT 431.808 314.304 432.000 314.328 ;
    END
  END li_d[487]
  PIN li_d[488]
    DIRECTION OUTPUT ;
    USE SIGNAL ;
    PORT
      LAYER M4 ;
        RECT 431.808 314.592 432.000 314.616 ;
    END
  END li_d[488]
  PIN li_d[489]
    DIRECTION OUTPUT ;
    USE SIGNAL ;
    PORT
      LAYER M4 ;
        RECT 431.808 314.928 432.000 314.952 ;
    END
  END li_d[489]
  PIN li_d[490]
    DIRECTION OUTPUT ;
    USE SIGNAL ;
    PORT
      LAYER M4 ;
        RECT 431.808 315.216 432.000 315.240 ;
    END
  END li_d[490]
  PIN li_d[491]
    DIRECTION OUTPUT ;
    USE SIGNAL ;
    PORT
      LAYER M4 ;
        RECT 431.808 315.504 432.000 315.528 ;
    END
  END li_d[491]
  PIN li_d[492]
    DIRECTION OUTPUT ;
    USE SIGNAL ;
    PORT
      LAYER M4 ;
        RECT 431.808 315.792 432.000 315.816 ;
    END
  END li_d[492]
  PIN li_d[493]
    DIRECTION OUTPUT ;
    USE SIGNAL ;
    PORT
      LAYER M4 ;
        RECT 431.808 316.128 432.000 316.152 ;
    END
  END li_d[493]
  PIN li_d[494]
    DIRECTION OUTPUT ;
    USE SIGNAL ;
    PORT
      LAYER M4 ;
        RECT 431.808 316.416 432.000 316.440 ;
    END
  END li_d[494]
  PIN li_d[495]
    DIRECTION OUTPUT ;
    USE SIGNAL ;
    PORT
      LAYER M4 ;
        RECT 431.808 316.704 432.000 316.728 ;
    END
  END li_d[495]
  PIN li_d[496]
    DIRECTION OUTPUT ;
    USE SIGNAL ;
    PORT
      LAYER M4 ;
        RECT 431.808 316.992 432.000 317.016 ;
    END
  END li_d[496]
  PIN li_d[497]
    DIRECTION OUTPUT ;
    USE SIGNAL ;
    PORT
      LAYER M4 ;
        RECT 431.808 317.328 432.000 317.352 ;
    END
  END li_d[497]
  PIN li_d[498]
    DIRECTION OUTPUT ;
    USE SIGNAL ;
    PORT
      LAYER M4 ;
        RECT 431.808 317.616 432.000 317.640 ;
    END
  END li_d[498]
  PIN li_d[499]
    DIRECTION OUTPUT ;
    USE SIGNAL ;
    PORT
      LAYER M4 ;
        RECT 431.808 317.904 432.000 317.928 ;
    END
  END li_d[499]
  PIN li_d[500]
    DIRECTION OUTPUT ;
    USE SIGNAL ;
    PORT
      LAYER M4 ;
        RECT 431.808 318.192 432.000 318.216 ;
    END
  END li_d[500]
  PIN li_d[501]
    DIRECTION OUTPUT ;
    USE SIGNAL ;
    PORT
      LAYER M4 ;
        RECT 431.808 318.480 432.000 318.504 ;
    END
  END li_d[501]
  PIN li_d[502]
    DIRECTION OUTPUT ;
    USE SIGNAL ;
    PORT
      LAYER M4 ;
        RECT 431.808 318.816 432.000 318.840 ;
    END
  END li_d[502]
  PIN li_d[503]
    DIRECTION OUTPUT ;
    USE SIGNAL ;
    PORT
      LAYER M4 ;
        RECT 431.808 319.104 432.000 319.128 ;
    END
  END li_d[503]
  PIN li_d[504]
    DIRECTION OUTPUT ;
    USE SIGNAL ;
    PORT
      LAYER M4 ;
        RECT 431.808 319.392 432.000 319.416 ;
    END
  END li_d[504]
  PIN li_d[505]
    DIRECTION OUTPUT ;
    USE SIGNAL ;
    PORT
      LAYER M4 ;
        RECT 431.808 319.680 432.000 319.704 ;
    END
  END li_d[505]
  PIN li_d[506]
    DIRECTION OUTPUT ;
    USE SIGNAL ;
    PORT
      LAYER M4 ;
        RECT 431.808 320.016 432.000 320.040 ;
    END
  END li_d[506]
  PIN li_d[507]
    DIRECTION OUTPUT ;
    USE SIGNAL ;
    PORT
      LAYER M4 ;
        RECT 431.808 320.304 432.000 320.328 ;
    END
  END li_d[507]
  PIN li_d[508]
    DIRECTION OUTPUT ;
    USE SIGNAL ;
    PORT
      LAYER M4 ;
        RECT 431.808 320.592 432.000 320.616 ;
    END
  END li_d[508]
  PIN li_d[509]
    DIRECTION OUTPUT ;
    USE SIGNAL ;
    PORT
      LAYER M4 ;
        RECT 431.808 320.880 432.000 320.904 ;
    END
  END li_d[509]
  PIN li_d[510]
    DIRECTION OUTPUT ;
    USE SIGNAL ;
    PORT
      LAYER M4 ;
        RECT 431.808 321.168 432.000 321.192 ;
    END
  END li_d[510]
  PIN li_d[511]
    DIRECTION OUTPUT ;
    USE SIGNAL ;
    PORT
      LAYER M4 ;
        RECT 431.808 321.504 432.000 321.528 ;
    END
  END li_d[511]
  PIN li_d[512]
    DIRECTION OUTPUT ;
    USE SIGNAL ;
    PORT
      LAYER M4 ;
        RECT 431.808 321.792 432.000 321.816 ;
    END
  END li_d[512]
  PIN li_d[513]
    DIRECTION OUTPUT ;
    USE SIGNAL ;
    PORT
      LAYER M4 ;
        RECT 431.808 322.080 432.000 322.104 ;
    END
  END li_d[513]
  PIN li_d[514]
    DIRECTION OUTPUT ;
    USE SIGNAL ;
    PORT
      LAYER M4 ;
        RECT 431.808 322.368 432.000 322.392 ;
    END
  END li_d[514]
  PIN li_d[515]
    DIRECTION OUTPUT ;
    USE SIGNAL ;
    PORT
      LAYER M4 ;
        RECT 431.808 322.704 432.000 322.728 ;
    END
  END li_d[515]
  PIN li_d[516]
    DIRECTION OUTPUT ;
    USE SIGNAL ;
    PORT
      LAYER M4 ;
        RECT 431.808 322.992 432.000 323.016 ;
    END
  END li_d[516]
  PIN li_d[517]
    DIRECTION OUTPUT ;
    USE SIGNAL ;
    PORT
      LAYER M4 ;
        RECT 431.808 323.280 432.000 323.304 ;
    END
  END li_d[517]
  PIN li_d[518]
    DIRECTION OUTPUT ;
    USE SIGNAL ;
    PORT
      LAYER M4 ;
        RECT 431.808 323.568 432.000 323.592 ;
    END
  END li_d[518]
  PIN li_d[519]
    DIRECTION OUTPUT ;
    USE SIGNAL ;
    PORT
      LAYER M4 ;
        RECT 431.808 323.856 432.000 323.880 ;
    END
  END li_d[519]
  PIN li_d[520]
    DIRECTION OUTPUT ;
    USE SIGNAL ;
    PORT
      LAYER M4 ;
        RECT 431.808 324.192 432.000 324.216 ;
    END
  END li_d[520]
  PIN li_d[521]
    DIRECTION OUTPUT ;
    USE SIGNAL ;
    PORT
      LAYER M4 ;
        RECT 431.808 324.480 432.000 324.504 ;
    END
  END li_d[521]
  PIN li_d[522]
    DIRECTION OUTPUT ;
    USE SIGNAL ;
    PORT
      LAYER M4 ;
        RECT 431.808 324.768 432.000 324.792 ;
    END
  END li_d[522]
  PIN li_d[523]
    DIRECTION OUTPUT ;
    USE SIGNAL ;
    PORT
      LAYER M4 ;
        RECT 431.808 325.056 432.000 325.080 ;
    END
  END li_d[523]
  PIN li_d[524]
    DIRECTION OUTPUT ;
    USE SIGNAL ;
    PORT
      LAYER M4 ;
        RECT 431.808 325.392 432.000 325.416 ;
    END
  END li_d[524]
  PIN li_d[525]
    DIRECTION OUTPUT ;
    USE SIGNAL ;
    PORT
      LAYER M4 ;
        RECT 431.808 325.680 432.000 325.704 ;
    END
  END li_d[525]
  PIN li_d[526]
    DIRECTION OUTPUT ;
    USE SIGNAL ;
    PORT
      LAYER M4 ;
        RECT 431.808 325.968 432.000 325.992 ;
    END
  END li_d[526]
  PIN li_d[527]
    DIRECTION OUTPUT ;
    USE SIGNAL ;
    PORT
      LAYER M4 ;
        RECT 431.808 326.256 432.000 326.280 ;
    END
  END li_d[527]
  PIN li_d[528]
    DIRECTION OUTPUT ;
    USE SIGNAL ;
    PORT
      LAYER M4 ;
        RECT 431.808 326.592 432.000 326.616 ;
    END
  END li_d[528]
  PIN li_d[529]
    DIRECTION OUTPUT ;
    USE SIGNAL ;
    PORT
      LAYER M4 ;
        RECT 431.808 326.880 432.000 326.904 ;
    END
  END li_d[529]
  PIN li_d[530]
    DIRECTION OUTPUT ;
    USE SIGNAL ;
    PORT
      LAYER M4 ;
        RECT 431.808 327.168 432.000 327.192 ;
    END
  END li_d[530]
  PIN li_d[531]
    DIRECTION OUTPUT ;
    USE SIGNAL ;
    PORT
      LAYER M4 ;
        RECT 431.808 327.456 432.000 327.480 ;
    END
  END li_d[531]
  PIN li_d[532]
    DIRECTION OUTPUT ;
    USE SIGNAL ;
    PORT
      LAYER M4 ;
        RECT 431.808 327.744 432.000 327.768 ;
    END
  END li_d[532]
  PIN li_d[533]
    DIRECTION OUTPUT ;
    USE SIGNAL ;
    PORT
      LAYER M4 ;
        RECT 431.808 328.080 432.000 328.104 ;
    END
  END li_d[533]
  PIN li_d[534]
    DIRECTION OUTPUT ;
    USE SIGNAL ;
    PORT
      LAYER M4 ;
        RECT 431.808 328.368 432.000 328.392 ;
    END
  END li_d[534]
  PIN li_d[535]
    DIRECTION OUTPUT ;
    USE SIGNAL ;
    PORT
      LAYER M4 ;
        RECT 431.808 328.656 432.000 328.680 ;
    END
  END li_d[535]
  PIN li_d[536]
    DIRECTION OUTPUT ;
    USE SIGNAL ;
    PORT
      LAYER M4 ;
        RECT 431.808 328.944 432.000 328.968 ;
    END
  END li_d[536]
  PIN li_d[537]
    DIRECTION OUTPUT ;
    USE SIGNAL ;
    PORT
      LAYER M4 ;
        RECT 431.808 329.280 432.000 329.304 ;
    END
  END li_d[537]
  PIN li_d[538]
    DIRECTION OUTPUT ;
    USE SIGNAL ;
    PORT
      LAYER M4 ;
        RECT 431.808 329.568 432.000 329.592 ;
    END
  END li_d[538]
  PIN li_d[539]
    DIRECTION OUTPUT ;
    USE SIGNAL ;
    PORT
      LAYER M4 ;
        RECT 431.808 329.856 432.000 329.880 ;
    END
  END li_d[539]
  PIN li_d[540]
    DIRECTION OUTPUT ;
    USE SIGNAL ;
    PORT
      LAYER M4 ;
        RECT 431.808 330.144 432.000 330.168 ;
    END
  END li_d[540]
  PIN li_d[541]
    DIRECTION OUTPUT ;
    USE SIGNAL ;
    PORT
      LAYER M4 ;
        RECT 431.808 330.432 432.000 330.456 ;
    END
  END li_d[541]
  PIN li_d[542]
    DIRECTION OUTPUT ;
    USE SIGNAL ;
    PORT
      LAYER M4 ;
        RECT 431.808 330.768 432.000 330.792 ;
    END
  END li_d[542]
  PIN li_d[543]
    DIRECTION OUTPUT ;
    USE SIGNAL ;
    PORT
      LAYER M4 ;
        RECT 431.808 331.056 432.000 331.080 ;
    END
  END li_d[543]
  PIN li_d[544]
    DIRECTION OUTPUT ;
    USE SIGNAL ;
    PORT
      LAYER M4 ;
        RECT 431.808 331.344 432.000 331.368 ;
    END
  END li_d[544]
  PIN li_d[545]
    DIRECTION OUTPUT ;
    USE SIGNAL ;
    PORT
      LAYER M4 ;
        RECT 431.808 331.632 432.000 331.656 ;
    END
  END li_d[545]
  PIN li_d[546]
    DIRECTION OUTPUT ;
    USE SIGNAL ;
    PORT
      LAYER M4 ;
        RECT 431.808 331.968 432.000 331.992 ;
    END
  END li_d[546]
  PIN li_d[547]
    DIRECTION OUTPUT ;
    USE SIGNAL ;
    PORT
      LAYER M4 ;
        RECT 431.808 332.256 432.000 332.280 ;
    END
  END li_d[547]
  PIN li_d[548]
    DIRECTION OUTPUT ;
    USE SIGNAL ;
    PORT
      LAYER M4 ;
        RECT 431.808 332.544 432.000 332.568 ;
    END
  END li_d[548]
  PIN li_d[549]
    DIRECTION OUTPUT ;
    USE SIGNAL ;
    PORT
      LAYER M4 ;
        RECT 431.808 332.832 432.000 332.856 ;
    END
  END li_d[549]
  PIN li_d[550]
    DIRECTION OUTPUT ;
    USE SIGNAL ;
    PORT
      LAYER M4 ;
        RECT 431.808 333.168 432.000 333.192 ;
    END
  END li_d[550]
  PIN li_d[551]
    DIRECTION OUTPUT ;
    USE SIGNAL ;
    PORT
      LAYER M4 ;
        RECT 431.808 333.456 432.000 333.480 ;
    END
  END li_d[551]
  PIN li_d[552]
    DIRECTION OUTPUT ;
    USE SIGNAL ;
    PORT
      LAYER M4 ;
        RECT 431.808 333.744 432.000 333.768 ;
    END
  END li_d[552]
  PIN flt[0]
    DIRECTION OUTPUT ;
    USE SIGNAL ;
    PORT
      LAYER M4 ;
        RECT 431.808 334.032 432.000 334.056 ;
    END
  END flt[0]
  PIN flt[1]
    DIRECTION OUTPUT ;
    USE SIGNAL ;
    PORT
      LAYER M4 ;
        RECT 431.808 334.320 432.000 334.344 ;
    END
  END flt[1]
  PIN flt[2]
    DIRECTION OUTPUT ;
    USE SIGNAL ;
    PORT
      LAYER M4 ;
        RECT 431.808 334.656 432.000 334.680 ;
    END
  END flt[2]
  PIN ck
    DIRECTION INPUT ;
    USE CLOCK ;
    PORT
      LAYER M5 ;
        RECT 73.440 336.768 73.464 336.960 ;
    END
  END ck
  PIN rs
    DIRECTION INPUT ;
    USE SIGNAL ;
    PORT
      LAYER M5 ;
        RECT 216.000 336.768 216.024 336.960 ;
    END
  END rs
  PIN chb
    DIRECTION INPUT ;
    USE SIGNAL ;
    PORT
      LAYER M3 ;
        RECT 358.557 336.768 358.581 336.960 ;
    END
  END chb
  PIN VDD
    DIRECTION INOUT ;
    USE POWER ;
    PORT
      LAYER M5 ;
        RECT 2.460 0.500 2.580 336.460 ;
        RECT 7.860 0.500 7.980 336.460 ;
        RECT 13.260 0.500 13.380 336.460 ;
        RECT 18.660 0.500 18.780 336.460 ;
        RECT 24.060 0.500 24.180 336.460 ;
        RECT 29.460 0.500 29.580 336.460 ;
        RECT 34.860 0.500 34.980 336.460 ;
        RECT 40.260 0.500 40.380 336.460 ;
        RECT 45.660 0.500 45.780 336.460 ;
        RECT 51.060 0.500 51.180 336.460 ;
        RECT 56.460 0.500 56.580 336.460 ;
        RECT 61.860 0.500 61.980 336.460 ;
        RECT 67.260 0.500 67.380 336.460 ;
        RECT 72.660 0.500 72.780 336.460 ;
        RECT 78.060 0.500 78.180 336.460 ;
        RECT 83.460 0.500 83.580 336.460 ;
        RECT 88.860 0.500 88.980 336.460 ;
        RECT 94.260 0.500 94.380 336.460 ;
        RECT 99.660 0.500 99.780 336.460 ;
        RECT 105.060 0.500 105.180 336.460 ;
        RECT 110.460 0.500 110.580 336.460 ;
        RECT 115.860 0.500 115.980 336.460 ;
        RECT 121.260 0.500 121.380 336.460 ;
        RECT 126.660 0.500 126.780 336.460 ;
        RECT 132.060 0.500 132.180 336.460 ;
        RECT 137.460 0.500 137.580 336.460 ;
        RECT 142.860 0.500 142.980 336.460 ;
        RECT 148.260 0.500 148.380 336.460 ;
        RECT 153.660 0.500 153.780 336.460 ;
        RECT 159.060 0.500 159.180 336.460 ;
        RECT 164.460 0.500 164.580 336.460 ;
        RECT 169.860 0.500 169.980 336.460 ;
        RECT 175.260 0.500 175.380 336.460 ;
        RECT 180.660 0.500 180.780 336.460 ;
        RECT 186.060 0.500 186.180 336.460 ;
        RECT 191.460 0.500 191.580 336.460 ;
        RECT 196.860 0.500 196.980 336.460 ;
        RECT 202.260 0.500 202.380 336.460 ;
        RECT 207.660 0.500 207.780 336.460 ;
        RECT 213.060 0.500 213.180 336.460 ;
        RECT 218.460 0.500 218.580 336.460 ;
        RECT 223.860 0.500 223.980 336.460 ;
        RECT 229.260 0.500 229.380 336.460 ;
        RECT 234.660 0.500 234.780 336.460 ;
        RECT 240.060 0.500 240.180 336.460 ;
        RECT 245.460 0.500 245.580 336.460 ;
        RECT 250.860 0.500 250.980 336.460 ;
        RECT 256.260 0.500 256.380 336.460 ;
        RECT 261.660 0.500 261.780 336.460 ;
        RECT 267.060 0.500 267.180 336.460 ;
        RECT 272.460 0.500 272.580 336.460 ;
        RECT 277.860 0.500 277.980 336.460 ;
        RECT 283.260 0.500 283.380 336.460 ;
        RECT 288.660 0.500 288.780 336.460 ;
        RECT 294.060 0.500 294.180 336.460 ;
        RECT 299.460 0.500 299.580 336.460 ;
        RECT 304.860 0.500 304.980 336.460 ;
        RECT 310.260 0.500 310.380 336.460 ;
        RECT 315.660 0.500 315.780 336.460 ;
        RECT 321.060 0.500 321.180 336.460 ;
        RECT 326.460 0.500 326.580 336.460 ;
        RECT 331.860 0.500 331.980 336.460 ;
        RECT 337.260 0.500 337.380 336.460 ;
        RECT 342.660 0.500 342.780 336.460 ;
        RECT 348.060 0.500 348.180 336.460 ;
        RECT 353.460 0.500 353.580 336.460 ;
        RECT 358.860 0.500 358.980 336.460 ;
        RECT 364.260 0.500 364.380 336.460 ;
        RECT 369.660 0.500 369.780 336.460 ;
        RECT 375.060 0.500 375.180 336.460 ;
        RECT 380.460 0.500 380.580 336.460 ;
        RECT 385.860 0.500 385.980 336.460 ;
        RECT 391.260 0.500 391.380 336.460 ;
        RECT 396.660 0.500 396.780 336.460 ;
        RECT 402.060 0.500 402.180 336.460 ;
        RECT 407.460 0.500 407.580 336.460 ;
        RECT 412.860 0.500 412.980 336.460 ;
        RECT 418.260 0.500 418.380 336.460 ;
        RECT 423.660 0.500 423.780 336.460 ;
        RECT 429.060 0.500 429.180 336.460 ;
    END
  END VDD
  PIN VSS
    DIRECTION INOUT ;
    USE GROUND ;
    PORT
      LAYER M5 ;
        RECT 2.652 0.500 2.772 336.460 ;
        RECT 8.052 0.500 8.172 336.460 ;
        RECT 13.452 0.500 13.572 336.460 ;
        RECT 18.852 0.500 18.972 336.460 ;
        RECT 24.252 0.500 24.372 336.460 ;
        RECT 29.652 0.500 29.772 336.460 ;
        RECT 35.052 0.500 35.172 336.460 ;
        RECT 40.452 0.500 40.572 336.460 ;
        RECT 45.852 0.500 45.972 336.460 ;
        RECT 51.252 0.500 51.372 336.460 ;
        RECT 56.652 0.500 56.772 336.460 ;
        RECT 62.052 0.500 62.172 336.460 ;
        RECT 67.452 0.500 67.572 336.460 ;
        RECT 72.852 0.500 72.972 336.460 ;
        RECT 78.252 0.500 78.372 336.460 ;
        RECT 83.652 0.500 83.772 336.460 ;
        RECT 89.052 0.500 89.172 336.460 ;
        RECT 94.452 0.500 94.572 336.460 ;
        RECT 99.852 0.500 99.972 336.460 ;
        RECT 105.252 0.500 105.372 336.460 ;
        RECT 110.652 0.500 110.772 336.460 ;
        RECT 116.052 0.500 116.172 336.460 ;
        RECT 121.452 0.500 121.572 336.460 ;
        RECT 126.852 0.500 126.972 336.460 ;
        RECT 132.252 0.500 132.372 336.460 ;
        RECT 137.652 0.500 137.772 336.460 ;
        RECT 143.052 0.500 143.172 336.460 ;
        RECT 148.452 0.500 148.572 336.460 ;
        RECT 153.852 0.500 153.972 336.460 ;
        RECT 159.252 0.500 159.372 336.460 ;
        RECT 164.652 0.500 164.772 336.460 ;
        RECT 170.052 0.500 170.172 336.460 ;
        RECT 175.452 0.500 175.572 336.460 ;
        RECT 180.852 0.500 180.972 336.460 ;
        RECT 186.252 0.500 186.372 336.460 ;
        RECT 191.652 0.500 191.772 336.460 ;
        RECT 197.052 0.500 197.172 336.460 ;
        RECT 202.452 0.500 202.572 336.460 ;
        RECT 207.852 0.500 207.972 336.460 ;
        RECT 213.252 0.500 213.372 336.460 ;
        RECT 218.652 0.500 218.772 336.460 ;
        RECT 224.052 0.500 224.172 336.460 ;
        RECT 229.452 0.500 229.572 336.460 ;
        RECT 234.852 0.500 234.972 336.460 ;
        RECT 240.252 0.500 240.372 336.460 ;
        RECT 245.652 0.500 245.772 336.460 ;
        RECT 251.052 0.500 251.172 336.460 ;
        RECT 256.452 0.500 256.572 336.460 ;
        RECT 261.852 0.500 261.972 336.460 ;
        RECT 267.252 0.500 267.372 336.460 ;
        RECT 272.652 0.500 272.772 336.460 ;
        RECT 278.052 0.500 278.172 336.460 ;
        RECT 283.452 0.500 283.572 336.460 ;
        RECT 288.852 0.500 288.972 336.460 ;
        RECT 294.252 0.500 294.372 336.460 ;
        RECT 299.652 0.500 299.772 336.460 ;
        RECT 305.052 0.500 305.172 336.460 ;
        RECT 310.452 0.500 310.572 336.460 ;
        RECT 315.852 0.500 315.972 336.460 ;
        RECT 321.252 0.500 321.372 336.460 ;
        RECT 326.652 0.500 326.772 336.460 ;
        RECT 332.052 0.500 332.172 336.460 ;
        RECT 337.452 0.500 337.572 336.460 ;
        RECT 342.852 0.500 342.972 336.460 ;
        RECT 348.252 0.500 348.372 336.460 ;
        RECT 353.652 0.500 353.772 336.460 ;
        RECT 359.052 0.500 359.172 336.460 ;
        RECT 364.452 0.500 364.572 336.460 ;
        RECT 369.852 0.500 369.972 336.460 ;
        RECT 375.252 0.500 375.372 336.460 ;
        RECT 380.652 0.500 380.772 336.460 ;
        RECT 386.052 0.500 386.172 336.460 ;
        RECT 391.452 0.500 391.572 336.460 ;
        RECT 396.852 0.500 396.972 336.460 ;
        RECT 402.252 0.500 402.372 336.460 ;
        RECT 407.652 0.500 407.772 336.460 ;
        RECT 413.052 0.500 413.172 336.460 ;
        RECT 418.452 0.500 418.572 336.460 ;
        RECT 423.852 0.500 423.972 336.460 ;
        RECT 429.252 0.500 429.372 336.460 ;
    END
  END VSS
  OBS
    LAYER M1 ;
      RECT 0.500 0.500 431.500 336.460 ;
    LAYER M2 ;
      RECT 0.500 0.500 431.500 336.460 ;
    LAYER M3 ;
      RECT 10.800 0.500 62.640 336.460 ;
      RECT 62.640 0.500 84.264 326.160 ;
      RECT 84.264 0.500 205.200 336.460 ;
      RECT 205.200 0.500 226.824 326.160 ;
      RECT 226.824 0.500 347.757 336.460 ;
      RECT 347.757 0.500 369.381 326.160 ;
      RECT 369.381 0.500 421.200 336.460 ;
    LAYER M4 ;
      RECT 10.800 0.500 62.640 336.460 ;
      RECT 62.640 0.500 84.264 326.160 ;
      RECT 84.264 0.500 205.200 336.460 ;
      RECT 205.200 0.500 226.824 326.160 ;
      RECT 226.824 0.500 347.757 336.460 ;
      RECT 347.757 0.500 369.381 326.160 ;
      RECT 369.381 0.500 421.200 336.460 ;
    LAYER M5 ;
      RECT 10.800 0.900 13.260 336.060 ;
      RECT 13.380 0.900 13.452 336.060 ;
      RECT 13.572 0.900 18.660 336.060 ;
      RECT 18.780 0.900 18.852 336.060 ;
      RECT 18.972 0.900 24.060 336.060 ;
      RECT 24.180 0.900 24.252 336.060 ;
      RECT 24.372 0.900 29.460 336.060 ;
      RECT 29.580 0.900 29.652 336.060 ;
      RECT 29.772 0.900 34.860 336.060 ;
      RECT 34.980 0.900 35.052 336.060 ;
      RECT 35.172 0.900 40.260 336.060 ;
      RECT 40.380 0.900 40.452 336.060 ;
      RECT 40.572 0.900 45.660 336.060 ;
      RECT 45.780 0.900 45.852 336.060 ;
      RECT 45.972 0.900 51.060 336.060 ;
      RECT 51.180 0.900 51.252 336.060 ;
      RECT 51.372 0.900 56.460 336.060 ;
      RECT 56.580 0.900 56.652 336.060 ;
      RECT 56.772 0.900 61.860 336.060 ;
      RECT 61.980 0.900 62.052 336.060 ;
      RECT 62.172 0.900 62.640 336.060 ;
      RECT 62.640 0.900 67.260 326.160 ;
      RECT 67.380 0.900 67.452 326.160 ;
      RECT 67.572 0.900 72.660 326.160 ;
      RECT 72.780 0.900 72.852 326.160 ;
      RECT 72.972 0.900 78.060 326.160 ;
      RECT 78.180 0.900 78.252 326.160 ;
      RECT 78.372 0.900 83.460 326.160 ;
      RECT 83.580 0.900 83.652 326.160 ;
      RECT 83.772 0.900 84.264 326.160 ;
      RECT 84.264 0.900 88.860 336.060 ;
      RECT 88.980 0.900 89.052 336.060 ;
      RECT 89.172 0.900 94.260 336.060 ;
      RECT 94.380 0.900 94.452 336.060 ;
      RECT 94.572 0.900 99.660 336.060 ;
      RECT 99.780 0.900 99.852 336.060 ;
      RECT 99.972 0.900 105.060 336.060 ;
      RECT 105.180 0.900 105.252 336.060 ;
      RECT 105.372 0.900 110.460 336.060 ;
      RECT 110.580 0.900 110.652 336.060 ;
      RECT 110.772 0.900 115.860 336.060 ;
      RECT 115.980 0.900 116.052 336.060 ;
      RECT 116.172 0.900 121.260 336.060 ;
      RECT 121.380 0.900 121.452 336.060 ;
      RECT 121.572 0.900 126.660 336.060 ;
      RECT 126.780 0.900 126.852 336.060 ;
      RECT 126.972 0.900 132.060 336.060 ;
      RECT 132.180 0.900 132.252 336.060 ;
      RECT 132.372 0.900 137.460 336.060 ;
      RECT 137.580 0.900 137.652 336.060 ;
      RECT 137.772 0.900 142.860 336.060 ;
      RECT 142.980 0.900 143.052 336.060 ;
      RECT 143.172 0.900 148.260 336.060 ;
      RECT 148.380 0.900 148.452 336.060 ;
      RECT 148.572 0.900 153.660 336.060 ;
      RECT 153.780 0.900 153.852 336.060 ;
      RECT 153.972 0.900 159.060 336.060 ;
      RECT 159.180 0.900 159.252 336.060 ;
      RECT 159.372 0.900 164.460 336.060 ;
      RECT 164.580 0.900 164.652 336.060 ;
      RECT 164.772 0.900 169.860 336.060 ;
      RECT 169.980 0.900 170.052 336.060 ;
      RECT 170.172 0.900 175.260 336.060 ;
      RECT 175.380 0.900 175.452 336.060 ;
      RECT 175.572 0.900 180.660 336.060 ;
      RECT 180.780 0.900 180.852 336.060 ;
      RECT 180.972 0.900 186.060 336.060 ;
      RECT 186.180 0.900 186.252 336.060 ;
      RECT 186.372 0.900 191.460 336.060 ;
      RECT 191.580 0.900 191.652 336.060 ;
      RECT 191.772 0.900 196.860 336.060 ;
      RECT 196.980 0.900 197.052 336.060 ;
      RECT 197.172 0.900 202.260 336.060 ;
      RECT 202.380 0.900 202.452 336.060 ;
      RECT 202.572 0.900 205.200 336.060 ;
      RECT 205.200 0.900 207.660 326.160 ;
      RECT 207.780 0.900 207.852 326.160 ;
      RECT 207.972 0.900 213.060 326.160 ;
      RECT 213.180 0.900 213.252 326.160 ;
      RECT 213.372 0.900 218.460 326.160 ;
      RECT 218.580 0.900 218.652 326.160 ;
      RECT 218.772 0.900 223.860 326.160 ;
      RECT 223.980 0.900 224.052 326.160 ;
      RECT 224.172 0.900 226.824 326.160 ;
      RECT 226.824 0.900 229.260 336.060 ;
      RECT 229.380 0.900 229.452 336.060 ;
      RECT 229.572 0.900 234.660 336.060 ;
      RECT 234.780 0.900 234.852 336.060 ;
      RECT 234.972 0.900 240.060 336.060 ;
      RECT 240.180 0.900 240.252 336.060 ;
      RECT 240.372 0.900 245.460 336.060 ;
      RECT 245.580 0.900 245.652 336.060 ;
      RECT 245.772 0.900 250.860 336.060 ;
      RECT 250.980 0.900 251.052 336.060 ;
      RECT 251.172 0.900 256.260 336.060 ;
      RECT 256.380 0.900 256.452 336.060 ;
      RECT 256.572 0.900 261.660 336.060 ;
      RECT 261.780 0.900 261.852 336.060 ;
      RECT 261.972 0.900 267.060 336.060 ;
      RECT 267.180 0.900 267.252 336.060 ;
      RECT 267.372 0.900 272.460 336.060 ;
      RECT 272.580 0.900 272.652 336.060 ;
      RECT 272.772 0.900 277.860 336.060 ;
      RECT 277.980 0.900 278.052 336.060 ;
      RECT 278.172 0.900 283.260 336.060 ;
      RECT 283.380 0.900 283.452 336.060 ;
      RECT 283.572 0.900 288.660 336.060 ;
      RECT 288.780 0.900 288.852 336.060 ;
      RECT 288.972 0.900 294.060 336.060 ;
      RECT 294.180 0.900 294.252 336.060 ;
      RECT 294.372 0.900 299.460 336.060 ;
      RECT 299.580 0.900 299.652 336.060 ;
      RECT 299.772 0.900 304.860 336.060 ;
      RECT 304.980 0.900 305.052 336.060 ;
      RECT 305.172 0.900 310.260 336.060 ;
      RECT 310.380 0.900 310.452 336.060 ;
      RECT 310.572 0.900 315.660 336.060 ;
      RECT 315.780 0.900 315.852 336.060 ;
      RECT 315.972 0.900 321.060 336.060 ;
      RECT 321.180 0.900 321.252 336.060 ;
      RECT 321.372 0.900 326.460 336.060 ;
      RECT 326.580 0.900 326.652 336.060 ;
      RECT 326.772 0.900 331.860 336.060 ;
      RECT 331.980 0.900 332.052 336.060 ;
      RECT 332.172 0.900 337.260 336.060 ;
      RECT 337.380 0.900 337.452 336.060 ;
      RECT 337.572 0.900 342.660 336.060 ;
      RECT 342.780 0.900 342.852 336.060 ;
      RECT 342.972 0.900 347.757 336.060 ;
      RECT 347.757 0.900 348.060 326.160 ;
      RECT 348.180 0.900 348.252 326.160 ;
      RECT 348.372 0.900 353.460 326.160 ;
      RECT 353.580 0.900 353.652 326.160 ;
      RECT 353.772 0.900 358.860 326.160 ;
      RECT 358.980 0.900 359.052 326.160 ;
      RECT 359.172 0.900 364.260 326.160 ;
      RECT 364.380 0.900 364.452 326.160 ;
      RECT 364.572 0.900 369.381 326.160 ;
      RECT 369.381 0.900 369.660 336.060 ;
      RECT 369.780 0.900 369.852 336.060 ;
      RECT 369.972 0.900 375.060 336.060 ;
      RECT 375.180 0.900 375.252 336.060 ;
      RECT 375.372 0.900 380.460 336.060 ;
      RECT 380.580 0.900 380.652 336.060 ;
      RECT 380.772 0.900 385.860 336.060 ;
      RECT 385.980 0.900 386.052 336.060 ;
      RECT 386.172 0.900 391.260 336.060 ;
      RECT 391.380 0.900 391.452 336.060 ;
      RECT 391.572 0.900 396.660 336.060 ;
      RECT 396.780 0.900 396.852 336.060 ;
      RECT 396.972 0.900 402.060 336.060 ;
      RECT 402.180 0.900 402.252 336.060 ;
      RECT 402.372 0.900 407.460 336.060 ;
      RECT 407.580 0.900 407.652 336.060 ;
      RECT 407.772 0.900 412.860 336.060 ;
      RECT 412.980 0.900 413.052 336.060 ;
      RECT 413.172 0.900 418.260 336.060 ;
      RECT 418.380 0.900 418.452 336.060 ;
      RECT 418.572 0.900 421.200 336.060 ;
  END
END dsfd_coll_lane_w_ntf
END LIBRARY
